VERSION 5.8 ;
BUSBITCHARS "[]" ;
DIVIDERCHAR "/" ;
UNITS
    DATABASE MICRONS 1000 ;
END UNITS

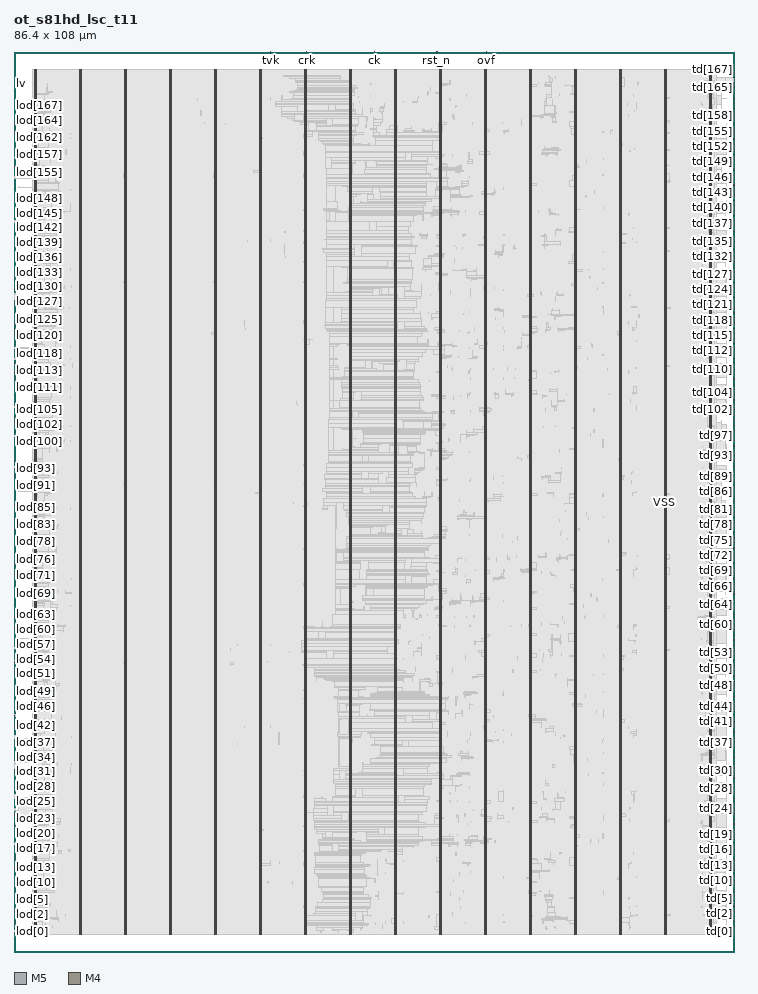
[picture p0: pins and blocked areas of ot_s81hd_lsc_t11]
MACRO ot_s81hd_lsc_t11
  FOREIGN ot_s81hd_lsc_t11 0 0 ;
  CLASS BLOCK ;
  SIZE 86.4 BY 108 ;
  PIN ck
    DIRECTION INPUT ;
    USE SIGNAL ;
    PORT
      LAYER M5 ;
        RECT  43.2 107.916 43.224 108 ;
    END
  END ck
  PIN crk
    DIRECTION INPUT ;
    USE SIGNAL ;
    PORT
      LAYER M5 ;
        RECT  35.088 107.916 35.112 108 ;
    END
  END crk
  PIN lod[0]
    DIRECTION OUTPUT ;
    USE SIGNAL ;
    PORT
      LAYER M4 ;
        RECT  0 2.448 0.084 2.472 ;
    END
  END lod[0]
  PIN lod[100]
    DIRECTION OUTPUT ;
    USE SIGNAL ;
    PORT
      LAYER M4 ;
        RECT  0 61.248 0.084 61.272 ;
    END
  END lod[100]
  PIN lod[101]
    DIRECTION OUTPUT ;
    USE SIGNAL ;
    PORT
      LAYER M4 ;
        RECT  0 61.824 0.084 61.848 ;
    END
  END lod[101]
  PIN lod[102]
    DIRECTION OUTPUT ;
    USE SIGNAL ;
    PORT
      LAYER M4 ;
        RECT  0 62.4 0.084 62.424 ;
    END
  END lod[102]
  PIN lod[103]
    DIRECTION OUTPUT ;
    USE SIGNAL ;
    PORT
      LAYER M4 ;
        RECT  0 62.976 0.084 63 ;
    END
  END lod[103]
  PIN lod[104]
    DIRECTION OUTPUT ;
    USE SIGNAL ;
    PORT
      LAYER M4 ;
        RECT  0 63.6 0.084 63.624 ;
    END
  END lod[104]
  PIN lod[105]
    DIRECTION OUTPUT ;
    USE SIGNAL ;
    PORT
      LAYER M4 ;
        RECT  0 64.176 0.084 64.2 ;
    END
  END lod[105]
  PIN lod[106]
    DIRECTION OUTPUT ;
    USE SIGNAL ;
    PORT
      LAYER M4 ;
        RECT  0 64.752 0.084 64.776 ;
    END
  END lod[106]
  PIN lod[107]
    DIRECTION OUTPUT ;
    USE SIGNAL ;
    PORT
      LAYER M4 ;
        RECT  0 65.328 0.084 65.352 ;
    END
  END lod[107]
  PIN lod[108]
    DIRECTION OUTPUT ;
    USE SIGNAL ;
    PORT
      LAYER M4 ;
        RECT  0 65.952 0.084 65.976 ;
    END
  END lod[108]
  PIN lod[109]
    DIRECTION OUTPUT ;
    USE SIGNAL ;
    PORT
      LAYER M4 ;
        RECT  0 66.528 0.084 66.552 ;
    END
  END lod[109]
  PIN lod[10]
    DIRECTION OUTPUT ;
    USE SIGNAL ;
    PORT
      LAYER M4 ;
        RECT  0 8.304 0.084 8.328 ;
    END
  END lod[10]
  PIN lod[110]
    DIRECTION OUTPUT ;
    USE SIGNAL ;
    PORT
      LAYER M4 ;
        RECT  0 67.104 0.084 67.128 ;
    END
  END lod[110]
  PIN lod[111]
    DIRECTION OUTPUT ;
    USE SIGNAL ;
    PORT
      LAYER M4 ;
        RECT  0 67.68 0.084 67.704 ;
    END
  END lod[111]
  PIN lod[112]
    DIRECTION OUTPUT ;
    USE SIGNAL ;
    PORT
      LAYER M4 ;
        RECT  0 68.304 0.084 68.328 ;
    END
  END lod[112]
  PIN lod[113]
    DIRECTION OUTPUT ;
    USE SIGNAL ;
    PORT
      LAYER M4 ;
        RECT  0 68.88 0.084 68.904 ;
    END
  END lod[113]
  PIN lod[114]
    DIRECTION OUTPUT ;
    USE SIGNAL ;
    PORT
      LAYER M4 ;
        RECT  0 69.456 0.084 69.48 ;
    END
  END lod[114]
  PIN lod[115]
    DIRECTION OUTPUT ;
    USE SIGNAL ;
    PORT
      LAYER M4 ;
        RECT  0 70.032 0.084 70.056 ;
    END
  END lod[115]
  PIN lod[116]
    DIRECTION OUTPUT ;
    USE SIGNAL ;
    PORT
      LAYER M4 ;
        RECT  0 70.656 0.084 70.68 ;
    END
  END lod[116]
  PIN lod[117]
    DIRECTION OUTPUT ;
    USE SIGNAL ;
    PORT
      LAYER M4 ;
        RECT  0 71.232 0.084 71.256 ;
    END
  END lod[117]
  PIN lod[118]
    DIRECTION OUTPUT ;
    USE SIGNAL ;
    PORT
      LAYER M4 ;
        RECT  0 71.808 0.084 71.832 ;
    END
  END lod[118]
  PIN lod[119]
    DIRECTION OUTPUT ;
    USE SIGNAL ;
    PORT
      LAYER M4 ;
        RECT  0 72.384 0.084 72.408 ;
    END
  END lod[119]
  PIN lod[11]
    DIRECTION OUTPUT ;
    USE SIGNAL ;
    PORT
      LAYER M4 ;
        RECT  0 8.928 0.084 8.952 ;
    END
  END lod[11]
  PIN lod[120]
    DIRECTION OUTPUT ;
    USE SIGNAL ;
    PORT
      LAYER M4 ;
        RECT  0 73.008 0.084 73.032 ;
    END
  END lod[120]
  PIN lod[121]
    DIRECTION OUTPUT ;
    USE SIGNAL ;
    PORT
      LAYER M4 ;
        RECT  0 73.584 0.084 73.608 ;
    END
  END lod[121]
  PIN lod[122]
    DIRECTION OUTPUT ;
    USE SIGNAL ;
    PORT
      LAYER M4 ;
        RECT  0 74.16 0.084 74.184 ;
    END
  END lod[122]
  PIN lod[123]
    DIRECTION OUTPUT ;
    USE SIGNAL ;
    PORT
      LAYER M4 ;
        RECT  0 74.736 0.084 74.76 ;
    END
  END lod[123]
  PIN lod[124]
    DIRECTION OUTPUT ;
    USE SIGNAL ;
    PORT
      LAYER M4 ;
        RECT  0 75.36 0.084 75.384 ;
    END
  END lod[124]
  PIN lod[125]
    DIRECTION OUTPUT ;
    USE SIGNAL ;
    PORT
      LAYER M4 ;
        RECT  0 75.936 0.084 75.96 ;
    END
  END lod[125]
  PIN lod[126]
    DIRECTION OUTPUT ;
    USE SIGNAL ;
    PORT
      LAYER M4 ;
        RECT  0 76.512 0.084 76.536 ;
    END
  END lod[126]
  PIN lod[127]
    DIRECTION OUTPUT ;
    USE SIGNAL ;
    PORT
      LAYER M4 ;
        RECT  0 77.088 0.084 77.112 ;
    END
  END lod[127]
  PIN lod[128]
    DIRECTION OUTPUT ;
    USE SIGNAL ;
    PORT
      LAYER M4 ;
        RECT  0 77.712 0.084 77.736 ;
    END
  END lod[128]
  PIN lod[129]
    DIRECTION OUTPUT ;
    USE SIGNAL ;
    PORT
      LAYER M4 ;
        RECT  0 78.288 0.084 78.312 ;
    END
  END lod[129]
  PIN lod[12]
    DIRECTION OUTPUT ;
    USE SIGNAL ;
    PORT
      LAYER M4 ;
        RECT  0 9.504 0.084 9.528 ;
    END
  END lod[12]
  PIN lod[130]
    DIRECTION OUTPUT ;
    USE SIGNAL ;
    PORT
      LAYER M4 ;
        RECT  0 78.864 0.084 78.888 ;
    END
  END lod[130]
  PIN lod[131]
    DIRECTION OUTPUT ;
    USE SIGNAL ;
    PORT
      LAYER M4 ;
        RECT  0 79.44 0.084 79.464 ;
    END
  END lod[131]
  PIN lod[132]
    DIRECTION OUTPUT ;
    USE SIGNAL ;
    PORT
      LAYER M4 ;
        RECT  0 80.064 0.084 80.088 ;
    END
  END lod[132]
  PIN lod[133]
    DIRECTION OUTPUT ;
    USE SIGNAL ;
    PORT
      LAYER M4 ;
        RECT  0 80.64 0.084 80.664 ;
    END
  END lod[133]
  PIN lod[134]
    DIRECTION OUTPUT ;
    USE SIGNAL ;
    PORT
      LAYER M4 ;
        RECT  0 81.216 0.084 81.24 ;
    END
  END lod[134]
  PIN lod[135]
    DIRECTION OUTPUT ;
    USE SIGNAL ;
    PORT
      LAYER M4 ;
        RECT  0 81.792 0.084 81.816 ;
    END
  END lod[135]
  PIN lod[136]
    DIRECTION OUTPUT ;
    USE SIGNAL ;
    PORT
      LAYER M4 ;
        RECT  0 82.416 0.084 82.44 ;
    END
  END lod[136]
  PIN lod[137]
    DIRECTION OUTPUT ;
    USE SIGNAL ;
    PORT
      LAYER M4 ;
        RECT  0 82.992 0.084 83.016 ;
    END
  END lod[137]
  PIN lod[138]
    DIRECTION OUTPUT ;
    USE SIGNAL ;
    PORT
      LAYER M4 ;
        RECT  0 83.568 0.084 83.592 ;
    END
  END lod[138]
  PIN lod[139]
    DIRECTION OUTPUT ;
    USE SIGNAL ;
    PORT
      LAYER M4 ;
        RECT  0 84.144 0.084 84.168 ;
    END
  END lod[139]
  PIN lod[13]
    DIRECTION OUTPUT ;
    USE SIGNAL ;
    PORT
      LAYER M4 ;
        RECT  0 10.08 0.084 10.104 ;
    END
  END lod[13]
  PIN lod[140]
    DIRECTION OUTPUT ;
    USE SIGNAL ;
    PORT
      LAYER M4 ;
        RECT  0 84.768 0.084 84.792 ;
    END
  END lod[140]
  PIN lod[141]
    DIRECTION OUTPUT ;
    USE SIGNAL ;
    PORT
      LAYER M4 ;
        RECT  0 85.344 0.084 85.368 ;
    END
  END lod[141]
  PIN lod[142]
    DIRECTION OUTPUT ;
    USE SIGNAL ;
    PORT
      LAYER M4 ;
        RECT  0 85.92 0.084 85.944 ;
    END
  END lod[142]
  PIN lod[143]
    DIRECTION OUTPUT ;
    USE SIGNAL ;
    PORT
      LAYER M4 ;
        RECT  0 86.496 0.084 86.52 ;
    END
  END lod[143]
  PIN lod[144]
    DIRECTION OUTPUT ;
    USE SIGNAL ;
    PORT
      LAYER M4 ;
        RECT  0 87.12 0.084 87.144 ;
    END
  END lod[144]
  PIN lod[145]
    DIRECTION OUTPUT ;
    USE SIGNAL ;
    PORT
      LAYER M4 ;
        RECT  0 87.696 0.084 87.72 ;
    END
  END lod[145]
  PIN lod[146]
    DIRECTION OUTPUT ;
    USE SIGNAL ;
    PORT
      LAYER M4 ;
        RECT  0 88.272 0.084 88.296 ;
    END
  END lod[146]
  PIN lod[147]
    DIRECTION OUTPUT ;
    USE SIGNAL ;
    PORT
      LAYER M4 ;
        RECT  0 88.848 0.084 88.872 ;
    END
  END lod[147]
  PIN lod[148]
    DIRECTION OUTPUT ;
    USE SIGNAL ;
    PORT
      LAYER M4 ;
        RECT  0 89.472 0.084 89.496 ;
    END
  END lod[148]
  PIN lod[149]
    DIRECTION OUTPUT ;
    USE SIGNAL ;
    PORT
      LAYER M4 ;
        RECT  0 90.048 0.084 90.072 ;
    END
  END lod[149]
  PIN lod[14]
    DIRECTION OUTPUT ;
    USE SIGNAL ;
    PORT
      LAYER M4 ;
        RECT  0 10.656 0.084 10.68 ;
    END
  END lod[14]
  PIN lod[150]
    DIRECTION OUTPUT ;
    USE SIGNAL ;
    PORT
      LAYER M4 ;
        RECT  0 90.624 0.084 90.648 ;
    END
  END lod[150]
  PIN lod[151]
    DIRECTION OUTPUT ;
    USE SIGNAL ;
    PORT
      LAYER M4 ;
        RECT  0 91.2 0.084 91.224 ;
    END
  END lod[151]
  PIN lod[152]
    DIRECTION OUTPUT ;
    USE SIGNAL ;
    PORT
      LAYER M4 ;
        RECT  0 91.824 0.084 91.848 ;
    END
  END lod[152]
  PIN lod[153]
    DIRECTION OUTPUT ;
    USE SIGNAL ;
    PORT
      LAYER M4 ;
        RECT  0 92.4 0.084 92.424 ;
    END
  END lod[153]
  PIN lod[154]
    DIRECTION OUTPUT ;
    USE SIGNAL ;
    PORT
      LAYER M4 ;
        RECT  0 92.976 0.084 93 ;
    END
  END lod[154]
  PIN lod[155]
    DIRECTION OUTPUT ;
    USE SIGNAL ;
    PORT
      LAYER M4 ;
        RECT  0 93.552 0.084 93.576 ;
    END
  END lod[155]
  PIN lod[156]
    DIRECTION OUTPUT ;
    USE SIGNAL ;
    PORT
      LAYER M4 ;
        RECT  0 94.176 0.084 94.2 ;
    END
  END lod[156]
  PIN lod[157]
    DIRECTION OUTPUT ;
    USE SIGNAL ;
    PORT
      LAYER M4 ;
        RECT  0 94.752 0.084 94.776 ;
    END
  END lod[157]
  PIN lod[158]
    DIRECTION OUTPUT ;
    USE SIGNAL ;
    PORT
      LAYER M4 ;
        RECT  0 95.328 0.084 95.352 ;
    END
  END lod[158]
  PIN lod[159]
    DIRECTION OUTPUT ;
    USE SIGNAL ;
    PORT
      LAYER M4 ;
        RECT  0 95.904 0.084 95.928 ;
    END
  END lod[159]
  PIN lod[15]
    DIRECTION OUTPUT ;
    USE SIGNAL ;
    PORT
      LAYER M4 ;
        RECT  0 11.28 0.084 11.304 ;
    END
  END lod[15]
  PIN lod[160]
    DIRECTION OUTPUT ;
    USE SIGNAL ;
    PORT
      LAYER M4 ;
        RECT  0 96.528 0.084 96.552 ;
    END
  END lod[160]
  PIN lod[161]
    DIRECTION OUTPUT ;
    USE SIGNAL ;
    PORT
      LAYER M4 ;
        RECT  0 97.104 0.084 97.128 ;
    END
  END lod[161]
  PIN lod[162]
    DIRECTION OUTPUT ;
    USE SIGNAL ;
    PORT
      LAYER M4 ;
        RECT  0 97.68 0.084 97.704 ;
    END
  END lod[162]
  PIN lod[163]
    DIRECTION OUTPUT ;
    USE SIGNAL ;
    PORT
      LAYER M4 ;
        RECT  0 98.256 0.084 98.28 ;
    END
  END lod[163]
  PIN lod[164]
    DIRECTION OUTPUT ;
    USE SIGNAL ;
    PORT
      LAYER M4 ;
        RECT  0 98.88 0.084 98.904 ;
    END
  END lod[164]
  PIN lod[165]
    DIRECTION OUTPUT ;
    USE SIGNAL ;
    PORT
      LAYER M4 ;
        RECT  0 99.456 0.084 99.48 ;
    END
  END lod[165]
  PIN lod[166]
    DIRECTION OUTPUT ;
    USE SIGNAL ;
    PORT
      LAYER M4 ;
        RECT  0 100.032 0.084 100.056 ;
    END
  END lod[166]
  PIN lod[167]
    DIRECTION OUTPUT ;
    USE SIGNAL ;
    PORT
      LAYER M4 ;
        RECT  0 100.608 0.084 100.632 ;
    END
  END lod[167]
  PIN lod[168]
    DIRECTION OUTPUT ;
    USE SIGNAL ;
    PORT
      LAYER M4 ;
        RECT  0 101.232 0.084 101.256 ;
    END
  END lod[168]
  PIN lod[16]
    DIRECTION OUTPUT ;
    USE SIGNAL ;
    PORT
      LAYER M4 ;
        RECT  0 11.856 0.084 11.88 ;
    END
  END lod[16]
  PIN lod[17]
    DIRECTION OUTPUT ;
    USE SIGNAL ;
    PORT
      LAYER M4 ;
        RECT  0 12.432 0.084 12.456 ;
    END
  END lod[17]
  PIN lod[18]
    DIRECTION OUTPUT ;
    USE SIGNAL ;
    PORT
      LAYER M4 ;
        RECT  0 13.008 0.084 13.032 ;
    END
  END lod[18]
  PIN lod[19]
    DIRECTION OUTPUT ;
    USE SIGNAL ;
    PORT
      LAYER M4 ;
        RECT  0 13.632 0.084 13.656 ;
    END
  END lod[19]
  PIN lod[1]
    DIRECTION OUTPUT ;
    USE SIGNAL ;
    PORT
      LAYER M4 ;
        RECT  0 3.024 0.084 3.048 ;
    END
  END lod[1]
  PIN lod[20]
    DIRECTION OUTPUT ;
    USE SIGNAL ;
    PORT
      LAYER M4 ;
        RECT  0 14.208 0.084 14.232 ;
    END
  END lod[20]
  PIN lod[21]
    DIRECTION OUTPUT ;
    USE SIGNAL ;
    PORT
      LAYER M4 ;
        RECT  0 14.784 0.084 14.808 ;
    END
  END lod[21]
  PIN lod[22]
    DIRECTION OUTPUT ;
    USE SIGNAL ;
    PORT
      LAYER M4 ;
        RECT  0 15.36 0.084 15.384 ;
    END
  END lod[22]
  PIN lod[23]
    DIRECTION OUTPUT ;
    USE SIGNAL ;
    PORT
      LAYER M4 ;
        RECT  0 15.984 0.084 16.008 ;
    END
  END lod[23]
  PIN lod[24]
    DIRECTION OUTPUT ;
    USE SIGNAL ;
    PORT
      LAYER M4 ;
        RECT  0 16.56 0.084 16.584 ;
    END
  END lod[24]
  PIN lod[25]
    DIRECTION OUTPUT ;
    USE SIGNAL ;
    PORT
      LAYER M4 ;
        RECT  0 17.136 0.084 17.16 ;
    END
  END lod[25]
  PIN lod[26]
    DIRECTION OUTPUT ;
    USE SIGNAL ;
    PORT
      LAYER M4 ;
        RECT  0 17.712 0.084 17.736 ;
    END
  END lod[26]
  PIN lod[27]
    DIRECTION OUTPUT ;
    USE SIGNAL ;
    PORT
      LAYER M4 ;
        RECT  0 18.336 0.084 18.36 ;
    END
  END lod[27]
  PIN lod[28]
    DIRECTION OUTPUT ;
    USE SIGNAL ;
    PORT
      LAYER M4 ;
        RECT  0 18.912 0.084 18.936 ;
    END
  END lod[28]
  PIN lod[29]
    DIRECTION OUTPUT ;
    USE SIGNAL ;
    PORT
      LAYER M4 ;
        RECT  0 19.488 0.084 19.512 ;
    END
  END lod[29]
  PIN lod[2]
    DIRECTION OUTPUT ;
    USE SIGNAL ;
    PORT
      LAYER M4 ;
        RECT  0 3.6 0.084 3.624 ;
    END
  END lod[2]
  PIN lod[30]
    DIRECTION OUTPUT ;
    USE SIGNAL ;
    PORT
      LAYER M4 ;
        RECT  0 20.064 0.084 20.088 ;
    END
  END lod[30]
  PIN lod[31]
    DIRECTION OUTPUT ;
    USE SIGNAL ;
    PORT
      LAYER M4 ;
        RECT  0 20.688 0.084 20.712 ;
    END
  END lod[31]
  PIN lod[32]
    DIRECTION OUTPUT ;
    USE SIGNAL ;
    PORT
      LAYER M4 ;
        RECT  0 21.264 0.084 21.288 ;
    END
  END lod[32]
  PIN lod[33]
    DIRECTION OUTPUT ;
    USE SIGNAL ;
    PORT
      LAYER M4 ;
        RECT  0 21.84 0.084 21.864 ;
    END
  END lod[33]
  PIN lod[34]
    DIRECTION OUTPUT ;
    USE SIGNAL ;
    PORT
      LAYER M4 ;
        RECT  0 22.416 0.084 22.44 ;
    END
  END lod[34]
  PIN lod[35]
    DIRECTION OUTPUT ;
    USE SIGNAL ;
    PORT
      LAYER M4 ;
        RECT  0 23.04 0.084 23.064 ;
    END
  END lod[35]
  PIN lod[36]
    DIRECTION OUTPUT ;
    USE SIGNAL ;
    PORT
      LAYER M4 ;
        RECT  0 23.616 0.084 23.64 ;
    END
  END lod[36]
  PIN lod[37]
    DIRECTION OUTPUT ;
    USE SIGNAL ;
    PORT
      LAYER M4 ;
        RECT  0 24.192 0.084 24.216 ;
    END
  END lod[37]
  PIN lod[38]
    DIRECTION OUTPUT ;
    USE SIGNAL ;
    PORT
      LAYER M4 ;
        RECT  0 24.768 0.084 24.792 ;
    END
  END lod[38]
  PIN lod[39]
    DIRECTION OUTPUT ;
    USE SIGNAL ;
    PORT
      LAYER M4 ;
        RECT  0 25.392 0.084 25.416 ;
    END
  END lod[39]
  PIN lod[3]
    DIRECTION OUTPUT ;
    USE SIGNAL ;
    PORT
      LAYER M4 ;
        RECT  0 4.224 0.084 4.248 ;
    END
  END lod[3]
  PIN lod[40]
    DIRECTION OUTPUT ;
    USE SIGNAL ;
    PORT
      LAYER M4 ;
        RECT  0 25.968 0.084 25.992 ;
    END
  END lod[40]
  PIN lod[41]
    DIRECTION OUTPUT ;
    USE SIGNAL ;
    PORT
      LAYER M4 ;
        RECT  0 26.544 0.084 26.568 ;
    END
  END lod[41]
  PIN lod[42]
    DIRECTION OUTPUT ;
    USE SIGNAL ;
    PORT
      LAYER M4 ;
        RECT  0 27.12 0.084 27.144 ;
    END
  END lod[42]
  PIN lod[43]
    DIRECTION OUTPUT ;
    USE SIGNAL ;
    PORT
      LAYER M4 ;
        RECT  0 27.744 0.084 27.768 ;
    END
  END lod[43]
  PIN lod[44]
    DIRECTION OUTPUT ;
    USE SIGNAL ;
    PORT
      LAYER M4 ;
        RECT  0 28.32 0.084 28.344 ;
    END
  END lod[44]
  PIN lod[45]
    DIRECTION OUTPUT ;
    USE SIGNAL ;
    PORT
      LAYER M4 ;
        RECT  0 28.896 0.084 28.92 ;
    END
  END lod[45]
  PIN lod[46]
    DIRECTION OUTPUT ;
    USE SIGNAL ;
    PORT
      LAYER M4 ;
        RECT  0 29.472 0.084 29.496 ;
    END
  END lod[46]
  PIN lod[47]
    DIRECTION OUTPUT ;
    USE SIGNAL ;
    PORT
      LAYER M4 ;
        RECT  0 30.096 0.084 30.12 ;
    END
  END lod[47]
  PIN lod[48]
    DIRECTION OUTPUT ;
    USE SIGNAL ;
    PORT
      LAYER M4 ;
        RECT  0 30.672 0.084 30.696 ;
    END
  END lod[48]
  PIN lod[49]
    DIRECTION OUTPUT ;
    USE SIGNAL ;
    PORT
      LAYER M4 ;
        RECT  0 31.248 0.084 31.272 ;
    END
  END lod[49]
  PIN lod[4]
    DIRECTION OUTPUT ;
    USE SIGNAL ;
    PORT
      LAYER M4 ;
        RECT  0 4.8 0.084 4.824 ;
    END
  END lod[4]
  PIN lod[50]
    DIRECTION OUTPUT ;
    USE SIGNAL ;
    PORT
      LAYER M4 ;
        RECT  0 31.824 0.084 31.848 ;
    END
  END lod[50]
  PIN lod[51]
    DIRECTION OUTPUT ;
    USE SIGNAL ;
    PORT
      LAYER M4 ;
        RECT  0 32.448 0.084 32.472 ;
    END
  END lod[51]
  PIN lod[52]
    DIRECTION OUTPUT ;
    USE SIGNAL ;
    PORT
      LAYER M4 ;
        RECT  0 33.024 0.084 33.048 ;
    END
  END lod[52]
  PIN lod[53]
    DIRECTION OUTPUT ;
    USE SIGNAL ;
    PORT
      LAYER M4 ;
        RECT  0 33.6 0.084 33.624 ;
    END
  END lod[53]
  PIN lod[54]
    DIRECTION OUTPUT ;
    USE SIGNAL ;
    PORT
      LAYER M4 ;
        RECT  0 34.176 0.084 34.2 ;
    END
  END lod[54]
  PIN lod[55]
    DIRECTION OUTPUT ;
    USE SIGNAL ;
    PORT
      LAYER M4 ;
        RECT  0 34.8 0.084 34.824 ;
    END
  END lod[55]
  PIN lod[56]
    DIRECTION OUTPUT ;
    USE SIGNAL ;
    PORT
      LAYER M4 ;
        RECT  0 35.376 0.084 35.4 ;
    END
  END lod[56]
  PIN lod[57]
    DIRECTION OUTPUT ;
    USE SIGNAL ;
    PORT
      LAYER M4 ;
        RECT  0 35.952 0.084 35.976 ;
    END
  END lod[57]
  PIN lod[58]
    DIRECTION OUTPUT ;
    USE SIGNAL ;
    PORT
      LAYER M4 ;
        RECT  0 36.528 0.084 36.552 ;
    END
  END lod[58]
  PIN lod[59]
    DIRECTION OUTPUT ;
    USE SIGNAL ;
    PORT
      LAYER M4 ;
        RECT  0 37.152 0.084 37.176 ;
    END
  END lod[59]
  PIN lod[5]
    DIRECTION OUTPUT ;
    USE SIGNAL ;
    PORT
      LAYER M4 ;
        RECT  0 5.376 0.084 5.4 ;
    END
  END lod[5]
  PIN lod[60]
    DIRECTION OUTPUT ;
    USE SIGNAL ;
    PORT
      LAYER M4 ;
        RECT  0 37.728 0.084 37.752 ;
    END
  END lod[60]
  PIN lod[61]
    DIRECTION OUTPUT ;
    USE SIGNAL ;
    PORT
      LAYER M4 ;
        RECT  0 38.304 0.084 38.328 ;
    END
  END lod[61]
  PIN lod[62]
    DIRECTION OUTPUT ;
    USE SIGNAL ;
    PORT
      LAYER M4 ;
        RECT  0 38.88 0.084 38.904 ;
    END
  END lod[62]
  PIN lod[63]
    DIRECTION OUTPUT ;
    USE SIGNAL ;
    PORT
      LAYER M4 ;
        RECT  0 39.504 0.084 39.528 ;
    END
  END lod[63]
  PIN lod[64]
    DIRECTION OUTPUT ;
    USE SIGNAL ;
    PORT
      LAYER M4 ;
        RECT  0 40.08 0.084 40.104 ;
    END
  END lod[64]
  PIN lod[65]
    DIRECTION OUTPUT ;
    USE SIGNAL ;
    PORT
      LAYER M4 ;
        RECT  0 40.656 0.084 40.68 ;
    END
  END lod[65]
  PIN lod[66]
    DIRECTION OUTPUT ;
    USE SIGNAL ;
    PORT
      LAYER M4 ;
        RECT  0 41.232 0.084 41.256 ;
    END
  END lod[66]
  PIN lod[67]
    DIRECTION OUTPUT ;
    USE SIGNAL ;
    PORT
      LAYER M4 ;
        RECT  0 41.856 0.084 41.88 ;
    END
  END lod[67]
  PIN lod[68]
    DIRECTION OUTPUT ;
    USE SIGNAL ;
    PORT
      LAYER M4 ;
        RECT  0 42.432 0.084 42.456 ;
    END
  END lod[68]
  PIN lod[69]
    DIRECTION OUTPUT ;
    USE SIGNAL ;
    PORT
      LAYER M4 ;
        RECT  0 43.008 0.084 43.032 ;
    END
  END lod[69]
  PIN lod[6]
    DIRECTION OUTPUT ;
    USE SIGNAL ;
    PORT
      LAYER M4 ;
        RECT  0 5.952 0.084 5.976 ;
    END
  END lod[6]
  PIN lod[70]
    DIRECTION OUTPUT ;
    USE SIGNAL ;
    PORT
      LAYER M4 ;
        RECT  0 43.584 0.084 43.608 ;
    END
  END lod[70]
  PIN lod[71]
    DIRECTION OUTPUT ;
    USE SIGNAL ;
    PORT
      LAYER M4 ;
        RECT  0 44.208 0.084 44.232 ;
    END
  END lod[71]
  PIN lod[72]
    DIRECTION OUTPUT ;
    USE SIGNAL ;
    PORT
      LAYER M4 ;
        RECT  0 44.784 0.084 44.808 ;
    END
  END lod[72]
  PIN lod[73]
    DIRECTION OUTPUT ;
    USE SIGNAL ;
    PORT
      LAYER M4 ;
        RECT  0 45.36 0.084 45.384 ;
    END
  END lod[73]
  PIN lod[74]
    DIRECTION OUTPUT ;
    USE SIGNAL ;
    PORT
      LAYER M4 ;
        RECT  0 45.936 0.084 45.96 ;
    END
  END lod[74]
  PIN lod[75]
    DIRECTION OUTPUT ;
    USE SIGNAL ;
    PORT
      LAYER M4 ;
        RECT  0 46.56 0.084 46.584 ;
    END
  END lod[75]
  PIN lod[76]
    DIRECTION OUTPUT ;
    USE SIGNAL ;
    PORT
      LAYER M4 ;
        RECT  0 47.136 0.084 47.16 ;
    END
  END lod[76]
  PIN lod[77]
    DIRECTION OUTPUT ;
    USE SIGNAL ;
    PORT
      LAYER M4 ;
        RECT  0 47.712 0.084 47.736 ;
    END
  END lod[77]
  PIN lod[78]
    DIRECTION OUTPUT ;
    USE SIGNAL ;
    PORT
      LAYER M4 ;
        RECT  0 48.288 0.084 48.312 ;
    END
  END lod[78]
  PIN lod[79]
    DIRECTION OUTPUT ;
    USE SIGNAL ;
    PORT
      LAYER M4 ;
        RECT  0 48.912 0.084 48.936 ;
    END
  END lod[79]
  PIN lod[7]
    DIRECTION OUTPUT ;
    USE SIGNAL ;
    PORT
      LAYER M4 ;
        RECT  0 6.576 0.084 6.6 ;
    END
  END lod[7]
  PIN lod[80]
    DIRECTION OUTPUT ;
    USE SIGNAL ;
    PORT
      LAYER M4 ;
        RECT  0 49.488 0.084 49.512 ;
    END
  END lod[80]
  PIN lod[81]
    DIRECTION OUTPUT ;
    USE SIGNAL ;
    PORT
      LAYER M4 ;
        RECT  0 50.064 0.084 50.088 ;
    END
  END lod[81]
  PIN lod[82]
    DIRECTION OUTPUT ;
    USE SIGNAL ;
    PORT
      LAYER M4 ;
        RECT  0 50.64 0.084 50.664 ;
    END
  END lod[82]
  PIN lod[83]
    DIRECTION OUTPUT ;
    USE SIGNAL ;
    PORT
      LAYER M4 ;
        RECT  0 51.264 0.084 51.288 ;
    END
  END lod[83]
  PIN lod[84]
    DIRECTION OUTPUT ;
    USE SIGNAL ;
    PORT
      LAYER M4 ;
        RECT  0 51.84 0.084 51.864 ;
    END
  END lod[84]
  PIN lod[85]
    DIRECTION OUTPUT ;
    USE SIGNAL ;
    PORT
      LAYER M4 ;
        RECT  0 52.416 0.084 52.44 ;
    END
  END lod[85]
  PIN lod[86]
    DIRECTION OUTPUT ;
    USE SIGNAL ;
    PORT
      LAYER M4 ;
        RECT  0 52.992 0.084 53.016 ;
    END
  END lod[86]
  PIN lod[87]
    DIRECTION OUTPUT ;
    USE SIGNAL ;
    PORT
      LAYER M4 ;
        RECT  0 53.616 0.084 53.64 ;
    END
  END lod[87]
  PIN lod[88]
    DIRECTION OUTPUT ;
    USE SIGNAL ;
    PORT
      LAYER M4 ;
        RECT  0 54.192 0.084 54.216 ;
    END
  END lod[88]
  PIN lod[89]
    DIRECTION OUTPUT ;
    USE SIGNAL ;
    PORT
      LAYER M4 ;
        RECT  0 54.768 0.084 54.792 ;
    END
  END lod[89]
  PIN lod[8]
    DIRECTION OUTPUT ;
    USE SIGNAL ;
    PORT
      LAYER M4 ;
        RECT  0 7.152 0.084 7.176 ;
    END
  END lod[8]
  PIN lod[90]
    DIRECTION OUTPUT ;
    USE SIGNAL ;
    PORT
      LAYER M4 ;
        RECT  0 55.344 0.084 55.368 ;
    END
  END lod[90]
  PIN lod[91]
    DIRECTION OUTPUT ;
    USE SIGNAL ;
    PORT
      LAYER M4 ;
        RECT  0 55.968 0.084 55.992 ;
    END
  END lod[91]
  PIN lod[92]
    DIRECTION OUTPUT ;
    USE SIGNAL ;
    PORT
      LAYER M4 ;
        RECT  0 56.544 0.084 56.568 ;
    END
  END lod[92]
  PIN lod[93]
    DIRECTION OUTPUT ;
    USE SIGNAL ;
    PORT
      LAYER M4 ;
        RECT  0 57.12 0.084 57.144 ;
    END
  END lod[93]
  PIN lod[94]
    DIRECTION OUTPUT ;
    USE SIGNAL ;
    PORT
      LAYER M4 ;
        RECT  0 57.696 0.084 57.72 ;
    END
  END lod[94]
  PIN lod[95]
    DIRECTION OUTPUT ;
    USE SIGNAL ;
    PORT
      LAYER M4 ;
        RECT  0 58.272 0.084 58.296 ;
    END
  END lod[95]
  PIN lod[96]
    DIRECTION OUTPUT ;
    USE SIGNAL ;
    PORT
      LAYER M4 ;
        RECT  0 58.896 0.084 58.92 ;
    END
  END lod[96]
  PIN lod[97]
    DIRECTION OUTPUT ;
    USE SIGNAL ;
    PORT
      LAYER M4 ;
        RECT  0 59.472 0.084 59.496 ;
    END
  END lod[97]
  PIN lod[98]
    DIRECTION OUTPUT ;
    USE SIGNAL ;
    PORT
      LAYER M4 ;
        RECT  0 60.048 0.084 60.072 ;
    END
  END lod[98]
  PIN lod[99]
    DIRECTION OUTPUT ;
    USE SIGNAL ;
    PORT
      LAYER M4 ;
        RECT  0 60.624 0.084 60.648 ;
    END
  END lod[99]
  PIN lod[9]
    DIRECTION OUTPUT ;
    USE SIGNAL ;
    PORT
      LAYER M4 ;
        RECT  0 7.728 0.084 7.752 ;
    END
  END lod[9]
  PIN lv
    DIRECTION OUTPUT ;
    USE SIGNAL ;
    PORT
      LAYER M4 ;
        RECT  0 104.208 0.084 104.232 ;
    END
  END lv
  PIN ovf
    DIRECTION OUTPUT ;
    USE SIGNAL ;
    PORT
      LAYER M5 ;
        RECT  56.688 107.916 56.712 108 ;
    END
  END ovf
  PIN rst_n
    DIRECTION INPUT ;
    USE SIGNAL ;
    PORT
      LAYER M5 ;
        RECT  50.736 107.916 50.76 108 ;
    END
  END rst_n
  PIN td[0]
    DIRECTION INPUT ;
    USE SIGNAL ;
    PORT
      LAYER M4 ;
        RECT  86.316 2.448 86.4 2.472 ;
    END
  END td[0]
  PIN td[100]
    DIRECTION INPUT ;
    USE SIGNAL ;
    PORT
      LAYER M4 ;
        RECT  86.316 63.792 86.4 63.816 ;
    END
  END td[100]
  PIN td[101]
    DIRECTION INPUT ;
    USE SIGNAL ;
    PORT
      LAYER M4 ;
        RECT  86.316 64.416 86.4 64.44 ;
    END
  END td[101]
  PIN td[102]
    DIRECTION INPUT ;
    USE SIGNAL ;
    PORT
      LAYER M4 ;
        RECT  86.316 65.04 86.4 65.064 ;
    END
  END td[102]
  PIN td[103]
    DIRECTION INPUT ;
    USE SIGNAL ;
    PORT
      LAYER M4 ;
        RECT  86.316 65.664 86.4 65.688 ;
    END
  END td[103]
  PIN td[104]
    DIRECTION INPUT ;
    USE SIGNAL ;
    PORT
      LAYER M4 ;
        RECT  86.316 66.24 86.4 66.264 ;
    END
  END td[104]
  PIN td[105]
    DIRECTION INPUT ;
    USE SIGNAL ;
    PORT
      LAYER M4 ;
        RECT  86.316 66.864 86.4 66.888 ;
    END
  END td[105]
  PIN td[106]
    DIRECTION INPUT ;
    USE SIGNAL ;
    PORT
      LAYER M4 ;
        RECT  86.316 67.488 86.4 67.512 ;
    END
  END td[106]
  PIN td[107]
    DIRECTION INPUT ;
    USE SIGNAL ;
    PORT
      LAYER M4 ;
        RECT  86.316 68.112 86.4 68.136 ;
    END
  END td[107]
  PIN td[108]
    DIRECTION INPUT ;
    USE SIGNAL ;
    PORT
      LAYER M4 ;
        RECT  86.316 68.736 86.4 68.76 ;
    END
  END td[108]
  PIN td[109]
    DIRECTION INPUT ;
    USE SIGNAL ;
    PORT
      LAYER M4 ;
        RECT  86.316 69.312 86.4 69.336 ;
    END
  END td[109]
  PIN td[10]
    DIRECTION INPUT ;
    USE SIGNAL ;
    PORT
      LAYER M4 ;
        RECT  86.316 8.592 86.4 8.616 ;
    END
  END td[10]
  PIN td[110]
    DIRECTION INPUT ;
    USE SIGNAL ;
    PORT
      LAYER M4 ;
        RECT  86.316 69.936 86.4 69.96 ;
    END
  END td[110]
  PIN td[111]
    DIRECTION INPUT ;
    USE SIGNAL ;
    PORT
      LAYER M4 ;
        RECT  86.316 70.56 86.4 70.584 ;
    END
  END td[111]
  PIN td[112]
    DIRECTION INPUT ;
    USE SIGNAL ;
    PORT
      LAYER M4 ;
        RECT  86.316 71.184 86.4 71.208 ;
    END
  END td[112]
  PIN td[113]
    DIRECTION INPUT ;
    USE SIGNAL ;
    PORT
      LAYER M4 ;
        RECT  86.316 71.76 86.4 71.784 ;
    END
  END td[113]
  PIN td[114]
    DIRECTION INPUT ;
    USE SIGNAL ;
    PORT
      LAYER M4 ;
        RECT  86.316 72.384 86.4 72.408 ;
    END
  END td[114]
  PIN td[115]
    DIRECTION INPUT ;
    USE SIGNAL ;
    PORT
      LAYER M4 ;
        RECT  86.316 73.008 86.4 73.032 ;
    END
  END td[115]
  PIN td[116]
    DIRECTION INPUT ;
    USE SIGNAL ;
    PORT
      LAYER M4 ;
        RECT  86.316 73.632 86.4 73.656 ;
    END
  END td[116]
  PIN td[117]
    DIRECTION INPUT ;
    USE SIGNAL ;
    PORT
      LAYER M4 ;
        RECT  86.316 74.256 86.4 74.28 ;
    END
  END td[117]
  PIN td[118]
    DIRECTION INPUT ;
    USE SIGNAL ;
    PORT
      LAYER M4 ;
        RECT  86.316 74.832 86.4 74.856 ;
    END
  END td[118]
  PIN td[119]
    DIRECTION INPUT ;
    USE SIGNAL ;
    PORT
      LAYER M4 ;
        RECT  86.316 75.456 86.4 75.48 ;
    END
  END td[119]
  PIN td[11]
    DIRECTION INPUT ;
    USE SIGNAL ;
    PORT
      LAYER M4 ;
        RECT  86.316 9.216 86.4 9.24 ;
    END
  END td[11]
  PIN td[120]
    DIRECTION INPUT ;
    USE SIGNAL ;
    PORT
      LAYER M4 ;
        RECT  86.316 76.08 86.4 76.104 ;
    END
  END td[120]
  PIN td[121]
    DIRECTION INPUT ;
    USE SIGNAL ;
    PORT
      LAYER M4 ;
        RECT  86.316 76.704 86.4 76.728 ;
    END
  END td[121]
  PIN td[122]
    DIRECTION INPUT ;
    USE SIGNAL ;
    PORT
      LAYER M4 ;
        RECT  86.316 77.28 86.4 77.304 ;
    END
  END td[122]
  PIN td[123]
    DIRECTION INPUT ;
    USE SIGNAL ;
    PORT
      LAYER M4 ;
        RECT  86.316 77.904 86.4 77.928 ;
    END
  END td[123]
  PIN td[124]
    DIRECTION INPUT ;
    USE SIGNAL ;
    PORT
      LAYER M4 ;
        RECT  86.316 78.528 86.4 78.552 ;
    END
  END td[124]
  PIN td[125]
    DIRECTION INPUT ;
    USE SIGNAL ;
    PORT
      LAYER M4 ;
        RECT  86.316 79.152 86.4 79.176 ;
    END
  END td[125]
  PIN td[126]
    DIRECTION INPUT ;
    USE SIGNAL ;
    PORT
      LAYER M4 ;
        RECT  86.316 79.776 86.4 79.8 ;
    END
  END td[126]
  PIN td[127]
    DIRECTION INPUT ;
    USE SIGNAL ;
    PORT
      LAYER M4 ;
        RECT  86.316 80.352 86.4 80.376 ;
    END
  END td[127]
  PIN td[128]
    DIRECTION INPUT ;
    USE SIGNAL ;
    PORT
      LAYER M4 ;
        RECT  86.316 80.976 86.4 81 ;
    END
  END td[128]
  PIN td[129]
    DIRECTION INPUT ;
    USE SIGNAL ;
    PORT
      LAYER M4 ;
        RECT  86.316 81.6 86.4 81.624 ;
    END
  END td[129]
  PIN td[12]
    DIRECTION INPUT ;
    USE SIGNAL ;
    PORT
      LAYER M4 ;
        RECT  86.316 9.84 86.4 9.864 ;
    END
  END td[12]
  PIN td[130]
    DIRECTION INPUT ;
    USE SIGNAL ;
    PORT
      LAYER M4 ;
        RECT  86.316 82.224 86.4 82.248 ;
    END
  END td[130]
  PIN td[131]
    DIRECTION INPUT ;
    USE SIGNAL ;
    PORT
      LAYER M4 ;
        RECT  86.316 82.8 86.4 82.824 ;
    END
  END td[131]
  PIN td[132]
    DIRECTION INPUT ;
    USE SIGNAL ;
    PORT
      LAYER M4 ;
        RECT  86.316 83.424 86.4 83.448 ;
    END
  END td[132]
  PIN td[133]
    DIRECTION INPUT ;
    USE SIGNAL ;
    PORT
      LAYER M4 ;
        RECT  86.316 84.048 86.4 84.072 ;
    END
  END td[133]
  PIN td[134]
    DIRECTION INPUT ;
    USE SIGNAL ;
    PORT
      LAYER M4 ;
        RECT  86.316 84.672 86.4 84.696 ;
    END
  END td[134]
  PIN td[135]
    DIRECTION INPUT ;
    USE SIGNAL ;
    PORT
      LAYER M4 ;
        RECT  86.316 85.296 86.4 85.32 ;
    END
  END td[135]
  PIN td[136]
    DIRECTION INPUT ;
    USE SIGNAL ;
    PORT
      LAYER M4 ;
        RECT  86.316 85.872 86.4 85.896 ;
    END
  END td[136]
  PIN td[137]
    DIRECTION INPUT ;
    USE SIGNAL ;
    PORT
      LAYER M4 ;
        RECT  86.316 86.496 86.4 86.52 ;
    END
  END td[137]
  PIN td[138]
    DIRECTION INPUT ;
    USE SIGNAL ;
    PORT
      LAYER M4 ;
        RECT  86.316 87.12 86.4 87.144 ;
    END
  END td[138]
  PIN td[139]
    DIRECTION INPUT ;
    USE SIGNAL ;
    PORT
      LAYER M4 ;
        RECT  86.316 87.744 86.4 87.768 ;
    END
  END td[139]
  PIN td[13]
    DIRECTION INPUT ;
    USE SIGNAL ;
    PORT
      LAYER M4 ;
        RECT  86.316 10.416 86.4 10.44 ;
    END
  END td[13]
  PIN td[140]
    DIRECTION INPUT ;
    USE SIGNAL ;
    PORT
      LAYER M4 ;
        RECT  86.316 88.368 86.4 88.392 ;
    END
  END td[140]
  PIN td[141]
    DIRECTION INPUT ;
    USE SIGNAL ;
    PORT
      LAYER M4 ;
        RECT  86.316 88.944 86.4 88.968 ;
    END
  END td[141]
  PIN td[142]
    DIRECTION INPUT ;
    USE SIGNAL ;
    PORT
      LAYER M4 ;
        RECT  86.316 89.568 86.4 89.592 ;
    END
  END td[142]
  PIN td[143]
    DIRECTION INPUT ;
    USE SIGNAL ;
    PORT
      LAYER M4 ;
        RECT  86.316 90.192 86.4 90.216 ;
    END
  END td[143]
  PIN td[144]
    DIRECTION INPUT ;
    USE SIGNAL ;
    PORT
      LAYER M4 ;
        RECT  86.316 90.816 86.4 90.84 ;
    END
  END td[144]
  PIN td[145]
    DIRECTION INPUT ;
    USE SIGNAL ;
    PORT
      LAYER M4 ;
        RECT  86.316 91.392 86.4 91.416 ;
    END
  END td[145]
  PIN td[146]
    DIRECTION INPUT ;
    USE SIGNAL ;
    PORT
      LAYER M4 ;
        RECT  86.316 92.016 86.4 92.04 ;
    END
  END td[146]
  PIN td[147]
    DIRECTION INPUT ;
    USE SIGNAL ;
    PORT
      LAYER M4 ;
        RECT  86.316 92.64 86.4 92.664 ;
    END
  END td[147]
  PIN td[148]
    DIRECTION INPUT ;
    USE SIGNAL ;
    PORT
      LAYER M4 ;
        RECT  86.316 93.264 86.4 93.288 ;
    END
  END td[148]
  PIN td[149]
    DIRECTION INPUT ;
    USE SIGNAL ;
    PORT
      LAYER M4 ;
        RECT  86.316 93.888 86.4 93.912 ;
    END
  END td[149]
  PIN td[14]
    DIRECTION INPUT ;
    USE SIGNAL ;
    PORT
      LAYER M4 ;
        RECT  86.316 11.04 86.4 11.064 ;
    END
  END td[14]
  PIN td[150]
    DIRECTION INPUT ;
    USE SIGNAL ;
    PORT
      LAYER M4 ;
        RECT  86.316 94.464 86.4 94.488 ;
    END
  END td[150]
  PIN td[151]
    DIRECTION INPUT ;
    USE SIGNAL ;
    PORT
      LAYER M4 ;
        RECT  86.316 95.088 86.4 95.112 ;
    END
  END td[151]
  PIN td[152]
    DIRECTION INPUT ;
    USE SIGNAL ;
    PORT
      LAYER M4 ;
        RECT  86.316 95.712 86.4 95.736 ;
    END
  END td[152]
  PIN td[153]
    DIRECTION INPUT ;
    USE SIGNAL ;
    PORT
      LAYER M4 ;
        RECT  86.316 96.336 86.4 96.36 ;
    END
  END td[153]
  PIN td[154]
    DIRECTION INPUT ;
    USE SIGNAL ;
    PORT
      LAYER M4 ;
        RECT  86.316 96.912 86.4 96.936 ;
    END
  END td[154]
  PIN td[155]
    DIRECTION INPUT ;
    USE SIGNAL ;
    PORT
      LAYER M4 ;
        RECT  86.316 97.536 86.4 97.56 ;
    END
  END td[155]
  PIN td[156]
    DIRECTION INPUT ;
    USE SIGNAL ;
    PORT
      LAYER M4 ;
        RECT  86.316 98.16 86.4 98.184 ;
    END
  END td[156]
  PIN td[157]
    DIRECTION INPUT ;
    USE SIGNAL ;
    PORT
      LAYER M4 ;
        RECT  86.316 98.784 86.4 98.808 ;
    END
  END td[157]
  PIN td[158]
    DIRECTION INPUT ;
    USE SIGNAL ;
    PORT
      LAYER M4 ;
        RECT  86.316 99.408 86.4 99.432 ;
    END
  END td[158]
  PIN td[159]
    DIRECTION INPUT ;
    USE SIGNAL ;
    PORT
      LAYER M4 ;
        RECT  86.316 99.984 86.4 100.008 ;
    END
  END td[159]
  PIN td[15]
    DIRECTION INPUT ;
    USE SIGNAL ;
    PORT
      LAYER M4 ;
        RECT  86.316 11.664 86.4 11.688 ;
    END
  END td[15]
  PIN td[160]
    DIRECTION INPUT ;
    USE SIGNAL ;
    PORT
      LAYER M4 ;
        RECT  86.316 100.608 86.4 100.632 ;
    END
  END td[160]
  PIN td[161]
    DIRECTION INPUT ;
    USE SIGNAL ;
    PORT
      LAYER M4 ;
        RECT  86.316 101.232 86.4 101.256 ;
    END
  END td[161]
  PIN td[162]
    DIRECTION INPUT ;
    USE SIGNAL ;
    PORT
      LAYER M4 ;
        RECT  86.316 101.856 86.4 101.88 ;
    END
  END td[162]
  PIN td[163]
    DIRECTION INPUT ;
    USE SIGNAL ;
    PORT
      LAYER M4 ;
        RECT  86.316 102.432 86.4 102.456 ;
    END
  END td[163]
  PIN td[164]
    DIRECTION INPUT ;
    USE SIGNAL ;
    PORT
      LAYER M4 ;
        RECT  86.316 103.056 86.4 103.08 ;
    END
  END td[164]
  PIN td[165]
    DIRECTION INPUT ;
    USE SIGNAL ;
    PORT
      LAYER M4 ;
        RECT  86.316 103.68 86.4 103.704 ;
    END
  END td[165]
  PIN td[166]
    DIRECTION INPUT ;
    USE SIGNAL ;
    PORT
      LAYER M4 ;
        RECT  86.316 104.304 86.4 104.328 ;
    END
  END td[166]
  PIN td[167]
    DIRECTION INPUT ;
    USE SIGNAL ;
    PORT
      LAYER M4 ;
        RECT  86.316 104.928 86.4 104.952 ;
    END
  END td[167]
  PIN td[168]
    DIRECTION INPUT ;
    USE SIGNAL ;
    PORT
      LAYER M4 ;
        RECT  86.316 105.504 86.4 105.528 ;
    END
  END td[168]
  PIN td[16]
    DIRECTION INPUT ;
    USE SIGNAL ;
    PORT
      LAYER M4 ;
        RECT  86.316 12.288 86.4 12.312 ;
    END
  END td[16]
  PIN td[17]
    DIRECTION INPUT ;
    USE SIGNAL ;
    PORT
      LAYER M4 ;
        RECT  86.316 12.864 86.4 12.888 ;
    END
  END td[17]
  PIN td[18]
    DIRECTION INPUT ;
    USE SIGNAL ;
    PORT
      LAYER M4 ;
        RECT  86.316 13.488 86.4 13.512 ;
    END
  END td[18]
  PIN td[19]
    DIRECTION INPUT ;
    USE SIGNAL ;
    PORT
      LAYER M4 ;
        RECT  86.316 14.112 86.4 14.136 ;
    END
  END td[19]
  PIN td[1]
    DIRECTION INPUT ;
    USE SIGNAL ;
    PORT
      LAYER M4 ;
        RECT  86.316 3.072 86.4 3.096 ;
    END
  END td[1]
  PIN td[20]
    DIRECTION INPUT ;
    USE SIGNAL ;
    PORT
      LAYER M4 ;
        RECT  86.316 14.736 86.4 14.76 ;
    END
  END td[20]
  PIN td[21]
    DIRECTION INPUT ;
    USE SIGNAL ;
    PORT
      LAYER M4 ;
        RECT  86.316 15.36 86.4 15.384 ;
    END
  END td[21]
  PIN td[22]
    DIRECTION INPUT ;
    USE SIGNAL ;
    PORT
      LAYER M4 ;
        RECT  86.316 15.936 86.4 15.96 ;
    END
  END td[22]
  PIN td[23]
    DIRECTION INPUT ;
    USE SIGNAL ;
    PORT
      LAYER M4 ;
        RECT  86.316 16.56 86.4 16.584 ;
    END
  END td[23]
  PIN td[24]
    DIRECTION INPUT ;
    USE SIGNAL ;
    PORT
      LAYER M4 ;
        RECT  86.316 17.184 86.4 17.208 ;
    END
  END td[24]
  PIN td[25]
    DIRECTION INPUT ;
    USE SIGNAL ;
    PORT
      LAYER M4 ;
        RECT  86.316 17.808 86.4 17.832 ;
    END
  END td[25]
  PIN td[26]
    DIRECTION INPUT ;
    USE SIGNAL ;
    PORT
      LAYER M4 ;
        RECT  86.316 18.384 86.4 18.408 ;
    END
  END td[26]
  PIN td[27]
    DIRECTION INPUT ;
    USE SIGNAL ;
    PORT
      LAYER M4 ;
        RECT  86.316 19.008 86.4 19.032 ;
    END
  END td[27]
  PIN td[28]
    DIRECTION INPUT ;
    USE SIGNAL ;
    PORT
      LAYER M4 ;
        RECT  86.316 19.632 86.4 19.656 ;
    END
  END td[28]
  PIN td[29]
    DIRECTION INPUT ;
    USE SIGNAL ;
    PORT
      LAYER M4 ;
        RECT  86.316 20.256 86.4 20.28 ;
    END
  END td[29]
  PIN td[2]
    DIRECTION INPUT ;
    USE SIGNAL ;
    PORT
      LAYER M4 ;
        RECT  86.316 3.696 86.4 3.72 ;
    END
  END td[2]
  PIN td[30]
    DIRECTION INPUT ;
    USE SIGNAL ;
    PORT
      LAYER M4 ;
        RECT  86.316 20.88 86.4 20.904 ;
    END
  END td[30]
  PIN td[31]
    DIRECTION INPUT ;
    USE SIGNAL ;
    PORT
      LAYER M4 ;
        RECT  86.316 21.456 86.4 21.48 ;
    END
  END td[31]
  PIN td[32]
    DIRECTION INPUT ;
    USE SIGNAL ;
    PORT
      LAYER M4 ;
        RECT  86.316 22.08 86.4 22.104 ;
    END
  END td[32]
  PIN td[33]
    DIRECTION INPUT ;
    USE SIGNAL ;
    PORT
      LAYER M4 ;
        RECT  86.316 22.704 86.4 22.728 ;
    END
  END td[33]
  PIN td[34]
    DIRECTION INPUT ;
    USE SIGNAL ;
    PORT
      LAYER M4 ;
        RECT  86.316 23.328 86.4 23.352 ;
    END
  END td[34]
  PIN td[35]
    DIRECTION INPUT ;
    USE SIGNAL ;
    PORT
      LAYER M4 ;
        RECT  86.316 23.904 86.4 23.928 ;
    END
  END td[35]
  PIN td[36]
    DIRECTION INPUT ;
    USE SIGNAL ;
    PORT
      LAYER M4 ;
        RECT  86.316 24.528 86.4 24.552 ;
    END
  END td[36]
  PIN td[37]
    DIRECTION INPUT ;
    USE SIGNAL ;
    PORT
      LAYER M4 ;
        RECT  86.316 25.152 86.4 25.176 ;
    END
  END td[37]
  PIN td[38]
    DIRECTION INPUT ;
    USE SIGNAL ;
    PORT
      LAYER M4 ;
        RECT  86.316 25.776 86.4 25.8 ;
    END
  END td[38]
  PIN td[39]
    DIRECTION INPUT ;
    USE SIGNAL ;
    PORT
      LAYER M4 ;
        RECT  86.316 26.4 86.4 26.424 ;
    END
  END td[39]
  PIN td[3]
    DIRECTION INPUT ;
    USE SIGNAL ;
    PORT
      LAYER M4 ;
        RECT  86.316 4.272 86.4 4.296 ;
    END
  END td[3]
  PIN td[40]
    DIRECTION INPUT ;
    USE SIGNAL ;
    PORT
      LAYER M4 ;
        RECT  86.316 26.976 86.4 27 ;
    END
  END td[40]
  PIN td[41]
    DIRECTION INPUT ;
    USE SIGNAL ;
    PORT
      LAYER M4 ;
        RECT  86.316 27.6 86.4 27.624 ;
    END
  END td[41]
  PIN td[42]
    DIRECTION INPUT ;
    USE SIGNAL ;
    PORT
      LAYER M4 ;
        RECT  86.316 28.224 86.4 28.248 ;
    END
  END td[42]
  PIN td[43]
    DIRECTION INPUT ;
    USE SIGNAL ;
    PORT
      LAYER M4 ;
        RECT  86.316 28.848 86.4 28.872 ;
    END
  END td[43]
  PIN td[44]
    DIRECTION INPUT ;
    USE SIGNAL ;
    PORT
      LAYER M4 ;
        RECT  86.316 29.472 86.4 29.496 ;
    END
  END td[44]
  PIN td[45]
    DIRECTION INPUT ;
    USE SIGNAL ;
    PORT
      LAYER M4 ;
        RECT  86.316 30.048 86.4 30.072 ;
    END
  END td[45]
  PIN td[46]
    DIRECTION INPUT ;
    USE SIGNAL ;
    PORT
      LAYER M4 ;
        RECT  86.316 30.672 86.4 30.696 ;
    END
  END td[46]
  PIN td[47]
    DIRECTION INPUT ;
    USE SIGNAL ;
    PORT
      LAYER M4 ;
        RECT  86.316 31.296 86.4 31.32 ;
    END
  END td[47]
  PIN td[48]
    DIRECTION INPUT ;
    USE SIGNAL ;
    PORT
      LAYER M4 ;
        RECT  86.316 31.92 86.4 31.944 ;
    END
  END td[48]
  PIN td[49]
    DIRECTION INPUT ;
    USE SIGNAL ;
    PORT
      LAYER M4 ;
        RECT  86.316 32.496 86.4 32.52 ;
    END
  END td[49]
  PIN td[4]
    DIRECTION INPUT ;
    USE SIGNAL ;
    PORT
      LAYER M4 ;
        RECT  86.316 4.896 86.4 4.92 ;
    END
  END td[4]
  PIN td[50]
    DIRECTION INPUT ;
    USE SIGNAL ;
    PORT
      LAYER M4 ;
        RECT  86.316 33.12 86.4 33.144 ;
    END
  END td[50]
  PIN td[51]
    DIRECTION INPUT ;
    USE SIGNAL ;
    PORT
      LAYER M4 ;
        RECT  86.316 33.744 86.4 33.768 ;
    END
  END td[51]
  PIN td[52]
    DIRECTION INPUT ;
    USE SIGNAL ;
    PORT
      LAYER M4 ;
        RECT  86.316 34.368 86.4 34.392 ;
    END
  END td[52]
  PIN td[53]
    DIRECTION INPUT ;
    USE SIGNAL ;
    PORT
      LAYER M4 ;
        RECT  86.316 34.992 86.4 35.016 ;
    END
  END td[53]
  PIN td[54]
    DIRECTION INPUT ;
    USE SIGNAL ;
    PORT
      LAYER M4 ;
        RECT  86.316 35.568 86.4 35.592 ;
    END
  END td[54]
  PIN td[55]
    DIRECTION INPUT ;
    USE SIGNAL ;
    PORT
      LAYER M4 ;
        RECT  86.316 36.192 86.4 36.216 ;
    END
  END td[55]
  PIN td[56]
    DIRECTION INPUT ;
    USE SIGNAL ;
    PORT
      LAYER M4 ;
        RECT  86.316 36.816 86.4 36.84 ;
    END
  END td[56]
  PIN td[57]
    DIRECTION INPUT ;
    USE SIGNAL ;
    PORT
      LAYER M4 ;
        RECT  86.316 37.44 86.4 37.464 ;
    END
  END td[57]
  PIN td[58]
    DIRECTION INPUT ;
    USE SIGNAL ;
    PORT
      LAYER M4 ;
        RECT  86.316 38.016 86.4 38.04 ;
    END
  END td[58]
  PIN td[59]
    DIRECTION INPUT ;
    USE SIGNAL ;
    PORT
      LAYER M4 ;
        RECT  86.316 38.64 86.4 38.664 ;
    END
  END td[59]
  PIN td[5]
    DIRECTION INPUT ;
    USE SIGNAL ;
    PORT
      LAYER M4 ;
        RECT  86.316 5.52 86.4 5.544 ;
    END
  END td[5]
  PIN td[60]
    DIRECTION INPUT ;
    USE SIGNAL ;
    PORT
      LAYER M4 ;
        RECT  86.316 39.264 86.4 39.288 ;
    END
  END td[60]
  PIN td[61]
    DIRECTION INPUT ;
    USE SIGNAL ;
    PORT
      LAYER M4 ;
        RECT  86.316 39.888 86.4 39.912 ;
    END
  END td[61]
  PIN td[62]
    DIRECTION INPUT ;
    USE SIGNAL ;
    PORT
      LAYER M4 ;
        RECT  86.316 40.512 86.4 40.536 ;
    END
  END td[62]
  PIN td[63]
    DIRECTION INPUT ;
    USE SIGNAL ;
    PORT
      LAYER M4 ;
        RECT  86.316 41.088 86.4 41.112 ;
    END
  END td[63]
  PIN td[64]
    DIRECTION INPUT ;
    USE SIGNAL ;
    PORT
      LAYER M4 ;
        RECT  86.316 41.712 86.4 41.736 ;
    END
  END td[64]
  PIN td[65]
    DIRECTION INPUT ;
    USE SIGNAL ;
    PORT
      LAYER M4 ;
        RECT  86.316 42.336 86.4 42.36 ;
    END
  END td[65]
  PIN td[66]
    DIRECTION INPUT ;
    USE SIGNAL ;
    PORT
      LAYER M4 ;
        RECT  86.316 42.96 86.4 42.984 ;
    END
  END td[66]
  PIN td[67]
    DIRECTION INPUT ;
    USE SIGNAL ;
    PORT
      LAYER M4 ;
        RECT  86.316 43.536 86.4 43.56 ;
    END
  END td[67]
  PIN td[68]
    DIRECTION INPUT ;
    USE SIGNAL ;
    PORT
      LAYER M4 ;
        RECT  86.316 44.16 86.4 44.184 ;
    END
  END td[68]
  PIN td[69]
    DIRECTION INPUT ;
    USE SIGNAL ;
    PORT
      LAYER M4 ;
        RECT  86.316 44.784 86.4 44.808 ;
    END
  END td[69]
  PIN td[6]
    DIRECTION INPUT ;
    USE SIGNAL ;
    PORT
      LAYER M4 ;
        RECT  86.316 6.144 86.4 6.168 ;
    END
  END td[6]
  PIN td[70]
    DIRECTION INPUT ;
    USE SIGNAL ;
    PORT
      LAYER M4 ;
        RECT  86.316 45.408 86.4 45.432 ;
    END
  END td[70]
  PIN td[71]
    DIRECTION INPUT ;
    USE SIGNAL ;
    PORT
      LAYER M4 ;
        RECT  86.316 46.032 86.4 46.056 ;
    END
  END td[71]
  PIN td[72]
    DIRECTION INPUT ;
    USE SIGNAL ;
    PORT
      LAYER M4 ;
        RECT  86.316 46.608 86.4 46.632 ;
    END
  END td[72]
  PIN td[73]
    DIRECTION INPUT ;
    USE SIGNAL ;
    PORT
      LAYER M4 ;
        RECT  86.316 47.232 86.4 47.256 ;
    END
  END td[73]
  PIN td[74]
    DIRECTION INPUT ;
    USE SIGNAL ;
    PORT
      LAYER M4 ;
        RECT  86.316 47.856 86.4 47.88 ;
    END
  END td[74]
  PIN td[75]
    DIRECTION INPUT ;
    USE SIGNAL ;
    PORT
      LAYER M4 ;
        RECT  86.316 48.48 86.4 48.504 ;
    END
  END td[75]
  PIN td[76]
    DIRECTION INPUT ;
    USE SIGNAL ;
    PORT
      LAYER M4 ;
        RECT  86.316 49.104 86.4 49.128 ;
    END
  END td[76]
  PIN td[77]
    DIRECTION INPUT ;
    USE SIGNAL ;
    PORT
      LAYER M4 ;
        RECT  86.316 49.68 86.4 49.704 ;
    END
  END td[77]
  PIN td[78]
    DIRECTION INPUT ;
    USE SIGNAL ;
    PORT
      LAYER M4 ;
        RECT  86.316 50.304 86.4 50.328 ;
    END
  END td[78]
  PIN td[79]
    DIRECTION INPUT ;
    USE SIGNAL ;
    PORT
      LAYER M4 ;
        RECT  86.316 50.928 86.4 50.952 ;
    END
  END td[79]
  PIN td[7]
    DIRECTION INPUT ;
    USE SIGNAL ;
    PORT
      LAYER M4 ;
        RECT  86.316 6.768 86.4 6.792 ;
    END
  END td[7]
  PIN td[80]
    DIRECTION INPUT ;
    USE SIGNAL ;
    PORT
      LAYER M4 ;
        RECT  86.316 51.552 86.4 51.576 ;
    END
  END td[80]
  PIN td[81]
    DIRECTION INPUT ;
    USE SIGNAL ;
    PORT
      LAYER M4 ;
        RECT  86.316 52.128 86.4 52.152 ;
    END
  END td[81]
  PIN td[82]
    DIRECTION INPUT ;
    USE SIGNAL ;
    PORT
      LAYER M4 ;
        RECT  86.316 52.752 86.4 52.776 ;
    END
  END td[82]
  PIN td[83]
    DIRECTION INPUT ;
    USE SIGNAL ;
    PORT
      LAYER M4 ;
        RECT  86.316 53.376 86.4 53.4 ;
    END
  END td[83]
  PIN td[84]
    DIRECTION INPUT ;
    USE SIGNAL ;
    PORT
      LAYER M4 ;
        RECT  86.316 54 86.4 54.024 ;
    END
  END td[84]
  PIN td[85]
    DIRECTION INPUT ;
    USE SIGNAL ;
    PORT
      LAYER M4 ;
        RECT  86.316 54.624 86.4 54.648 ;
    END
  END td[85]
  PIN td[86]
    DIRECTION INPUT ;
    USE SIGNAL ;
    PORT
      LAYER M4 ;
        RECT  86.316 55.2 86.4 55.224 ;
    END
  END td[86]
  PIN td[87]
    DIRECTION INPUT ;
    USE SIGNAL ;
    PORT
      LAYER M4 ;
        RECT  86.316 55.824 86.4 55.848 ;
    END
  END td[87]
  PIN td[88]
    DIRECTION INPUT ;
    USE SIGNAL ;
    PORT
      LAYER M4 ;
        RECT  86.316 56.448 86.4 56.472 ;
    END
  END td[88]
  PIN td[89]
    DIRECTION INPUT ;
    USE SIGNAL ;
    PORT
      LAYER M4 ;
        RECT  86.316 57.072 86.4 57.096 ;
    END
  END td[89]
  PIN td[8]
    DIRECTION INPUT ;
    USE SIGNAL ;
    PORT
      LAYER M4 ;
        RECT  86.316 7.344 86.4 7.368 ;
    END
  END td[8]
  PIN td[90]
    DIRECTION INPUT ;
    USE SIGNAL ;
    PORT
      LAYER M4 ;
        RECT  86.316 57.648 86.4 57.672 ;
    END
  END td[90]
  PIN td[91]
    DIRECTION INPUT ;
    USE SIGNAL ;
    PORT
      LAYER M4 ;
        RECT  86.316 58.272 86.4 58.296 ;
    END
  END td[91]
  PIN td[92]
    DIRECTION INPUT ;
    USE SIGNAL ;
    PORT
      LAYER M4 ;
        RECT  86.316 58.896 86.4 58.92 ;
    END
  END td[92]
  PIN td[93]
    DIRECTION INPUT ;
    USE SIGNAL ;
    PORT
      LAYER M4 ;
        RECT  86.316 59.52 86.4 59.544 ;
    END
  END td[93]
  PIN td[94]
    DIRECTION INPUT ;
    USE SIGNAL ;
    PORT
      LAYER M4 ;
        RECT  86.316 60.144 86.4 60.168 ;
    END
  END td[94]
  PIN td[95]
    DIRECTION INPUT ;
    USE SIGNAL ;
    PORT
      LAYER M4 ;
        RECT  86.316 60.72 86.4 60.744 ;
    END
  END td[95]
  PIN td[96]
    DIRECTION INPUT ;
    USE SIGNAL ;
    PORT
      LAYER M4 ;
        RECT  86.316 61.344 86.4 61.368 ;
    END
  END td[96]
  PIN td[97]
    DIRECTION INPUT ;
    USE SIGNAL ;
    PORT
      LAYER M4 ;
        RECT  86.316 61.968 86.4 61.992 ;
    END
  END td[97]
  PIN td[98]
    DIRECTION INPUT ;
    USE SIGNAL ;
    PORT
      LAYER M4 ;
        RECT  86.316 62.592 86.4 62.616 ;
    END
  END td[98]
  PIN td[99]
    DIRECTION INPUT ;
    USE SIGNAL ;
    PORT
      LAYER M4 ;
        RECT  86.316 63.168 86.4 63.192 ;
    END
  END td[99]
  PIN td[9]
    DIRECTION INPUT ;
    USE SIGNAL ;
    PORT
      LAYER M4 ;
        RECT  86.316 7.968 86.4 7.992 ;
    END
  END td[9]
  PIN tvk
    DIRECTION INPUT ;
    USE SIGNAL ;
    PORT
      LAYER M5 ;
        RECT  30.768 107.916 30.792 108 ;
    END
  END tvk
  PIN VDD
    DIRECTION INOUT ;
    USE POWER ;
    PORT
      LAYER M5 ;
        RECT  83.592 2.151 83.712 105.849 ;
        RECT  78.192 2.151 78.312 105.849 ;
        RECT  72.792 2.151 72.912 105.849 ;
        RECT  67.392 2.151 67.512 105.849 ;
        RECT  61.992 2.151 62.112 105.849 ;
        RECT  56.592 2.151 56.712 105.849 ;
        RECT  51.192 2.151 51.312 105.849 ;
        RECT  45.792 2.151 45.912 105.849 ;
        RECT  40.392 2.151 40.512 105.849 ;
        RECT  34.992 2.151 35.112 105.849 ;
        RECT  29.592 2.151 29.712 105.849 ;
        RECT  24.192 2.151 24.312 105.849 ;
        RECT  18.792 2.151 18.912 105.849 ;
        RECT  13.392 2.151 13.512 105.849 ;
        RECT  7.992 2.151 8.112 105.849 ;
        RECT  2.592 2.151 2.712 105.849 ;
    END
  END VDD
  PIN VSS
    DIRECTION INOUT ;
    USE GROUND ;
    PORT
      LAYER M5 ;
        RECT  83.4 2.137 83.52 105.863 ;
        RECT  78 2.137 78.12 105.863 ;
        RECT  72.6 2.137 72.72 105.863 ;
        RECT  67.2 2.137 67.32 105.863 ;
        RECT  61.8 2.137 61.92 105.863 ;
        RECT  56.4 2.137 56.52 105.863 ;
        RECT  51 2.137 51.12 105.863 ;
        RECT  45.6 2.137 45.72 105.863 ;
        RECT  40.2 2.137 40.32 105.863 ;
        RECT  34.8 2.137 34.92 105.863 ;
        RECT  29.4 2.137 29.52 105.863 ;
        RECT  24 2.137 24.12 105.863 ;
        RECT  18.6 2.137 18.72 105.863 ;
        RECT  13.2 2.137 13.32 105.863 ;
        RECT  7.8 2.137 7.92 105.863 ;
        RECT  2.4 2.137 2.52 105.863 ;
    END
  END VSS
  OBS
    LAYER RVTN ;
     RECT  2.16 2.16 84.24 2.295 ;
     RECT  2.16 2.565 84.24 2.835 ;
     RECT  2.16 3.105 84.24 3.375 ;
     RECT  2.16 3.645 84.24 3.915 ;
     RECT  2.16 4.185 84.24 4.455 ;
     RECT  2.16 4.725 84.24 4.995 ;
     RECT  2.16 5.265 84.24 5.535 ;
     RECT  2.16 5.805 84.24 6.075 ;
     RECT  2.16 6.345 84.24 6.615 ;
     RECT  2.16 6.885 84.24 7.155 ;
     RECT  2.16 7.425 84.24 7.695 ;
     RECT  2.16 7.965 84.24 8.235 ;
     RECT  2.16 8.505 84.24 8.775 ;
     RECT  2.16 9.045 84.24 9.315 ;
     RECT  2.16 9.585 84.24 9.855 ;
     RECT  2.16 10.125 84.24 10.395 ;
     RECT  2.16 10.665 84.24 10.935 ;
     RECT  2.16 11.205 84.24 11.475 ;
     RECT  2.16 11.745 84.24 12.015 ;
     RECT  2.16 12.285 84.24 12.555 ;
     RECT  2.16 12.825 84.24 13.095 ;
     RECT  2.16 13.365 84.24 13.635 ;
     RECT  2.16 13.905 84.24 14.175 ;
     RECT  2.16 14.445 84.24 14.715 ;
     RECT  2.16 14.985 84.24 15.255 ;
     RECT  2.16 15.525 84.24 15.795 ;
     RECT  2.16 16.065 84.24 16.335 ;
     RECT  2.16 16.605 84.24 16.875 ;
     RECT  2.16 17.145 84.24 17.415 ;
     RECT  2.16 17.685 84.24 17.955 ;
     RECT  2.16 18.225 84.24 18.495 ;
     RECT  2.16 18.765 84.24 19.035 ;
     RECT  2.16 19.305 84.24 19.575 ;
     RECT  2.16 19.845 84.24 20.115 ;
     RECT  2.16 20.385 84.24 20.655 ;
     RECT  2.16 20.925 84.24 21.195 ;
     RECT  2.16 21.465 84.24 21.735 ;
     RECT  2.16 22.005 84.24 22.275 ;
     RECT  2.16 22.545 84.24 22.815 ;
     RECT  2.16 23.085 84.24 23.355 ;
     RECT  2.16 23.625 84.24 23.895 ;
     RECT  2.16 24.165 84.24 24.435 ;
     RECT  2.16 24.705 84.24 24.975 ;
     RECT  2.16 25.245 84.24 25.515 ;
     RECT  2.16 25.785 84.24 26.055 ;
     RECT  2.16 26.325 84.24 26.595 ;
     RECT  2.16 26.865 84.24 27.135 ;
     RECT  2.16 27.405 84.24 27.675 ;
     RECT  2.16 27.945 84.24 28.215 ;
     RECT  2.16 28.485 84.24 28.755 ;
     RECT  2.16 29.025 84.24 29.295 ;
     RECT  2.16 29.565 84.24 29.835 ;
     RECT  2.16 30.105 84.24 30.375 ;
     RECT  2.16 30.645 84.24 30.915 ;
     RECT  2.16 31.185 84.24 31.455 ;
     RECT  2.16 31.725 84.24 31.995 ;
     RECT  2.16 32.265 84.24 32.535 ;
     RECT  2.16 32.805 84.24 33.075 ;
     RECT  2.16 33.345 84.24 33.615 ;
     RECT  2.16 33.885 84.24 34.155 ;
     RECT  2.16 34.425 84.24 34.695 ;
     RECT  2.16 34.965 84.24 35.235 ;
     RECT  2.16 35.505 84.24 35.775 ;
     RECT  2.16 36.045 84.24 36.315 ;
     RECT  2.16 36.585 84.24 36.855 ;
     RECT  2.16 37.125 84.24 37.395 ;
     RECT  2.16 37.665 84.24 37.935 ;
     RECT  2.16 38.205 84.24 38.475 ;
     RECT  2.16 38.745 84.24 39.015 ;
     RECT  2.16 39.285 84.24 39.555 ;
     RECT  2.16 39.825 84.24 40.095 ;
     RECT  2.16 40.365 84.24 40.635 ;
     RECT  2.16 40.905 84.24 41.175 ;
     RECT  2.16 41.445 84.24 41.715 ;
     RECT  2.16 41.985 84.24 42.255 ;
     RECT  2.16 42.525 84.24 42.795 ;
     RECT  2.16 43.065 84.24 43.335 ;
     RECT  2.16 43.605 84.24 43.875 ;
     RECT  2.16 44.145 84.24 44.415 ;
     RECT  2.16 44.685 84.24 44.955 ;
     RECT  2.16 45.225 84.24 45.495 ;
     RECT  2.16 45.765 84.24 46.035 ;
     RECT  2.16 46.305 84.24 46.575 ;
     RECT  2.16 46.845 84.24 47.115 ;
     RECT  2.16 47.385 84.24 47.655 ;
     RECT  2.16 47.925 84.24 48.195 ;
     RECT  2.16 48.465 84.24 48.735 ;
     RECT  2.16 49.005 84.24 49.275 ;
     RECT  2.16 49.545 84.24 49.815 ;
     RECT  2.16 50.085 84.24 50.355 ;
     RECT  2.16 50.625 84.24 50.895 ;
     RECT  2.16 51.165 84.24 51.435 ;
     RECT  2.16 51.705 84.24 51.975 ;
     RECT  2.16 52.245 84.24 52.515 ;
     RECT  2.16 52.785 84.24 53.055 ;
     RECT  2.16 53.325 84.24 53.595 ;
     RECT  2.16 53.865 84.24 54.135 ;
     RECT  2.16 54.405 84.24 54.675 ;
     RECT  2.16 54.945 84.24 55.215 ;
     RECT  2.16 55.485 84.24 55.755 ;
     RECT  2.16 56.025 84.24 56.295 ;
     RECT  2.16 56.565 84.24 56.835 ;
     RECT  2.16 57.105 84.24 57.375 ;
     RECT  2.16 57.645 84.24 57.915 ;
     RECT  2.16 58.185 84.24 58.455 ;
     RECT  2.16 58.725 84.24 58.995 ;
     RECT  2.16 59.265 84.24 59.535 ;
     RECT  2.16 59.805 84.24 60.075 ;
     RECT  2.16 60.345 84.24 60.615 ;
     RECT  2.16 60.885 84.24 61.155 ;
     RECT  2.16 61.425 84.24 61.695 ;
     RECT  2.16 61.965 84.24 62.235 ;
     RECT  2.16 62.505 84.24 62.775 ;
     RECT  2.16 63.045 84.24 63.315 ;
     RECT  2.16 63.585 84.24 63.855 ;
     RECT  2.16 64.125 84.24 64.395 ;
     RECT  2.16 64.665 84.24 64.935 ;
     RECT  2.16 65.205 84.24 65.475 ;
     RECT  2.16 65.745 84.24 66.015 ;
     RECT  2.16 66.285 84.24 66.555 ;
     RECT  2.16 66.825 84.24 67.095 ;
     RECT  2.16 67.365 84.24 67.635 ;
     RECT  2.16 67.905 84.24 68.175 ;
     RECT  2.16 68.445 84.24 68.715 ;
     RECT  2.16 68.985 84.24 69.255 ;
     RECT  2.16 69.525 84.24 69.795 ;
     RECT  2.16 70.065 84.24 70.335 ;
     RECT  2.16 70.605 84.24 70.875 ;
     RECT  2.16 71.145 84.24 71.415 ;
     RECT  2.16 71.685 84.24 71.955 ;
     RECT  2.16 72.225 84.24 72.495 ;
     RECT  2.16 72.765 84.24 73.035 ;
     RECT  2.16 73.305 84.24 73.575 ;
     RECT  2.16 73.845 84.24 74.115 ;
     RECT  2.16 74.385 84.24 74.655 ;
     RECT  2.16 74.925 84.24 75.195 ;
     RECT  2.16 75.465 84.24 75.735 ;
     RECT  2.16 76.005 84.24 76.275 ;
     RECT  2.16 76.545 84.24 76.815 ;
     RECT  2.16 77.085 84.24 77.355 ;
     RECT  2.16 77.625 84.24 77.895 ;
     RECT  2.16 78.165 84.24 78.435 ;
     RECT  2.16 78.705 84.24 78.975 ;
     RECT  2.16 79.245 84.24 79.515 ;
     RECT  2.16 79.785 84.24 80.055 ;
     RECT  2.16 80.325 84.24 80.595 ;
     RECT  2.16 80.865 84.24 81.135 ;
     RECT  2.16 81.405 84.24 81.675 ;
     RECT  2.16 81.945 84.24 82.215 ;
     RECT  2.16 82.485 84.24 82.755 ;
     RECT  2.16 83.025 84.24 83.295 ;
     RECT  2.16 83.565 84.24 83.835 ;
     RECT  2.16 84.105 84.24 84.375 ;
     RECT  2.16 84.645 84.24 84.915 ;
     RECT  2.16 85.185 84.24 85.455 ;
     RECT  2.16 85.725 84.24 85.995 ;
     RECT  2.16 86.265 84.24 86.535 ;
     RECT  2.16 86.805 84.24 87.075 ;
     RECT  2.16 87.345 84.24 87.615 ;
     RECT  2.16 87.885 84.24 88.155 ;
     RECT  2.16 88.425 84.24 88.695 ;
     RECT  2.16 88.965 84.24 89.235 ;
     RECT  2.16 89.505 84.24 89.775 ;
     RECT  2.16 90.045 84.24 90.315 ;
     RECT  2.16 90.585 84.24 90.855 ;
     RECT  2.16 91.125 84.24 91.395 ;
     RECT  2.16 91.665 84.24 91.935 ;
     RECT  2.16 92.205 84.24 92.475 ;
     RECT  2.16 92.745 84.24 93.015 ;
     RECT  2.16 93.285 84.24 93.555 ;
     RECT  2.16 93.825 84.24 94.095 ;
     RECT  2.16 94.365 84.24 94.635 ;
     RECT  2.16 94.905 84.24 95.175 ;
     RECT  2.16 95.445 84.24 95.715 ;
     RECT  2.16 95.985 84.24 96.255 ;
     RECT  2.16 96.525 84.24 96.795 ;
     RECT  2.16 97.065 84.24 97.335 ;
     RECT  2.16 97.605 84.24 97.875 ;
     RECT  2.16 98.145 84.24 98.415 ;
     RECT  2.16 98.685 84.24 98.955 ;
     RECT  2.16 99.225 84.24 99.495 ;
     RECT  2.16 99.765 84.24 100.035 ;
     RECT  2.16 100.305 84.24 100.575 ;
     RECT  2.16 100.845 84.24 101.115 ;
     RECT  2.16 101.385 84.24 101.655 ;
     RECT  2.16 101.925 84.24 102.195 ;
     RECT  2.16 102.465 84.24 102.735 ;
     RECT  2.16 103.005 84.24 103.275 ;
     RECT  2.16 103.545 84.24 103.815 ;
     RECT  2.16 104.085 84.24 104.355 ;
     RECT  2.16 104.625 84.24 104.895 ;
     RECT  2.16 105.165 84.24 105.435 ;
     RECT  2.16 105.705 84.24 105.84 ;
    LAYER RVTP ;
     RECT  2.16 2.295 84.24 2.565 ;
     RECT  2.16 2.835 84.24 3.105 ;
     RECT  2.16 3.375 84.24 3.645 ;
     RECT  2.16 3.915 84.24 4.185 ;
     RECT  2.16 4.455 84.24 4.725 ;
     RECT  2.16 4.995 84.24 5.265 ;
     RECT  2.16 5.535 84.24 5.805 ;
     RECT  2.16 6.075 84.24 6.345 ;
     RECT  2.16 6.615 84.24 6.885 ;
     RECT  2.16 7.155 84.24 7.425 ;
     RECT  2.16 7.695 84.24 7.965 ;
     RECT  2.16 8.235 84.24 8.505 ;
     RECT  2.16 8.775 84.24 9.045 ;
     RECT  2.16 9.315 84.24 9.585 ;
     RECT  2.16 9.855 84.24 10.125 ;
     RECT  2.16 10.395 84.24 10.665 ;
     RECT  2.16 10.935 84.24 11.205 ;
     RECT  2.16 11.475 84.24 11.745 ;
     RECT  2.16 12.015 84.24 12.285 ;
     RECT  2.16 12.555 84.24 12.825 ;
     RECT  2.16 13.095 84.24 13.365 ;
     RECT  2.16 13.635 84.24 13.905 ;
     RECT  2.16 14.175 84.24 14.445 ;
     RECT  2.16 14.715 84.24 14.985 ;
     RECT  2.16 15.255 84.24 15.525 ;
     RECT  2.16 15.795 84.24 16.065 ;
     RECT  2.16 16.335 84.24 16.605 ;
     RECT  2.16 16.875 84.24 17.145 ;
     RECT  2.16 17.415 84.24 17.685 ;
     RECT  2.16 17.955 84.24 18.225 ;
     RECT  2.16 18.495 84.24 18.765 ;
     RECT  2.16 19.035 84.24 19.305 ;
     RECT  2.16 19.575 84.24 19.845 ;
     RECT  2.16 20.115 84.24 20.385 ;
     RECT  2.16 20.655 84.24 20.925 ;
     RECT  2.16 21.195 84.24 21.465 ;
     RECT  2.16 21.735 84.24 22.005 ;
     RECT  2.16 22.275 84.24 22.545 ;
     RECT  2.16 22.815 84.24 23.085 ;
     RECT  2.16 23.355 84.24 23.625 ;
     RECT  2.16 23.895 84.24 24.165 ;
     RECT  2.16 24.435 84.24 24.705 ;
     RECT  2.16 24.975 84.24 25.245 ;
     RECT  2.16 25.515 84.24 25.785 ;
     RECT  2.16 26.055 84.24 26.325 ;
     RECT  2.16 26.595 84.24 26.865 ;
     RECT  2.16 27.135 84.24 27.405 ;
     RECT  2.16 27.675 84.24 27.945 ;
     RECT  2.16 28.215 84.24 28.485 ;
     RECT  2.16 28.755 84.24 29.025 ;
     RECT  2.16 29.295 84.24 29.565 ;
     RECT  2.16 29.835 84.24 30.105 ;
     RECT  2.16 30.375 84.24 30.645 ;
     RECT  2.16 30.915 84.24 31.185 ;
     RECT  2.16 31.455 84.24 31.725 ;
     RECT  2.16 31.995 84.24 32.265 ;
     RECT  2.16 32.535 84.24 32.805 ;
     RECT  2.16 33.075 84.24 33.345 ;
     RECT  2.16 33.615 84.24 33.885 ;
     RECT  2.16 34.155 84.24 34.425 ;
     RECT  2.16 34.695 84.24 34.965 ;
     RECT  2.16 35.235 84.24 35.505 ;
     RECT  2.16 35.775 84.24 36.045 ;
     RECT  2.16 36.315 84.24 36.585 ;
     RECT  2.16 36.855 84.24 37.125 ;
     RECT  2.16 37.395 84.24 37.665 ;
     RECT  2.16 37.935 84.24 38.205 ;
     RECT  2.16 38.475 84.24 38.745 ;
     RECT  2.16 39.015 84.24 39.285 ;
     RECT  2.16 39.555 84.24 39.825 ;
     RECT  2.16 40.095 84.24 40.365 ;
     RECT  2.16 40.635 84.24 40.905 ;
     RECT  2.16 41.175 84.24 41.445 ;
     RECT  2.16 41.715 84.24 41.985 ;
     RECT  2.16 42.255 84.24 42.525 ;
     RECT  2.16 42.795 84.24 43.065 ;
     RECT  2.16 43.335 84.24 43.605 ;
     RECT  2.16 43.875 84.24 44.145 ;
     RECT  2.16 44.415 84.24 44.685 ;
     RECT  2.16 44.955 84.24 45.225 ;
     RECT  2.16 45.495 84.24 45.765 ;
     RECT  2.16 46.035 84.24 46.305 ;
     RECT  2.16 46.575 84.24 46.845 ;
     RECT  2.16 47.115 84.24 47.385 ;
     RECT  2.16 47.655 84.24 47.925 ;
     RECT  2.16 48.195 84.24 48.465 ;
     RECT  2.16 48.735 84.24 49.005 ;
     RECT  2.16 49.275 84.24 49.545 ;
     RECT  2.16 49.815 84.24 50.085 ;
     RECT  2.16 50.355 84.24 50.625 ;
     RECT  2.16 50.895 84.24 51.165 ;
     RECT  2.16 51.435 84.24 51.705 ;
     RECT  2.16 51.975 84.24 52.245 ;
     RECT  2.16 52.515 84.24 52.785 ;
     RECT  2.16 53.055 84.24 53.325 ;
     RECT  2.16 53.595 84.24 53.865 ;
     RECT  2.16 54.135 84.24 54.405 ;
     RECT  2.16 54.675 84.24 54.945 ;
     RECT  2.16 55.215 84.24 55.485 ;
     RECT  2.16 55.755 84.24 56.025 ;
     RECT  2.16 56.295 84.24 56.565 ;
     RECT  2.16 56.835 84.24 57.105 ;
     RECT  2.16 57.375 84.24 57.645 ;
     RECT  2.16 57.915 84.24 58.185 ;
     RECT  2.16 58.455 84.24 58.725 ;
     RECT  2.16 58.995 84.24 59.265 ;
     RECT  2.16 59.535 84.24 59.805 ;
     RECT  2.16 60.075 84.24 60.345 ;
     RECT  2.16 60.615 84.24 60.885 ;
     RECT  2.16 61.155 84.24 61.425 ;
     RECT  2.16 61.695 84.24 61.965 ;
     RECT  2.16 62.235 84.24 62.505 ;
     RECT  2.16 62.775 84.24 63.045 ;
     RECT  2.16 63.315 84.24 63.585 ;
     RECT  2.16 63.855 84.24 64.125 ;
     RECT  2.16 64.395 84.24 64.665 ;
     RECT  2.16 64.935 84.24 65.205 ;
     RECT  2.16 65.475 84.24 65.745 ;
     RECT  2.16 66.015 84.24 66.285 ;
     RECT  2.16 66.555 84.24 66.825 ;
     RECT  2.16 67.095 84.24 67.365 ;
     RECT  2.16 67.635 84.24 67.905 ;
     RECT  2.16 68.175 84.24 68.445 ;
     RECT  2.16 68.715 84.24 68.985 ;
     RECT  2.16 69.255 84.24 69.525 ;
     RECT  2.16 69.795 84.24 70.065 ;
     RECT  2.16 70.335 84.24 70.605 ;
     RECT  2.16 70.875 84.24 71.145 ;
     RECT  2.16 71.415 84.24 71.685 ;
     RECT  2.16 71.955 84.24 72.225 ;
     RECT  2.16 72.495 84.24 72.765 ;
     RECT  2.16 73.035 84.24 73.305 ;
     RECT  2.16 73.575 84.24 73.845 ;
     RECT  2.16 74.115 84.24 74.385 ;
     RECT  2.16 74.655 84.24 74.925 ;
     RECT  2.16 75.195 84.24 75.465 ;
     RECT  2.16 75.735 84.24 76.005 ;
     RECT  2.16 76.275 84.24 76.545 ;
     RECT  2.16 76.815 84.24 77.085 ;
     RECT  2.16 77.355 84.24 77.625 ;
     RECT  2.16 77.895 84.24 78.165 ;
     RECT  2.16 78.435 84.24 78.705 ;
     RECT  2.16 78.975 84.24 79.245 ;
     RECT  2.16 79.515 84.24 79.785 ;
     RECT  2.16 80.055 84.24 80.325 ;
     RECT  2.16 80.595 84.24 80.865 ;
     RECT  2.16 81.135 84.24 81.405 ;
     RECT  2.16 81.675 84.24 81.945 ;
     RECT  2.16 82.215 84.24 82.485 ;
     RECT  2.16 82.755 84.24 83.025 ;
     RECT  2.16 83.295 84.24 83.565 ;
     RECT  2.16 83.835 84.24 84.105 ;
     RECT  2.16 84.375 84.24 84.645 ;
     RECT  2.16 84.915 84.24 85.185 ;
     RECT  2.16 85.455 84.24 85.725 ;
     RECT  2.16 85.995 84.24 86.265 ;
     RECT  2.16 86.535 84.24 86.805 ;
     RECT  2.16 87.075 84.24 87.345 ;
     RECT  2.16 87.615 84.24 87.885 ;
     RECT  2.16 88.155 84.24 88.425 ;
     RECT  2.16 88.695 84.24 88.965 ;
     RECT  2.16 89.235 84.24 89.505 ;
     RECT  2.16 89.775 84.24 90.045 ;
     RECT  2.16 90.315 84.24 90.585 ;
     RECT  2.16 90.855 84.24 91.125 ;
     RECT  2.16 91.395 84.24 91.665 ;
     RECT  2.16 91.935 84.24 92.205 ;
     RECT  2.16 92.475 84.24 92.745 ;
     RECT  2.16 93.015 84.24 93.285 ;
     RECT  2.16 93.555 84.24 93.825 ;
     RECT  2.16 94.095 84.24 94.365 ;
     RECT  2.16 94.635 84.24 94.905 ;
     RECT  2.16 95.175 84.24 95.445 ;
     RECT  2.16 95.715 84.24 95.985 ;
     RECT  2.16 96.255 84.24 96.525 ;
     RECT  2.16 96.795 84.24 97.065 ;
     RECT  2.16 97.335 84.24 97.605 ;
     RECT  2.16 97.875 84.24 98.145 ;
     RECT  2.16 98.415 84.24 98.685 ;
     RECT  2.16 98.955 84.24 99.225 ;
     RECT  2.16 99.495 84.24 99.765 ;
     RECT  2.16 100.035 84.24 100.305 ;
     RECT  2.16 100.575 84.24 100.845 ;
     RECT  2.16 101.115 84.24 101.385 ;
     RECT  2.16 101.655 84.24 101.925 ;
     RECT  2.16 102.195 84.24 102.465 ;
     RECT  2.16 102.735 84.24 103.005 ;
     RECT  2.16 103.275 84.24 103.545 ;
     RECT  2.16 103.815 84.24 104.085 ;
     RECT  2.16 104.355 84.24 104.625 ;
     RECT  2.16 104.895 84.24 105.165 ;
     RECT  2.16 105.435 84.24 105.705 ;
    LAYER M1 ;
     RECT  2.16 2.151 84.24 105.849 ;
    LAYER M2 ;
     RECT  0.103 16.956 0.535 16.974 ;
     RECT  0.535 15.876 2.16 17.676 ;
     RECT  0.103 18.468 2.16 18.486 ;
     RECT  0.103 22.716 2.16 22.734 ;
     RECT  0.103 25.596 2.16 25.614 ;
     RECT  0.103 36.396 2.16 36.414 ;
     RECT  0.535 37.566 2.16 37.584 ;
     RECT  2.047 38.448 2.16 38.466 ;
     RECT  0.535 55.26 2.16 55.278 ;
     RECT  0.103 58.086 2.16 58.104 ;
     RECT  0.103 72.468 2.16 72.486 ;
     RECT  0.535 83.736 2.16 83.754 ;
     RECT  0.535 91.746 2.16 91.764 ;
     RECT  0.103 92.826 2.16 92.844 ;
     RECT  0.103 95.346 2.16 95.364 ;
     RECT  2.16 2.151 84.24 105.849 ;
     RECT  84.24 101.7 84.911 102.762 ;
     RECT  84.24 29.772 84.947 29.79 ;
     RECT  84.24 53.568 84.947 54.972 ;
     RECT  84.24 55.764 84.947 57.096 ;
     RECT  84.24 62.172 84.947 63.54 ;
     RECT  84.24 71.352 84.947 71.64 ;
     RECT  84.24 82.728 84.947 83.79 ;
     RECT  84.24 87.318 84.947 87.642 ;
     RECT  84.24 92.178 84.947 93.078 ;
     RECT  84.24 93.87 84.947 94.86 ;
     RECT  84.911 102.438 84.947 102.762 ;
     RECT  84.24 4.968 85.379 5.526 ;
     RECT  84.24 9.558 85.379 9.846 ;
     RECT  84.24 21.132 85.379 22.23 ;
     RECT  84.24 23.022 85.379 24.696 ;
     RECT  84.24 33.318 85.379 34.416 ;
     RECT  84.24 41.958 85.379 42.48 ;
     RECT  84.24 43.308 85.379 45.45 ;
     RECT  84.24 46.278 85.379 46.602 ;
     RECT  84.947 53.568 85.379 54.126 ;
     RECT  84.24 59.238 85.379 61.416 ;
     RECT  84.24 65.718 85.379 66.276 ;
     RECT  84.24 67.068 85.379 68.13 ;
     RECT  84.24 80.028 85.379 81.09 ;
     RECT  84.947 82.998 85.379 83.016 ;
     RECT  84.947 87.318 85.379 87.336 ;
     RECT  84.24 88.668 85.379 88.686 ;
     RECT  84.24 103.788 85.379 104.886 ;
     RECT  84.24 76.788 85.451 77.85 ;
     RECT  84.24 2.808 85.487 3.096 ;
     RECT  84.24 3.852 85.487 3.87 ;
     RECT  85.379 5.202 85.487 5.526 ;
     RECT  84.24 6.282 85.487 7.38 ;
     RECT  84.24 8.172 85.487 8.73 ;
     RECT  85.379 9.828 85.487 9.846 ;
     RECT  84.24 10.602 85.487 11.16 ;
     RECT  84.24 11.952 85.487 14.13 ;
     RECT  84.24 14.922 85.487 16.596 ;
     RECT  84.24 17.352 85.487 18.45 ;
     RECT  84.24 19.278 85.487 20.34 ;
     RECT  85.379 21.132 85.487 21.15 ;
     RECT  85.379 22.212 85.487 22.23 ;
     RECT  85.379 23.022 85.487 24.12 ;
     RECT  84.24 25.488 85.487 27.09 ;
     RECT  84.24 27.918 85.487 28.98 ;
     RECT  84.24 30.888 85.487 32.49 ;
     RECT  85.379 33.858 85.487 34.416 ;
     RECT  84.24 35.172 85.487 36.27 ;
     RECT  84.24 37.062 85.487 39.276 ;
     RECT  84.24 40.41 85.487 41.13 ;
     RECT  85.379 42.462 85.487 42.48 ;
     RECT  85.379 43.542 85.487 45.45 ;
     RECT  85.379 46.584 85.487 46.602 ;
     RECT  84.24 47.358 85.487 48.456 ;
     RECT  84.24 49.248 85.487 50.958 ;
     RECT  84.24 52.182 85.487 52.776 ;
     RECT  85.379 53.568 85.487 53.586 ;
     RECT  84.947 56.502 85.487 57.096 ;
     RECT  84.24 57.852 85.487 58.41 ;
     RECT  85.379 59.778 85.487 60.876 ;
     RECT  84.947 62.172 85.487 63.27 ;
     RECT  84.24 64.602 85.487 64.62 ;
     RECT  85.379 65.988 85.487 66.276 ;
     RECT  85.379 67.608 85.487 68.13 ;
     RECT  84.24 68.922 85.487 70.596 ;
     RECT  84.947 71.352 85.487 71.37 ;
     RECT  84.24 72.738 85.487 73.026 ;
     RECT  84.24 73.782 85.487 75.492 ;
     RECT  85.451 77.022 85.487 77.85 ;
     RECT  84.24 78.642 85.487 79.2 ;
     RECT  85.379 80.532 85.487 81.09 ;
     RECT  84.24 81.918 85.487 81.936 ;
     RECT  84.24 84.654 85.487 86.526 ;
     RECT  84.24 90.792 85.487 91.422 ;
     RECT  84.947 92.178 85.487 92.7 ;
     RECT  84.947 94.446 85.487 94.464 ;
     RECT  84.24 95.724 85.487 96.012 ;
     RECT  84.24 97.038 85.487 97.596 ;
     RECT  84.24 98.388 85.487 99.18 ;
     RECT  84.24 99.972 85.487 99.99 ;
     RECT  84.24 100.818 85.487 100.836 ;
     RECT  84.947 102.438 85.487 102.456 ;
     RECT  84.24 105.678 85.487 105.696 ;
     RECT  85.487 40.41 85.523 40.428 ;
     RECT  85.487 49.554 85.523 49.572 ;
     RECT  84.947 83.772 85.523 83.79 ;
     RECT  84.24 89.478 85.523 90.036 ;
     RECT  85.487 95.994 85.523 96.012 ;
     RECT  85.487 99.162 85.523 99.18 ;
     RECT  85.487 32.472 86.315 32.49 ;
     RECT  85.487 48.438 86.315 48.456 ;
     RECT  85.379 104.292 86.315 104.886 ;
    LAYER M3 ;
     RECT  40.215 2.143 40.305 2.335 ;
     RECT  40.215 2.335 40.662 2.371 ;
     RECT  2.415 2.143 2.505 2.413 ;
     RECT  7.815 2.143 7.905 2.413 ;
     RECT  13.215 2.143 13.305 2.413 ;
     RECT  18.615 2.143 18.705 2.413 ;
     RECT  24.015 2.143 24.105 2.413 ;
     RECT  29.415 2.143 29.505 2.413 ;
     RECT  34.815 2.143 34.905 2.413 ;
     RECT  45.615 2.143 45.705 2.413 ;
     RECT  51.015 2.143 51.105 2.413 ;
     RECT  56.415 2.143 56.505 2.413 ;
     RECT  61.815 2.143 61.905 2.413 ;
     RECT  67.215 2.143 67.305 2.413 ;
     RECT  72.615 2.143 72.705 2.413 ;
     RECT  78.015 2.143 78.105 2.413 ;
     RECT  83.415 2.143 83.505 2.413 ;
     RECT  36.828 2.371 36.846 2.533 ;
     RECT  83.415 2.413 83.697 2.533 ;
     RECT  38.16 2.533 38.178 2.569 ;
     RECT  38.916 2.371 38.934 2.569 ;
     RECT  40.215 2.371 40.77 2.569 ;
     RECT  0.108 2.443 0.126 2.573 ;
     RECT  83.304 2.533 83.697 2.605 ;
     RECT  36.324 2.533 36.846 2.635 ;
     RECT  3.42 2.461 3.438 2.641 ;
     RECT  38.16 2.569 38.934 2.641 ;
     RECT  39.96 2.569 40.77 2.641 ;
     RECT  51.015 2.413 51.297 2.641 ;
     RECT  50.724 2.641 51.297 2.731 ;
     RECT  63.792 2.731 63.882 2.767 ;
     RECT  83.304 2.605 84.042 2.795 ;
     RECT  3.42 2.641 3.474 2.803 ;
     RECT  63.792 2.767 63.99 2.861 ;
     RECT  41.544 2.605 41.562 2.875 ;
     RECT  3.42 2.803 3.654 2.911 ;
     RECT  36.324 2.635 37.17 2.911 ;
     RECT  38.16 2.641 40.77 2.911 ;
     RECT  41.544 2.875 41.778 2.911 ;
     RECT  64.98 2.767 64.998 2.911 ;
     RECT  73.8 2.731 73.818 2.911 ;
     RECT  64.908 2.911 64.998 2.939 ;
     RECT  2.415 2.413 2.697 3.019 ;
     RECT  63.792 2.861 63.882 3.029 ;
     RECT  73.8 2.911 73.926 3.029 ;
     RECT  50.508 2.731 51.297 3.065 ;
     RECT  64.908 2.939 64.926 3.101 ;
     RECT  36.324 2.911 41.778 3.145 ;
     RECT  34.815 2.413 35.097 3.163 ;
     RECT  35.892 3.145 41.778 3.163 ;
     RECT  4.608 2.911 4.626 3.173 ;
     RECT  34.815 3.163 41.778 3.181 ;
     RECT  34.815 3.181 42.39 3.271 ;
     RECT  73.8 3.029 73.89 3.271 ;
     RECT  44.172 2.767 44.19 3.299 ;
     RECT  43.236 3.301 43.254 3.341 ;
     RECT  44.352 3.307 44.37 3.344 ;
     RECT  2.34 3.019 2.697 3.371 ;
     RECT  34.815 3.271 42.498 3.371 ;
     RECT  34.815 3.371 42.39 3.443 ;
     RECT  45.615 2.413 45.897 3.451 ;
     RECT  67.215 2.413 67.497 3.451 ;
     RECT  72.615 2.413 72.897 3.541 ;
     RECT  73.728 3.271 73.89 3.541 ;
     RECT  34.815 3.443 41.958 3.569 ;
     RECT  43.38 3.343 43.398 3.569 ;
     RECT  54.144 3.451 54.162 3.569 ;
     RECT  83.415 2.795 84.042 3.569 ;
     RECT  58.788 3.541 58.806 3.577 ;
     RECT  44.532 3.451 44.55 3.605 ;
     RECT  46.764 3.451 46.782 3.605 ;
     RECT  58.68 3.577 58.806 3.641 ;
     RECT  58.68 3.641 58.698 3.677 ;
     RECT  2.415 3.371 2.697 3.685 ;
     RECT  3.42 2.911 3.834 3.685 ;
     RECT  54.792 3.613 54.81 3.713 ;
     RECT  64.62 3.685 64.782 3.721 ;
     RECT  66.672 3.451 67.497 3.721 ;
     RECT  66.24 3.721 67.497 3.749 ;
     RECT  63.468 3.451 63.558 3.811 ;
     RECT  64.296 3.721 64.782 3.811 ;
     RECT  34.815 3.569 41.886 3.839 ;
     RECT  66.24 3.749 66.402 3.883 ;
     RECT  63.468 3.811 64.782 3.931 ;
     RECT  65.52 3.883 66.402 3.931 ;
     RECT  5.328 3.649 5.346 3.955 ;
     RECT  45.324 3.451 45.897 3.983 ;
     RECT  63.324 3.931 66.402 3.983 ;
     RECT  2.415 3.685 3.834 3.991 ;
     RECT  4.608 3.955 5.346 3.991 ;
     RECT  2.415 3.991 5.346 4.109 ;
     RECT  63.828 3.983 66.402 4.145 ;
     RECT  72.615 3.541 73.89 4.145 ;
     RECT  5.112 4.109 5.166 4.157 ;
     RECT  2.415 4.109 4.158 4.217 ;
     RECT  66.384 4.145 66.402 4.217 ;
     RECT  61.815 2.413 62.097 4.225 ;
     RECT  63.828 4.145 65.538 4.253 ;
     RECT  64.044 4.253 65.538 4.289 ;
     RECT  73.944 4.261 74.25 4.351 ;
     RECT  78.015 2.413 78.297 4.351 ;
     RECT  83.415 3.569 83.898 4.351 ;
     RECT  41.868 3.839 41.886 4.363 ;
     RECT  42.732 4.261 42.75 4.363 ;
     RECT  34.815 3.839 41.022 4.379 ;
     RECT  41.868 4.363 42.75 4.379 ;
     RECT  49.788 4.189 49.806 4.379 ;
     RECT  73.944 4.351 74.754 4.379 ;
     RECT  74.736 4.379 74.754 4.387 ;
     RECT  83.304 4.351 83.898 4.387 ;
     RECT  61.815 4.225 62.19 4.415 ;
     RECT  82.728 4.387 83.898 4.423 ;
     RECT  50.724 3.065 51.297 4.487 ;
     RECT  74.736 4.387 74.826 4.487 ;
     RECT  82.728 4.423 84.042 4.487 ;
     RECT  6.12 4.261 6.138 4.523 ;
     RECT  74.808 4.487 74.826 4.523 ;
     RECT  83.376 4.487 84.042 4.523 ;
     RECT  58.716 4.423 58.734 4.559 ;
     RECT  78.015 4.351 78.75 4.559 ;
     RECT  35.928 4.379 41.022 4.649 ;
     RECT  52.632 4.423 52.65 4.685 ;
     RECT  73.944 4.379 73.962 4.685 ;
     RECT  2.415 4.217 4.05 4.721 ;
     RECT  64.044 4.289 64.962 4.721 ;
     RECT  2.415 4.721 4.014 4.733 ;
     RECT  36.216 4.649 41.022 4.801 ;
     RECT  41.868 4.379 42.426 4.801 ;
     RECT  1.152 4.699 1.17 4.829 ;
     RECT  85.464 2.443 85.482 4.891 ;
     RECT  83.415 4.523 84.042 4.919 ;
     RECT  85.356 4.891 85.482 4.991 ;
     RECT  5.112 4.157 5.13 5.027 ;
     RECT  36.216 4.801 42.426 5.179 ;
     RECT  2.415 4.733 3.978 5.341 ;
     RECT  34.815 4.379 35.097 5.341 ;
     RECT  36.216 5.179 42.642 5.341 ;
     RECT  64.044 4.721 64.854 5.341 ;
     RECT  36.216 5.341 42.75 5.459 ;
     RECT  53.604 5.161 53.622 5.459 ;
     RECT  73.872 5.161 73.89 5.459 ;
     RECT  63.972 5.341 64.854 5.495 ;
     RECT  82.548 5.341 82.566 5.495 ;
     RECT  34.776 5.341 35.097 5.567 ;
     RECT  74.664 5.467 74.682 5.567 ;
     RECT  2.304 5.341 3.978 5.611 ;
     RECT  2.304 5.611 4.338 5.693 ;
     RECT  3.492 5.693 4.338 5.801 ;
     RECT  36.468 5.459 42.75 5.909 ;
     RECT  63.972 5.495 64.494 5.971 ;
     RECT  63.936 5.971 64.494 6.151 ;
     RECT  2.304 5.693 2.697 6.179 ;
     RECT  63.828 6.151 64.494 6.241 ;
     RECT  37.044 5.909 42.75 6.275 ;
     RECT  37.08 6.275 42.75 6.421 ;
     RECT  67.215 3.749 67.497 6.421 ;
     RECT  73.692 6.241 73.71 6.421 ;
     RECT  2.415 6.179 2.697 6.511 ;
     RECT  3.492 5.801 4.086 6.511 ;
     RECT  37.08 6.421 42.93 6.539 ;
     RECT  66.708 6.421 67.497 6.539 ;
     RECT  73.692 6.421 73.818 6.539 ;
     RECT  53.424 6.151 53.442 6.575 ;
     RECT  73.692 6.539 73.71 6.575 ;
     RECT  43.704 6.241 43.722 6.691 ;
     RECT  63.828 6.241 64.638 6.691 ;
     RECT  72.615 4.145 72.897 6.781 ;
     RECT  61.815 4.415 62.097 6.808 ;
     RECT  43.416 6.691 43.722 6.809 ;
     RECT  63.648 6.691 64.71 6.809 ;
     RECT  82.656 6.313 82.674 6.817 ;
     RECT  83.415 4.919 83.898 6.817 ;
     RECT  37.08 6.539 42.498 6.845 ;
     RECT  63.648 6.809 64.566 6.845 ;
     RECT  45.615 3.983 45.897 6.961 ;
     RECT  46.62 6.925 46.638 6.961 ;
     RECT  61.815 6.808 62.586 6.961 ;
     RECT  37.08 6.845 41.994 7.051 ;
     RECT  61.815 6.961 62.73 7.051 ;
     RECT  70.776 6.925 70.794 7.051 ;
     RECT  45.615 6.961 46.638 7.079 ;
     RECT  70.704 7.051 70.794 7.079 ;
     RECT  45.615 7.079 45.897 7.087 ;
     RECT  37.044 7.051 41.994 7.115 ;
     RECT  52.416 6.817 52.434 7.115 ;
     RECT  61.776 7.051 62.73 7.115 ;
     RECT  51.015 4.487 51.297 7.123 ;
     RECT  45.612 7.087 45.897 7.133 ;
     RECT  2.415 6.511 4.086 7.147 ;
     RECT  61.776 7.115 62.154 7.187 ;
     RECT  82.656 6.817 83.898 7.187 ;
     RECT  2.304 7.147 4.086 7.195 ;
     RECT  4.896 7.087 4.914 7.195 ;
     RECT  37.044 7.115 41.886 7.195 ;
     RECT  43.704 6.809 43.722 7.223 ;
     RECT  50.724 7.123 51.297 7.223 ;
     RECT  72.615 6.781 72.954 7.223 ;
     RECT  36.972 7.195 41.886 7.231 ;
     RECT  46.764 7.123 46.782 7.259 ;
     RECT  63.072 7.231 63.306 7.277 ;
     RECT  2.304 7.195 4.914 7.349 ;
     RECT  53.928 7.195 53.946 7.349 ;
     RECT  63.072 7.277 63.09 7.349 ;
     RECT  70.704 7.079 70.722 7.349 ;
     RECT  4.716 7.349 4.914 7.385 ;
     RECT  61.776 7.187 62.097 7.385 ;
     RECT  82.62 7.231 82.638 7.385 ;
     RECT  64.224 6.845 64.242 7.421 ;
     RECT  4.716 7.385 4.734 7.469 ;
     RECT  36.936 7.231 41.886 7.771 ;
     RECT  2.304 7.349 3.87 7.799 ;
     RECT  36.54 7.771 41.886 7.861 ;
     RECT  72.615 7.223 72.897 8.131 ;
     RECT  61.815 7.385 62.097 8.203 ;
     RECT  83.415 7.187 83.898 8.275 ;
     RECT  2.415 7.799 3.87 8.311 ;
     RECT  30.528 8.167 30.546 8.311 ;
     RECT  61.815 8.203 62.154 8.311 ;
     RECT  83.196 8.275 83.898 8.311 ;
     RECT  30.42 8.311 30.546 8.429 ;
     RECT  33.372 8.041 33.39 8.429 ;
     RECT  72.615 8.131 72.954 8.429 ;
     RECT  2.415 8.311 4.014 8.465 ;
     RECT  61.815 8.311 62.694 8.465 ;
     RECT  83.196 8.311 84.042 8.537 ;
     RECT  43.308 8.311 43.326 8.635 ;
     RECT  72.615 8.429 72.897 8.671 ;
     RECT  52.74 8.473 52.758 8.735 ;
     RECT  85.464 4.991 85.482 8.735 ;
     RECT  82.152 8.671 82.674 8.771 ;
     RECT  36.54 7.861 42.282 8.779 ;
     RECT  36.54 8.779 42.318 8.851 ;
     RECT  43.2 8.635 43.326 8.851 ;
     RECT  61.815 8.465 62.154 8.851 ;
     RECT  36.54 8.851 43.326 8.879 ;
     RECT  2.415 8.465 3.582 8.923 ;
     RECT  36.54 8.879 42.75 8.969 ;
     RECT  61.524 8.851 62.154 8.969 ;
     RECT  72.468 8.671 72.897 8.969 ;
     RECT  58.716 8.779 58.734 9.005 ;
     RECT  82.296 8.771 82.674 9.005 ;
     RECT  36.54 8.969 42.318 9.049 ;
     RECT  74.664 8.977 74.682 9.077 ;
     RECT  36.396 9.049 42.318 9.121 ;
     RECT  43.632 9.121 43.794 9.239 ;
     RECT  36.36 9.121 42.318 9.275 ;
     RECT  36.36 9.275 42.066 9.283 ;
     RECT  36.324 9.283 42.066 9.391 ;
     RECT  72.615 8.969 72.897 9.481 ;
     RECT  44.568 9.391 44.586 9.509 ;
     RECT  53.46 9.121 53.478 9.509 ;
     RECT  61.815 8.969 62.154 9.517 ;
     RECT  63.072 8.851 63.09 9.517 ;
     RECT  82.656 9.005 82.674 9.581 ;
     RECT  85.356 9.211 85.374 9.581 ;
     RECT  54.72 9.517 54.738 9.617 ;
     RECT  61.815 9.517 63.09 9.638 ;
     RECT  61.815 9.638 63.198 9.661 ;
     RECT  2.304 8.923 3.582 9.689 ;
     RECT  61.815 9.661 64.242 9.779 ;
     RECT  72.615 9.481 72.954 9.815 ;
     RECT  36.108 9.391 42.066 9.895 ;
     RECT  2.376 9.689 3.582 9.923 ;
     RECT  64.224 9.779 64.242 9.923 ;
     RECT  36 9.895 42.066 10.085 ;
     RECT  36.144 10.085 42.066 10.201 ;
     RECT  2.376 9.923 3.546 10.319 ;
     RECT  4.392 10.165 4.41 10.319 ;
     RECT  29.415 2.413 29.697 10.327 ;
     RECT  43.632 9.239 43.65 10.327 ;
     RECT  36.144 10.201 42.57 10.363 ;
     RECT  34.815 5.567 35.097 10.399 ;
     RECT  67.215 6.539 67.497 10.399 ;
     RECT  29.415 10.327 30.15 10.435 ;
     RECT  45.615 7.133 45.897 10.471 ;
     RECT  73.692 10.021 73.71 10.471 ;
     RECT  36.144 10.363 42.786 10.499 ;
     RECT  45 10.471 45.897 10.561 ;
     RECT  73.692 10.471 73.818 10.561 ;
     RECT  29.415 10.435 30.798 10.589 ;
     RECT  44.712 10.561 45.897 10.589 ;
     RECT  61.815 9.779 63.342 10.589 ;
     RECT  54.468 10.327 54.486 10.597 ;
     RECT  73.692 10.561 74.07 10.625 ;
     RECT  54.36 10.597 54.738 10.669 ;
     RECT  34.776 10.399 35.097 10.697 ;
     RECT  36.144 10.499 41.958 10.733 ;
     RECT  64.692 10.471 64.71 10.741 ;
     RECT  53.856 10.669 54.81 10.769 ;
     RECT  31.896 10.669 31.914 10.859 ;
     RECT  51.015 7.223 51.297 10.867 ;
     RECT  53.856 10.769 53.874 10.895 ;
     RECT  74.052 10.625 74.07 10.895 ;
     RECT  50.796 10.867 51.297 10.903 ;
     RECT  46.728 10.831 46.746 10.931 ;
     RECT  64.116 10.741 64.962 10.931 ;
     RECT  64.116 10.931 64.89 10.967 ;
     RECT  2.415 10.319 3.546 11.011 ;
     RECT  44.712 10.589 44.73 11.011 ;
     RECT  83.415 8.537 84.042 11.011 ;
     RECT  30.78 10.589 30.798 11.039 ;
     RECT  43.596 10.327 43.65 11.039 ;
     RECT  43.632 11.039 43.65 11.069 ;
     RECT  44.568 11.011 44.73 11.069 ;
     RECT  61.815 10.589 62.802 11.129 ;
     RECT  64.116 10.967 64.566 11.129 ;
     RECT  64.116 11.129 64.35 11.131 ;
     RECT  61.815 11.129 62.73 11.165 ;
     RECT  82.836 11.011 84.042 11.165 ;
     RECT  63.648 11.131 64.35 11.171 ;
     RECT  44.568 11.069 44.586 11.237 ;
     RECT  2.415 11.011 4.086 11.272 ;
     RECT  64.116 11.171 64.35 11.273 ;
     RECT  2.304 11.272 4.086 11.275 ;
     RECT  50.724 10.903 51.297 11.309 ;
     RECT  66.672 10.399 67.497 11.309 ;
     RECT  36.144 10.733 41.634 11.551 ;
     RECT  36.036 11.551 41.67 11.669 ;
     RECT  45.615 10.589 45.897 11.749 ;
     RECT  65.484 11.749 65.502 11.785 ;
     RECT  5.292 11.785 5.31 11.821 ;
     RECT  36.108 11.669 41.67 11.821 ;
     RECT  65.484 11.785 65.646 11.821 ;
     RECT  53.028 11.551 53.046 11.939 ;
     RECT  74.34 11.641 74.358 11.939 ;
     RECT  83.415 11.165 84.042 11.939 ;
     RECT  64.332 11.273 64.35 11.975 ;
     RECT  65.412 11.821 65.646 11.975 ;
     RECT  82.62 11.821 82.638 11.975 ;
     RECT  36.108 11.821 42.21 11.981 ;
     RECT  65.628 11.975 65.646 11.981 ;
     RECT  45.615 11.749 46.602 12.055 ;
     RECT  5.292 11.821 5.706 12.091 ;
     RECT  34.815 10.697 35.097 12.091 ;
     RECT  36.684 11.981 42.21 12.091 ;
     RECT  43.956 12.055 43.974 12.091 ;
     RECT  36.684 12.091 43.974 12.119 ;
     RECT  2.304 11.275 4.23 12.181 ;
     RECT  5.292 12.091 5.742 12.209 ;
     RECT  34.776 12.091 35.097 12.209 ;
     RECT  38.916 12.119 43.974 12.217 ;
     RECT  6.48 12.091 6.822 12.281 ;
     RECT  38.916 12.217 44.118 12.325 ;
     RECT  44.928 12.055 46.602 12.325 ;
     RECT  6.48 12.281 6.498 12.353 ;
     RECT  67.215 11.309 67.497 12.451 ;
     RECT  2.304 12.181 4.338 12.551 ;
     RECT  2.415 12.551 4.338 12.631 ;
     RECT  47.952 12.595 47.97 12.631 ;
     RECT  67.215 12.451 67.554 12.631 ;
     RECT  38.916 12.325 46.602 12.715 ;
     RECT  47.412 12.631 47.97 12.715 ;
     RECT  38.916 12.715 47.97 12.721 ;
     RECT  67.215 12.631 67.662 12.749 ;
     RECT  67.215 12.749 67.554 12.785 ;
     RECT  36.684 12.119 38.178 12.793 ;
     RECT  51.015 11.309 51.297 12.793 ;
     RECT  54.72 12.631 54.738 12.793 ;
     RECT  50.724 12.793 51.297 12.829 ;
     RECT  36.576 12.793 38.178 12.901 ;
     RECT  52.092 12.631 52.434 12.901 ;
     RECT  53.172 12.631 53.19 12.901 ;
     RECT  36.504 12.901 38.178 12.941 ;
     RECT  36.576 12.941 38.178 13.027 ;
     RECT  38.916 12.721 48.51 13.027 ;
     RECT  50.148 12.829 51.297 13.027 ;
     RECT  52.092 12.901 53.334 13.027 ;
     RECT  56.415 2.413 56.697 13.027 ;
     RECT  0.108 12.859 0.126 13.037 ;
     RECT  54.144 12.793 54.738 13.063 ;
     RECT  83.415 11.939 83.697 13.063 ;
     RECT  2.415 12.631 5.238 13.085 ;
     RECT  36.576 13.027 48.51 13.091 ;
     RECT  50.148 13.027 53.334 13.091 ;
     RECT  54.144 13.063 54.882 13.135 ;
     RECT  55.98 13.027 56.697 13.147 ;
     RECT  55.98 13.147 56.754 13.171 ;
     RECT  83.268 13.063 83.697 13.171 ;
     RECT  42.264 13.091 48.51 13.261 ;
     RECT  54.144 13.135 55.026 13.261 ;
     RECT  55.944 13.171 56.898 13.261 ;
     RECT  83.268 13.171 83.898 13.297 ;
     RECT  2.415 13.085 4.59 13.325 ;
     RECT  69.156 12.991 69.174 13.325 ;
     RECT  57.708 13.099 57.726 13.397 ;
     RECT  42.264 13.261 49.014 13.405 ;
     RECT  50.148 13.091 52.758 13.405 ;
     RECT  54.144 13.261 56.898 13.405 ;
     RECT  36.576 13.091 41.526 13.433 ;
     RECT  54.072 13.405 56.898 13.433 ;
     RECT  56.34 13.433 56.898 13.441 ;
     RECT  83.232 13.297 83.898 13.441 ;
     RECT  36.576 13.433 40.878 13.469 ;
     RECT  69.264 13.369 69.282 13.469 ;
     RECT  4.284 13.325 4.59 13.559 ;
     RECT  37.008 13.469 40.878 13.559 ;
     RECT  42.264 13.405 52.758 13.559 ;
     RECT  54.072 13.433 55.566 13.559 ;
     RECT  70.092 13.171 70.11 13.559 ;
     RECT  37.008 13.559 40.77 13.595 ;
     RECT  56.34 13.441 57.33 13.595 ;
     RECT  50.832 13.559 52.758 13.631 ;
     RECT  70.668 13.567 70.722 13.667 ;
     RECT  37.008 13.595 40.497 13.709 ;
     RECT  67.215 12.785 67.497 13.711 ;
     RECT  42.264 13.559 48.978 13.829 ;
     RECT  82.98 13.441 83.898 13.837 ;
     RECT  51.015 13.631 52.758 13.853 ;
     RECT  54.54 13.559 55.566 13.853 ;
     RECT  4.284 13.559 4.518 13.865 ;
     RECT  42.264 13.829 48.87 13.865 ;
     RECT  56.34 13.595 56.697 13.865 ;
     RECT  82.656 13.837 83.898 13.865 ;
     RECT  52.164 13.853 52.254 13.901 ;
     RECT  82.656 13.865 83.697 13.937 ;
     RECT  5.364 13.711 5.382 13.973 ;
     RECT  54.936 13.853 55.566 13.973 ;
     RECT  82.656 13.937 82.674 13.981 ;
     RECT  55.548 13.973 55.566 14.009 ;
     RECT  52.236 13.901 52.254 14.099 ;
     RECT  67.215 13.711 67.842 14.099 ;
     RECT  42.264 13.865 48.546 14.135 ;
     RECT  53.208 13.981 53.226 14.135 ;
     RECT  82.548 13.981 82.674 14.135 ;
     RECT  70.668 13.667 70.686 14.207 ;
     RECT  37.008 13.709 37.35 14.251 ;
     RECT  38.16 13.709 40.497 14.341 ;
     RECT  42.264 14.135 43.686 14.341 ;
     RECT  38.16 14.341 41.13 14.413 ;
     RECT  36.324 14.251 37.35 14.485 ;
     RECT  38.16 14.413 41.274 14.485 ;
     RECT  42.192 14.341 43.686 14.485 ;
     RECT  2.415 13.325 3.438 14.521 ;
     RECT  29.415 10.589 29.697 14.611 ;
     RECT  4.644 14.485 4.662 14.639 ;
     RECT  29.415 14.611 29.934 14.669 ;
     RECT  36.324 14.485 43.686 14.755 ;
     RECT  2.415 14.521 3.87 14.779 ;
     RECT  36.036 14.755 43.686 14.881 ;
     RECT  44.496 14.135 48.546 14.881 ;
     RECT  67.215 14.099 67.497 14.881 ;
     RECT  36.036 14.881 48.546 14.989 ;
     RECT  49.392 14.881 49.41 14.989 ;
     RECT  51.015 13.853 51.297 15.025 ;
     RECT  34.815 12.209 35.097 15.061 ;
     RECT  36.036 14.989 49.41 15.061 ;
     RECT  50.472 15.025 51.297 15.061 ;
     RECT  82.656 14.135 82.674 15.061 ;
     RECT  83.415 13.937 83.697 15.061 ;
     RECT  2.376 14.779 3.87 15.179 ;
     RECT  34.776 15.061 35.097 15.179 ;
     RECT  66.744 14.881 67.497 15.179 ;
     RECT  82.656 15.061 83.697 15.215 ;
     RECT  36.036 15.061 51.297 15.251 ;
     RECT  2.415 15.179 3.87 15.259 ;
     RECT  66.888 15.179 67.497 15.287 ;
     RECT  5.4 15.259 5.418 15.331 ;
     RECT  0.108 15.259 0.126 15.389 ;
     RECT  82.656 15.215 82.674 15.421 ;
     RECT  54.432 15.295 54.45 15.449 ;
     RECT  61.815 11.165 62.097 15.493 ;
     RECT  5.04 15.331 5.418 15.565 ;
     RECT  36.036 15.251 49.338 15.593 ;
     RECT  82.332 15.421 82.674 15.593 ;
     RECT  56.415 13.865 56.697 15.601 ;
     RECT  64.872 15.529 64.89 15.601 ;
     RECT  83.415 15.215 83.697 15.601 ;
     RECT  54.72 15.529 54.738 15.629 ;
     RECT  64.8 15.601 64.89 15.629 ;
     RECT  2.415 15.259 4.194 15.691 ;
     RECT  5.04 15.565 5.598 15.691 ;
     RECT  78.015 4.559 78.297 15.691 ;
     RECT  36.036 15.593 48.618 15.719 ;
     RECT  59.292 15.529 59.31 15.719 ;
     RECT  69.984 15.601 70.002 15.719 ;
     RECT  36.036 15.719 48.546 15.755 ;
     RECT  82.44 15.593 82.674 15.755 ;
     RECT  36.036 15.755 39.33 15.787 ;
     RECT  40.14 15.755 48.546 15.827 ;
     RECT  61.815 15.493 62.766 15.827 ;
     RECT  82.656 15.755 82.674 15.827 ;
     RECT  63.936 15.643 63.954 15.871 ;
     RECT  64.8 15.629 64.818 15.871 ;
     RECT  78.015 15.691 78.678 15.899 ;
     RECT  2.415 15.691 5.598 15.989 ;
     RECT  63.936 15.871 64.818 15.989 ;
     RECT  35.964 15.787 39.33 15.997 ;
     RECT  2.415 15.989 4.626 16.013 ;
     RECT  63.936 15.989 64.674 16.025 ;
     RECT  73.8 15.691 73.818 16.025 ;
     RECT  67.215 15.287 67.497 16.033 ;
     RECT  70.704 15.727 70.722 16.033 ;
     RECT  50.472 15.251 51.297 16.069 ;
     RECT  56.415 15.601 57.222 16.069 ;
     RECT  57.996 15.871 58.014 16.069 ;
     RECT  4.536 16.013 4.626 16.133 ;
     RECT  63.936 16.025 64.098 16.133 ;
     RECT  66.6 16.033 67.497 16.133 ;
     RECT  53.352 15.565 53.37 16.141 ;
     RECT  63.072 15.979 63.09 16.141 ;
     RECT  63.936 16.133 64.026 16.141 ;
     RECT  50.472 16.069 51.534 16.169 ;
     RECT  70.704 16.033 70.794 16.169 ;
     RECT  72.615 9.815 72.897 16.231 ;
     RECT  56.415 16.069 57.258 16.259 ;
     RECT  63.072 16.141 64.026 16.259 ;
     RECT  66.672 16.133 67.497 16.259 ;
     RECT  56.415 16.259 56.697 16.267 ;
     RECT  83.415 15.601 84.042 16.295 ;
     RECT  50.472 16.169 51.297 16.331 ;
     RECT  70.704 16.169 70.722 16.331 ;
     RECT  57.996 16.069 58.734 16.367 ;
     RECT  83.415 16.295 83.898 16.375 ;
     RECT  56.052 16.267 56.697 16.411 ;
     RECT  35.928 15.997 39.33 16.439 ;
     RECT  53.064 16.141 53.37 16.439 ;
     RECT  53.064 16.439 53.082 16.445 ;
     RECT  40.176 15.827 48.546 16.501 ;
     RECT  55.98 16.411 56.697 16.529 ;
     RECT  72.615 16.231 73.386 16.565 ;
     RECT  0.54 15.871 0.558 16.589 ;
     RECT  54.108 16.267 54.126 16.601 ;
     RECT  57.996 16.367 58.014 16.601 ;
     RECT  63.36 16.259 64.026 16.601 ;
     RECT  50.544 16.331 51.297 16.673 ;
     RECT  34.815 15.179 35.097 16.681 ;
     RECT  35.928 16.439 37.566 16.681 ;
     RECT  38.304 16.439 39.33 16.681 ;
     RECT  40.176 16.501 49.05 16.681 ;
     RECT  34.815 16.681 37.566 16.733 ;
     RECT  38.304 16.681 49.05 16.733 ;
     RECT  83.232 16.375 83.898 16.907 ;
     RECT  38.376 16.733 49.05 16.915 ;
     RECT  64.656 17.035 64.674 17.041 ;
     RECT  55.116 17.035 55.134 17.105 ;
     RECT  56.088 16.529 56.697 17.105 ;
     RECT  64.656 17.041 65.538 17.105 ;
     RECT  2.415 16.013 3.798 17.149 ;
     RECT  4.608 16.133 4.626 17.149 ;
     RECT  0.108 16.951 0.126 17.165 ;
     RECT  35.928 16.733 37.566 17.185 ;
     RECT  35.928 17.185 37.638 17.213 ;
     RECT  73.8 17.041 73.818 17.221 ;
     RECT  59.868 17.041 59.886 17.339 ;
     RECT  63.288 17.041 63.306 17.375 ;
     RECT  73.8 17.221 73.926 17.375 ;
     RECT  2.415 17.149 4.626 17.419 ;
     RECT  83.415 16.907 83.898 17.491 ;
     RECT  2.415 17.419 4.662 17.609 ;
     RECT  36 17.213 37.638 17.617 ;
     RECT  38.376 16.915 49.554 17.617 ;
     RECT  36 17.617 49.554 17.689 ;
     RECT  0.54 17.653 0.558 17.741 ;
     RECT  56.415 17.105 56.697 17.851 ;
     RECT  61.815 15.827 62.097 17.851 ;
     RECT  36 17.689 49.59 17.915 ;
     RECT  46.908 17.915 49.59 17.995 ;
     RECT  36 17.915 46.17 18.023 ;
     RECT  51.015 16.673 51.297 18.031 ;
     RECT  64.944 17.105 65.538 18.031 ;
     RECT  83.415 17.491 84.042 18.031 ;
     RECT  54.684 17.959 54.702 18.059 ;
     RECT  61.815 17.851 62.73 18.059 ;
     RECT  52.416 17.959 52.434 18.121 ;
     RECT  74.34 17.887 74.358 18.121 ;
     RECT  52.272 18.121 52.434 18.149 ;
     RECT  53.208 18.031 53.226 18.149 ;
     RECT  56.415 17.851 57.186 18.149 ;
     RECT  52.272 18.149 52.29 18.173 ;
     RECT  50.724 18.031 51.297 18.221 ;
     RECT  82.872 18.031 84.042 18.221 ;
     RECT  46.908 17.995 49.626 18.265 ;
     RECT  63.864 18.193 63.882 18.301 ;
     RECT  2.415 17.609 3.978 18.331 ;
     RECT  36 18.023 37.386 18.419 ;
     RECT  63.504 18.301 63.882 18.419 ;
     RECT  64.908 18.031 66.114 18.419 ;
     RECT  38.16 18.023 46.17 18.491 ;
     RECT  36.936 18.419 37.026 18.527 ;
     RECT  36 18.419 36.018 18.563 ;
     RECT  65.196 18.419 66.114 18.563 ;
     RECT  2.304 18.331 3.978 18.571 ;
     RECT  34.815 16.733 35.097 18.571 ;
     RECT  2.304 18.571 4.086 18.599 ;
     RECT  36.936 18.527 36.954 18.689 ;
     RECT  38.16 18.491 40.986 18.689 ;
     RECT  46.908 18.265 49.806 18.689 ;
     RECT  34.776 18.571 35.097 18.761 ;
     RECT  41.868 18.491 46.17 18.769 ;
     RECT  46.908 18.689 49.086 18.769 ;
     RECT  38.52 18.689 40.986 18.797 ;
     RECT  83.232 18.221 84.042 18.797 ;
     RECT  2.415 18.599 4.086 18.841 ;
     RECT  74.34 18.121 74.502 18.841 ;
     RECT  0.108 18.463 0.126 18.941 ;
     RECT  65.196 18.563 65.394 18.959 ;
     RECT  52.416 18.931 52.434 19.031 ;
     RECT  63.504 18.419 63.522 19.111 ;
     RECT  52.2 19.075 52.218 19.133 ;
     RECT  65.196 18.959 65.214 19.133 ;
     RECT  58.104 18.031 58.734 19.229 ;
     RECT  63.432 19.111 63.522 19.229 ;
     RECT  74.088 18.841 74.502 19.229 ;
     RECT  83.415 18.797 84.042 19.229 ;
     RECT  2.415 18.841 4.626 19.265 ;
     RECT  63.504 19.229 63.522 19.265 ;
     RECT  82.512 19.111 82.53 19.265 ;
     RECT  66.168 19.111 66.186 19.301 ;
     RECT  58.716 19.229 58.734 19.337 ;
     RECT  74.664 19.237 74.682 19.337 ;
     RECT  2.415 19.265 2.697 19.483 ;
     RECT  51.015 18.221 51.297 19.579 ;
     RECT  38.592 18.797 40.986 19.651 ;
     RECT  41.868 18.769 49.086 19.651 ;
     RECT  2.304 19.483 2.697 19.679 ;
     RECT  4.032 19.265 4.626 19.741 ;
     RECT  38.592 19.651 49.194 19.813 ;
     RECT  52.956 19.201 52.974 19.849 ;
     RECT  54.684 19.579 54.702 19.877 ;
     RECT  52.956 19.849 53.298 19.915 ;
     RECT  51.015 19.579 51.498 19.921 ;
     RECT  52.92 19.915 53.298 19.921 ;
     RECT  4.032 19.741 4.734 20.011 ;
     RECT  67.215 16.259 67.497 20.011 ;
     RECT  51.015 19.921 53.694 20.039 ;
     RECT  38.592 19.813 49.23 20.047 ;
     RECT  53.568 20.039 53.694 20.075 ;
     RECT  53.568 20.075 53.586 20.147 ;
     RECT  67.215 20.011 67.518 20.147 ;
     RECT  38.592 20.047 49.626 20.155 ;
     RECT  83.415 19.229 83.697 20.155 ;
     RECT  70.704 20.011 70.722 20.183 ;
     RECT  2.415 19.679 2.697 20.191 ;
     RECT  3.42 20.011 4.734 20.191 ;
     RECT  38.592 20.155 50.094 20.191 ;
     RECT  63.792 19.963 64.134 20.219 ;
     RECT  2.415 20.191 4.878 20.333 ;
     RECT  4.5 20.333 4.878 20.345 ;
     RECT  2.415 20.333 3.762 20.417 ;
     RECT  38.304 20.191 50.094 20.443 ;
     RECT  4.5 20.345 4.554 20.489 ;
     RECT  38.196 20.443 50.094 20.489 ;
     RECT  63.792 20.219 63.81 20.525 ;
     RECT  83.415 20.155 84.042 20.579 ;
     RECT  83.415 20.579 83.898 20.615 ;
     RECT  4.536 20.489 4.554 20.651 ;
     RECT  51.015 20.039 52.578 20.723 ;
     RECT  38.304 20.489 50.094 20.759 ;
     RECT  39.816 20.759 50.094 20.821 ;
     RECT  51.015 20.723 51.57 20.821 ;
     RECT  52.344 20.723 52.578 21.091 ;
     RECT  52.344 21.091 53.082 21.115 ;
     RECT  52.344 21.115 53.73 21.155 ;
     RECT  85.464 9.823 85.482 21.155 ;
     RECT  39.816 20.821 51.57 21.227 ;
     RECT  2.415 20.417 3.618 21.259 ;
     RECT  38.304 20.759 39.078 21.263 ;
     RECT  53.064 21.155 53.73 21.271 ;
     RECT  54.684 21.163 54.702 21.271 ;
     RECT  39.816 21.227 46.026 21.299 ;
     RECT  37.584 21.271 37.602 21.341 ;
     RECT  46.764 21.227 51.57 21.389 ;
     RECT  68.94 21.127 68.958 21.389 ;
     RECT  70.704 21.361 70.722 21.397 ;
     RECT  46.764 21.389 51.462 21.425 ;
     RECT  53.064 21.271 54.702 21.425 ;
     RECT  39.816 21.299 45.897 21.461 ;
     RECT  46.764 21.425 51.297 21.461 ;
     RECT  53.316 21.425 54.702 21.497 ;
     RECT  83.415 20.615 83.826 21.505 ;
     RECT  41.364 21.461 45.897 21.533 ;
     RECT  70.596 21.397 70.722 21.533 ;
     RECT  2.304 21.259 3.618 21.569 ;
     RECT  50.724 21.461 51.297 21.569 ;
     RECT  53.316 21.497 54.054 21.569 ;
     RECT  85.356 21.451 85.374 21.731 ;
     RECT  34.815 18.761 35.097 21.739 ;
     RECT  38.376 21.263 39.078 21.811 ;
     RECT  39.816 21.461 40.497 21.811 ;
     RECT  34.776 21.739 35.097 21.839 ;
     RECT  4.428 21.361 4.446 21.901 ;
     RECT  4.428 21.901 4.59 21.931 ;
     RECT  2.415 21.569 3.618 21.965 ;
     RECT  3.42 21.965 3.618 21.979 ;
     RECT  4.392 21.931 4.59 21.979 ;
     RECT  38.376 21.811 40.497 22.013 ;
     RECT  41.868 21.533 45.897 22.027 ;
     RECT  46.764 21.461 49.59 22.027 ;
     RECT  83.415 21.505 84.042 22.081 ;
     RECT  6.804 21.469 6.822 22.109 ;
     RECT  64.8 22.081 64.818 22.171 ;
     RECT  82.764 22.081 84.042 22.199 ;
     RECT  3.42 21.979 4.59 22.219 ;
     RECT  38.88 22.013 40.497 22.235 ;
     RECT  82.764 22.199 83.697 22.235 ;
     RECT  41.868 22.027 49.59 22.279 ;
     RECT  2.415 21.965 2.697 22.411 ;
     RECT  3.42 22.219 4.698 22.441 ;
     RECT  41.868 22.279 49.878 22.469 ;
     RECT  64.656 22.171 64.818 22.469 ;
     RECT  64.656 22.469 64.674 22.505 ;
     RECT  6.84 22.351 6.858 22.577 ;
     RECT  42.768 22.469 49.878 22.621 ;
     RECT  51.015 21.569 51.297 22.621 ;
     RECT  2.304 22.411 2.697 22.649 ;
     RECT  2.415 22.649 2.697 22.711 ;
     RECT  3.42 22.441 5.202 22.711 ;
     RECT  42.768 22.621 51.297 22.711 ;
     RECT  67.215 20.147 67.497 22.747 ;
     RECT  2.415 22.711 5.202 22.775 ;
     RECT  41.868 22.469 41.886 22.781 ;
     RECT  2.415 22.775 4.842 22.919 ;
     RECT  2.415 22.919 4.266 23.045 ;
     RECT  0.108 21.835 0.126 23.069 ;
     RECT  54.576 23.125 54.594 23.161 ;
     RECT  83.415 22.235 83.697 23.161 ;
     RECT  42.768 22.711 51.858 23.189 ;
     RECT  53.676 22.981 53.694 23.251 ;
     RECT  54.504 23.161 55.134 23.251 ;
     RECT  68.796 22.981 68.814 23.279 ;
     RECT  43.452 23.189 51.858 23.315 ;
     RECT  53.676 23.251 55.134 23.315 ;
     RECT  43.884 23.315 51.858 23.371 ;
     RECT  53.676 23.315 55.062 23.431 ;
     RECT  53.604 23.431 55.062 23.459 ;
     RECT  82.44 22.981 82.674 23.521 ;
     RECT  83.415 23.161 84.042 23.521 ;
     RECT  43.884 23.371 52.542 23.549 ;
     RECT  43.92 23.549 52.542 23.585 ;
     RECT  53.604 23.459 54.558 23.629 ;
     RECT  43.92 23.585 51.966 23.693 ;
     RECT  82.332 23.521 84.042 23.693 ;
     RECT  2.415 23.045 4.23 23.701 ;
     RECT  67.176 22.747 67.497 23.701 ;
     RECT  43.92 23.693 51.894 23.819 ;
     RECT  53.388 23.629 54.558 23.819 ;
     RECT  82.44 23.693 84.042 23.819 ;
     RECT  43.92 23.819 51.786 23.855 ;
     RECT  70.74 23.791 70.758 23.891 ;
     RECT  2.376 23.701 4.23 23.899 ;
     RECT  43.92 23.855 51.678 23.927 ;
     RECT  82.98 23.819 84.042 23.927 ;
     RECT  53.604 23.819 53.766 24.089 ;
     RECT  54.54 23.819 54.558 24.089 ;
     RECT  2.376 23.899 4.59 24.125 ;
     RECT  85.464 22.075 85.482 24.125 ;
     RECT  53.604 24.089 53.622 24.131 ;
     RECT  83.232 23.927 84.042 24.197 ;
     RECT  66.78 23.701 67.497 24.331 ;
     RECT  4.392 24.125 4.59 24.359 ;
     RECT  4.392 24.359 4.518 24.395 ;
     RECT  43.92 23.927 51.57 24.629 ;
     RECT  43.92 24.629 51.462 24.665 ;
     RECT  66.672 24.331 67.497 24.665 ;
     RECT  85.356 24.523 85.374 24.701 ;
     RECT  43.92 24.665 46.566 24.745 ;
     RECT  2.376 24.125 3.546 24.763 ;
     RECT  43.272 24.745 46.566 24.781 ;
     RECT  42.84 24.781 46.566 24.899 ;
     RECT  2.304 24.763 3.546 24.935 ;
     RECT  26.784 24.907 26.802 25.079 ;
     RECT  40.215 22.235 40.497 25.147 ;
     RECT  58.716 25.147 58.734 25.277 ;
     RECT  56.415 18.149 56.697 25.285 ;
     RECT  57.456 25.141 57.474 25.285 ;
     RECT  56.415 25.285 57.474 25.321 ;
     RECT  83.415 24.197 84.042 25.321 ;
     RECT  43.272 24.899 46.566 25.435 ;
     RECT  47.304 24.665 51.297 25.435 ;
     RECT  2.304 24.935 3.474 25.439 ;
     RECT  54.36 25.141 54.378 25.439 ;
     RECT  56.415 25.321 58.086 25.439 ;
     RECT  70.56 25.141 70.578 25.439 ;
     RECT  56.415 25.439 57.33 25.475 ;
     RECT  58.068 25.439 58.086 25.475 ;
     RECT  83.196 25.321 84.042 25.475 ;
     RECT  4.5 24.395 4.518 25.583 ;
     RECT  54.684 25.447 54.702 25.583 ;
     RECT  70.704 25.447 70.722 25.583 ;
     RECT  38.88 22.235 39.078 25.675 ;
     RECT  40.215 25.147 40.59 25.675 ;
     RECT  65.556 25.675 65.574 25.715 ;
     RECT  4.032 25.675 4.05 25.745 ;
     RECT  38.88 25.675 40.59 25.753 ;
     RECT  43.272 25.435 51.297 25.753 ;
     RECT  38.88 25.753 40.914 25.789 ;
     RECT  38.88 25.789 41.526 25.861 ;
     RECT  6.84 25.789 6.858 25.889 ;
     RECT  74.304 25.681 74.322 25.987 ;
     RECT  0.108 25.591 0.126 25.997 ;
     RECT  53.82 25.963 53.838 26.015 ;
     RECT  65.88 25.861 66.15 26.015 ;
     RECT  82.62 25.861 82.638 26.015 ;
     RECT  38.772 25.861 41.526 26.095 ;
     RECT  38.772 26.095 41.67 26.159 ;
     RECT  65.88 26.015 65.898 26.159 ;
     RECT  2.304 25.439 3.15 26.203 ;
     RECT  42.768 25.753 51.297 26.221 ;
     RECT  74.304 25.987 74.682 26.221 ;
     RECT  52.02 25.825 52.038 26.249 ;
     RECT  59.652 26.023 59.67 26.249 ;
     RECT  42.444 26.221 51.297 26.329 ;
     RECT  54.792 25.951 54.81 26.357 ;
     RECT  65.016 25.951 65.034 26.357 ;
     RECT  31.788 24.871 31.806 26.393 ;
     RECT  38.772 26.159 39.078 26.393 ;
     RECT  4.968 25.681 4.986 26.401 ;
     RECT  40.176 26.159 41.67 26.401 ;
     RECT  42.408 26.329 51.297 26.401 ;
     RECT  63.828 26.365 63.846 26.401 ;
     RECT  83.415 25.475 84.042 26.401 ;
     RECT  52.056 26.329 52.074 26.429 ;
     RECT  57.816 26.365 57.834 26.519 ;
     RECT  74.016 26.221 74.682 26.519 ;
     RECT  83.268 26.401 84.042 26.555 ;
     RECT  4.392 26.401 4.986 26.663 ;
     RECT  58.716 26.527 58.734 26.663 ;
     RECT  74.664 26.519 74.682 26.663 ;
     RECT  2.304 26.203 3.618 26.699 ;
     RECT  56.415 25.475 56.697 26.761 ;
     RECT  61.815 18.059 62.097 26.761 ;
     RECT  40.176 26.401 51.297 26.789 ;
     RECT  63.828 26.401 64.782 26.789 ;
     RECT  27.648 26.905 27.666 27.059 ;
     RECT  64.224 26.789 64.782 27.059 ;
     RECT  2.415 26.699 3.618 27.067 ;
     RECT  4.392 26.663 4.41 27.067 ;
     RECT  2.415 27.067 4.41 27.095 ;
     RECT  73.728 26.761 73.746 27.095 ;
     RECT  56.376 26.761 56.697 27.167 ;
     RECT  64.764 27.059 64.782 27.203 ;
     RECT  30.744 26.941 30.762 27.239 ;
     RECT  51.015 26.789 51.297 27.337 ;
     RECT  61.815 26.761 62.154 27.571 ;
     RECT  63.288 26.941 63.306 27.571 ;
     RECT  72.615 16.565 72.897 27.571 ;
     RECT  40.176 26.789 50.238 27.599 ;
     RECT  51.015 27.337 51.75 27.599 ;
     RECT  56.415 27.167 56.697 27.607 ;
     RECT  47.772 27.599 50.238 27.715 ;
     RECT  51.015 27.599 51.297 27.715 ;
     RECT  2.415 27.095 4.122 27.739 ;
     RECT  61.815 27.571 63.306 27.751 ;
     RECT  83.415 26.555 84.042 27.751 ;
     RECT  2.304 27.739 4.122 27.779 ;
     RECT  4.932 27.445 4.95 27.869 ;
     RECT  47.772 27.715 51.297 27.869 ;
     RECT  56.415 27.607 57.042 27.869 ;
     RECT  72.615 27.571 73.278 27.869 ;
     RECT  82.764 27.751 84.042 27.869 ;
     RECT  2.415 27.779 4.122 27.877 ;
     RECT  61.815 27.751 63.882 27.905 ;
     RECT  82.764 27.869 83.898 27.905 ;
     RECT  2.415 27.877 4.806 27.917 ;
     RECT  38.88 26.393 39.078 27.931 ;
     RECT  61.815 27.905 63.81 27.965 ;
     RECT  38.88 27.931 39.258 27.985 ;
     RECT  40.176 27.599 46.926 27.985 ;
     RECT  63.792 27.965 63.81 28.049 ;
     RECT  38.88 27.985 46.926 28.211 ;
     RECT  61.815 27.965 62.622 28.255 ;
     RECT  5.688 27.841 5.706 28.283 ;
     RECT  38.88 28.211 42.426 28.283 ;
     RECT  43.236 28.211 46.926 28.381 ;
     RECT  47.772 27.869 49.878 28.381 ;
     RECT  57.492 28.111 57.51 28.409 ;
     RECT  0.108 28.315 0.126 28.445 ;
     RECT  53.856 28.291 53.874 28.445 ;
     RECT  61.74 28.255 62.622 28.445 ;
     RECT  42.408 28.283 42.426 28.481 ;
     RECT  52.92 28.075 52.938 28.541 ;
     RECT  53.028 28.561 53.046 28.651 ;
     RECT  53.028 28.651 53.838 28.679 ;
     RECT  50.724 27.869 51.297 28.759 ;
     RECT  38.88 28.283 41.454 28.795 ;
     RECT  56.415 27.869 56.697 28.795 ;
     RECT  38.844 28.795 41.454 28.823 ;
     RECT  2.415 27.917 4.446 28.831 ;
     RECT  43.236 28.381 49.878 28.831 ;
     RECT  50.652 28.759 51.297 28.831 ;
     RECT  52.092 28.507 52.11 28.831 ;
     RECT  82.98 27.905 83.898 28.831 ;
     RECT  38.844 28.823 39.078 28.859 ;
     RECT  53.712 28.679 53.838 28.949 ;
     RECT  69.876 28.687 69.894 28.949 ;
     RECT  43.236 28.831 52.11 28.957 ;
     RECT  42.696 28.957 52.11 28.973 ;
     RECT  53.712 28.949 53.73 28.985 ;
     RECT  82.512 28.831 83.898 28.985 ;
     RECT  85.464 25.147 85.482 28.985 ;
     RECT  2.304 28.831 4.446 29.021 ;
     RECT  56.415 28.795 57.186 29.057 ;
     RECT  70.704 28.111 70.722 29.057 ;
     RECT  42.696 28.973 51.75 29.069 ;
     RECT  56.415 29.057 56.79 29.069 ;
     RECT  3.744 29.021 4.446 29.101 ;
     RECT  3.744 29.101 4.59 29.255 ;
     RECT  54.612 29.083 54.63 29.371 ;
     RECT  3.744 29.255 4.266 29.399 ;
     RECT  67.215 24.665 67.497 29.461 ;
     RECT  52.596 29.419 52.614 29.489 ;
     RECT  54.612 29.371 54.702 29.489 ;
     RECT  67.032 29.461 67.497 29.497 ;
     RECT  2.304 29.021 2.697 29.561 ;
     RECT  39.852 28.823 41.454 29.605 ;
     RECT  83.016 28.985 83.898 29.605 ;
     RECT  39.78 29.605 41.454 29.641 ;
     RECT  54.684 29.489 54.702 29.641 ;
     RECT  67.032 29.497 68.13 29.641 ;
     RECT  83.016 29.605 84.042 29.669 ;
     RECT  54.684 29.641 55.026 29.759 ;
     RECT  67.032 29.641 68.274 29.759 ;
     RECT  67.032 29.759 68.13 29.795 ;
     RECT  54.684 29.759 54.702 29.837 ;
     RECT  83.232 29.669 84.042 29.867 ;
     RECT  38.844 28.859 39.006 29.875 ;
     RECT  39.78 29.641 41.814 29.875 ;
     RECT  42.768 29.069 51.75 29.875 ;
     RECT  3.744 29.399 3.906 30.001 ;
     RECT  2.415 29.561 2.697 30.037 ;
     RECT  3.42 30.001 3.906 30.037 ;
     RECT  84.924 29.767 84.942 30.077 ;
     RECT  2.415 30.037 3.906 30.271 ;
     RECT  38.844 29.875 51.75 30.283 ;
     RECT  34.815 21.839 35.097 30.379 ;
     RECT  52.992 29.605 53.154 30.415 ;
     RECT  38.844 30.283 52.002 30.451 ;
     RECT  52.992 30.415 53.226 30.451 ;
     RECT  34.776 30.379 35.097 30.479 ;
     RECT  2.415 30.271 4.626 30.541 ;
     RECT  38.448 30.451 52.146 30.569 ;
     RECT  2.376 30.541 4.626 30.605 ;
     RECT  42.732 30.569 51.354 30.605 ;
     RECT  52.92 30.451 53.226 30.605 ;
     RECT  41.328 30.569 41.922 30.641 ;
     RECT  38.448 30.569 40.554 30.649 ;
     RECT  41.328 30.641 41.49 30.653 ;
     RECT  54.144 30.451 54.162 30.667 ;
     RECT  52.128 30.569 52.146 30.677 ;
     RECT  38.304 30.649 40.554 30.701 ;
     RECT  42.732 30.605 50.166 30.713 ;
     RECT  52.92 30.605 52.938 30.713 ;
     RECT  54 30.667 54.162 30.721 ;
     RECT  42.732 30.713 49.914 30.797 ;
     RECT  54 30.721 54.774 30.847 ;
     RECT  68.544 30.541 68.562 30.875 ;
     RECT  67.215 29.795 67.497 30.883 ;
     RECT  52.74 30.847 52.758 30.893 ;
     RECT  58.608 30.811 58.698 30.911 ;
     RECT  42.804 30.797 49.914 30.947 ;
     RECT  53.892 30.847 54.774 30.949 ;
     RECT  53.892 30.949 54.918 30.991 ;
     RECT  82.656 30.883 82.674 30.991 ;
     RECT  42.804 30.947 49.302 31.019 ;
     RECT  43.2 31.019 49.302 31.037 ;
     RECT  43.38 31.037 49.302 31.109 ;
     RECT  53.892 30.991 55.566 31.109 ;
     RECT  66.708 30.883 67.497 31.109 ;
     RECT  82.512 30.991 82.674 31.109 ;
     RECT  54 31.109 55.566 31.145 ;
     RECT  82.512 31.109 82.53 31.145 ;
     RECT  2.376 30.605 4.518 31.181 ;
     RECT  43.596 31.109 49.302 31.217 ;
     RECT  54 31.145 55.422 31.217 ;
     RECT  58.68 30.911 58.698 31.217 ;
     RECT  2.376 31.181 2.97 31.243 ;
     RECT  54 31.217 54.018 31.253 ;
     RECT  70.704 31.117 70.722 31.253 ;
     RECT  48.42 31.217 48.798 31.289 ;
     RECT  55.404 31.217 55.422 31.289 ;
     RECT  38.952 30.701 40.554 31.351 ;
     RECT  41.328 30.653 41.346 31.351 ;
     RECT  34.815 30.479 35.097 31.423 ;
     RECT  38.952 31.351 41.346 31.423 ;
     RECT  4.824 31.459 4.986 31.495 ;
     RECT  38.952 31.423 41.634 31.495 ;
     RECT  34.776 31.423 35.097 31.523 ;
     RECT  38.952 31.495 41.994 31.531 ;
     RECT  2.304 31.243 2.97 31.565 ;
     RECT  4.824 31.495 5.058 31.685 ;
     RECT  43.596 31.217 46.674 31.757 ;
     RECT  38.952 31.531 42.138 31.765 ;
     RECT  38.484 31.765 42.138 31.801 ;
     RECT  43.596 31.757 45.954 31.867 ;
     RECT  38.484 31.801 42.57 31.891 ;
     RECT  43.56 31.867 45.954 31.891 ;
     RECT  50.22 31.801 50.238 31.904 ;
     RECT  83.415 29.867 84.042 31.919 ;
     RECT  82.188 31.801 82.206 31.955 ;
     RECT  51.015 30.605 51.297 31.963 ;
     RECT  85.464 30.667 85.482 31.991 ;
     RECT  4.932 31.685 5.058 32.035 ;
     RECT  50.976 31.963 51.297 32.071 ;
     RECT  49.824 31.904 50.238 32.161 ;
     RECT  50.976 32.071 51.426 32.161 ;
     RECT  4.932 32.035 5.49 32.189 ;
     RECT  49.824 32.161 51.426 32.189 ;
     RECT  50.76 32.189 51.426 32.333 ;
     RECT  3.708 31.181 4.014 32.341 ;
     RECT  49.824 32.189 49.95 32.341 ;
     RECT  48.708 31.289 48.798 32.431 ;
     RECT  49.644 32.341 49.95 32.431 ;
     RECT  66.456 31.891 66.474 32.431 ;
     RECT  2.304 31.565 2.754 32.443 ;
     RECT  3.6 32.341 4.014 32.443 ;
     RECT  38.484 31.891 45.954 32.443 ;
     RECT  2.304 32.443 4.014 32.459 ;
     RECT  4.932 32.189 4.95 32.477 ;
     RECT  86.292 32.467 86.31 32.525 ;
     RECT  3.42 32.459 4.014 32.611 ;
     RECT  38.196 32.443 45.954 32.611 ;
     RECT  46.764 32.341 46.782 32.611 ;
     RECT  66.384 32.431 66.474 32.611 ;
     RECT  67.215 31.109 67.497 32.611 ;
     RECT  3.42 32.611 4.878 32.729 ;
     RECT  48.708 32.431 49.95 32.729 ;
     RECT  66.384 32.611 67.497 32.729 ;
     RECT  37.548 32.611 46.782 32.737 ;
     RECT  66.384 32.729 66.402 32.765 ;
     RECT  37.224 32.737 46.782 32.773 ;
     RECT  36.288 32.611 36.306 32.809 ;
     RECT  49.212 32.729 49.95 32.873 ;
     RECT  36.252 32.809 36.306 32.881 ;
     RECT  55.044 32.845 55.062 32.881 ;
     RECT  49.608 32.873 49.662 32.909 ;
     RECT  36.252 32.881 36.378 32.971 ;
     RECT  37.116 32.773 46.782 32.971 ;
     RECT  47.844 32.431 47.862 32.971 ;
     RECT  49.644 32.909 49.662 32.999 ;
     RECT  55.044 32.881 55.674 33.007 ;
     RECT  56.415 29.069 56.697 33.007 ;
     RECT  83.415 31.919 83.697 33.007 ;
     RECT  55.044 33.007 56.697 33.035 ;
     RECT  55.116 33.035 56.697 33.053 ;
     RECT  2.304 32.459 2.697 33.071 ;
     RECT  36.252 32.971 47.862 33.079 ;
     RECT  36.18 33.079 47.862 33.115 ;
     RECT  36.072 33.115 47.862 33.151 ;
     RECT  55.656 33.053 56.697 33.269 ;
     RECT  69.48 33.151 69.498 33.269 ;
     RECT  55.944 33.269 56.697 33.305 ;
     RECT  64.944 32.971 64.962 33.305 ;
     RECT  85.356 33.115 85.374 33.341 ;
     RECT  83.415 33.007 84.042 33.385 ;
     RECT  70.704 33.241 70.722 33.413 ;
     RECT  36.072 33.151 48.006 33.449 ;
     RECT  65.052 33.349 65.07 33.449 ;
     RECT  2.376 33.071 2.697 33.511 ;
     RECT  3.42 32.729 3.438 33.511 ;
     RECT  50.76 32.333 51.297 33.511 ;
     RECT  36.072 33.449 47.034 33.583 ;
     RECT  61.815 28.445 62.097 33.583 ;
     RECT  50.688 33.511 51.297 33.611 ;
     RECT  2.376 33.511 3.438 33.629 ;
     RECT  2.415 33.629 3.438 33.691 ;
     RECT  4.212 32.729 4.878 33.691 ;
     RECT  72.615 27.869 72.897 33.781 ;
     RECT  83.232 33.385 84.042 33.781 ;
     RECT  2.415 33.691 4.878 33.809 ;
     RECT  36.036 33.583 47.034 33.809 ;
     RECT  61.815 33.583 62.694 33.809 ;
     RECT  59.868 33.511 59.886 33.845 ;
     RECT  63.216 33.817 63.234 33.869 ;
     RECT  36.036 33.809 46.206 33.953 ;
     RECT  82.548 33.781 84.042 33.953 ;
     RECT  52.596 33.511 52.614 33.989 ;
     RECT  72.615 33.781 73.17 34.079 ;
     RECT  82.656 33.953 84.042 34.079 ;
     RECT  82.656 34.079 82.674 34.115 ;
     RECT  34.815 31.523 35.097 34.195 ;
     RECT  36.036 33.953 45.897 34.195 ;
     RECT  48.132 33.643 48.15 34.205 ;
     RECT  83.415 34.079 84.042 34.349 ;
     RECT  34.815 34.195 45.897 34.429 ;
     RECT  34.632 34.429 45.897 34.493 ;
     RECT  25.992 34.357 26.01 34.501 ;
     RECT  13.215 2.413 13.497 34.591 ;
     RECT  13.104 34.591 13.497 34.637 ;
     RECT  25.992 34.501 26.334 34.733 ;
     RECT  2.415 33.809 4.662 34.861 ;
     RECT  30.456 34.771 30.474 34.889 ;
     RECT  2.376 34.861 4.662 34.961 ;
     RECT  0.108 34.795 0.126 34.973 ;
     RECT  51.015 33.611 51.297 35.131 ;
     RECT  72.615 34.079 72.897 35.131 ;
     RECT  46.764 35.125 46.782 35.165 ;
     RECT  34.815 34.493 45.897 35.167 ;
     RECT  2.376 34.961 4.374 35.195 ;
     RECT  63.432 34.795 63.45 35.195 ;
     RECT  83.415 34.349 83.697 35.203 ;
     RECT  3.456 35.195 4.374 35.231 ;
     RECT  34.815 35.167 46.062 35.267 ;
     RECT  61.815 33.809 62.097 35.311 ;
     RECT  83.415 35.203 83.826 35.311 ;
     RECT  50.688 35.131 51.297 35.339 ;
     RECT  2.376 35.195 2.697 35.371 ;
     RECT  67.215 32.729 67.497 35.401 ;
     RECT  72.615 35.131 73.17 35.401 ;
     RECT  60.444 35.131 60.462 35.465 ;
     RECT  56.415 33.305 56.697 35.509 ;
     RECT  50.724 35.339 51.297 35.537 ;
     RECT  66.708 35.401 67.497 35.537 ;
     RECT  64.368 35.311 64.386 35.545 ;
     RECT  72.615 35.401 73.278 35.573 ;
     RECT  82.656 35.437 82.674 35.581 ;
     RECT  83.415 35.311 83.898 35.581 ;
     RECT  54.144 35.131 54.162 35.609 ;
     RECT  82.44 35.581 82.674 35.609 ;
     RECT  70.704 35.509 70.722 35.699 ;
     RECT  82.44 35.609 82.458 35.735 ;
     RECT  61.815 35.311 62.73 35.807 ;
     RECT  63.576 35.311 63.594 35.807 ;
     RECT  65.7 35.545 65.718 35.807 ;
     RECT  58.716 35.779 58.734 35.843 ;
     RECT  38.376 35.267 45.897 35.879 ;
     RECT  34.815 35.267 37.458 35.899 ;
     RECT  56.088 35.509 56.697 35.941 ;
     RECT  74.664 35.707 74.682 35.941 ;
     RECT  3.456 35.231 4.23 35.969 ;
     RECT  34.524 35.899 37.458 36.049 ;
     RECT  38.376 35.879 44.838 36.049 ;
     RECT  64.368 35.545 64.674 36.049 ;
     RECT  33.084 35.947 33.102 36.077 ;
     RECT  2.304 35.371 2.697 36.085 ;
     RECT  3.456 35.969 4.086 36.085 ;
     RECT  47.916 35.419 47.934 36.085 ;
     RECT  48.888 35.581 48.906 36.085 ;
     RECT  47.916 36.085 48.906 36.113 ;
     RECT  64.116 36.049 64.674 36.113 ;
     RECT  34.524 36.049 37.53 36.121 ;
     RECT  38.304 36.049 44.838 36.121 ;
     RECT  78.015 15.899 78.297 36.121 ;
     RECT  2.304 36.085 4.086 36.149 ;
     RECT  55.764 35.941 56.697 36.239 ;
     RECT  74.196 35.941 74.682 36.239 ;
     RECT  2.415 36.149 4.086 36.275 ;
     RECT  63.036 36.121 63.054 36.275 ;
     RECT  64.116 36.113 64.602 36.275 ;
     RECT  78.015 36.121 78.678 36.275 ;
     RECT  74.664 36.239 74.682 36.347 ;
     RECT  48.42 36.113 48.906 36.391 ;
     RECT  25.956 36.121 25.974 36.419 ;
     RECT  48.42 36.391 48.942 36.509 ;
     RECT  83.415 35.581 84.042 36.509 ;
     RECT  0.108 36.391 0.126 36.557 ;
     RECT  34.524 36.121 44.838 36.625 ;
     RECT  45.615 35.879 45.897 36.625 ;
     RECT  64.512 36.275 64.602 36.895 ;
     RECT  2.415 36.275 3.438 36.907 ;
     RECT  26.784 36.787 26.802 36.959 ;
     RECT  30.78 36.751 30.798 36.959 ;
     RECT  34.524 36.625 45.897 37.021 ;
     RECT  48.924 36.509 48.942 37.037 ;
     RECT  2.376 36.907 3.438 37.147 ;
     RECT  65.52 36.931 65.538 37.165 ;
     RECT  83.415 36.509 83.898 37.165 ;
     RECT  2.304 37.147 3.438 37.201 ;
     RECT  47.304 36.907 47.322 37.201 ;
     RECT  55.224 36.895 55.35 37.201 ;
     RECT  56.415 36.239 56.697 37.201 ;
     RECT  67.215 35.537 67.497 37.201 ;
     RECT  74.448 37.021 74.466 37.201 ;
     RECT  47.304 37.201 47.466 37.291 ;
     RECT  47.304 37.291 47.538 37.319 ;
     RECT  55.224 37.201 56.697 37.319 ;
     RECT  65.484 37.165 65.646 37.319 ;
     RECT  66.492 37.201 67.497 37.319 ;
     RECT  74.448 37.201 74.574 37.327 ;
     RECT  55.224 37.319 55.242 37.355 ;
     RECT  73.764 37.327 74.574 37.355 ;
     RECT  64.512 36.895 64.638 37.363 ;
     RECT  65.484 37.319 65.61 37.363 ;
     RECT  34.524 37.021 46.17 37.391 ;
     RECT  47.52 37.319 47.538 37.391 ;
     RECT  83.088 37.165 83.898 37.427 ;
     RECT  34.815 37.391 46.17 37.463 ;
     RECT  64.512 37.363 65.61 37.471 ;
     RECT  2.304 37.201 3.618 37.499 ;
     RECT  2.415 37.499 3.618 37.589 ;
     RECT  56.052 37.319 56.697 37.589 ;
     RECT  64.332 37.471 65.61 37.589 ;
     RECT  73.764 37.355 73.782 37.589 ;
     RECT  2.415 37.589 3.438 37.625 ;
     RECT  34.815 37.463 45.897 37.625 ;
     RECT  64.548 37.589 65.61 37.625 ;
     RECT  82.44 37.471 82.458 37.625 ;
     RECT  56.124 37.589 56.697 37.661 ;
     RECT  0.54 37.561 0.558 37.757 ;
     RECT  2.415 37.625 3.366 37.859 ;
     RECT  49.896 37.597 49.914 37.859 ;
     RECT  56.415 37.661 56.697 37.867 ;
     RECT  61.815 35.807 62.097 37.939 ;
     RECT  48.96 37.975 48.978 38.045 ;
     RECT  65.592 37.625 65.61 38.045 ;
     RECT  2.415 37.859 3.15 38.129 ;
     RECT  56.415 37.867 57.078 38.129 ;
     RECT  64.548 37.625 64.566 38.129 ;
     RECT  74.628 37.831 74.646 38.129 ;
     RECT  61.815 37.939 62.73 38.165 ;
     RECT  83.196 37.427 83.898 38.165 ;
     RECT  66.528 37.319 67.497 38.201 ;
     RECT  37.404 37.625 45.897 38.281 ;
     RECT  2.415 38.129 3.114 38.299 ;
     RECT  4.392 36.931 4.41 38.371 ;
     RECT  34.815 37.625 36.486 38.407 ;
     RECT  37.404 38.281 45.918 38.407 ;
     RECT  2.052 38.299 3.114 38.471 ;
     RECT  4.068 38.371 4.662 38.471 ;
     RECT  83.232 38.165 83.898 38.507 ;
     RECT  4.464 38.471 4.662 38.551 ;
     RECT  5.94 38.479 5.958 38.551 ;
     RECT  34.815 38.407 45.918 38.785 ;
     RECT  34.815 38.785 46.422 38.821 ;
     RECT  72.615 35.573 72.897 38.911 ;
     RECT  34.776 38.821 46.422 38.939 ;
     RECT  34.776 38.939 37.062 38.975 ;
     RECT  2.304 38.471 3.114 39.019 ;
     RECT  34.776 38.975 36.09 39.047 ;
     RECT  37.944 38.939 46.422 39.047 ;
     RECT  2.304 39.019 3.15 39.055 ;
     RECT  34.776 39.047 35.097 39.083 ;
     RECT  36.864 38.975 37.062 39.083 ;
     RECT  37.98 39.047 46.422 39.083 ;
     RECT  4.464 38.551 5.958 39.091 ;
     RECT  51.015 35.537 51.297 39.091 ;
     RECT  54.684 39.019 54.702 39.091 ;
     RECT  61.815 38.165 62.097 39.091 ;
     RECT  74.376 38.641 74.394 39.091 ;
     RECT  83.415 38.507 83.898 39.091 ;
     RECT  2.304 39.055 3.438 39.119 ;
     RECT  4.464 39.091 6.21 39.119 ;
     RECT  36.072 39.047 36.09 39.119 ;
     RECT  38.268 39.083 46.422 39.119 ;
     RECT  58.716 39.019 58.734 39.119 ;
     RECT  74.376 39.091 74.538 39.181 ;
     RECT  5.22 39.119 6.21 39.209 ;
     RECT  51.015 39.091 51.858 39.209 ;
     RECT  52.812 38.911 52.83 39.209 ;
     RECT  54.684 39.091 54.738 39.209 ;
     RECT  59.58 39.091 59.598 39.209 ;
     RECT  72.396 38.911 72.897 39.209 ;
     RECT  51.015 39.209 51.297 39.217 ;
     RECT  5.22 39.209 5.238 39.245 ;
     RECT  74.376 39.181 74.682 39.245 ;
     RECT  38.268 39.119 46.35 39.281 ;
     RECT  61.776 39.091 62.097 39.281 ;
     RECT  65.268 39.091 65.286 39.289 ;
     RECT  50.904 39.217 51.297 39.293 ;
     RECT  85.464 33.739 85.482 39.293 ;
     RECT  6.192 39.209 6.21 39.317 ;
     RECT  54.72 39.209 54.738 39.317 ;
     RECT  74.664 39.245 74.682 39.317 ;
     RECT  60.84 39.055 60.858 39.341 ;
     RECT  64.404 39.289 65.286 39.341 ;
     RECT  64.404 39.341 64.422 39.479 ;
     RECT  63.288 39.181 63.306 39.515 ;
     RECT  2.415 39.119 3.438 39.523 ;
     RECT  4.176 39.289 4.194 39.523 ;
     RECT  66.06 39.361 66.078 39.623 ;
     RECT  37.044 39.083 37.062 39.659 ;
     RECT  2.415 39.523 4.194 39.749 ;
     RECT  48.348 39.901 48.366 39.979 ;
     RECT  48.204 39.979 48.366 40.055 ;
     RECT  2.415 39.749 3.402 40.075 ;
     RECT  4.536 39.865 4.554 40.091 ;
     RECT  82.044 39.991 82.062 40.091 ;
     RECT  51.015 39.293 51.297 40.099 ;
     RECT  46.8 39.979 46.89 40.171 ;
     RECT  83.415 39.091 84.042 40.171 ;
     RECT  2.304 40.075 3.402 40.199 ;
     RECT  54.252 40.135 54.27 40.205 ;
     RECT  52.884 40.171 52.902 40.289 ;
     RECT  65.772 39.901 65.79 40.289 ;
     RECT  68.472 40.027 68.49 40.289 ;
     RECT  82.188 40.171 84.042 40.289 ;
     RECT  48.708 40.171 48.87 40.325 ;
     RECT  50.724 40.099 51.297 40.325 ;
     RECT  82.836 40.289 83.697 40.325 ;
     RECT  70.74 40.261 70.758 40.361 ;
     RECT  68.616 40.297 68.634 40.397 ;
     RECT  55.188 40.171 55.206 40.433 ;
     RECT  38.268 39.281 45.897 40.469 ;
     RECT  46.728 40.171 47.034 40.469 ;
     RECT  48.708 40.325 48.726 40.469 ;
     RECT  49.608 40.369 49.626 40.469 ;
     RECT  85.5 40.405 85.518 40.541 ;
     RECT  2.415 40.199 3.402 40.651 ;
     RECT  2.415 40.651 4.086 40.829 ;
     RECT  2.415 40.829 3.51 40.939 ;
     RECT  46.728 40.469 46.782 40.945 ;
     RECT  38.592 40.469 45.897 40.973 ;
     RECT  5.04 40.873 5.058 40.981 ;
     RECT  2.376 40.939 3.51 41.009 ;
     RECT  38.628 40.973 45.897 41.009 ;
     RECT  42.804 41.009 45.897 41.035 ;
     RECT  46.62 40.945 46.782 41.035 ;
     RECT  47.808 40.171 47.97 41.035 ;
     RECT  61.815 39.281 62.097 41.071 ;
     RECT  51.015 40.325 51.297 41.083 ;
     RECT  38.628 41.009 42.066 41.099 ;
     RECT  38.628 41.099 41.13 41.135 ;
     RECT  85.464 41.083 85.482 41.135 ;
     RECT  38.628 41.135 40.842 41.243 ;
     RECT  42.804 41.035 46.782 41.251 ;
     RECT  47.736 41.035 48.114 41.251 ;
     RECT  50.472 41.083 51.297 41.251 ;
     RECT  78.015 36.275 78.297 41.251 ;
     RECT  42.804 41.251 48.474 41.323 ;
     RECT  4.428 40.981 5.058 41.341 ;
     RECT  50.472 41.251 51.426 41.369 ;
     RECT  61.815 41.071 62.73 41.369 ;
     RECT  41.94 41.099 42.066 41.405 ;
     RECT  78.015 41.251 78.678 41.441 ;
     RECT  83.415 40.325 83.697 41.485 ;
     RECT  50.688 41.369 51.426 41.513 ;
     RECT  6.804 41.449 6.822 41.549 ;
     RECT  2.415 41.009 3.51 41.611 ;
     RECT  52.2 41.611 52.218 41.647 ;
     RECT  4.428 41.341 5.202 41.675 ;
     RECT  68.292 41.341 68.31 41.675 ;
     RECT  67.215 38.201 67.497 41.683 ;
     RECT  42.804 41.323 48.69 41.707 ;
     RECT  38.628 41.243 40.554 41.741 ;
     RECT  52.2 41.647 52.326 41.749 ;
     RECT  42.804 41.707 49.194 41.755 ;
     RECT  42.192 41.755 49.194 41.791 ;
     RECT  52.2 41.749 52.974 41.791 ;
     RECT  66.708 41.683 67.497 41.819 ;
     RECT  2.415 41.611 3.654 41.851 ;
     RECT  2.412 41.851 3.654 41.909 ;
     RECT  52.2 41.791 53.622 41.945 ;
     RECT  85.356 41.707 85.374 41.981 ;
     RECT  40.215 41.741 40.554 41.989 ;
     RECT  54.72 41.611 54.738 41.989 ;
     RECT  52.272 41.945 53.622 42.017 ;
     RECT  2.415 41.909 3.654 42.061 ;
     RECT  4.428 41.675 4.626 42.061 ;
     RECT  54.72 41.989 55.278 42.061 ;
     RECT  56.415 38.129 56.697 42.061 ;
     RECT  40.215 41.989 40.734 42.089 ;
     RECT  52.452 42.017 53.622 42.139 ;
     RECT  54.72 42.061 56.754 42.139 ;
     RECT  42.192 41.791 49.554 42.151 ;
     RECT  69.984 42.061 70.002 42.151 ;
     RECT  2.415 42.061 4.626 42.179 ;
     RECT  52.452 42.139 56.754 42.179 ;
     RECT  58.716 42.061 58.734 42.179 ;
     RECT  42.192 42.151 50.202 42.187 ;
     RECT  41.832 42.187 50.202 42.259 ;
     RECT  51.015 41.513 51.354 42.259 ;
     RECT  52.452 42.179 52.47 42.287 ;
     RECT  41.832 42.259 51.354 42.323 ;
     RECT  50.148 42.323 51.354 42.331 ;
     RECT  55.836 42.179 56.754 42.331 ;
     RECT  50.148 42.331 51.426 42.359 ;
     RECT  3.636 42.179 4.626 42.449 ;
     RECT  41.832 42.323 49.302 42.449 ;
     RECT  69.84 42.151 70.002 42.449 ;
     RECT  55.836 42.331 57.078 42.485 ;
     RECT  69.84 42.449 69.858 42.485 ;
     RECT  85.464 42.331 85.482 42.485 ;
     RECT  50.148 42.359 50.202 42.521 ;
     RECT  55.008 42.179 55.098 42.557 ;
     RECT  50.184 42.521 50.202 42.629 ;
     RECT  2.415 42.179 2.754 42.719 ;
     RECT  53.604 42.179 53.694 42.719 ;
     RECT  41.832 42.449 49.266 42.755 ;
     RECT  55.008 42.557 55.026 42.755 ;
     RECT  83.415 41.485 84.042 42.835 ;
     RECT  53.604 42.719 53.622 42.989 ;
     RECT  69.156 42.691 69.282 42.989 ;
     RECT  51.015 42.359 51.426 42.997 ;
     RECT  61.815 41.369 62.097 42.997 ;
     RECT  2.415 42.719 2.697 43.003 ;
     RECT  69.156 42.989 69.174 43.025 ;
     RECT  55.944 42.485 56.697 43.061 ;
     RECT  3.636 42.449 4.014 43.069 ;
     RECT  6.156 42.961 6.174 43.069 ;
     RECT  3.6 43.069 4.014 43.141 ;
     RECT  61.815 42.997 62.514 43.141 ;
     RECT  2.304 43.003 2.697 43.169 ;
     RECT  6.156 43.069 6.858 43.169 ;
     RECT  67.215 41.819 67.497 43.231 ;
     RECT  61.815 43.141 62.73 43.277 ;
     RECT  51.015 42.997 51.894 43.291 ;
     RECT  5.22 43.105 5.238 43.325 ;
     RECT  6.156 43.169 6.174 43.331 ;
     RECT  85.356 42.955 85.374 43.331 ;
     RECT  50.94 43.291 51.894 43.411 ;
     RECT  42.192 42.755 42.318 43.609 ;
     RECT  43.092 42.755 49.266 43.609 ;
     RECT  83.232 42.835 84.042 43.637 ;
     RECT  38.628 41.741 39.186 43.645 ;
     RECT  40.215 42.089 40.497 43.645 ;
     RECT  50.94 43.411 51.93 43.673 ;
     RECT  3.492 43.141 4.014 43.681 ;
     RECT  38.628 43.645 40.497 43.681 ;
     RECT  42.192 43.609 49.266 43.681 ;
     RECT  67.176 43.231 67.497 43.771 ;
     RECT  2.415 43.169 2.697 43.843 ;
     RECT  3.492 43.681 4.086 43.843 ;
     RECT  42.192 43.681 49.59 43.879 ;
     RECT  38.556 43.681 40.497 43.915 ;
     RECT  34.815 39.083 35.097 43.951 ;
     RECT  42.156 43.879 49.59 43.951 ;
     RECT  42.156 43.951 50.202 44.041 ;
     RECT  50.94 43.673 51.297 44.041 ;
     RECT  38.52 43.915 41.022 44.077 ;
     RECT  42.156 44.041 51.297 44.077 ;
     RECT  66.78 43.771 67.497 44.105 ;
     RECT  38.52 44.077 51.297 44.177 ;
     RECT  2.415 43.843 4.086 44.203 ;
     RECT  34.776 43.951 35.097 44.213 ;
     RECT  2.304 44.203 4.086 44.311 ;
     RECT  54.324 44.221 54.342 44.311 ;
     RECT  50.292 44.177 51.297 44.645 ;
     RECT  54.324 44.311 54.738 44.681 ;
     RECT  57.564 44.491 57.582 44.725 ;
     RECT  38.52 44.177 46.926 44.753 ;
     RECT  57.564 44.725 58.266 44.761 ;
     RECT  6.84 44.689 6.858 44.789 ;
     RECT  70.632 44.581 70.65 44.879 ;
     RECT  2.304 44.311 4.662 44.915 ;
     RECT  57.564 44.761 58.806 44.915 ;
     RECT  82.548 44.761 82.566 44.915 ;
     RECT  2.304 44.915 3.87 44.987 ;
     RECT  57.564 44.915 58.734 44.987 ;
     RECT  70.704 44.887 70.722 44.987 ;
     RECT  58.248 44.987 58.734 45.005 ;
     RECT  47.664 44.177 49.446 45.031 ;
     RECT  64.944 45.031 64.962 45.121 ;
     RECT  54.18 45.031 54.198 45.149 ;
     RECT  64.512 45.121 64.962 45.149 ;
     RECT  83.415 43.637 84.042 45.149 ;
     RECT  42.3 44.753 46.926 45.193 ;
     RECT  47.664 45.031 49.518 45.193 ;
     RECT  42.3 45.193 49.518 45.265 ;
     RECT  4.644 44.915 4.662 45.293 ;
     RECT  52.596 45.265 52.614 45.301 ;
     RECT  64.512 45.149 64.782 45.301 ;
     RECT  78.015 41.441 78.297 45.301 ;
     RECT  64.404 45.301 64.782 45.341 ;
     RECT  56.415 43.061 56.697 45.391 ;
     RECT  58.464 45.005 58.734 45.419 ;
     RECT  64.404 45.341 64.53 45.419 ;
     RECT  42.3 45.265 49.842 45.455 ;
     RECT  85.464 43.528 85.482 45.455 ;
     RECT  51.015 44.645 51.297 45.535 ;
     RECT  61.02 45.391 61.038 45.571 ;
     RECT  61.815 43.277 62.097 45.571 ;
     RECT  51.015 45.535 51.678 45.581 ;
     RECT  52.596 45.301 53.262 45.599 ;
     RECT  51.015 45.581 51.297 45.661 ;
     RECT  63.288 45.391 63.306 45.689 ;
     RECT  64.404 45.419 64.422 45.689 ;
     RECT  42.3 45.455 49.626 45.691 ;
     RECT  61.02 45.571 62.097 45.691 ;
     RECT  58.716 45.419 58.734 45.697 ;
     RECT  83.415 45.149 83.898 45.697 ;
     RECT  42.264 45.691 49.626 45.731 ;
     RECT  50.724 45.661 51.297 45.797 ;
     RECT  56.415 45.391 57.042 45.797 ;
     RECT  60.768 45.691 62.097 45.805 ;
     RECT  67.215 44.105 67.497 45.805 ;
     RECT  72.615 39.209 72.897 45.805 ;
     RECT  38.52 44.753 41.454 45.841 ;
     RECT  42.3 45.731 49.626 45.869 ;
     RECT  55.368 45.733 55.386 45.869 ;
     RECT  58.716 45.697 58.806 45.869 ;
     RECT  65.88 45.841 65.898 45.917 ;
     RECT  74.34 45.031 74.358 45.931 ;
     RECT  2.304 44.987 3.69 45.959 ;
     RECT  42.3 45.869 49.518 45.959 ;
     RECT  58.716 45.869 58.734 45.959 ;
     RECT  60.768 45.805 62.73 45.959 ;
     RECT  66.888 45.805 67.497 45.959 ;
     RECT  72.252 45.805 72.897 45.959 ;
     RECT  74.34 45.931 74.754 45.959 ;
     RECT  82.404 45.841 82.422 45.959 ;
     RECT  74.736 45.959 74.754 45.967 ;
     RECT  52.956 45.599 53.262 45.982 ;
     RECT  2.304 45.959 3.546 45.995 ;
     RECT  61.524 45.959 62.658 45.995 ;
     RECT  60.768 45.959 60.786 46.013 ;
     RECT  74.736 45.967 74.826 46.067 ;
     RECT  83.16 45.697 83.898 46.075 ;
     RECT  74.736 46.067 74.754 46.103 ;
     RECT  2.304 45.995 3.438 46.139 ;
     RECT  52.956 45.982 52.974 46.139 ;
     RECT  78.015 45.301 78.678 46.139 ;
     RECT  47.592 45.959 49.518 46.229 ;
     RECT  83.088 46.075 84.042 46.229 ;
     RECT  85.356 46.027 85.374 46.301 ;
     RECT  51.015 45.797 51.297 46.615 ;
     RECT  38.52 45.841 41.562 46.643 ;
     RECT  38.556 46.643 41.562 46.651 ;
     RECT  61.815 45.995 62.658 46.685 ;
     RECT  2.415 46.139 3.438 46.741 ;
     RECT  47.7 46.229 49.518 46.741 ;
     RECT  50.364 46.615 51.297 46.741 ;
     RECT  38.556 46.651 41.598 46.769 ;
     RECT  42.516 45.959 46.854 46.777 ;
     RECT  38.628 46.769 41.598 46.877 ;
     RECT  83.088 46.229 83.898 46.877 ;
     RECT  39.492 46.877 41.598 46.921 ;
     RECT  42.516 46.777 46.926 46.921 ;
     RECT  2.415 46.741 3.798 47.011 ;
     RECT  4.644 46.921 4.662 47.011 ;
     RECT  65.376 46.747 65.394 47.011 ;
     RECT  83.415 46.877 83.898 47.047 ;
     RECT  54.18 46.921 54.198 47.075 ;
     RECT  65.052 47.011 65.394 47.083 ;
     RECT  78.015 46.139 78.297 47.083 ;
     RECT  2.415 47.011 4.662 47.111 ;
     RECT  2.415 47.111 4.086 47.131 ;
     RECT  56.415 45.797 56.697 47.155 ;
     RECT  59.436 47.011 59.454 47.155 ;
     RECT  39.492 46.921 46.926 47.191 ;
     RECT  47.7 46.741 51.297 47.191 ;
     RECT  53.244 46.747 53.262 47.191 ;
     RECT  65.052 47.083 65.538 47.191 ;
     RECT  66.348 47.083 66.366 47.191 ;
     RECT  39.492 47.191 51.297 47.219 ;
     RECT  78.015 47.083 78.678 47.219 ;
     RECT  53.244 47.191 53.73 47.261 ;
     RECT  39.492 47.219 49.842 47.309 ;
     RECT  53.712 47.261 53.73 47.309 ;
     RECT  56.415 47.155 57.114 47.309 ;
     RECT  57.888 46.885 57.906 47.309 ;
     RECT  59.256 47.155 59.454 47.309 ;
     RECT  65.052 47.191 66.366 47.309 ;
     RECT  39.492 47.309 49.698 47.315 ;
     RECT  63.396 47.281 63.414 47.323 ;
     RECT  56.415 47.309 56.97 47.357 ;
     RECT  65.124 47.309 65.538 47.381 ;
     RECT  62.892 47.323 63.414 47.389 ;
     RECT  62.892 47.389 63.882 47.417 ;
     RECT  66.312 47.309 66.366 47.453 ;
     RECT  66.384 47.461 66.402 47.551 ;
     RECT  67.215 45.959 67.497 47.551 ;
     RECT  72.615 45.959 72.897 47.551 ;
     RECT  65.448 47.381 65.538 47.579 ;
     RECT  66.384 47.551 67.497 47.579 ;
     RECT  74.844 47.461 74.862 47.579 ;
     RECT  50.616 47.219 51.297 47.615 ;
     RECT  60.3 47.389 60.318 47.615 ;
     RECT  62.892 47.417 62.91 47.615 ;
     RECT  65.448 47.579 65.466 47.651 ;
     RECT  66.672 47.579 67.497 47.651 ;
     RECT  78.015 47.219 78.642 47.687 ;
     RECT  82.656 47.587 82.674 47.687 ;
     RECT  59.256 47.309 59.274 47.759 ;
     RECT  72.615 47.551 73.386 47.821 ;
     RECT  63.756 47.417 63.882 47.849 ;
     RECT  83.415 47.047 84.042 47.857 ;
     RECT  63.756 47.849 63.774 47.885 ;
     RECT  85.464 46.579 85.482 47.885 ;
     RECT  38.628 46.877 38.682 47.965 ;
     RECT  39.492 47.315 49.302 47.965 ;
     RECT  72.615 47.821 73.458 47.993 ;
     RECT  2.304 47.131 4.086 48.001 ;
     RECT  5.076 47.965 5.094 48.001 ;
     RECT  2.304 48.001 5.094 48.091 ;
     RECT  38.628 47.965 49.302 48.091 ;
     RECT  2.304 48.091 5.13 48.119 ;
     RECT  83.232 47.857 84.042 48.119 ;
     RECT  38.592 48.091 49.302 48.187 ;
     RECT  38.52 48.187 49.302 48.199 ;
     RECT  38.52 48.199 49.734 48.227 ;
     RECT  38.556 48.227 49.734 48.263 ;
     RECT  34.815 44.213 35.097 48.271 ;
     RECT  39.708 48.263 49.734 48.299 ;
     RECT  38.556 48.263 38.646 48.389 ;
     RECT  34.776 48.271 35.097 48.461 ;
     RECT  39.744 48.299 49.734 48.461 ;
     RECT  86.292 48.433 86.31 48.509 ;
     RECT  39.852 48.461 49.734 48.569 ;
     RECT  5.004 48.119 5.13 48.731 ;
     RECT  39.924 48.569 49.734 48.775 ;
     RECT  2.304 48.119 4.158 48.941 ;
     RECT  39.924 48.775 49.986 48.973 ;
     RECT  51.015 47.615 51.297 48.973 ;
     RECT  83.232 48.119 83.898 48.973 ;
     RECT  82.656 48.973 83.898 49.045 ;
     RECT  2.415 48.941 4.158 49.081 ;
     RECT  59.76 49.195 59.778 49.235 ;
     RECT  2.415 49.081 4.41 49.271 ;
     RECT  85.464 49.099 85.482 49.271 ;
     RECT  82.656 49.045 84.042 49.351 ;
     RECT  71.316 49.171 71.334 49.469 ;
     RECT  82.44 49.351 84.042 49.469 ;
     RECT  82.98 49.469 83.697 49.505 ;
     RECT  52.992 49.441 53.01 49.541 ;
     RECT  74.592 49.441 74.61 49.541 ;
     RECT  39.924 48.973 51.297 49.613 ;
     RECT  49.752 49.613 51.297 49.621 ;
     RECT  66.42 49.441 66.438 49.649 ;
     RECT  85.5 49.549 85.518 49.709 ;
     RECT  49.752 49.621 51.75 49.775 ;
     RECT  39.924 49.613 48.978 49.847 ;
     RECT  60.408 49.351 60.426 49.883 ;
     RECT  50.256 49.775 51.75 49.919 ;
     RECT  40.215 49.847 48.978 50.009 ;
     RECT  40.215 50.009 46.494 50.045 ;
     RECT  58.644 49.711 58.662 50.045 ;
     RECT  54.684 50.017 54.702 50.117 ;
     RECT  2.415 49.271 3.798 50.125 ;
     RECT  50.472 49.919 51.75 50.153 ;
     RECT  43.776 50.045 46.494 50.279 ;
     RECT  47.268 50.009 48.978 50.279 ;
     RECT  43.776 50.279 44.622 50.315 ;
     RECT  65.52 49.981 65.538 50.315 ;
     RECT  83.232 49.505 83.697 50.387 ;
     RECT  51.015 50.153 51.75 50.431 ;
     RECT  51.015 50.431 51.894 50.521 ;
     RECT  67.215 47.651 67.497 50.521 ;
     RECT  45.612 50.279 46.494 50.549 ;
     RECT  48.852 50.279 48.87 50.549 ;
     RECT  65.664 50.431 65.682 50.549 ;
     RECT  83.415 50.387 83.697 50.665 ;
     RECT  47.268 50.279 47.97 50.729 ;
     RECT  51.015 50.521 51.966 50.729 ;
     RECT  2.415 50.125 4.302 50.779 ;
     RECT  2.415 50.779 4.698 50.791 ;
     RECT  38.556 48.389 38.61 50.791 ;
     RECT  45.615 50.549 46.494 50.791 ;
     RECT  47.268 50.729 47.43 50.791 ;
     RECT  83.415 50.665 84.042 50.819 ;
     RECT  67.215 50.521 67.806 50.855 ;
     RECT  2.415 50.791 4.77 50.863 ;
     RECT  2.415 50.863 5.274 50.891 ;
     RECT  40.215 50.045 42.786 50.935 ;
     RECT  85.464 50.287 85.482 50.963 ;
     RECT  40.215 50.935 42.966 51.061 ;
     RECT  44.1 50.315 44.622 51.061 ;
     RECT  2.415 50.891 3.69 51.089 ;
     RECT  51.015 50.729 51.93 51.089 ;
     RECT  4.752 50.891 5.274 51.125 ;
     RECT  40.215 51.061 44.622 51.163 ;
     RECT  5.184 51.125 5.274 51.169 ;
     RECT  2.415 51.089 3.402 51.197 ;
     RECT  5.184 51.169 5.31 51.197 ;
     RECT  2.415 51.197 3.186 51.211 ;
     RECT  5.256 51.197 5.31 51.233 ;
     RECT  40.215 51.163 44.874 51.241 ;
     RECT  2.376 51.211 3.186 51.259 ;
     RECT  5.292 51.233 5.31 51.269 ;
     RECT  40.176 51.241 44.874 51.331 ;
     RECT  45.615 50.791 47.43 51.331 ;
     RECT  2.268 51.259 3.186 51.359 ;
     RECT  40.176 51.331 47.43 51.511 ;
     RECT  83.415 50.819 83.697 51.547 ;
     RECT  40.176 51.511 47.502 51.745 ;
     RECT  83.415 51.547 83.898 51.745 ;
     RECT  40.176 51.745 47.898 51.781 ;
     RECT  48.852 51.439 48.87 51.781 ;
     RECT  54.684 50.971 54.702 51.871 ;
     RECT  53.46 51.871 53.478 51.883 ;
     RECT  54.324 51.871 54.702 51.931 ;
     RECT  65.484 51.601 65.502 51.935 ;
     RECT  2.304 51.359 3.186 52.051 ;
     RECT  40.176 51.781 48.87 52.051 ;
     RECT  53.244 51.883 53.478 52.051 ;
     RECT  54.324 51.931 54.846 52.051 ;
     RECT  56.415 47.357 56.697 52.051 ;
     RECT  82.656 51.943 82.674 52.051 ;
     RECT  68.904 51.871 68.922 52.169 ;
     RECT  82.512 52.051 82.674 52.205 ;
     RECT  53.244 52.051 56.697 52.277 ;
     RECT  70.704 52.177 70.722 52.277 ;
     RECT  2.304 52.051 3.618 52.285 ;
     RECT  40.176 52.051 49.05 52.285 ;
     RECT  2.304 52.285 3.69 52.321 ;
     RECT  53.244 52.277 55.314 52.349 ;
     RECT  2.304 52.321 4.41 52.439 ;
     RECT  2.304 52.439 3.654 52.445 ;
     RECT  53.604 52.349 54.342 52.547 ;
     RECT  39.924 52.285 49.122 52.591 ;
     RECT  39.924 52.591 49.194 52.681 ;
     RECT  39.924 52.681 49.302 52.709 ;
     RECT  55.152 52.349 55.314 52.709 ;
     RECT  82.656 52.205 82.674 52.709 ;
     RECT  55.296 52.709 55.314 52.745 ;
     RECT  68.724 52.411 68.742 52.745 ;
     RECT  53.964 52.547 54.342 52.781 ;
     RECT  4.392 52.439 4.41 52.951 ;
     RECT  53.964 52.781 54.09 52.979 ;
     RECT  66.204 52.861 66.222 52.979 ;
     RECT  39.924 52.709 44.19 52.987 ;
     RECT  37.548 53.059 37.566 53.131 ;
     RECT  39.6 52.987 44.19 53.131 ;
     RECT  37.044 53.131 37.566 53.249 ;
     RECT  2.415 52.445 3.654 53.365 ;
     RECT  4.392 52.951 5.13 53.365 ;
     RECT  45.072 52.709 49.302 53.365 ;
     RECT  6.768 53.059 6.786 53.393 ;
     RECT  34.815 48.461 35.097 53.401 ;
     RECT  45.072 53.365 49.338 53.401 ;
     RECT  2.415 53.365 5.13 53.519 ;
     RECT  37.188 53.249 37.566 53.527 ;
     RECT  38.556 50.791 38.682 53.527 ;
     RECT  4.536 53.519 5.022 53.555 ;
     RECT  39.564 53.131 44.19 53.563 ;
     RECT  34.776 53.401 35.097 53.591 ;
     RECT  85.464 52.123 85.482 53.591 ;
     RECT  2.415 53.519 3.69 53.611 ;
     RECT  39.564 53.563 44.298 53.635 ;
     RECT  45.072 53.401 49.482 53.635 ;
     RECT  34.815 53.591 35.097 53.755 ;
     RECT  66.024 53.671 66.042 53.761 ;
     RECT  67.215 50.855 67.497 53.761 ;
     RECT  2.304 53.611 3.69 53.789 ;
     RECT  66.024 53.761 67.497 53.789 ;
     RECT  34.815 53.755 35.19 53.861 ;
     RECT  4.536 53.555 4.554 53.933 ;
     RECT  37.188 53.527 38.682 53.941 ;
     RECT  39.564 53.635 49.482 53.941 ;
     RECT  2.304 53.789 2.754 53.969 ;
     RECT  33.516 53.851 33.534 53.969 ;
     RECT  56.415 52.277 56.697 54.031 ;
     RECT  83.415 51.745 84.042 54.059 ;
     RECT  3.528 53.789 3.69 54.131 ;
     RECT  85.356 53.995 85.374 54.131 ;
     RECT  51.015 51.089 51.297 54.175 ;
     RECT  56.415 54.031 57.042 54.175 ;
     RECT  58.356 54.103 58.374 54.175 ;
     RECT  53.496 54.067 53.514 54.329 ;
     RECT  37.188 53.941 49.482 54.461 ;
     RECT  37.44 54.461 49.482 54.473 ;
     RECT  56.415 54.175 58.374 54.473 ;
     RECT  48.96 54.473 49.482 54.481 ;
     RECT  50.904 54.175 51.297 54.481 ;
     RECT  50.76 54.481 51.297 54.557 ;
     RECT  66.708 53.789 67.497 54.571 ;
     RECT  57.528 54.473 58.374 54.607 ;
     RECT  48.96 54.481 49.986 54.671 ;
     RECT  2.415 53.969 2.754 54.679 ;
     RECT  37.44 54.473 48.222 54.701 ;
     RECT  48.96 54.671 49.302 54.707 ;
     RECT  57.528 54.607 58.734 54.707 ;
     RECT  2.415 54.679 2.79 54.751 ;
     RECT  61.815 46.685 62.097 54.751 ;
     RECT  3.672 54.131 3.69 54.763 ;
     RECT  66.672 54.571 67.497 54.841 ;
     RECT  50.148 54.715 50.274 54.869 ;
     RECT  70.668 54.715 70.686 54.869 ;
     RECT  78.015 47.687 78.297 54.877 ;
     RECT  83.415 54.059 83.754 54.877 ;
     RECT  57.528 54.707 58.518 54.905 ;
     RECT  57.528 54.905 57.546 54.977 ;
     RECT  58.5 54.905 58.518 54.977 ;
     RECT  66.6 54.841 67.497 54.977 ;
     RECT  78.015 54.877 78.678 54.977 ;
     RECT  70.74 54.877 70.758 55.013 ;
     RECT  3.672 54.763 4.014 55.021 ;
     RECT  29.415 14.669 29.697 55.021 ;
     RECT  64.692 54.679 64.71 55.021 ;
     RECT  83.415 54.877 83.826 55.021 ;
     RECT  37.44 54.701 47.79 55.049 ;
     RECT  61.815 54.751 62.766 55.049 ;
     RECT  64.044 55.021 64.71 55.085 ;
     RECT  74.232 54.751 74.25 55.111 ;
     RECT  28.98 55.021 29.697 55.139 ;
     RECT  37.44 55.049 41.886 55.139 ;
     RECT  50.148 54.869 50.238 55.139 ;
     RECT  64.548 55.085 64.71 55.139 ;
     RECT  74.232 55.111 74.682 55.139 ;
     RECT  42.732 55.049 47.79 55.175 ;
     RECT  50.22 55.139 50.238 55.175 ;
     RECT  64.548 55.139 64.566 55.175 ;
     RECT  2.415 54.751 2.826 55.183 ;
     RECT  3.672 55.021 4.554 55.183 ;
     RECT  42.732 55.175 47.538 55.211 ;
     RECT  42.732 55.211 47.466 55.247 ;
     RECT  83.415 55.021 83.898 55.255 ;
     RECT  49.284 54.707 49.302 55.283 ;
     RECT  74.664 55.139 74.682 55.283 ;
     RECT  37.44 55.139 41.814 55.291 ;
     RECT  0.54 55.255 0.558 55.373 ;
     RECT  2.415 55.183 4.554 55.525 ;
     RECT  37.044 55.291 41.814 55.589 ;
     RECT  2.415 55.525 4.806 55.679 ;
     RECT  84.924 54.409 84.942 55.853 ;
     RECT  37.404 55.589 41.814 55.915 ;
     RECT  42.732 55.247 47.43 55.915 ;
     RECT  4.68 55.679 4.806 55.949 ;
     RECT  4.68 55.949 4.698 55.985 ;
     RECT  37.404 55.915 47.43 55.993 ;
     RECT  51.015 54.557 51.297 56.029 ;
     RECT  13.215 34.637 13.497 56.191 ;
     RECT  24.015 2.413 24.297 56.191 ;
     RECT  34.815 53.861 35.097 56.191 ;
     RECT  2.415 55.679 3.87 56.219 ;
     RECT  37.404 55.993 47.538 56.219 ;
     RECT  13.104 56.191 13.497 56.237 ;
     RECT  23.904 56.191 24.297 56.237 ;
     RECT  34.704 56.191 35.097 56.237 ;
     RECT  58.716 56.227 58.734 56.327 ;
     RECT  44.676 56.219 47.538 56.335 ;
     RECT  48.276 55.915 48.294 56.335 ;
     RECT  83.415 55.255 84.042 56.335 ;
     RECT  64.152 56.191 64.17 56.371 ;
     RECT  44.676 56.335 48.294 56.399 ;
     RECT  74.052 56.191 74.07 56.525 ;
     RECT  2.415 56.219 3.474 56.539 ;
     RECT  64.152 56.371 65.538 56.561 ;
     RECT  50.724 56.029 51.297 56.569 ;
     RECT  54.684 56.461 54.702 56.569 ;
     RECT  54.684 56.569 54.81 56.633 ;
     RECT  70.704 56.533 70.722 56.633 ;
     RECT  37.404 56.219 43.722 56.641 ;
     RECT  50.724 56.569 51.894 56.641 ;
     RECT  72.615 47.993 72.897 56.731 ;
     RECT  50.724 56.641 52.038 56.759 ;
     RECT  53.784 56.683 53.802 56.759 ;
     RECT  52.02 56.759 52.038 56.795 ;
     RECT  54.792 56.633 54.81 56.831 ;
     RECT  61.815 55.049 62.097 56.839 ;
     RECT  37.296 56.641 43.722 56.867 ;
     RECT  83.232 56.335 84.042 56.867 ;
     RECT  63.396 56.725 63.414 56.911 ;
     RECT  64.152 56.561 64.35 56.911 ;
     RECT  2.304 56.539 3.474 56.939 ;
     RECT  44.676 56.399 48.186 56.939 ;
     RECT  2.415 56.939 3.474 56.971 ;
     RECT  61.815 56.839 62.154 57.029 ;
     RECT  63.288 56.911 64.35 57.029 ;
     RECT  72.615 56.731 73.17 57.109 ;
     RECT  2.415 56.971 4.086 57.137 ;
     RECT  63.792 57.029 64.35 57.137 ;
     RECT  58.572 57.001 58.59 57.173 ;
     RECT  64.332 57.137 64.35 57.173 ;
     RECT  3.42 57.137 4.086 57.181 ;
     RECT  57.564 56.731 57.582 57.209 ;
     RECT  72.615 57.109 73.278 57.209 ;
     RECT  44.964 56.939 48.186 57.271 ;
     RECT  44.964 57.271 48.402 57.299 ;
     RECT  37.296 56.867 41.742 57.335 ;
     RECT  42.588 56.867 43.722 57.415 ;
     RECT  65.52 56.561 65.538 57.415 ;
     RECT  37.44 57.335 41.742 57.443 ;
     RECT  48.096 57.299 48.402 57.451 ;
     RECT  64.944 57.415 65.538 57.451 ;
     RECT  64.944 57.451 65.682 57.485 ;
     RECT  48.096 57.451 48.474 57.541 ;
     RECT  74.124 57.307 74.142 57.541 ;
     RECT  65.52 57.485 65.682 57.569 ;
     RECT  74.124 57.541 74.214 57.569 ;
     RECT  65.664 57.569 65.682 57.605 ;
     RECT  37.512 57.443 41.742 57.649 ;
     RECT  42.588 57.415 44.226 57.649 ;
     RECT  37.512 57.649 44.226 57.685 ;
     RECT  44.964 57.299 47.286 57.685 ;
     RECT  2.415 57.137 2.697 57.691 ;
     RECT  5.256 57.451 5.274 57.713 ;
     RECT  74.196 57.569 74.214 57.713 ;
     RECT  48.096 57.541 48.618 57.811 ;
     RECT  3.42 57.181 4.482 57.883 ;
     RECT  48.096 57.811 48.978 57.883 ;
     RECT  51.015 56.759 51.297 57.883 ;
     RECT  2.304 57.691 2.697 57.919 ;
     RECT  3.42 57.883 4.698 57.919 ;
     RECT  48.096 57.883 49.05 57.955 ;
     RECT  2.304 57.919 4.698 58.019 ;
     RECT  48.096 57.955 49.302 58.019 ;
     RECT  48.6 58.019 49.302 58.109 ;
     RECT  50.724 57.883 51.297 58.109 ;
     RECT  82.62 57.991 82.638 58.109 ;
     RECT  48.6 58.109 49.23 58.145 ;
     RECT  65.736 57.991 65.754 58.145 ;
     RECT  37.512 57.685 47.286 58.189 ;
     RECT  0.108 58.081 0.126 58.301 ;
     RECT  34.815 56.237 35.097 58.351 ;
     RECT  2.376 58.019 4.698 58.379 ;
     RECT  2.376 58.379 4.59 58.415 ;
     RECT  85.464 56.443 85.482 58.415 ;
     RECT  34.776 58.351 35.097 58.559 ;
     RECT  2.376 58.415 3.942 58.649 ;
     RECT  37.512 58.189 47.826 58.649 ;
     RECT  37.764 58.649 47.826 58.721 ;
     RECT  37.764 58.721 47.61 58.793 ;
     RECT  37.764 58.793 47.574 58.829 ;
     RECT  2.376 58.649 3.474 58.891 ;
     RECT  72.615 57.209 72.897 59.035 ;
     RECT  51.015 58.109 51.297 59.071 ;
     RECT  2.304 58.891 3.474 59.099 ;
     RECT  60.84 59.035 60.858 59.161 ;
     RECT  2.415 59.099 3.474 59.189 ;
     RECT  60.696 59.161 60.858 59.189 ;
     RECT  72.576 59.035 72.897 59.189 ;
     RECT  82.656 59.071 82.674 59.189 ;
     RECT  60.696 59.189 60.714 59.213 ;
     RECT  74.664 59.161 74.682 59.261 ;
     RECT  85.356 58.891 85.374 59.261 ;
     RECT  51.015 59.071 51.75 59.275 ;
     RECT  61.815 57.029 62.097 59.305 ;
     RECT  51.015 59.275 51.966 59.341 ;
     RECT  60.444 59.233 60.462 59.459 ;
     RECT  61.632 59.305 62.097 59.531 ;
     RECT  37.764 58.829 41.814 59.611 ;
     RECT  42.552 58.829 47.574 59.611 ;
     RECT  49.968 59.431 49.986 59.611 ;
     RECT  51.015 59.341 52.11 59.611 ;
     RECT  51.015 59.611 52.542 59.701 ;
     RECT  37.764 59.611 47.898 59.729 ;
     RECT  82.44 59.611 82.458 59.765 ;
     RECT  49.212 58.145 49.23 59.773 ;
     RECT  49.032 59.773 49.23 59.851 ;
     RECT  47.16 59.729 47.898 59.873 ;
     RECT  47.268 59.873 47.898 59.881 ;
     RECT  48.672 59.851 49.23 59.881 ;
     RECT  51.015 59.701 52.65 59.885 ;
     RECT  37.764 59.729 46.17 59.999 ;
     RECT  47.268 59.881 49.23 59.999 ;
     RECT  47.268 59.999 48.69 60.035 ;
     RECT  52.632 59.885 52.65 60.035 ;
     RECT  67.215 54.977 67.497 60.043 ;
     RECT  54.684 59.971 54.702 60.071 ;
     RECT  49.968 59.611 50.13 60.091 ;
     RECT  51.015 59.885 51.894 60.091 ;
     RECT  49.968 60.091 51.894 60.143 ;
     RECT  49.968 60.143 50.202 60.151 ;
     RECT  83.415 56.867 84.042 60.151 ;
     RECT  37.764 59.999 43.686 60.179 ;
     RECT  50.976 60.143 51.894 60.179 ;
     RECT  39.384 60.179 43.686 60.269 ;
     RECT  49.608 60.151 50.202 60.269 ;
     RECT  65.448 59.881 65.466 60.269 ;
     RECT  82.764 60.151 84.042 60.269 ;
     RECT  67.215 60.043 67.554 60.277 ;
     RECT  82.764 60.269 83.97 60.305 ;
     RECT  39.384 60.269 39.402 60.377 ;
     RECT  66.708 60.277 67.554 60.377 ;
     RECT  2.415 59.189 3.438 60.385 ;
     RECT  4.212 59.881 4.23 60.385 ;
     RECT  50.184 60.269 50.202 60.413 ;
     RECT  50.976 60.179 51.642 60.413 ;
     RECT  40.215 60.269 43.686 60.539 ;
     RECT  40.215 60.539 40.806 60.611 ;
     RECT  2.415 60.385 4.23 60.655 ;
     RECT  47.268 60.035 48.33 60.691 ;
     RECT  82.656 60.547 82.674 60.719 ;
     RECT  45.036 59.999 46.098 60.781 ;
     RECT  47.052 60.691 48.33 60.781 ;
     RECT  40.215 60.611 40.662 60.809 ;
     RECT  85.464 59.515 85.482 60.881 ;
     RECT  41.58 60.539 43.686 60.889 ;
     RECT  2.415 60.655 4.41 60.925 ;
     RECT  5.148 60.043 5.166 60.925 ;
     RECT  45.036 60.781 48.33 60.955 ;
     RECT  41.58 60.889 44.082 61.051 ;
     RECT  45.036 60.955 48.726 61.051 ;
     RECT  50.976 60.413 51.297 61.051 ;
     RECT  41.58 61.051 48.762 61.079 ;
     RECT  83.415 60.305 83.97 61.087 ;
     RECT  2.415 60.925 5.166 61.115 ;
     RECT  41.832 61.079 48.762 61.115 ;
     RECT  41.904 61.115 48.762 61.181 ;
     RECT  50.688 61.051 51.297 61.187 ;
     RECT  53.1 61.147 53.118 61.187 ;
     RECT  51.015 61.187 51.297 61.189 ;
     RECT  4.932 61.115 5.166 61.195 ;
     RECT  5.904 61.051 5.922 61.195 ;
     RECT  51.015 61.189 51.462 61.229 ;
     RECT  2.415 61.115 4.158 61.231 ;
     RECT  4.932 61.195 5.922 61.231 ;
     RECT  83.415 61.087 84.042 61.231 ;
     RECT  2.304 61.231 4.158 61.277 ;
     RECT  67.215 60.377 67.554 61.349 ;
     RECT  83.196 61.231 84.042 61.349 ;
     RECT  52.092 61.231 52.11 61.357 ;
     RECT  4.932 61.231 6.03 61.373 ;
     RECT  6.804 61.243 6.822 61.373 ;
     RECT  2.415 61.277 4.158 61.385 ;
     RECT  5.904 61.373 6.03 61.385 ;
     RECT  83.196 61.349 83.754 61.385 ;
     RECT  85.356 61.339 85.374 61.421 ;
     RECT  6.012 61.385 6.03 61.457 ;
     RECT  70.668 60.547 70.686 61.493 ;
     RECT  4.932 61.373 5.166 61.529 ;
     RECT  40.215 60.809 40.626 61.579 ;
     RECT  41.904 61.181 48.726 61.619 ;
     RECT  52.092 61.357 52.218 61.619 ;
     RECT  40.215 61.579 41.094 61.655 ;
     RECT  52.092 61.619 52.11 61.655 ;
     RECT  54.324 61.591 54.342 61.861 ;
     RECT  4.932 61.529 4.95 61.889 ;
     RECT  0.108 61.819 0.126 61.949 ;
     RECT  51.015 61.229 51.297 62.005 ;
     RECT  54.324 61.861 54.666 62.005 ;
     RECT  54.324 62.005 55.314 62.041 ;
     RECT  53.568 61.195 53.586 62.107 ;
     RECT  54.324 62.041 55.566 62.107 ;
     RECT  3.96 61.385 4.158 62.131 ;
     RECT  41.976 61.619 48.726 62.131 ;
     RECT  53.568 62.107 55.566 62.131 ;
     RECT  53.568 62.131 55.638 62.141 ;
     RECT  69.192 61.861 69.21 62.195 ;
     RECT  41.976 62.131 49.302 62.239 ;
     RECT  2.415 61.385 3.006 62.311 ;
     RECT  3.816 62.131 4.158 62.311 ;
     RECT  54.252 62.141 55.638 62.311 ;
     RECT  56.415 54.473 56.697 62.311 ;
     RECT  83.415 61.385 83.754 62.311 ;
     RECT  54.252 62.311 56.697 62.339 ;
     RECT  2.415 62.311 4.158 62.395 ;
     RECT  41.976 62.239 49.338 62.395 ;
     RECT  41.76 62.395 49.338 62.401 ;
     RECT  2.304 62.395 4.158 62.581 ;
     RECT  41.76 62.401 49.374 62.581 ;
     RECT  50.616 62.005 51.297 62.581 ;
     RECT  2.304 62.581 4.77 62.609 ;
     RECT  54.252 62.339 54.27 62.621 ;
     RECT  40.215 61.655 40.626 62.671 ;
     RECT  55.116 62.339 56.697 62.699 ;
     RECT  69.516 62.311 69.678 62.699 ;
     RECT  39.78 62.671 40.626 62.731 ;
     RECT  41.76 62.581 51.297 62.731 ;
     RECT  55.872 62.699 56.697 62.735 ;
     RECT  69.516 62.699 69.534 62.735 ;
     RECT  39.78 62.731 51.297 62.743 ;
     RECT  39.42 62.743 51.297 62.765 ;
     RECT  39.42 62.765 49.086 62.771 ;
     RECT  55.116 62.699 55.134 62.807 ;
     RECT  39.42 62.771 45.954 62.815 ;
     RECT  50.04 62.765 51.297 62.815 ;
     RECT  67.215 61.349 67.497 62.815 ;
     RECT  2.415 62.609 4.77 62.851 ;
     RECT  67.215 62.815 67.554 62.851 ;
     RECT  37.764 60.179 38.394 62.941 ;
     RECT  39.204 62.815 45.954 62.941 ;
     RECT  37.764 62.941 45.954 62.969 ;
     RECT  66.96 62.851 67.554 62.969 ;
     RECT  56.232 62.735 56.697 63.005 ;
     RECT  63.576 62.968 63.594 63.005 ;
     RECT  83.415 62.311 84.042 63.085 ;
     RECT  50.04 62.815 51.498 63.121 ;
     RECT  6.804 63.013 6.822 63.149 ;
     RECT  2.415 62.851 5.958 63.239 ;
     RECT  64.944 63.115 64.962 63.239 ;
     RECT  67.215 62.969 67.554 63.239 ;
     RECT  83.232 63.085 84.042 63.239 ;
     RECT  2.415 63.239 5.814 63.275 ;
     RECT  50.04 63.121 51.786 63.275 ;
     RECT  85.464 61.963 85.482 63.275 ;
     RECT  37.764 62.969 45.897 63.391 ;
     RECT  50.04 63.275 51.714 63.419 ;
     RECT  5.724 63.275 5.814 63.509 ;
     RECT  5.724 63.509 5.742 63.545 ;
     RECT  46.692 62.771 49.086 63.661 ;
     RECT  50.04 63.419 51.297 63.661 ;
     RECT  46.656 63.661 51.297 63.779 ;
     RECT  84.924 63.517 84.942 63.821 ;
     RECT  37.728 63.391 45.897 63.923 ;
     RECT  37.836 63.923 45.897 63.931 ;
     RECT  46.656 63.779 50.202 63.931 ;
     RECT  37.836 63.931 50.202 64.085 ;
     RECT  2.415 63.275 4.158 64.165 ;
     RECT  83.232 63.239 83.697 64.363 ;
     RECT  56.415 63.005 56.697 64.411 ;
     RECT  2.415 64.165 4.626 64.589 ;
     RECT  41.364 64.085 50.202 64.597 ;
     RECT  50.94 63.779 51.297 64.597 ;
     RECT  52.524 64.597 52.542 64.633 ;
     RECT  52.524 64.633 52.83 64.669 ;
     RECT  2.415 64.589 4.554 64.697 ;
     RECT  83.124 64.363 83.697 64.697 ;
     RECT  56.34 64.411 56.697 64.741 ;
     RECT  2.415 64.697 4.23 64.747 ;
     RECT  41.364 64.597 51.297 64.769 ;
     RECT  50.184 64.769 51.297 64.795 ;
     RECT  37.836 64.085 40.626 64.831 ;
     RECT  41.364 64.769 49.302 64.831 ;
     RECT  52.452 64.669 52.83 64.831 ;
     RECT  37.836 64.831 49.302 64.859 ;
     RECT  50.184 64.795 51.534 64.859 ;
     RECT  56.34 64.741 57.042 64.867 ;
     RECT  69.588 64.831 69.606 64.867 ;
     RECT  50.184 64.859 51.297 64.895 ;
     RECT  52.38 64.831 52.83 64.931 ;
     RECT  54.792 64.741 54.81 64.931 ;
     RECT  83.415 64.697 83.697 64.939 ;
     RECT  37.836 64.859 48.978 64.973 ;
     RECT  55.872 64.867 57.042 65.011 ;
     RECT  64.944 64.987 64.962 65.011 ;
     RECT  52.812 64.931 52.83 65.129 ;
     RECT  69.588 64.867 69.714 65.129 ;
     RECT  37.836 64.973 48.726 65.165 ;
     RECT  63.72 64.831 63.738 65.165 ;
     RECT  69.588 65.129 69.606 65.165 ;
     RECT  55.872 65.011 57.33 65.201 ;
     RECT  64.836 65.011 65.07 65.281 ;
     RECT  55.872 65.201 57.042 65.309 ;
     RECT  74.664 65.011 74.682 65.371 ;
     RECT  39.06 65.165 48.726 65.399 ;
     RECT  55.872 65.309 56.697 65.399 ;
     RECT  82.656 64.831 82.674 65.399 ;
     RECT  0.108 65.323 0.126 65.453 ;
     RECT  64.728 65.281 65.07 65.515 ;
     RECT  83.415 64.939 83.97 65.515 ;
     RECT  74.664 65.371 74.754 65.543 ;
     RECT  64.44 65.515 65.07 65.551 ;
     RECT  64.44 65.551 65.214 65.579 ;
     RECT  85.464 64.411 85.482 65.659 ;
     RECT  33.984 65.551 34.002 65.669 ;
     RECT  85.356 65.659 85.482 65.741 ;
     RECT  33.876 65.821 33.894 66.083 ;
     RECT  65.196 65.579 65.214 66.091 ;
     RECT  2.304 64.747 4.23 66.119 ;
     RECT  37.836 65.165 38.322 66.139 ;
     RECT  39.06 65.399 48.654 66.139 ;
     RECT  37.836 66.139 49.194 66.209 ;
     RECT  64.44 65.579 64.458 66.209 ;
     RECT  65.196 66.091 66.114 66.209 ;
     RECT  74.016 65.911 74.034 66.245 ;
     RECT  66.096 66.209 66.114 66.281 ;
     RECT  85.464 65.741 85.482 66.281 ;
     RECT  2.415 66.119 4.23 66.325 ;
     RECT  41.616 66.209 49.194 66.353 ;
     RECT  51.015 64.895 51.297 66.361 ;
     RECT  50.724 66.361 51.297 66.475 ;
     RECT  39.204 66.209 40.698 66.479 ;
     RECT  41.724 66.353 49.194 66.515 ;
     RECT  2.415 66.325 4.41 66.523 ;
     RECT  50.724 66.475 51.786 66.631 ;
     RECT  63.396 66.451 63.414 66.631 ;
     RECT  6.804 66.361 6.822 66.659 ;
     RECT  52.704 66.289 52.722 66.659 ;
     RECT  54.432 66.361 54.45 66.721 ;
     RECT  41.724 66.515 49.05 66.749 ;
     RECT  50.112 66.631 51.786 66.749 ;
     RECT  63.396 66.631 63.882 66.749 ;
     RECT  53.604 66.715 53.622 66.785 ;
     RECT  59.652 66.631 59.67 66.829 ;
     RECT  63.396 66.749 63.414 66.857 ;
     RECT  57.816 66.451 58.158 66.865 ;
     RECT  59.652 66.829 59.994 66.865 ;
     RECT  61.815 59.531 62.097 66.865 ;
     RECT  50.112 66.749 51.297 66.893 ;
     RECT  59.004 66.865 59.994 66.901 ;
     RECT  83.415 65.515 84.042 66.901 ;
     RECT  50.724 66.893 51.297 66.929 ;
     RECT  74.34 66.901 74.358 66.991 ;
     RECT  54.432 66.721 54.63 67.019 ;
     RECT  61.815 66.865 62.766 67.019 ;
     RECT  66.24 66.865 66.258 67.019 ;
     RECT  71.424 66.865 71.442 67.019 ;
     RECT  82.98 66.901 84.042 67.019 ;
     RECT  74.34 66.991 74.754 67.027 ;
     RECT  57.708 66.865 58.158 67.055 ;
     RECT  58.932 66.901 59.994 67.055 ;
     RECT  83.052 67.019 84.042 67.055 ;
     RECT  85.356 66.859 85.374 67.091 ;
     RECT  54.72 67.027 54.738 67.127 ;
     RECT  57.708 67.055 57.726 67.127 ;
     RECT  59.976 67.055 59.994 67.127 ;
     RECT  74.16 67.027 74.754 67.163 ;
     RECT  2.415 66.523 4.518 67.171 ;
     RECT  39.384 66.479 40.698 67.171 ;
     RECT  65.196 66.209 65.25 67.243 ;
     RECT  39.384 67.171 40.986 67.261 ;
     RECT  41.724 66.749 48.762 67.261 ;
     RECT  58.932 67.055 59.022 67.277 ;
     RECT  64.224 67.243 65.25 67.277 ;
     RECT  2.415 67.171 5.058 67.333 ;
     RECT  2.415 67.333 5.166 67.405 ;
     RECT  61.815 67.019 62.73 67.433 ;
     RECT  2.415 67.405 5.346 67.441 ;
     RECT  58.932 67.277 58.95 67.469 ;
     RECT  64.224 67.277 65.214 67.469 ;
     RECT  2.415 67.441 5.598 67.595 ;
     RECT  65.196 67.469 65.214 67.595 ;
     RECT  39.384 67.261 48.762 67.627 ;
     RECT  2.415 67.595 5.49 67.667 ;
     RECT  39.312 67.627 48.762 67.667 ;
     RECT  64.224 67.469 64.242 67.667 ;
     RECT  6.732 67.441 6.75 67.711 ;
     RECT  39.348 67.667 48.762 67.711 ;
     RECT  6.732 67.711 6.822 67.739 ;
     RECT  39.348 67.711 48.834 67.801 ;
     RECT  2.415 67.667 5.346 67.805 ;
     RECT  2.415 67.805 5.31 67.829 ;
     RECT  6.804 67.739 6.822 67.829 ;
     RECT  74.376 67.163 74.682 67.829 ;
     RECT  74.376 67.829 74.394 67.865 ;
     RECT  2.415 67.829 3.438 67.867 ;
     RECT  2.376 67.867 3.438 67.901 ;
     RECT  4.356 67.829 5.31 67.901 ;
     RECT  39.348 67.801 48.906 67.901 ;
     RECT  4.536 67.901 5.31 67.973 ;
     RECT  5.148 67.973 5.31 68.099 ;
     RECT  39.348 67.901 48.834 68.099 ;
     RECT  39.348 68.099 48.69 68.135 ;
     RECT  5.292 68.099 5.31 68.171 ;
     RECT  2.376 67.901 3.258 68.369 ;
     RECT  39.348 68.135 48.654 68.369 ;
     RECT  2.376 68.369 3.114 68.381 ;
     RECT  2.415 68.381 3.114 68.405 ;
     RECT  72.615 59.189 72.897 68.611 ;
     RECT  61.815 67.433 62.097 68.635 ;
     RECT  49.896 68.485 49.914 68.639 ;
     RECT  39.348 68.369 48.51 68.675 ;
     RECT  61.704 68.635 62.097 68.675 ;
     RECT  61.776 68.675 62.097 68.717 ;
     RECT  39.348 68.675 47.97 68.719 ;
     RECT  37.836 66.209 38.322 68.755 ;
     RECT  39.096 68.719 47.97 68.755 ;
     RECT  61.815 68.717 62.097 68.791 ;
     RECT  37.836 68.755 47.97 68.819 ;
     RECT  37.836 68.819 47.934 68.909 ;
     RECT  54.792 68.647 54.81 68.909 ;
     RECT  60.012 68.791 60.03 68.909 ;
     RECT  72.615 68.611 72.954 68.909 ;
     RECT  58.716 68.719 58.734 68.945 ;
     RECT  39.348 68.909 47.934 68.981 ;
     RECT  39.42 68.981 47.934 69.053 ;
     RECT  39.528 69.053 47.934 69.089 ;
     RECT  83.415 67.055 84.042 69.179 ;
     RECT  2.415 68.405 2.862 69.187 ;
     RECT  2.415 69.187 3.15 69.451 ;
     RECT  64.404 69.451 64.422 69.491 ;
     RECT  83.415 69.179 83.898 69.493 ;
     RECT  51.015 66.929 51.297 69.529 ;
     RECT  64.836 69.529 64.926 69.601 ;
     RECT  73.728 69.421 73.746 69.601 ;
     RECT  50.688 69.529 51.297 69.629 ;
     RECT  39.672 69.089 47.934 69.691 ;
     RECT  61.815 68.791 62.658 69.691 ;
     RECT  64.836 69.601 65.43 69.719 ;
     RECT  73.728 69.601 73.89 69.719 ;
     RECT  39.672 69.691 48.114 69.755 ;
     RECT  54.504 69.421 54.666 69.755 ;
     RECT  73.728 69.719 73.746 69.755 ;
     RECT  61.815 69.691 62.694 69.791 ;
     RECT  2.415 69.451 3.366 69.799 ;
     RECT  4.788 69.601 4.806 69.799 ;
     RECT  83.232 69.493 83.898 69.827 ;
     RECT  65.34 69.719 65.358 69.863 ;
     RECT  37.836 68.909 38.322 69.871 ;
     RECT  46.764 69.755 48.114 69.899 ;
     RECT  2.415 69.799 3.582 69.931 ;
     RECT  52.632 69.763 52.65 69.961 ;
     RECT  52.452 69.961 52.65 69.989 ;
     RECT  57.528 69.871 57.546 69.989 ;
     RECT  71.172 69.763 71.19 69.989 ;
     RECT  54.72 69.799 54.738 70.025 ;
     RECT  82.62 69.871 82.638 70.025 ;
     RECT  4.716 69.799 4.806 70.033 ;
     RECT  39.672 69.755 43.506 70.061 ;
     RECT  60.156 69.871 60.174 70.061 ;
     RECT  2.376 69.931 3.582 70.069 ;
     RECT  67.215 63.239 67.497 70.069 ;
     RECT  52.452 69.989 52.47 70.097 ;
     RECT  74.628 69.997 74.646 70.097 ;
     RECT  37.836 69.871 38.934 70.109 ;
     RECT  59.22 69.835 59.238 70.109 ;
     RECT  39.672 70.061 42.21 70.133 ;
     RECT  2.376 70.069 3.978 70.141 ;
     RECT  4.716 70.033 5.166 70.141 ;
     RECT  2.376 70.141 5.166 70.259 ;
     RECT  67.215 70.069 67.662 70.259 ;
     RECT  2.376 70.259 4.374 70.301 ;
     RECT  78.015 54.977 78.297 70.303 ;
     RECT  7.02 70.141 7.038 70.331 ;
     RECT  83.415 69.827 83.898 70.375 ;
     RECT  37.836 70.109 38.826 70.403 ;
     RECT  52.02 70.141 52.038 70.403 ;
     RECT  5.148 70.259 5.166 70.411 ;
     RECT  6.012 70.375 6.03 70.411 ;
     RECT  78.015 70.303 78.678 70.439 ;
     RECT  5.148 70.411 6.03 70.445 ;
     RECT  44.352 69.755 45.99 70.501 ;
     RECT  5.148 70.445 5.31 70.529 ;
     RECT  83.415 70.375 84.042 70.529 ;
     RECT  47.088 69.899 48.114 70.573 ;
     RECT  6.984 70.411 7.002 70.601 ;
     RECT  44.352 70.501 46.062 70.609 ;
     RECT  5.292 70.529 5.31 70.673 ;
     RECT  2.415 70.301 4.374 70.685 ;
     RECT  42.948 70.061 43.074 70.843 ;
     RECT  43.848 70.609 46.062 70.843 ;
     RECT  42.948 70.843 46.062 70.879 ;
     RECT  47.088 70.573 48.15 70.915 ;
     RECT  40.215 70.133 42.21 70.951 ;
     RECT  42.948 70.879 46.242 70.951 ;
     RECT  2.415 70.685 4.194 71.069 ;
     RECT  40.215 70.951 46.242 71.077 ;
     RECT  47.088 70.915 48.582 71.077 ;
     RECT  37.836 70.403 38.322 71.149 ;
     RECT  83.415 70.529 83.697 71.185 ;
     RECT  54.504 71.185 54.522 71.221 ;
     RECT  51.015 69.629 51.297 71.227 ;
     RECT  6.804 71.149 6.822 71.249 ;
     RECT  37.836 71.149 38.79 71.249 ;
     RECT  0.108 71.131 0.126 71.261 ;
     RECT  54.504 71.221 55.494 71.261 ;
     RECT  68.832 71.041 68.85 71.375 ;
     RECT  85.464 67.483 85.482 71.375 ;
     RECT  51.015 71.227 51.858 71.383 ;
     RECT  55.008 71.261 55.494 71.383 ;
     RECT  67.215 70.259 67.497 71.383 ;
     RECT  83.232 71.185 83.697 71.383 ;
     RECT  53.28 71.311 53.37 71.405 ;
     RECT  40.215 71.077 48.582 71.419 ;
     RECT  82.656 71.383 83.697 71.447 ;
     RECT  53.28 71.405 53.298 71.483 ;
     RECT  55.008 71.383 55.566 71.483 ;
     RECT  51.015 71.383 52.326 71.491 ;
     RECT  82.656 71.447 82.674 71.491 ;
     RECT  51.015 71.491 52.47 71.609 ;
     RECT  67.215 71.383 67.554 71.609 ;
     RECT  52.452 71.609 52.47 71.645 ;
     RECT  82.548 71.491 82.674 71.645 ;
     RECT  82.656 71.645 82.674 71.717 ;
     RECT  51.015 71.609 51.642 71.725 ;
     RECT  70.668 71.617 70.686 71.753 ;
     RECT  84.924 71.617 84.942 71.789 ;
     RECT  2.415 71.069 3.474 71.803 ;
     RECT  2.304 71.803 3.474 71.851 ;
     RECT  40.215 71.419 48.978 71.995 ;
     RECT  2.304 71.851 3.978 72.059 ;
     RECT  55.008 71.483 55.026 72.149 ;
     RECT  2.415 72.059 3.978 72.185 ;
     RECT  60.156 72.121 60.174 72.185 ;
     RECT  40.215 71.995 49.41 72.265 ;
     RECT  50.328 71.725 51.642 72.265 ;
     RECT  58.68 72.157 58.698 72.293 ;
     RECT  60.444 72.301 60.462 72.421 ;
     RECT  56.415 65.399 56.697 72.427 ;
     RECT  67.215 71.609 67.497 72.463 ;
     RECT  0.108 72.379 0.126 72.491 ;
     RECT  54.684 72.391 54.702 72.491 ;
     RECT  83.415 71.447 83.697 72.535 ;
     RECT  60.444 72.421 60.75 72.571 ;
     RECT  61.815 69.791 62.097 72.571 ;
     RECT  52.56 72.571 52.578 72.661 ;
     RECT  69.372 72.571 69.39 72.661 ;
     RECT  40.215 72.265 51.642 72.689 ;
     RECT  60.444 72.571 60.894 72.689 ;
     RECT  67.215 72.463 67.95 72.689 ;
     RECT  37.836 71.249 38.322 72.697 ;
     RECT  55.872 72.427 56.697 72.725 ;
     RECT  40.215 72.689 49.77 72.733 ;
     RECT  50.76 72.689 51.642 72.733 ;
     RECT  52.56 72.661 53.082 72.733 ;
     RECT  61.668 72.571 62.097 72.761 ;
     RECT  6.804 72.571 6.822 72.797 ;
     RECT  50.76 72.733 53.082 72.833 ;
     RECT  58.716 72.571 58.734 72.833 ;
     RECT  61.74 72.761 62.097 72.833 ;
     RECT  37.836 72.697 38.862 72.841 ;
     RECT  56.415 72.725 56.697 72.841 ;
     RECT  50.76 72.833 52.578 72.869 ;
     RECT  40.032 72.733 49.77 72.931 ;
     RECT  55.548 72.841 55.638 72.931 ;
     RECT  34.815 58.559 35.097 72.955 ;
     RECT  2.415 72.185 3.618 72.959 ;
     RECT  52.128 72.869 52.578 72.959 ;
     RECT  69.264 72.661 69.39 72.959 ;
     RECT  2.415 72.959 3.402 72.995 ;
     RECT  39.924 72.931 49.77 72.995 ;
     RECT  69.264 72.959 69.282 72.995 ;
     RECT  2.415 72.995 3.33 73.003 ;
     RECT  52.56 72.959 52.578 73.031 ;
     RECT  55.296 72.931 55.638 73.031 ;
     RECT  37.836 72.841 39.042 73.051 ;
     RECT  39.924 72.995 48.438 73.051 ;
     RECT  4.968 72.499 4.986 73.075 ;
     RECT  56.415 72.841 56.826 73.103 ;
     RECT  4.968 73.075 5.094 73.111 ;
     RECT  50.76 72.869 51.297 73.139 ;
     RECT  60.876 72.689 60.894 73.229 ;
     RECT  82.656 72.733 82.674 73.337 ;
     RECT  74.664 73.237 74.682 73.373 ;
     RECT  34.815 72.955 35.478 73.471 ;
     RECT  4.968 73.111 5.346 73.483 ;
     RECT  4.464 73.483 5.346 73.499 ;
     RECT  49.608 72.995 49.77 73.499 ;
     RECT  55.62 73.031 55.638 73.499 ;
     RECT  34.704 73.471 35.766 73.517 ;
     RECT  49.752 73.499 49.77 73.517 ;
     RECT  4.464 73.499 5.31 73.535 ;
     RECT  2.304 73.003 3.33 73.741 ;
     RECT  4.716 73.535 5.31 73.769 ;
     RECT  60.912 73.507 60.93 73.769 ;
     RECT  4.716 73.769 5.238 73.805 ;
     RECT  37.836 73.051 48.438 73.849 ;
     RECT  2.304 73.741 3.942 73.949 ;
     RECT  60.984 73.921 61.002 74.011 ;
     RECT  61.815 72.833 62.097 74.011 ;
     RECT  72.615 68.909 72.897 74.011 ;
     RECT  72.576 74.011 72.897 74.047 ;
     RECT  60.984 74.011 62.097 74.075 ;
     RECT  24.015 56.237 24.297 74.083 ;
     RECT  37.836 73.849 48.87 74.191 ;
     RECT  51.015 73.139 51.297 74.191 ;
     RECT  61.815 74.075 62.097 74.191 ;
     RECT  54.432 74.191 54.45 74.281 ;
     RECT  54.432 74.281 54.702 74.309 ;
     RECT  60.984 74.075 61.002 74.309 ;
     RECT  25.272 74.281 25.29 74.333 ;
     RECT  23.724 74.083 24.297 74.381 ;
     RECT  50.796 74.191 51.297 74.389 ;
     RECT  61.815 74.191 62.406 74.389 ;
     RECT  37.836 74.191 48.978 74.425 ;
     RECT  54.684 74.309 54.702 74.453 ;
     RECT  37.62 74.425 48.978 74.461 ;
     RECT  61.815 74.389 62.73 74.461 ;
     RECT  72.396 74.047 72.897 74.489 ;
     RECT  2.415 73.949 3.942 74.551 ;
     RECT  4.716 73.805 4.734 74.551 ;
     RECT  56.415 73.103 56.697 74.551 ;
     RECT  63.72 74.389 63.738 74.551 ;
     RECT  37.62 74.461 49.662 74.579 ;
     RECT  58.86 74.281 58.878 74.579 ;
     RECT  50.796 74.389 51.606 74.581 ;
     RECT  63.72 74.551 63.882 74.581 ;
     RECT  37.62 74.579 49.518 74.587 ;
     RECT  65.34 74.461 65.358 74.587 ;
     RECT  50.58 74.581 51.606 74.615 ;
     RECT  53.496 74.425 53.514 74.621 ;
     RECT  65.34 74.587 65.61 74.623 ;
     RECT  50.58 74.615 51.57 74.651 ;
     RECT  37.44 74.587 49.518 74.669 ;
     RECT  2.415 74.551 4.734 74.731 ;
     RECT  50.58 74.651 51.297 74.731 ;
     RECT  63.72 74.581 64.242 74.731 ;
     RECT  65.34 74.623 66.114 74.731 ;
     RECT  67.215 72.689 67.497 74.731 ;
     RECT  74.268 74.551 74.286 74.731 ;
     RECT  63.72 74.731 64.422 74.759 ;
     RECT  46.8 74.669 49.518 74.765 ;
     RECT  37.44 74.669 46.026 74.821 ;
     RECT  83.415 72.535 84.042 74.821 ;
     RECT  27.72 74.731 27.738 74.849 ;
     RECT  56.415 74.551 56.754 74.849 ;
     RECT  61.815 74.461 62.802 74.849 ;
     RECT  65.196 74.731 67.497 74.849 ;
     RECT  74.268 74.731 74.43 74.885 ;
     RECT  58.716 74.821 58.734 74.921 ;
     RECT  63.864 74.759 64.422 74.921 ;
     RECT  82.728 74.821 84.042 74.921 ;
     RECT  55.296 74.623 55.314 74.957 ;
     RECT  50.436 74.731 51.297 74.993 ;
     RECT  65.196 74.849 65.214 74.993 ;
     RECT  66.528 74.849 67.497 74.993 ;
     RECT  2.304 74.731 4.734 75.091 ;
     RECT  46.8 74.765 49.23 75.119 ;
     RECT  61.815 74.849 62.73 75.119 ;
     RECT  2.304 75.091 5.022 75.191 ;
     RECT  37.368 74.821 46.026 75.235 ;
     RECT  3.996 75.191 5.022 75.271 ;
     RECT  37.296 75.235 46.026 75.293 ;
     RECT  2.304 75.191 3.258 75.355 ;
     RECT  3.996 75.271 5.598 75.389 ;
     RECT  63.864 74.921 64.134 75.389 ;
     RECT  34.815 73.517 35.097 75.469 ;
     RECT  2.16 75.355 3.258 75.485 ;
     RECT  3.996 75.389 4.806 75.497 ;
     RECT  5.58 75.389 5.598 75.533 ;
     RECT  37.368 75.293 46.026 75.533 ;
     RECT  63.864 75.389 63.99 75.569 ;
     RECT  63.972 75.569 63.99 75.581 ;
     RECT  39.312 75.533 46.026 75.631 ;
     RECT  46.8 75.119 48.942 75.631 ;
     RECT  73.692 75.271 73.71 75.659 ;
     RECT  82.98 74.921 84.042 75.695 ;
     RECT  27.612 75.001 27.63 75.731 ;
     RECT  34.776 75.469 35.097 75.803 ;
     RECT  74.664 74.893 74.682 75.803 ;
     RECT  2.34 75.485 3.258 75.821 ;
     RECT  83.232 75.695 84.042 75.929 ;
     RECT  2.415 75.821 3.258 76.045 ;
     RECT  3.996 75.497 4.158 76.045 ;
     RECT  39.312 75.631 48.942 76.073 ;
     RECT  50.148 75.931 50.166 76.081 ;
     RECT  51.015 74.993 51.297 76.081 ;
     RECT  61.815 75.119 62.097 76.081 ;
     RECT  64.908 75.901 64.926 76.081 ;
     RECT  60.984 76.081 62.097 76.171 ;
     RECT  57.78 75.901 57.798 76.199 ;
     RECT  60.984 76.171 62.694 76.301 ;
     RECT  64.908 76.081 64.998 76.315 ;
     RECT  2.415 76.045 4.158 76.351 ;
     RECT  64.908 76.315 65.718 76.351 ;
     RECT  67.215 74.993 67.497 76.351 ;
     RECT  64.908 76.351 67.497 76.363 ;
     RECT  60.984 76.301 62.097 76.379 ;
     RECT  60.984 76.379 61.002 76.397 ;
     RECT  64.512 76.363 67.497 76.441 ;
     RECT  64.152 76.441 67.497 76.469 ;
     RECT  64.152 76.469 65.466 76.505 ;
     RECT  74.988 76.171 75.006 76.505 ;
     RECT  66.636 76.469 67.497 76.541 ;
     RECT  2.415 76.351 4.266 76.549 ;
     RECT  39.312 76.073 48.798 76.577 ;
     RECT  50.148 76.081 51.297 76.577 ;
     RECT  53.928 76.549 53.946 76.649 ;
     RECT  85.464 72.379 85.482 76.699 ;
     RECT  2.415 76.549 4.806 76.711 ;
     RECT  83.415 75.929 84.042 76.739 ;
     RECT  49.716 76.621 49.734 76.775 ;
     RECT  85.428 76.699 85.482 76.811 ;
     RECT  50.652 76.577 51.297 76.847 ;
     RECT  54.684 76.747 54.702 76.847 ;
     RECT  58.716 76.207 58.734 76.891 ;
     RECT  48.78 76.577 48.798 76.919 ;
     RECT  64.512 76.505 65.466 76.925 ;
     RECT  64.656 76.925 65.466 77.009 ;
     RECT  58.248 76.891 58.734 77.035 ;
     RECT  2.415 76.711 5.166 77.081 ;
     RECT  65.448 77.009 65.466 77.081 ;
     RECT  3.672 77.081 5.166 77.083 ;
     RECT  70.704 76.513 70.722 77.089 ;
     RECT  57.6 77.035 58.734 77.117 ;
     RECT  39.312 76.577 47.97 77.125 ;
     RECT  3.672 77.083 5.706 77.161 ;
     RECT  78.015 70.439 78.297 77.161 ;
     RECT  57.6 77.117 58.266 77.165 ;
     RECT  3.672 77.161 5.886 77.279 ;
     RECT  58.14 77.165 58.266 77.279 ;
     RECT  64.656 77.009 64.674 77.279 ;
     RECT  70.704 77.089 70.794 77.279 ;
     RECT  58.14 77.279 58.158 77.315 ;
     RECT  78.015 77.161 78.75 77.315 ;
     RECT  70.704 77.279 70.722 77.323 ;
     RECT  74.088 77.287 74.106 77.323 ;
     RECT  6.66 77.161 6.678 77.351 ;
     RECT  37.368 75.533 38.322 77.359 ;
     RECT  39.276 77.125 47.97 77.359 ;
     RECT  5.796 77.279 5.886 77.387 ;
     RECT  37.368 77.359 47.97 77.395 ;
     RECT  83.415 76.739 83.898 77.395 ;
     RECT  5.868 77.387 5.886 77.423 ;
     RECT  70.632 77.323 70.722 77.423 ;
     RECT  74.088 77.323 74.718 77.423 ;
     RECT  70.704 77.423 70.722 77.459 ;
     RECT  2.415 77.081 2.934 77.707 ;
     RECT  3.672 77.279 3.762 77.819 ;
     RECT  4.536 77.279 4.554 77.819 ;
     RECT  2.304 77.707 2.934 77.899 ;
     RECT  3.672 77.819 3.69 77.899 ;
     RECT  83.232 77.395 83.898 77.899 ;
     RECT  83.232 77.899 84.042 77.927 ;
     RECT  2.304 77.899 3.69 77.999 ;
     RECT  2.415 77.999 3.69 78.077 ;
     RECT  37.368 77.395 48.258 78.161 ;
     RECT  37.44 78.161 48.258 78.205 ;
     RECT  37.44 78.205 48.33 78.395 ;
     RECT  46.8 78.395 48.33 78.475 ;
     RECT  46.8 78.475 48.834 78.601 ;
     RECT  61.815 76.379 62.097 78.601 ;
     RECT  64.944 78.091 64.962 78.665 ;
     RECT  82.332 78.511 82.35 78.665 ;
     RECT  61.56 78.601 62.097 78.667 ;
     RECT  54.72 78.601 54.738 78.781 ;
     RECT  73.8 78.601 73.818 78.781 ;
     RECT  37.44 78.395 46.062 78.809 ;
     RECT  43.884 78.809 46.062 78.899 ;
     RECT  49.932 78.781 49.95 78.899 ;
     RECT  73.8 78.781 73.926 78.899 ;
     RECT  83.415 77.927 84.042 78.899 ;
     RECT  83.415 78.899 83.898 78.907 ;
     RECT  61.56 78.667 62.37 78.935 ;
     RECT  65.088 78.781 65.97 78.935 ;
     RECT  73.8 78.899 73.818 78.935 ;
     RECT  2.415 78.077 3.438 78.979 ;
     RECT  4.248 78.955 4.266 78.979 ;
     RECT  0.108 78.283 0.126 78.989 ;
     RECT  65.088 78.935 65.214 79.007 ;
     RECT  65.952 78.935 65.97 79.007 ;
     RECT  63.324 78.781 63.342 79.051 ;
     RECT  83.232 78.907 83.898 79.051 ;
     RECT  2.415 78.979 4.266 79.169 ;
     RECT  37.44 78.809 42.966 79.169 ;
     RECT  54.72 78.781 54.81 79.169 ;
     RECT  63.216 79.051 63.342 79.169 ;
     RECT  3.924 79.169 4.266 79.177 ;
     RECT  5.4 79.141 5.418 79.177 ;
     RECT  46.8 78.601 48.942 79.205 ;
     RECT  63.216 79.169 63.234 79.205 ;
     RECT  85.464 76.811 85.482 79.205 ;
     RECT  3.924 79.177 5.418 79.229 ;
     RECT  39.78 79.169 42.966 79.241 ;
     RECT  65.196 79.007 65.214 79.241 ;
     RECT  5.4 79.229 5.418 79.321 ;
     RECT  51.015 76.847 51.297 79.321 ;
     RECT  2.415 79.169 3.15 79.411 ;
     RECT  46.8 79.205 47.97 79.439 ;
     RECT  52.416 78.907 52.434 79.439 ;
     RECT  58.716 79.411 58.734 79.511 ;
     RECT  82.98 79.051 83.898 79.519 ;
     RECT  5.4 79.321 5.85 79.555 ;
     RECT  40.215 79.241 42.966 79.555 ;
     RECT  5.4 79.555 5.922 79.583 ;
     RECT  54.72 79.169 54.738 79.583 ;
     RECT  5.652 79.583 5.922 79.591 ;
     RECT  40.215 79.555 43.146 79.591 ;
     RECT  43.884 78.899 44.082 79.591 ;
     RECT  56.415 74.849 56.697 79.591 ;
     RECT  82.908 79.519 83.898 79.591 ;
     RECT  3.924 79.229 4.266 79.619 ;
     RECT  40.215 79.591 44.082 79.681 ;
     RECT  44.964 78.899 45.954 79.681 ;
     RECT  56.34 79.591 56.697 79.709 ;
     RECT  69.984 79.483 70.002 79.709 ;
     RECT  5.652 79.591 6.102 79.745 ;
     RECT  82.836 79.591 83.898 79.745 ;
     RECT  57.636 79.591 57.654 79.781 ;
     RECT  40.215 79.681 45.954 79.825 ;
     RECT  46.8 79.439 47.574 79.825 ;
     RECT  83.232 79.745 83.898 79.825 ;
     RECT  67.215 76.541 67.497 79.951 ;
     RECT  5.904 79.745 6.102 79.979 ;
     RECT  6.876 79.753 6.894 79.979 ;
     RECT  83.232 79.825 84.042 79.979 ;
     RECT  5.904 79.979 5.922 80.051 ;
     RECT  85.356 79.771 85.374 80.051 ;
     RECT  2.376 79.411 3.15 80.059 ;
     RECT  48.924 79.205 48.942 80.141 ;
     RECT  50.04 80.095 50.058 80.141 ;
     RECT  40.215 79.825 47.574 80.221 ;
     RECT  3.924 79.619 3.942 80.249 ;
     RECT  66.888 79.951 67.497 80.249 ;
     RECT  40.215 80.221 47.718 80.257 ;
     RECT  50.976 79.321 51.297 80.285 ;
     RECT  2.304 80.059 3.15 80.321 ;
     RECT  70.668 80.221 70.686 80.321 ;
     RECT  13.215 56.237 13.497 80.365 ;
     RECT  24.015 74.381 24.297 80.365 ;
     RECT  34.815 75.803 35.097 80.365 ;
     RECT  39.564 80.257 47.718 80.381 ;
     RECT  2.415 80.321 3.15 80.401 ;
     RECT  13.104 80.365 13.497 80.429 ;
     RECT  23.904 80.365 24.297 80.429 ;
     RECT  34.704 80.365 35.097 80.429 ;
     RECT  2.415 80.401 3.762 80.519 ;
     RECT  4.536 80.365 4.554 80.519 ;
     RECT  39.924 80.381 47.718 80.519 ;
     RECT  39.96 80.519 47.718 80.671 ;
     RECT  54.936 80.635 54.954 80.671 ;
     RECT  54.936 80.671 55.458 80.761 ;
     RECT  56.415 79.709 56.697 80.761 ;
     RECT  54.432 80.761 56.697 80.905 ;
     RECT  69.048 80.761 69.066 80.941 ;
     RECT  69.048 80.941 69.174 81.059 ;
     RECT  69.048 81.059 69.066 81.095 ;
     RECT  54.324 80.905 56.697 81.203 ;
     RECT  2.415 80.519 3.618 81.211 ;
     RECT  51.015 80.285 51.297 81.211 ;
     RECT  83.232 79.979 83.697 81.211 ;
     RECT  2.196 81.211 3.618 81.301 ;
     RECT  51.015 81.211 52.074 81.337 ;
     RECT  50.616 81.337 52.074 81.365 ;
     RECT  2.196 81.301 4.122 81.389 ;
     RECT  50.616 81.365 51.354 81.509 ;
     RECT  2.304 81.389 4.122 81.599 ;
     RECT  67.215 80.249 67.497 81.643 ;
     RECT  54.324 81.203 55.53 81.671 ;
     RECT  51.015 81.509 51.354 81.707 ;
     RECT  55.188 81.671 55.53 81.743 ;
     RECT  53.136 81.739 53.154 81.751 ;
     RECT  54.324 81.671 54.342 81.751 ;
     RECT  83.232 81.211 84.042 81.751 ;
     RECT  52.776 81.751 54.342 81.779 ;
     RECT  3.924 81.599 4.122 81.787 ;
     RECT  49.32 81.607 49.338 81.841 ;
     RECT  52.776 81.779 52.794 81.869 ;
     RECT  55.44 81.743 55.53 81.869 ;
     RECT  67.215 81.643 68.166 81.869 ;
     RECT  68.904 81.751 68.922 81.869 ;
     RECT  53.748 81.779 54.342 81.905 ;
     RECT  82.656 81.751 84.042 81.941 ;
     RECT  85.464 80.347 85.482 81.941 ;
     RECT  48.96 81.841 49.59 81.949 ;
     RECT  39.96 80.671 47.862 81.985 ;
     RECT  6.732 81.751 6.822 82.013 ;
     RECT  70.704 81.877 70.722 82.013 ;
     RECT  2.304 81.599 3.114 82.049 ;
     RECT  6.732 82.013 6.75 82.049 ;
     RECT  55.512 81.869 55.53 82.049 ;
     RECT  54.324 81.905 54.342 82.061 ;
     RECT  39.96 81.985 47.898 82.109 ;
     RECT  39.96 82.109 47.718 82.111 ;
     RECT  48.96 81.949 50.13 82.139 ;
     RECT  39.348 82.111 47.718 82.175 ;
     RECT  37.44 79.169 38.286 82.219 ;
     RECT  39.348 82.175 44.838 82.219 ;
     RECT  49.176 82.139 50.13 82.255 ;
     RECT  51.015 81.707 51.297 82.255 ;
     RECT  3.924 81.787 4.266 82.381 ;
     RECT  2.415 82.049 3.114 82.409 ;
     RECT  49.176 82.255 51.297 82.409 ;
     RECT  67.215 81.869 67.554 82.409 ;
     RECT  82.656 81.941 82.674 82.481 ;
     RECT  3.924 82.381 4.338 82.561 ;
     RECT  5.184 82.021 5.202 82.561 ;
     RECT  50.04 82.409 51.297 82.637 ;
     RECT  67.215 82.409 67.497 82.651 ;
     RECT  3.492 82.561 5.598 82.679 ;
     RECT  50.04 82.637 50.13 82.679 ;
     RECT  34.815 80.429 35.097 82.723 ;
     RECT  85.356 82.219 85.374 82.723 ;
     RECT  5.472 82.679 5.598 82.823 ;
     RECT  66.564 82.651 67.497 82.823 ;
     RECT  3.492 82.679 4.59 82.829 ;
     RECT  45.576 82.175 47.718 82.831 ;
     RECT  5.472 82.823 5.562 82.859 ;
     RECT  34.776 82.723 35.097 82.859 ;
     RECT  5.472 82.859 5.49 82.949 ;
     RECT  3.528 82.829 4.59 82.985 ;
     RECT  45.576 82.831 47.754 82.985 ;
     RECT  2.415 82.409 2.697 82.987 ;
     RECT  37.44 82.219 44.838 82.993 ;
     RECT  45.576 82.985 47.43 82.993 ;
     RECT  84.924 82.723 85.374 83.021 ;
     RECT  2.304 82.987 2.697 83.129 ;
     RECT  49.176 82.409 49.194 83.168 ;
     RECT  50.04 82.679 50.058 83.168 ;
     RECT  49.176 83.168 50.058 83.219 ;
     RECT  52.848 82.723 52.866 83.219 ;
     RECT  51.015 82.637 51.297 83.371 ;
     RECT  84.924 83.021 84.942 83.453 ;
     RECT  49.68 83.219 50.058 83.461 ;
     RECT  51.015 83.371 51.498 83.461 ;
     RECT  32.58 83.371 32.598 83.489 ;
     RECT  37.44 82.993 47.43 83.489 ;
     RECT  49.68 83.461 51.498 83.525 ;
     RECT  2.34 83.129 2.697 83.563 ;
     RECT  3.528 82.985 4.374 83.563 ;
     RECT  50.4 83.525 51.498 83.569 ;
     RECT  58.104 83.335 58.122 83.569 ;
     RECT  50.4 83.569 51.534 83.641 ;
     RECT  58.104 83.569 58.59 83.755 ;
     RECT  2.34 83.563 4.374 83.759 ;
     RECT  37.44 83.489 40.878 83.759 ;
     RECT  66.996 82.823 67.497 83.759 ;
     RECT  83.415 81.941 84.042 83.759 ;
     RECT  50.4 83.641 51.714 83.795 ;
     RECT  57.636 83.755 58.59 83.795 ;
     RECT  82.512 83.641 82.53 83.795 ;
     RECT  41.652 83.489 47.43 83.875 ;
     RECT  48.168 83.803 48.186 83.875 ;
     RECT  37.44 83.759 40.842 83.911 ;
     RECT  57.816 83.795 58.59 83.911 ;
     RECT  2.34 83.759 4.266 84.029 ;
     RECT  70.74 83.911 70.758 84.029 ;
     RECT  57.816 83.911 58.698 84.065 ;
     RECT  78.015 77.315 78.297 84.073 ;
     RECT  85.5 83.767 85.518 84.077 ;
     RECT  57.816 84.065 57.834 84.137 ;
     RECT  83.415 83.759 83.697 84.145 ;
     RECT  0.54 83.731 0.558 84.173 ;
     RECT  78.015 84.073 78.678 84.209 ;
     RECT  37.188 83.911 40.842 84.331 ;
     RECT  37.008 84.331 40.842 84.371 ;
     RECT  59.976 84.271 59.994 84.379 ;
     RECT  59.976 84.379 60.282 84.479 ;
     RECT  53.064 84.451 53.082 84.569 ;
     RECT  53.856 84.307 53.874 84.569 ;
     RECT  59.976 84.479 60.066 84.605 ;
     RECT  41.652 83.875 48.186 84.613 ;
     RECT  51.015 83.795 51.297 84.613 ;
     RECT  41.652 84.613 48.402 84.685 ;
     RECT  56.415 81.203 56.697 84.721 ;
     RECT  58.644 84.065 58.698 84.721 ;
     RECT  63.648 84.379 63.666 84.721 ;
     RECT  83.232 84.145 83.697 84.721 ;
     RECT  52.884 84.685 52.902 84.749 ;
     RECT  2.34 84.029 4.014 84.763 ;
     RECT  2.304 84.763 4.014 84.811 ;
     RECT  63.648 84.721 64.17 84.811 ;
     RECT  41.652 84.685 48.474 84.839 ;
     RECT  50.724 84.613 51.297 84.839 ;
     RECT  58.644 84.721 58.806 84.839 ;
     RECT  83.232 84.721 84.042 84.839 ;
     RECT  63.396 84.811 64.17 84.847 ;
     RECT  32.472 83.641 32.49 84.875 ;
     RECT  55.764 84.721 56.697 84.875 ;
     RECT  58.788 84.839 58.806 84.875 ;
     RECT  63.396 84.847 64.746 84.875 ;
     RECT  37.44 84.371 40.842 84.883 ;
     RECT  41.652 84.839 47.826 84.883 ;
     RECT  63.648 84.875 64.746 84.883 ;
     RECT  65.52 84.811 65.538 84.883 ;
     RECT  60.048 84.605 60.066 84.911 ;
     RECT  37.44 84.883 47.826 84.941 ;
     RECT  34.815 82.859 35.097 84.991 ;
     RECT  72.615 74.489 72.897 84.991 ;
     RECT  2.304 84.811 4.122 85.109 ;
     RECT  72.615 84.991 73.386 85.109 ;
     RECT  3.42 85.109 4.122 85.145 ;
     RECT  63.648 84.883 65.538 85.253 ;
     RECT  74.664 85.081 74.682 85.253 ;
     RECT  34.776 84.991 35.097 85.289 ;
     RECT  28.044 85.225 28.062 85.379 ;
     RECT  64.872 85.253 64.89 85.379 ;
     RECT  2.304 85.109 2.697 85.451 ;
     RECT  30.78 85.261 30.798 85.451 ;
     RECT  37.44 84.941 47.754 85.483 ;
     RECT  37.296 85.483 47.754 85.523 ;
     RECT  51.015 84.839 51.297 85.621 ;
     RECT  56.415 84.875 56.697 85.621 ;
     RECT  74.16 85.459 74.178 85.649 ;
     RECT  49.464 85.459 49.482 85.657 ;
     RECT  37.476 85.523 47.754 85.729 ;
     RECT  37.476 85.729 47.79 85.765 ;
     RECT  63.648 85.253 63.918 85.801 ;
     RECT  2.415 85.451 2.697 85.891 ;
     RECT  3.42 85.145 4.05 85.891 ;
     RECT  48.924 85.657 49.482 85.891 ;
     RECT  61.815 78.935 62.097 85.891 ;
     RECT  37.476 85.765 48.114 85.919 ;
     RECT  56.376 85.621 56.697 85.919 ;
     RECT  53.928 85.801 53.946 85.927 ;
     RECT  63.252 85.801 63.918 85.955 ;
     RECT  4.896 85.765 4.914 85.963 ;
     RECT  50.796 85.621 51.297 85.963 ;
     RECT  63.252 85.955 63.774 86.027 ;
     RECT  2.415 85.891 4.05 86.035 ;
     RECT  4.896 85.963 5.094 86.035 ;
     RECT  48.924 85.891 49.59 86.035 ;
     RECT  53.82 85.927 53.946 86.035 ;
     RECT  48.708 86.035 49.59 86.045 ;
     RECT  50.724 85.963 51.297 86.063 ;
     RECT  58.788 85.927 58.806 86.063 ;
     RECT  72.615 85.109 72.897 86.071 ;
     RECT  53.82 86.035 54.162 86.099 ;
     RECT  63.684 86.027 63.774 86.099 ;
     RECT  2.415 86.035 5.094 86.161 ;
     RECT  37.476 85.919 47.682 86.189 ;
     RECT  48.708 86.045 48.726 86.189 ;
     RECT  54.144 86.099 54.162 86.189 ;
     RECT  63.684 86.099 63.702 86.189 ;
     RECT  64.98 86.035 64.998 86.189 ;
     RECT  72.615 86.071 73.458 86.189 ;
     RECT  83.415 84.839 84.042 86.189 ;
     RECT  61.815 85.891 62.154 86.225 ;
     RECT  49.572 86.045 49.59 86.261 ;
     RECT  74.664 86.161 74.682 86.261 ;
     RECT  67.215 83.759 67.497 86.305 ;
     RECT  83.415 86.189 83.898 86.305 ;
     RECT  32.508 86.341 32.526 86.459 ;
     RECT  66.492 86.305 67.497 86.459 ;
     RECT  34.815 85.289 35.097 86.467 ;
     RECT  85.464 84.649 85.482 86.531 ;
     RECT  34.776 86.467 35.097 86.567 ;
     RECT  65.016 86.341 65.034 86.587 ;
     RECT  2.415 86.161 5.202 86.603 ;
     RECT  65.016 86.587 65.574 86.611 ;
     RECT  37.476 86.189 47.286 86.621 ;
     RECT  83.304 86.305 83.898 86.701 ;
     RECT  2.415 86.603 4.482 86.729 ;
     RECT  65.016 86.611 65.718 86.729 ;
     RECT  65.196 86.729 65.214 86.765 ;
     RECT  2.415 86.729 3.51 86.771 ;
     RECT  78.015 84.209 78.297 86.773 ;
     RECT  4.464 86.729 4.482 86.837 ;
     RECT  82.872 86.701 83.898 86.845 ;
     RECT  66.708 86.459 67.497 86.909 ;
     RECT  78.015 86.773 78.678 86.909 ;
     RECT  74.304 86.809 74.322 86.999 ;
     RECT  74.664 87.007 74.682 87.107 ;
     RECT  43.488 86.621 47.286 87.115 ;
     RECT  82.764 86.845 83.898 87.115 ;
     RECT  82.764 87.115 84.042 87.269 ;
     RECT  85.356 87.115 85.374 87.341 ;
     RECT  2.415 86.771 2.97 87.595 ;
     RECT  43.488 87.115 47.61 87.619 ;
     RECT  37.476 86.621 42.606 87.647 ;
     RECT  37.476 87.647 38.862 87.655 ;
     RECT  40.14 87.647 42.606 87.655 ;
     RECT  37.44 87.655 38.862 87.683 ;
     RECT  40.14 87.655 42.714 87.691 ;
     RECT  43.488 87.619 47.97 87.691 ;
     RECT  0.108 87.595 0.126 87.725 ;
     RECT  37.44 87.683 37.854 87.725 ;
     RECT  84.924 87.619 84.942 87.773 ;
     RECT  2.415 87.595 3.042 87.853 ;
     RECT  82.764 87.269 83.898 87.917 ;
     RECT  2.415 87.853 3.618 88.231 ;
     RECT  49.068 87.781 49.086 88.231 ;
     RECT  40.14 87.691 47.97 88.321 ;
     RECT  50.112 88.231 50.202 88.321 ;
     RECT  51.015 86.063 51.297 88.321 ;
     RECT  52.452 88.231 52.47 88.321 ;
     RECT  40.14 88.321 48.114 88.363 ;
     RECT  2.415 88.231 3.978 88.393 ;
     RECT  52.344 88.321 52.47 88.459 ;
     RECT  53.28 88.321 53.298 88.459 ;
     RECT  40.14 88.363 48.258 88.465 ;
     RECT  49.032 88.231 49.086 88.465 ;
     RECT  83.232 87.917 83.898 88.465 ;
     RECT  5.652 88.321 5.67 88.501 ;
     RECT  50.112 88.321 51.297 88.501 ;
     RECT  56.415 85.919 56.697 88.501 ;
     RECT  64.296 88.357 64.314 88.501 ;
     RECT  65.304 88.429 65.322 88.501 ;
     RECT  73.692 88.321 73.71 88.501 ;
     RECT  64.296 88.501 65.322 88.529 ;
     RECT  50.004 88.501 51.297 88.603 ;
     RECT  73.692 88.501 73.818 88.619 ;
     RECT  40.14 88.465 49.194 88.627 ;
     RECT  50.004 88.603 51.57 88.627 ;
     RECT  64.296 88.529 64.998 88.655 ;
     RECT  73.692 88.619 73.71 88.655 ;
     RECT  85.356 88.363 85.374 88.691 ;
     RECT  40.14 88.627 51.57 88.727 ;
     RECT  5.652 88.501 5.706 88.735 ;
     RECT  39.348 88.699 39.366 88.735 ;
     RECT  40.14 88.727 49.194 88.735 ;
     RECT  50.184 88.727 51.57 88.771 ;
     RECT  52.344 88.459 53.298 88.771 ;
     RECT  83.232 88.465 84.042 88.771 ;
     RECT  38.592 87.683 38.61 88.795 ;
     RECT  39.348 88.735 49.194 88.795 ;
     RECT  64.296 88.655 64.638 88.799 ;
     RECT  2.415 88.393 4.554 88.843 ;
     RECT  5.652 88.735 6.102 88.861 ;
     RECT  64.296 88.799 64.422 88.861 ;
     RECT  2.412 88.843 4.554 88.889 ;
     RECT  5.652 88.861 6.822 88.889 ;
     RECT  38.592 88.795 49.194 88.889 ;
     RECT  50.184 88.771 53.406 88.889 ;
     RECT  55.872 88.501 56.697 88.889 ;
     RECT  62.892 88.771 62.982 88.889 ;
     RECT  2.415 88.889 4.554 88.891 ;
     RECT  37.476 87.725 37.854 88.897 ;
     RECT  38.592 88.889 39.186 88.897 ;
     RECT  37.476 88.897 39.186 88.925 ;
     RECT  50.184 88.889 53.298 88.925 ;
     RECT  54.216 88.771 54.234 88.925 ;
     RECT  62.964 88.889 62.982 88.925 ;
     RECT  82.98 88.771 84.042 88.925 ;
     RECT  5.652 88.889 5.922 88.931 ;
     RECT  50.328 88.925 52.686 88.931 ;
     RECT  37.476 88.925 38.862 88.939 ;
     RECT  39.96 88.889 49.194 88.961 ;
     RECT  34.815 86.567 35.097 88.969 ;
     RECT  2.415 88.891 4.662 89.005 ;
     RECT  67.215 86.909 67.497 89.041 ;
     RECT  34.776 88.969 35.097 89.069 ;
     RECT  50.328 88.931 52.542 89.069 ;
     RECT  2.415 89.005 4.878 89.159 ;
     RECT  5.652 88.931 5.67 89.159 ;
     RECT  37.116 88.939 38.862 89.159 ;
     RECT  50.328 89.069 51.297 89.159 ;
     RECT  52.344 89.069 52.542 89.159 ;
     RECT  64.188 88.861 64.422 89.159 ;
     RECT  67.215 89.041 67.986 89.159 ;
     RECT  37.116 89.159 38.79 89.231 ;
     RECT  64.296 89.159 64.314 89.231 ;
     RECT  52.524 89.159 52.542 89.303 ;
     RECT  70.704 89.167 70.722 89.303 ;
     RECT  2.415 89.159 4.662 89.339 ;
     RECT  40.14 88.961 49.194 89.339 ;
     RECT  50.364 89.159 51.297 89.429 ;
     RECT  85.464 88.939 85.482 89.473 ;
     RECT  40.215 89.339 49.194 89.581 ;
     RECT  85.464 89.473 85.518 89.735 ;
     RECT  40.215 89.581 49.41 89.807 ;
     RECT  41.472 89.807 49.41 89.843 ;
     RECT  6.804 88.889 6.822 89.879 ;
     RECT  2.415 89.339 4.554 89.885 ;
     RECT  2.415 89.885 3.87 89.969 ;
     RECT  52.2 89.899 52.218 89.969 ;
     RECT  83.415 88.925 84.042 89.969 ;
     RECT  41.544 89.843 49.41 89.981 ;
     RECT  42.444 89.981 49.41 90.013 ;
     RECT  41.544 89.981 41.67 90.029 ;
     RECT  37.476 89.231 38.79 90.041 ;
     RECT  41.544 90.029 41.562 90.041 ;
     RECT  2.415 89.969 3.726 90.043 ;
     RECT  2.304 90.043 3.726 90.077 ;
     RECT  85.5 89.735 85.518 90.221 ;
     RECT  42.444 90.013 50.058 90.32 ;
     RECT  4.644 90.121 4.662 90.383 ;
     RECT  43.92 90.32 50.058 90.391 ;
     RECT  51.015 89.429 51.297 90.391 ;
     RECT  52.416 90.091 52.434 90.481 ;
     RECT  2.304 90.077 3.474 90.509 ;
     RECT  52.416 90.481 52.938 90.589 ;
     RECT  54.036 90.517 54.054 90.589 ;
     RECT  52.416 90.589 54.63 90.605 ;
     RECT  43.92 90.391 51.297 90.653 ;
     RECT  40.215 89.807 40.698 90.661 ;
     RECT  54.612 90.605 54.63 90.661 ;
     RECT  68.544 90.481 68.562 90.661 ;
     RECT  54.612 90.661 55.062 90.779 ;
     RECT  68.544 90.661 68.706 90.779 ;
     RECT  52.416 90.605 53.658 90.815 ;
     RECT  54.828 90.779 54.846 90.815 ;
     RECT  68.544 90.779 68.562 90.815 ;
     RECT  42.444 90.32 43.182 90.851 ;
     RECT  3.42 90.509 3.474 90.859 ;
     RECT  40.215 90.661 41.094 90.859 ;
     RECT  56.415 88.889 56.697 90.895 ;
     RECT  56.088 90.895 56.697 90.931 ;
     RECT  57.456 90.751 57.474 90.931 ;
     RECT  52.416 90.815 53.622 90.959 ;
     RECT  56.088 90.931 57.69 91.049 ;
     RECT  40.215 90.859 41.598 91.057 ;
     RECT  42.444 90.851 43.074 91.057 ;
     RECT  83.415 89.969 83.79 91.057 ;
     RECT  43.92 90.653 49.554 91.121 ;
     RECT  57.456 91.049 57.69 91.165 ;
     RECT  57.456 91.165 57.726 91.193 ;
     RECT  3.42 90.859 3.834 91.201 ;
     RECT  5.364 90.859 5.382 91.201 ;
     RECT  43.92 91.121 49.482 91.201 ;
     RECT  56.088 91.049 56.697 91.229 ;
     RECT  40.215 91.057 43.074 91.291 ;
     RECT  5.364 91.201 5.526 91.319 ;
     RECT  57.6 91.193 57.726 91.319 ;
     RECT  69.696 91.021 69.714 91.355 ;
     RECT  2.304 90.509 2.697 91.399 ;
     RECT  3.42 91.201 4.302 91.399 ;
     RECT  50.58 90.653 51.297 91.429 ;
     RECT  2.304 91.399 4.302 91.435 ;
     RECT  5.364 91.319 5.382 91.435 ;
     RECT  6.804 91.363 6.822 91.463 ;
     RECT  50.58 91.429 51.39 91.471 ;
     RECT  52.416 90.959 53.478 91.471 ;
     RECT  2.304 91.435 5.382 91.499 ;
     RECT  50.58 91.471 53.478 91.589 ;
     RECT  57.6 91.319 57.618 91.589 ;
     RECT  50.652 91.589 53.478 91.697 ;
     RECT  40.032 91.291 43.074 91.705 ;
     RECT  43.884 91.201 49.482 91.705 ;
     RECT  52.992 91.697 53.478 91.741 ;
     RECT  58.716 91.471 58.734 91.769 ;
     RECT  40.032 91.705 49.482 91.831 ;
     RECT  67.215 89.159 67.497 91.831 ;
     RECT  0.54 91.741 0.558 91.853 ;
     RECT  50.652 91.697 52.182 91.859 ;
     RECT  52.992 91.741 53.982 91.895 ;
     RECT  53.64 91.895 53.982 91.903 ;
     RECT  67.104 91.831 67.497 91.903 ;
     RECT  37.476 90.041 38.61 91.975 ;
     RECT  39.384 91.831 49.482 91.975 ;
     RECT  53.64 91.903 54.306 92.011 ;
     RECT  61.815 86.225 62.097 92.011 ;
     RECT  61.815 92.011 62.73 92.165 ;
     RECT  2.415 91.499 5.382 92.209 ;
     RECT  53.64 92.011 54.522 92.237 ;
     RECT  37.476 91.975 49.482 92.245 ;
     RECT  2.415 92.209 5.454 92.285 ;
     RECT  4.968 92.285 5.454 92.309 ;
     RECT  78.015 86.909 78.297 92.371 ;
     RECT  4.968 92.309 5.238 92.435 ;
     RECT  37.476 92.245 49.518 92.443 ;
     RECT  50.652 91.859 52.074 92.443 ;
     RECT  78.015 92.371 78.678 92.443 ;
     RECT  53.64 92.237 54.486 92.507 ;
     RECT  83.415 91.057 84.042 92.515 ;
     RECT  2.415 92.285 4.194 92.551 ;
     RECT  4.968 92.435 5.058 92.579 ;
     RECT  53.64 92.507 53.658 92.579 ;
     RECT  54.468 92.507 54.486 92.579 ;
     RECT  66.708 91.903 67.497 92.579 ;
     RECT  78.015 92.443 78.75 92.579 ;
     RECT  85.464 90.787 85.482 92.705 ;
     RECT  82.764 92.515 84.042 92.777 ;
     RECT  37.476 92.443 52.074 92.785 ;
     RECT  13.215 80.429 13.497 92.911 ;
     RECT  24.015 80.429 24.297 92.911 ;
     RECT  34.815 89.069 35.097 92.911 ;
     RECT  4.968 92.579 4.986 92.939 ;
     RECT  37.476 92.785 52.182 92.939 ;
     RECT  37.476 92.939 51.894 92.975 ;
     RECT  0.108 92.821 0.126 93.005 ;
     RECT  2.304 92.551 4.194 93.101 ;
     RECT  54.684 92.983 54.702 93.119 ;
     RECT  67.068 92.579 67.497 93.209 ;
     RECT  37.476 92.975 50.022 93.281 ;
     RECT  70.668 93.217 70.686 93.317 ;
     RECT  37.476 93.281 40.95 93.353 ;
     RECT  41.904 93.281 50.022 93.353 ;
     RECT  13.104 92.911 13.497 93.389 ;
     RECT  23.904 92.911 24.297 93.389 ;
     RECT  34.704 92.911 35.097 93.389 ;
     RECT  78.015 92.579 78.678 93.389 ;
     RECT  2.304 93.101 3.582 93.479 ;
     RECT  42.084 93.353 50.022 93.479 ;
     RECT  29.415 55.139 29.697 93.499 ;
     RECT  53.496 93.451 53.514 93.589 ;
     RECT  52.956 93.589 53.514 93.631 ;
     RECT  50.976 92.975 51.894 93.721 ;
     RECT  4.392 93.325 4.41 93.749 ;
     RECT  28.764 93.499 29.697 93.749 ;
     RECT  52.956 93.631 53.91 93.749 ;
     RECT  29.052 93.749 29.697 93.773 ;
     RECT  50.976 93.721 51.966 93.829 ;
     RECT  52.956 93.749 53.694 93.829 ;
     RECT  50.976 93.829 53.694 93.865 ;
     RECT  42.084 93.479 49.482 93.869 ;
     RECT  3.456 93.479 3.582 93.901 ;
     RECT  84.924 93.055 84.942 93.917 ;
     RECT  37.476 93.353 40.662 94.027 ;
     RECT  37.332 94.027 40.662 94.055 ;
     RECT  50.4 93.865 53.694 94.061 ;
     RECT  50.94 94.061 53.694 94.091 ;
     RECT  42.192 93.869 49.482 94.127 ;
     RECT  67.215 93.209 67.497 94.171 ;
     RECT  53.064 94.091 53.694 94.199 ;
     RECT  50.94 94.091 52.074 94.289 ;
     RECT  53.064 94.199 53.658 94.289 ;
     RECT  67.215 94.171 67.842 94.289 ;
     RECT  3.456 93.901 3.618 94.325 ;
     RECT  43.488 94.127 49.482 94.333 ;
     RECT  78.015 93.389 78.297 94.333 ;
     RECT  53.352 94.289 53.658 94.361 ;
     RECT  2.304 93.479 2.697 94.405 ;
     RECT  53.352 94.361 53.622 94.433 ;
     RECT  78.015 94.333 78.678 94.433 ;
     RECT  43.488 94.333 49.554 94.441 ;
     RECT  2.304 94.405 3.006 94.469 ;
     RECT  85.464 94.441 85.482 94.493 ;
     RECT  43.488 94.441 50.202 94.559 ;
     RECT  51.015 94.289 52.074 94.559 ;
     RECT  53.604 94.433 53.622 94.559 ;
     RECT  67.215 94.289 67.77 94.559 ;
     RECT  51.015 94.559 51.93 94.595 ;
     RECT  55.008 94.603 55.026 94.651 ;
     RECT  38.088 94.055 40.662 94.675 ;
     RECT  38.088 94.675 40.986 94.711 ;
     RECT  42.192 94.127 42.354 94.711 ;
     RECT  54.396 94.651 55.026 94.865 ;
     RECT  43.488 94.559 49.59 94.873 ;
     RECT  43.416 94.873 49.59 94.937 ;
     RECT  38.088 94.711 41.022 94.945 ;
     RECT  42.012 94.711 42.354 94.945 ;
     RECT  43.416 94.937 46.926 94.945 ;
     RECT  4.32 94.699 4.338 94.981 ;
     RECT  54.576 94.865 55.026 95.099 ;
     RECT  68.688 94.711 68.706 95.099 ;
     RECT  84.924 94.837 84.942 95.117 ;
     RECT  54.576 95.099 54.918 95.135 ;
     RECT  2.415 94.469 3.006 95.143 ;
     RECT  70.704 95.071 70.722 95.171 ;
     RECT  51.015 94.595 51.297 95.251 ;
     RECT  0.108 95.323 0.126 95.369 ;
     RECT  37.332 94.055 37.35 95.377 ;
     RECT  38.088 94.945 46.926 95.377 ;
     RECT  47.7 94.937 49.59 95.413 ;
     RECT  50.58 95.251 51.297 95.413 ;
     RECT  4.32 94.981 4.374 95.521 ;
     RECT  34.815 93.389 35.097 95.521 ;
     RECT  52.596 95.449 52.614 95.521 ;
     RECT  63.9 95.485 63.918 95.521 ;
     RECT  61.815 92.165 62.097 95.611 ;
     RECT  65.232 95.521 65.25 95.611 ;
     RECT  5.436 95.521 5.454 95.639 ;
     RECT  52.56 95.521 52.614 95.639 ;
     RECT  56.415 91.229 56.697 95.647 ;
     RECT  65.16 95.611 65.25 95.647 ;
     RECT  47.7 95.413 51.498 95.659 ;
     RECT  56.415 95.647 57.042 95.683 ;
     RECT  63.9 95.521 63.99 95.683 ;
     RECT  4.248 95.521 4.374 95.707 ;
     RECT  5.256 95.683 5.274 95.707 ;
     RECT  47.7 95.659 51.678 95.711 ;
     RECT  52.596 95.639 52.614 95.711 ;
     RECT  63.9 95.683 64.134 95.719 ;
     RECT  4.248 95.707 5.274 95.741 ;
     RECT  47.7 95.711 51.606 95.741 ;
     RECT  85.464 95.707 85.482 95.747 ;
     RECT  2.415 95.143 3.51 95.755 ;
     RECT  4.248 95.741 5.094 95.755 ;
     RECT  63.288 95.719 64.134 95.791 ;
     RECT  64.944 95.647 65.25 95.791 ;
     RECT  61.815 95.611 62.154 95.819 ;
     RECT  37.332 95.377 46.926 95.881 ;
     RECT  47.7 95.741 51.297 95.881 ;
     RECT  54.576 95.135 54.702 95.909 ;
     RECT  63.288 95.791 65.25 95.909 ;
     RECT  54.576 95.909 54.594 95.945 ;
     RECT  34.776 95.521 35.097 96.017 ;
     RECT  37.332 95.881 51.297 96.089 ;
     RECT  55.872 95.683 57.042 96.089 ;
     RECT  63.468 95.909 65.25 96.151 ;
     RECT  2.415 95.755 5.094 96.179 ;
     RECT  73.908 96.061 73.926 96.179 ;
     RECT  5.076 96.179 5.094 96.215 ;
     RECT  78.015 94.433 78.297 96.223 ;
     RECT  6.228 95.647 6.246 96.323 ;
     RECT  63.468 96.151 65.61 96.323 ;
     RECT  78.015 96.223 78.678 96.323 ;
     RECT  63.648 96.323 65.61 96.359 ;
     RECT  85.5 95.989 85.518 96.365 ;
     RECT  63.648 96.359 65.322 96.449 ;
     RECT  74.448 96.331 74.466 96.449 ;
     RECT  2.415 96.179 4.158 96.485 ;
     RECT  64.44 96.449 65.322 96.485 ;
     RECT  64.44 96.485 65.178 96.521 ;
     RECT  65.16 96.521 65.178 96.557 ;
     RECT  63.648 96.449 63.666 96.719 ;
     RECT  37.332 96.089 50.166 96.827 ;
     RECT  72.615 86.189 72.897 96.835 ;
     RECT  37.332 96.827 42.606 96.871 ;
     RECT  37.116 96.871 42.606 96.893 ;
     RECT  37.116 96.893 41.526 96.989 ;
     RECT  42.588 96.893 42.606 96.989 ;
     RECT  72.615 96.835 72.99 96.989 ;
     RECT  37.116 96.989 40.734 96.997 ;
     RECT  36.972 96.997 40.734 97.231 ;
     RECT  82.656 96.493 82.674 97.259 ;
     RECT  36.936 97.231 40.734 97.267 ;
     RECT  36.828 97.267 40.734 97.339 ;
     RECT  2.415 96.485 2.97 97.375 ;
     RECT  4.104 96.485 4.158 97.375 ;
     RECT  43.344 96.827 50.166 97.375 ;
     RECT  51.015 96.089 51.297 97.375 ;
     RECT  2.415 97.375 4.158 97.411 ;
     RECT  36.756 97.339 40.734 97.411 ;
     RECT  36.504 97.411 40.734 97.565 ;
     RECT  29.415 93.773 29.697 97.609 ;
     RECT  2.34 97.411 4.698 97.672 ;
     RECT  34.815 96.017 35.097 97.681 ;
     RECT  43.344 97.375 51.297 97.681 ;
     RECT  6.804 97.609 6.822 97.709 ;
     RECT  2.304 97.672 4.698 97.799 ;
     RECT  29.415 97.609 29.826 97.799 ;
     RECT  2.304 97.799 4.59 97.835 ;
     RECT  43.272 97.681 51.297 97.909 ;
     RECT  34.776 97.681 35.097 97.912 ;
     RECT  43.02 97.909 51.297 97.949 ;
     RECT  36.576 97.565 40.734 97.951 ;
     RECT  43.164 97.949 51.297 97.979 ;
     RECT  36.576 97.951 41.13 98.107 ;
     RECT  36.576 98.107 41.67 98.113 ;
     RECT  34.776 97.912 35.802 98.141 ;
     RECT  67.215 94.559 67.497 98.149 ;
     RECT  78.015 96.323 78.297 98.221 ;
     RECT  6.768 98.041 6.786 98.249 ;
     RECT  2.304 97.835 4.446 98.339 ;
     RECT  36.576 98.113 41.994 98.339 ;
     RECT  58.896 98.221 58.914 98.341 ;
     RECT  36.576 98.339 41.13 98.375 ;
     RECT  43.164 97.979 43.902 98.375 ;
     RECT  44.64 97.979 51.297 98.375 ;
     RECT  78.015 98.221 78.678 98.375 ;
     RECT  4.284 98.339 4.446 98.411 ;
     RECT  48.96 98.375 51.297 98.419 ;
     RECT  56.415 96.089 56.697 98.419 ;
     RECT  46.764 98.375 48.042 98.447 ;
     RECT  34.815 98.141 35.802 98.455 ;
     RECT  36.576 98.375 40.95 98.455 ;
     RECT  70.668 98.347 70.686 98.483 ;
     RECT  58.716 98.341 58.914 98.491 ;
     RECT  48.96 98.419 51.462 98.519 ;
     RECT  71.604 98.221 71.622 98.581 ;
     RECT  2.304 98.339 3.474 98.609 ;
     RECT  34.815 98.455 40.95 98.609 ;
     RECT  46.764 98.447 48.006 98.609 ;
     RECT  48.96 98.519 50.094 98.609 ;
     RECT  58.716 98.491 59.382 98.609 ;
     RECT  71.604 98.581 71.802 98.609 ;
     RECT  56.415 98.419 57.042 98.645 ;
     RECT  59.364 98.609 59.382 98.645 ;
     RECT  71.784 98.609 71.802 98.681 ;
     RECT  43.164 98.375 43.47 98.689 ;
     RECT  44.64 98.375 46.026 98.753 ;
     RECT  48.96 98.609 49.266 98.753 ;
     RECT  47.016 98.609 47.718 98.765 ;
     RECT  4.284 98.411 4.302 98.789 ;
     RECT  48.96 98.753 48.978 98.789 ;
     RECT  66.888 98.149 67.497 98.851 ;
     RECT  42.768 98.689 43.47 98.879 ;
     RECT  47.376 98.765 47.718 98.879 ;
     RECT  50.076 98.609 50.094 98.879 ;
     RECT  65.808 98.761 65.826 98.879 ;
     RECT  85.464 96.907 85.482 98.915 ;
     RECT  66.744 98.851 67.497 99.022 ;
     RECT  47.7 98.879 47.718 99.101 ;
     RECT  36.288 98.609 40.95 99.115 ;
     RECT  36.288 99.115 41.274 99.149 ;
     RECT  42.192 98.995 42.282 99.149 ;
     RECT  45.072 98.753 46.026 99.149 ;
     RECT  43.092 98.879 43.47 99.157 ;
     RECT  45.072 99.149 45.897 99.197 ;
     RECT  50.94 98.519 51.462 99.265 ;
     RECT  2.415 98.609 3.474 99.301 ;
     RECT  34.815 98.609 35.334 99.301 ;
     RECT  38.196 99.149 41.274 99.301 ;
     RECT  2.415 99.301 3.618 99.419 ;
     RECT  25.344 99.265 25.362 99.419 ;
     RECT  54.972 99.301 54.99 99.419 ;
     RECT  85.5 99.157 85.518 99.437 ;
     RECT  2.415 99.419 3.474 99.451 ;
     RECT  36.288 99.149 37.458 99.463 ;
     RECT  22.824 99.391 22.842 99.491 ;
     RECT  58.644 99.391 58.662 99.491 ;
     RECT  34.38 99.301 35.334 99.499 ;
     RECT  50.94 99.265 51.93 99.527 ;
     RECT  34.38 99.499 35.37 99.535 ;
     RECT  36.216 99.463 37.458 99.535 ;
     RECT  43.092 99.157 43.974 99.563 ;
     RECT  55.044 99.427 55.062 99.563 ;
     RECT  43.164 99.563 43.974 99.571 ;
     RECT  64.584 99.535 64.602 99.571 ;
     RECT  78.015 98.375 78.297 99.571 ;
     RECT  50.94 99.527 51.426 99.599 ;
     RECT  33.624 99.661 33.642 99.688 ;
     RECT  34.38 99.535 37.458 99.688 ;
     RECT  64.584 99.571 65.07 99.689 ;
     RECT  66.708 99.022 67.497 99.689 ;
     RECT  82.656 99.571 82.674 99.689 ;
     RECT  33.624 99.688 37.458 99.725 ;
     RECT  78.015 99.571 78.678 99.725 ;
     RECT  33.624 99.725 33.678 99.733 ;
     RECT  4.392 99.301 4.41 99.761 ;
     RECT  42.264 99.149 42.282 99.769 ;
     RECT  43.164 99.571 44.226 99.869 ;
     RECT  60.84 99.163 60.858 99.959 ;
     RECT  43.164 99.869 43.362 99.995 ;
     RECT  34.74 99.725 37.458 100.003 ;
     RECT  38.196 99.301 41.31 100.003 ;
     RECT  52.848 99.841 52.866 100.039 ;
     RECT  33.408 99.733 33.678 100.075 ;
     RECT  42.264 99.769 42.426 100.111 ;
     RECT  63.252 100.039 63.27 100.111 ;
     RECT  64.584 99.689 64.998 100.111 ;
     RECT  2.304 99.451 3.474 100.139 ;
     RECT  43.164 99.995 43.182 100.139 ;
     RECT  63.144 100.111 63.27 100.171 ;
     RECT  32.76 100.075 33.678 100.201 ;
     RECT  64.476 100.111 64.998 100.201 ;
     RECT  34.74 100.003 41.31 100.219 ;
     RECT  42.156 100.111 42.426 100.219 ;
     RECT  34.74 100.219 42.426 100.229 ;
     RECT  52.56 100.039 52.866 100.229 ;
     RECT  61.815 95.819 62.097 100.237 ;
     RECT  63.144 100.171 63.522 100.237 ;
     RECT  2.415 100.139 3.474 100.381 ;
     RECT  61.815 100.237 63.522 100.381 ;
     RECT  64.368 100.201 64.998 100.381 ;
     RECT  61.815 100.381 64.998 100.409 ;
     RECT  34.74 100.229 41.778 100.499 ;
     RECT  52.56 100.229 52.722 100.499 ;
     RECT  63.288 100.409 64.998 100.499 ;
     RECT  32.148 100.201 33.678 100.507 ;
     RECT  34.74 100.499 41.022 100.507 ;
     RECT  52.56 100.499 52.578 100.535 ;
     RECT  73.728 100.201 73.746 100.535 ;
     RECT  44.208 99.869 44.226 100.615 ;
     RECT  63.648 100.499 64.998 100.643 ;
     RECT  2.415 100.381 3.51 100.651 ;
     RECT  32.148 100.507 41.022 100.651 ;
     RECT  64.584 100.643 64.998 100.651 ;
     RECT  64.584 100.651 65.07 100.679 ;
     RECT  2.415 100.651 3.834 100.741 ;
     RECT  67.215 99.689 67.497 100.741 ;
     RECT  64.836 100.679 65.07 100.769 ;
     RECT  83.415 92.777 84.042 100.769 ;
     RECT  32.076 100.651 41.022 100.841 ;
     RECT  85.464 99.967 85.482 100.841 ;
     RECT  44.1 100.615 44.226 100.849 ;
     RECT  2.415 100.741 4.41 100.877 ;
     RECT  66.708 100.741 67.497 100.877 ;
     RECT  43.812 100.849 44.226 100.885 ;
     RECT  42.732 100.615 42.75 100.891 ;
     RECT  34.815 100.841 41.022 100.925 ;
     RECT  22.428 100.345 22.446 101.039 ;
     RECT  74.448 100.885 74.466 101.039 ;
     RECT  83.415 100.769 83.862 101.047 ;
     RECT  38.52 100.925 41.022 101.147 ;
     RECT  42.732 100.891 43.038 101.183 ;
     RECT  43.812 100.885 44.298 101.183 ;
     RECT  2.415 100.877 4.374 101.219 ;
     RECT  42.732 101.183 42.75 101.309 ;
     RECT  83.376 101.047 83.862 101.309 ;
     RECT  43.956 101.183 44.298 101.317 ;
     RECT  41.76 100.499 41.778 101.345 ;
     RECT  43.956 101.317 44.514 101.417 ;
     RECT  32.076 100.841 33.966 101.425 ;
     RECT  63.648 100.643 63.666 101.425 ;
     RECT  52.956 101.317 52.974 101.461 ;
     RECT  31.896 101.425 33.966 101.467 ;
     RECT  2.415 101.219 4.302 101.551 ;
     RECT  63.648 101.425 63.81 101.563 ;
     RECT  64.836 100.769 64.962 101.563 ;
     RECT  44.424 101.417 44.514 101.579 ;
     RECT  52.956 101.461 53.082 101.579 ;
     RECT  63.648 101.563 64.962 101.579 ;
     RECT  52.956 101.579 52.974 101.615 ;
     RECT  63.648 101.579 64.602 101.615 ;
     RECT  34.815 100.925 37.746 101.659 ;
     RECT  38.52 101.147 40.77 101.659 ;
     RECT  83.415 101.309 83.862 101.659 ;
     RECT  82.656 101.587 82.674 101.687 ;
     RECT  31.356 101.467 33.966 101.731 ;
     RECT  34.815 101.659 40.77 101.731 ;
     RECT  2.376 101.551 4.302 101.849 ;
     RECT  31.356 101.731 40.77 101.849 ;
     RECT  44.424 101.579 44.442 101.849 ;
     RECT  73.656 101.587 73.674 101.849 ;
     RECT  82.512 101.731 82.53 101.885 ;
     RECT  74.664 101.047 74.682 101.957 ;
     RECT  48.456 101.929 48.474 101.965 ;
     RECT  31.356 101.849 40.554 102.029 ;
     RECT  47.772 101.965 48.474 102.029 ;
     RECT  63.648 101.615 63.846 102.029 ;
     RECT  41.472 101.965 41.49 102.119 ;
     RECT  46.764 101.965 46.782 102.119 ;
     RECT  63.792 102.029 63.846 102.119 ;
     RECT  84.888 101.227 84.906 102.191 ;
     RECT  48.42 102.029 48.474 102.263 ;
     RECT  64.584 101.615 64.602 102.263 ;
     RECT  32.148 102.029 40.554 102.299 ;
     RECT  18.615 2.413 18.897 102.361 ;
     RECT  21.996 102.235 22.014 102.389 ;
     RECT  48.456 102.263 48.474 102.389 ;
     RECT  52.308 102.163 52.326 102.389 ;
     RECT  63.828 102.119 63.846 102.389 ;
     RECT  83.415 101.659 84.042 102.389 ;
     RECT  33.264 102.299 40.554 102.425 ;
     RECT  78.015 99.725 78.297 102.433 ;
     RECT  18.615 102.361 18.954 102.461 ;
     RECT  84.924 102.424 85.482 102.461 ;
     RECT  83.415 102.389 83.898 102.505 ;
     RECT  30.78 102.235 30.798 102.569 ;
     RECT  78.015 102.433 78.678 102.569 ;
     RECT  48.492 102.505 48.51 102.659 ;
     RECT  41.292 102.571 41.31 102.695 ;
     RECT  42.768 102.631 42.786 102.731 ;
     RECT  33.588 102.425 40.554 102.775 ;
     RECT  32.148 102.299 32.166 102.839 ;
     RECT  49.608 102.811 49.626 102.901 ;
     RECT  67.215 100.877 67.497 102.901 ;
     RECT  54.252 102.703 54.27 102.929 ;
     RECT  63.864 102.541 64.494 102.929 ;
     RECT  74.34 102.631 74.358 102.929 ;
     RECT  2.415 101.849 3.618 102.937 ;
     RECT  83.196 102.505 83.898 102.937 ;
     RECT  2.415 102.937 4.194 102.965 ;
     RECT  66.744 102.901 67.497 103.001 ;
     RECT  82.656 102.937 83.898 103.037 ;
     RECT  51.015 99.599 51.297 103.045 ;
     RECT  65.412 102.811 65.43 103.073 ;
     RECT  3.924 102.965 4.194 103.081 ;
     RECT  84.924 102.461 84.942 103.085 ;
     RECT  33.588 102.775 40.914 103.195 ;
     RECT  50.544 103.045 51.297 103.199 ;
     RECT  33.012 103.195 40.914 103.235 ;
     RECT  49.608 102.901 49.698 103.235 ;
     RECT  3.924 103.081 4.662 103.271 ;
     RECT  83.196 103.037 83.898 103.307 ;
     RECT  33.588 103.235 40.914 103.421 ;
     RECT  33.84 103.421 40.914 103.469 ;
     RECT  83.415 103.307 83.898 103.585 ;
     RECT  33.984 103.469 40.914 103.621 ;
     RECT  3.924 103.271 4.014 103.739 ;
     RECT  33.984 103.621 41.166 103.739 ;
     RECT  49.932 103.351 50.022 103.739 ;
     RECT  49.932 103.739 49.986 103.775 ;
     RECT  85.356 103.675 85.374 103.811 ;
     RECT  61.815 100.409 62.097 103.819 ;
     RECT  64.476 102.929 64.494 103.819 ;
     RECT  66.996 103.001 67.497 103.855 ;
     RECT  64.116 103.819 64.494 103.891 ;
     RECT  72.615 96.989 72.897 103.891 ;
     RECT  51.015 103.199 51.297 103.981 ;
     RECT  66.888 103.855 67.497 104.008 ;
     RECT  33.984 103.739 41.022 104.009 ;
     RECT  66.168 104.008 67.497 104.009 ;
     RECT  63.792 103.891 64.494 104.011 ;
     RECT  66.168 104.009 66.186 104.045 ;
     RECT  63.648 104.011 64.494 104.051 ;
     RECT  51.015 103.981 51.894 104.125 ;
     RECT  61.815 103.819 62.73 104.153 ;
     RECT  2.415 102.965 2.697 104.161 ;
     RECT  42.804 103.981 42.822 104.161 ;
     RECT  51.015 104.125 52.326 104.161 ;
     RECT  74.772 103.981 74.79 104.161 ;
     RECT  3.996 103.739 4.014 104.189 ;
     RECT  2.304 104.161 2.697 104.237 ;
     RECT  74.772 104.161 74.862 104.251 ;
     RECT  42.732 104.161 42.894 104.279 ;
     RECT  51.015 104.161 52.434 104.279 ;
     RECT  74.772 104.251 74.898 104.279 ;
     RECT  82.44 104.161 82.458 104.287 ;
     RECT  83.415 103.585 84.042 104.287 ;
     RECT  62.964 104.161 62.982 104.315 ;
     RECT  63.756 104.051 64.494 104.315 ;
     RECT  74.844 104.279 74.898 104.315 ;
     RECT  82.44 104.287 84.042 104.315 ;
     RECT  33.984 104.009 40.554 104.395 ;
     RECT  74.88 104.315 74.898 104.423 ;
     RECT  64.224 104.315 64.494 104.431 ;
     RECT  33.804 104.395 40.554 104.459 ;
     RECT  33.804 104.459 40.497 104.549 ;
     RECT  52.308 104.279 52.434 104.549 ;
     RECT  82.8 104.315 84.042 104.549 ;
     RECT  52.308 104.549 52.326 104.585 ;
     RECT  33.804 104.549 39.186 104.629 ;
     RECT  64.224 104.431 64.638 104.819 ;
     RECT  33.732 104.629 39.186 104.863 ;
     RECT  86.292 104.287 86.31 104.957 ;
     RECT  72.615 103.891 73.278 104.971 ;
     RECT  64.224 104.819 64.242 105.067 ;
     RECT  64.08 105.067 64.242 105.089 ;
     RECT  65.016 104.863 65.034 105.089 ;
     RECT  33.048 104.863 39.186 105.097 ;
     RECT  32.328 105.097 39.186 105.125 ;
     RECT  64.08 105.089 64.098 105.125 ;
     RECT  32.328 105.125 32.49 105.149 ;
     RECT  33.264 105.125 39.186 105.161 ;
     RECT  33.264 105.161 35.622 105.197 ;
     RECT  36.432 105.161 39.186 105.233 ;
     RECT  82.8 104.549 83.898 105.331 ;
     RECT  32.472 105.149 32.49 105.359 ;
     RECT  33.264 105.197 35.262 105.359 ;
     RECT  36.504 105.233 39.186 105.359 ;
     RECT  72.615 104.971 73.602 105.359 ;
     RECT  33.3 105.359 35.262 105.431 ;
     RECT  82.476 105.331 83.898 105.431 ;
     RECT  82.728 105.431 83.898 105.467 ;
     RECT  83.415 105.467 83.898 105.475 ;
     RECT  34.056 105.431 35.262 105.503 ;
     RECT  36.504 105.359 39.15 105.503 ;
     RECT  34.056 105.503 34.074 105.539 ;
     RECT  2.415 104.237 2.697 105.587 ;
     RECT  7.815 2.413 8.097 105.587 ;
     RECT  13.215 93.389 13.497 105.587 ;
     RECT  18.615 102.461 18.897 105.587 ;
     RECT  24.015 93.389 24.297 105.587 ;
     RECT  29.415 97.799 29.697 105.587 ;
     RECT  40.215 104.549 40.497 105.587 ;
     RECT  45.615 99.197 45.897 105.587 ;
     RECT  51.015 104.279 51.297 105.587 ;
     RECT  56.415 98.645 56.697 105.587 ;
     RECT  61.815 104.153 62.097 105.587 ;
     RECT  67.215 104.009 67.497 105.587 ;
     RECT  72.615 105.359 72.897 105.587 ;
     RECT  78.015 102.569 78.297 105.587 ;
     RECT  31.428 105.475 31.446 105.629 ;
     RECT  34.815 105.503 35.262 105.629 ;
     RECT  37.26 105.503 37.278 105.629 ;
     RECT  38.268 105.503 38.286 105.629 ;
     RECT  39.024 105.503 39.15 105.629 ;
     RECT  49.968 103.775 49.986 105.629 ;
     RECT  83.415 105.475 84.042 105.629 ;
     RECT  39.024 105.629 39.042 105.665 ;
     RECT  85.464 105.499 85.482 105.701 ;
     RECT  51.015 105.587 51.105 105.709 ;
     RECT  50.292 105.709 51.105 105.809 ;
     RECT  31.248 105.745 31.266 105.821 ;
     RECT  2.415 105.587 2.505 105.857 ;
     RECT  7.815 105.587 7.905 105.857 ;
     RECT  13.215 105.587 13.305 105.857 ;
     RECT  18.615 105.587 18.705 105.857 ;
     RECT  24.015 105.587 24.105 105.857 ;
     RECT  29.415 105.587 29.505 105.857 ;
     RECT  34.815 105.629 35.154 105.857 ;
     RECT  40.215 105.587 40.305 105.857 ;
     RECT  45.615 105.587 45.705 105.857 ;
     RECT  50.58 105.809 51.105 105.857 ;
     RECT  56.415 105.587 56.574 105.857 ;
     RECT  61.815 105.587 61.905 105.857 ;
     RECT  67.215 105.587 67.305 105.857 ;
     RECT  72.615 105.587 72.705 105.857 ;
     RECT  78.015 105.587 78.105 105.857 ;
     RECT  83.415 105.629 83.505 105.857 ;
     RECT  35.136 105.857 35.154 105.965 ;
     RECT  56.556 105.857 56.574 107.213 ;
     RECT  50.58 105.857 50.598 107.885 ;
    LAYER M4 ;
     RECT  0.06 2.448 0.137 101.256 ;
     RECT  0.137 2.544 0.569 16.584 ;
     RECT  0.137 17.712 0.569 18.36 ;
     RECT  0.137 37.152 0.569 57.72 ;
     RECT  0.137 73.008 0.569 92.424 ;
     RECT  0.137 26.544 2.365 35.976 ;
     RECT  0.569 37.152 2.365 37.176 ;
     RECT  0.569 55.968 2.365 57.72 ;
     RECT  0.137 58.896 2.365 71.832 ;
     RECT  0.569 2.544 2.408 15.288 ;
     RECT  0.569 18.336 2.408 18.36 ;
     RECT  0.137 19.488 2.408 22.44 ;
     RECT  0.137 23.616 2.408 25.416 ;
     RECT  2.365 26.544 2.408 37.176 ;
     RECT  0.569 38.304 2.408 54.792 ;
     RECT  2.365 55.968 2.408 71.832 ;
     RECT  0.569 73.008 2.408 83.592 ;
     RECT  0.569 84.768 2.408 91.224 ;
     RECT  0.569 92.4 2.408 92.424 ;
     RECT  0.137 93.552 2.408 94.776 ;
     RECT  0.137 95.904 2.408 101.256 ;
     RECT  0.06 104.208 2.408 104.232 ;
     RECT  2.408 2.148 2.512 105.852 ;
     RECT  2.512 2.418 2.704 105.582 ;
     RECT  2.704 39.504 2.729 39.528 ;
     RECT  2.704 20.304 2.765 22.728 ;
     RECT  2.704 58.656 2.801 64.2 ;
     RECT  2.704 12.864 2.837 14.28 ;
     RECT  2.704 48.432 2.837 57.144 ;
     RECT  2.704 85.92 2.837 87.624 ;
     RECT  2.837 14.208 2.873 14.28 ;
     RECT  2.704 69.456 2.873 71.88 ;
     RECT  2.704 96.288 2.873 98.088 ;
     RECT  2.704 45.696 2.909 46.584 ;
     RECT  2.704 65.424 2.909 67.896 ;
     RECT  2.801 61.248 3.017 64.2 ;
     RECT  2.909 65.904 3.053 67.896 ;
     RECT  2.837 86.16 3.053 87.624 ;
     RECT  2.873 96.288 3.061 96.552 ;
     RECT  2.837 12.864 3.233 13.08 ;
     RECT  3.017 62.64 3.233 64.2 ;
     RECT  2.704 88.608 3.305 90.072 ;
     RECT  2.837 48.432 3.377 52.152 ;
     RECT  2.873 69.456 3.377 70.728 ;
     RECT  2.704 72.96 3.413 83.592 ;
     RECT  2.704 2.544 3.443 8.904 ;
     RECT  2.704 30.192 3.443 32.472 ;
     RECT  2.909 45.696 3.443 45.72 ;
     RECT  3.377 50.208 3.443 52.152 ;
     RECT  2.801 58.656 3.443 60.072 ;
     RECT  3.413 72.96 3.443 82.824 ;
     RECT  3.443 2.544 3.449 8.808 ;
     RECT  2.704 33.6 3.449 35.928 ;
     RECT  2.704 36.912 3.449 37.608 ;
     RECT  2.873 97.536 3.449 98.088 ;
     RECT  3.377 48.432 3.485 49.032 ;
     RECT  3.443 58.656 3.485 58.68 ;
     RECT  3.443 72.96 3.485 75.48 ;
     RECT  3.443 50.544 3.491 52.152 ;
     RECT  2.837 53.184 3.491 57.144 ;
     RECT  3.377 70.272 3.491 70.728 ;
     RECT  2.704 10.272 3.521 11.304 ;
     RECT  3.491 70.416 3.529 70.728 ;
     RECT  2.704 26.208 3.539 28.968 ;
     RECT  3.053 86.16 3.539 86.76 ;
     RECT  2.704 91.44 3.539 94.728 ;
     RECT  3.449 2.832 3.565 8.808 ;
     RECT  3.443 30.192 3.565 31.272 ;
     RECT  3.565 2.832 3.587 7.752 ;
     RECT  3.491 54.096 3.587 57.144 ;
     RECT  3.565 30.24 3.593 31.272 ;
     RECT  3.587 6.24 3.629 7.464 ;
     RECT  3.305 88.608 3.629 88.632 ;
     RECT  2.704 18.768 3.635 18.984 ;
     RECT  2.765 21.36 3.635 22.728 ;
     RECT  2.873 71.856 3.635 71.88 ;
     RECT  3.485 72.96 3.635 74.136 ;
     RECT  3.587 2.832 3.683 4.728 ;
     RECT  3.449 34.224 3.683 35.928 ;
     RECT  2.704 99.168 3.683 99.192 ;
     RECT  2.873 14.256 3.697 14.28 ;
     RECT  2.704 15.264 3.697 15.384 ;
     RECT  3.635 18.768 3.701 18.792 ;
     RECT  3.443 76.56 3.701 82.824 ;
     RECT  2.704 40.656 3.709 41.64 ;
     RECT  2.704 42.768 3.724 43.32 ;
     RECT  3.683 3.024 3.729 4.728 ;
     RECT  3.683 34.608 3.731 35.928 ;
     RECT  2.765 20.304 3.733 20.328 ;
     RECT  2.704 23.952 3.737 24.744 ;
     RECT  3.305 89.856 3.737 90.072 ;
     RECT  3.635 21.936 3.765 22.728 ;
     RECT  3.709 40.656 3.769 41.4 ;
     RECT  3.539 86.16 3.841 86.184 ;
     RECT  3.233 62.64 3.845 63.864 ;
     RECT  3.629 6.24 3.881 6.264 ;
     RECT  3.053 65.904 3.909 66.552 ;
     RECT  3.737 24.72 3.925 24.744 ;
     RECT  3.539 26.208 3.925 26.232 ;
     RECT  3.449 37.584 3.925 37.608 ;
     RECT  3.697 14.256 3.971 15.384 ;
     RECT  3.925 24.72 3.971 26.232 ;
     RECT  3.925 37.584 3.971 38.424 ;
     RECT  3.769 39.696 3.971 41.4 ;
     RECT  3.587 54.672 3.971 57.144 ;
     RECT  3.841 85.488 3.971 86.184 ;
     RECT  3.845 62.976 3.989 63.864 ;
     RECT  3.913 17.664 3.997 17.688 ;
     RECT  3.737 89.856 4.012 89.88 ;
     RECT  3.593 30.24 4.019 30.264 ;
     RECT  3.233 13.056 4.021 13.08 ;
     RECT  3.971 14.64 4.021 15.384 ;
     RECT  3.769 16.512 4.021 16.536 ;
     RECT  3.729 4.128 4.025 4.728 ;
     RECT  3.593 31.248 4.025 31.272 ;
     RECT  3.971 54.768 4.025 57.144 ;
     RECT  3.989 62.976 4.025 63.24 ;
     RECT  3.485 75.168 4.025 75.48 ;
     RECT  2.704 104.16 4.025 104.184 ;
     RECT  3.539 28.944 4.06 28.968 ;
     RECT  3.971 25.68 4.061 25.704 ;
     RECT  3.539 92.16 4.067 94.728 ;
     RECT  3.971 40.656 4.097 41.4 ;
     RECT  4.025 56.208 4.097 57 ;
     RECT  3.017 61.248 4.129 61.368 ;
     RECT  3.731 34.608 4.133 34.968 ;
     RECT  3.701 78.96 4.133 82.824 ;
     RECT  3.061 96.528 4.133 96.552 ;
     RECT  3.485 48.432 4.169 48.456 ;
     RECT  3.449 97.536 4.169 97.56 ;
     RECT  4.021 14.64 4.205 16.536 ;
     RECT  3.521 11.28 4.241 11.304 ;
     RECT  4.133 78.96 4.277 80.424 ;
     RECT  4.133 81.792 4.277 82.824 ;
     RECT  2.704 44.448 4.313 44.472 ;
     RECT  3.701 76.56 4.313 77.112 ;
     RECT  3.053 67.872 4.345 67.896 ;
     RECT  4.277 82.416 4.349 82.824 ;
     RECT  4.067 92.256 4.349 94.728 ;
     RECT  3.733 20.304 4.385 20.376 ;
     RECT  4.345 67.776 4.385 67.896 ;
     RECT  3.529 70.416 4.385 70.68 ;
     RECT  4.021 13.056 4.421 13.656 ;
     RECT  3.765 21.936 4.421 22.248 ;
     RECT  4.349 92.256 4.451 93.96 ;
     RECT  3.971 38.4 4.453 38.424 ;
     RECT  4.453 38.4 4.493 38.808 ;
     RECT  3.635 73.488 4.493 74.136 ;
     RECT  4.451 92.256 4.493 93.768 ;
     RECT  3.909 66.528 4.529 66.552 ;
     RECT  3.971 86.16 4.565 86.184 ;
     RECT  4.097 41.376 4.601 41.4 ;
     RECT  4.349 82.8 4.601 82.824 ;
     RECT  4.205 15.984 4.637 16.536 ;
     RECT  4.025 75.168 4.637 75.192 ;
     RECT  4.421 22.224 4.709 22.248 ;
     RECT  3.491 50.784 4.709 50.808 ;
     RECT  4.277 79.2 4.709 80.424 ;
     RECT  3.629 7.44 4.745 7.464 ;
     RECT  3.539 27.888 4.817 27.912 ;
     RECT  3.443 32.448 4.961 32.472 ;
     RECT  4.025 63.216 5.069 63.24 ;
     RECT  4.421 13.056 5.123 13.08 ;
     RECT  4.025 4.128 5.177 4.152 ;
     RECT  3.443 60.048 5.177 60.072 ;
     RECT  4.493 38.784 5.249 38.808 ;
     RECT  3.724 43.296 5.249 43.32 ;
     RECT  4.405 95.712 5.285 95.736 ;
     RECT  4.385 67.776 5.357 67.8 ;
     RECT  5.077 11.952 5.573 11.976 ;
     RECT  4.313 77.088 5.717 77.112 ;
     RECT  4.709 80.016 5.933 80.424 ;
     RECT  4.633 88.896 5.933 88.92 ;
     RECT  4.385 70.416 6.041 70.44 ;
     RECT  4.129 61.248 6.833 61.464 ;
     RECT  3.729 3.024 7.808 3.048 ;
     RECT  3.565 8.784 7.808 8.808 ;
     RECT  4.205 14.64 7.808 14.664 ;
     RECT  4.385 20.352 7.808 20.376 ;
     RECT  4.133 34.608 7.808 34.632 ;
     RECT  4.097 56.208 7.808 56.232 ;
     RECT  6.833 61.344 7.808 61.464 ;
     RECT  4.493 73.776 7.808 74.136 ;
     RECT  5.933 80.4 7.808 80.424 ;
     RECT  4.493 92.928 7.808 93.768 ;
     RECT  7.808 2.148 7.912 105.852 ;
     RECT  7.912 2.418 8.104 105.582 ;
     RECT  8.104 3.024 13.208 3.048 ;
     RECT  8.104 8.784 13.208 8.808 ;
     RECT  8.104 14.64 13.208 14.664 ;
     RECT  8.104 20.352 13.208 20.376 ;
     RECT  8.104 34.608 13.208 34.632 ;
     RECT  8.104 56.208 13.208 56.232 ;
     RECT  8.104 61.344 13.208 61.464 ;
     RECT  8.104 73.776 13.208 74.136 ;
     RECT  8.104 80.4 13.208 80.424 ;
     RECT  8.104 92.928 13.208 93.768 ;
     RECT  13.208 2.148 13.312 105.852 ;
     RECT  13.312 2.418 13.504 105.582 ;
     RECT  13.504 3.024 18.608 3.048 ;
     RECT  13.504 8.784 18.608 8.808 ;
     RECT  13.504 14.64 18.608 14.664 ;
     RECT  13.504 20.352 18.608 20.376 ;
     RECT  13.504 34.608 18.608 34.632 ;
     RECT  13.504 56.208 18.608 56.232 ;
     RECT  13.504 61.344 18.608 61.464 ;
     RECT  13.504 73.776 18.608 74.136 ;
     RECT  13.504 80.4 18.608 80.424 ;
     RECT  13.504 92.928 18.608 93.768 ;
     RECT  18.608 2.148 18.712 105.852 ;
     RECT  18.712 2.418 18.904 105.582 ;
     RECT  18.904 73.776 23.713 74.136 ;
     RECT  18.904 34.608 23.893 34.632 ;
     RECT  18.904 3.024 24.008 3.048 ;
     RECT  18.904 8.784 24.008 8.808 ;
     RECT  18.904 14.64 24.008 14.664 ;
     RECT  18.904 20.352 24.008 20.376 ;
     RECT  23.893 34.608 24.008 34.728 ;
     RECT  18.904 56.208 24.008 56.232 ;
     RECT  18.904 61.344 24.008 61.464 ;
     RECT  23.713 73.776 24.008 74.376 ;
     RECT  18.904 80.4 24.008 80.424 ;
     RECT  18.904 92.928 24.008 93.768 ;
     RECT  24.008 2.148 24.112 105.852 ;
     RECT  24.112 2.418 24.304 105.582 ;
     RECT  24.304 34.704 25.981 34.728 ;
     RECT  25.981 34.368 26.387 34.728 ;
     RECT  24.304 73.776 28.789 74.376 ;
     RECT  24.304 14.64 29.269 14.664 ;
     RECT  26.341 35.952 29.269 35.976 ;
     RECT  24.304 3.024 29.408 3.048 ;
     RECT  24.304 8.784 29.408 8.808 ;
     RECT  29.269 14.64 29.408 14.808 ;
     RECT  24.304 20.352 29.408 20.376 ;
     RECT  26.387 34.368 29.408 34.392 ;
     RECT  29.269 35.712 29.408 35.976 ;
     RECT  24.304 56.208 29.408 56.232 ;
     RECT  24.304 61.344 29.408 61.464 ;
     RECT  28.789 73.344 29.408 74.376 ;
     RECT  24.304 80.4 29.408 80.424 ;
     RECT  24.304 92.928 29.408 93.768 ;
     RECT  29.408 2.148 29.512 105.852 ;
     RECT  29.512 2.418 29.704 105.582 ;
     RECT  30.757 106.56 30.853 106.68 ;
     RECT  30.853 105.792 30.899 106.68 ;
     RECT  30.757 107.856 30.899 107.88 ;
     RECT  30.899 105.792 31.277 105.816 ;
     RECT  31.345 101.472 32.065 101.496 ;
     RECT  32.065 100.704 32.105 101.496 ;
     RECT  32.281 101.712 32.389 101.736 ;
     RECT  32.105 100.704 32.461 100.728 ;
     RECT  32.389 101.712 33.013 101.976 ;
     RECT  33.001 103.2 33.013 103.224 ;
     RECT  29.704 35.712 33.073 35.976 ;
     RECT  33.013 101.712 33.329 103.224 ;
     RECT  32.461 100.368 33.493 100.728 ;
     RECT  33.493 99.696 33.539 100.728 ;
     RECT  33.329 101.952 33.577 103.224 ;
     RECT  33.539 99.696 33.617 100.392 ;
     RECT  33.577 101.952 33.683 103.416 ;
     RECT  33.683 101.952 33.725 103.224 ;
     RECT  33.725 102.768 33.797 103.224 ;
     RECT  33.617 99.696 34.729 99.72 ;
     RECT  29.704 3.024 34.808 3.048 ;
     RECT  29.704 8.784 34.808 8.808 ;
     RECT  29.704 14.64 34.808 14.664 ;
     RECT  29.704 20.352 34.808 20.376 ;
     RECT  34.597 34.464 34.808 34.488 ;
     RECT  33.073 35.712 34.808 36.072 ;
     RECT  33.505 53.856 34.808 53.88 ;
     RECT  29.704 56.208 34.808 56.232 ;
     RECT  29.704 61.344 34.808 61.464 ;
     RECT  29.704 73.488 34.808 74.328 ;
     RECT  29.704 80.4 34.808 80.424 ;
     RECT  29.704 92.928 34.808 93.768 ;
     RECT  34.729 99.552 34.808 99.72 ;
     RECT  33.797 103.2 34.808 103.224 ;
     RECT  32.317 105.12 34.808 105.144 ;
     RECT  34.808 2.148 34.912 105.852 ;
     RECT  34.912 2.418 35.077 105.852 ;
     RECT  35.077 2.418 35.104 105.96 ;
     RECT  35.104 105.936 35.165 105.96 ;
     RECT  35.104 99.552 35.219 100.488 ;
     RECT  35.104 101.616 35.219 101.64 ;
     RECT  35.104 102.672 35.219 104.04 ;
     RECT  35.104 53.76 35.603 53.88 ;
     RECT  35.104 72.144 35.603 74.328 ;
     RECT  35.603 73.488 35.777 74.328 ;
     RECT  35.219 99.696 35.932 100.488 ;
     RECT  35.104 14.64 36.097 14.664 ;
     RECT  35.104 15.792 36.097 16.728 ;
     RECT  35.104 34.464 36.209 37.272 ;
     RECT  36.14 101.808 36.227 101.832 ;
     RECT  36.209 34.464 36.421 34.488 ;
     RECT  35.219 103.056 36.421 103.224 ;
     RECT  35.104 97.92 36.457 98.52 ;
     RECT  36.209 35.76 36.467 37.272 ;
     RECT  36.097 11.952 36.493 11.976 ;
     RECT  36.241 104.88 36.493 104.904 ;
     RECT  35.104 8.784 36.517 8.808 ;
     RECT  36.097 14.64 36.569 16.728 ;
     RECT  36.517 8.448 36.604 8.808 ;
     RECT  36.467 35.856 36.641 37.272 ;
     RECT  35.932 99.744 36.745 100.488 ;
     RECT  36.457 97.92 36.749 98.76 ;
     RECT  36.493 11.952 36.817 12.936 ;
     RECT  35.104 9.936 36.853 9.96 ;
     RECT  36.817 11.952 36.853 13.176 ;
     RECT  36.569 14.64 36.853 16.248 ;
     RECT  36.853 11.952 36.899 16.248 ;
     RECT  36.749 97.92 36.949 97.944 ;
     RECT  36.641 35.904 36.997 37.272 ;
     RECT  35.104 38.736 36.997 38.76 ;
     RECT  36.949 97.008 37.036 97.944 ;
     RECT  36.899 15.792 37.073 16.248 ;
     RECT  36.997 35.904 37.101 38.76 ;
     RECT  36.385 5.088 37.109 5.112 ;
     RECT  35.104 3.024 37.141 4.008 ;
     RECT  37.101 35.904 37.145 38.04 ;
     RECT  35.603 53.856 37.177 53.88 ;
     RECT  35.104 18 37.285 18.024 ;
     RECT  35.104 20.352 37.285 20.376 ;
     RECT  35.777 73.776 37.285 74.328 ;
     RECT  37.073 15.792 37.325 16.056 ;
     RECT  37.285 18 37.325 18.216 ;
     RECT  36.899 11.952 37.331 14.664 ;
     RECT  36.997 84.336 37.331 84.36 ;
     RECT  37.244 85.488 37.331 85.512 ;
     RECT  37.105 88.944 37.381 88.968 ;
     RECT  36.745 99.744 37.397 101.304 ;
     RECT  37.381 88.8 37.427 88.968 ;
     RECT  36.421 34.128 37.429 34.488 ;
     RECT  37.285 87.264 37.469 87.72 ;
     RECT  37.397 100.08 37.469 101.304 ;
     RECT  35.104 56.208 37.484 56.232 ;
     RECT  37.484 57.6 37.501 57.624 ;
     RECT  37.177 53.856 37.525 54.456 ;
     RECT  37.484 55.44 37.525 56.232 ;
     RECT  37.525 53.856 37.571 56.232 ;
     RECT  37.501 57.6 37.571 58.152 ;
     RECT  37.141 2.64 37.573 4.008 ;
     RECT  37.285 19.392 37.573 20.376 ;
     RECT  36.421 102.576 37.58 103.224 ;
     RECT  37.58 102.384 37.609 103.224 ;
     RECT  37.285 73.776 37.619 75.288 ;
     RECT  37.501 77.52 37.619 77.544 ;
     RECT  36.493 104.88 37.649 105.48 ;
     RECT  37.469 100.08 37.667 101.016 ;
     RECT  37.649 105.456 37.757 105.48 ;
     RECT  37.331 11.952 37.793 13.704 ;
     RECT  37.82 96.672 37.907 96.696 ;
     RECT  37.609 102.144 37.907 103.224 ;
     RECT  37.033 6.24 38.041 6.264 ;
     RECT  35.603 72.144 38.041 72.168 ;
     RECT  35.104 92.928 38.101 93.768 ;
     RECT  38.041 96.72 38.101 96.744 ;
     RECT  37.573 2.64 38.113 4.056 ;
     RECT  36.604 8.592 38.113 8.808 ;
     RECT  37.609 10.944 38.113 10.968 ;
     RECT  37.793 11.952 38.113 11.976 ;
     RECT  38.06 95.472 38.147 95.496 ;
     RECT  36.241 33.024 38.156 33.048 ;
     RECT  38.101 96.72 38.188 96.888 ;
     RECT  38.041 72.144 38.195 72.696 ;
     RECT  36.853 9.888 38.197 9.96 ;
     RECT  38.113 10.944 38.197 11.976 ;
     RECT  38.156 32.448 38.197 33.048 ;
     RECT  37.429 34.128 38.197 34.776 ;
     RECT  37.145 35.904 38.197 36.792 ;
     RECT  37.036 97.92 38.221 97.944 ;
     RECT  38.197 31.92 38.243 36.792 ;
     RECT  38.113 2.64 38.245 4.536 ;
     RECT  38.041 6.24 38.245 6.84 ;
     RECT  37.145 38.016 38.257 38.04 ;
     RECT  38.197 9.792 38.291 11.976 ;
     RECT  37.325 15.792 38.293 16.008 ;
     RECT  38.101 92.928 38.297 94.2 ;
     RECT  37.325 18.192 38.329 18.216 ;
     RECT  37.573 19.392 38.329 21.336 ;
     RECT  37.753 83.856 38.329 83.88 ;
     RECT  38.221 97.92 38.329 98.28 ;
     RECT  38.245 2.64 38.332 6.84 ;
     RECT  38.332 2.64 38.333 4.968 ;
     RECT  37.571 53.856 38.333 54.696 ;
     RECT  38.332 6.096 38.341 6.84 ;
     RECT  38.113 8.544 38.341 8.808 ;
     RECT  38.293 30.672 38.341 30.696 ;
     RECT  38.341 6.096 38.365 8.808 ;
     RECT  38.291 9.792 38.365 11.736 ;
     RECT  38.329 18.192 38.365 21.336 ;
     RECT  38.365 6.096 38.387 11.736 ;
     RECT  38.341 30.24 38.387 30.696 ;
     RECT  38.243 33.264 38.387 36.792 ;
     RECT  38.297 92.928 38.396 93.528 ;
     RECT  38.387 35.472 38.405 36.792 ;
     RECT  38.257 38.016 38.405 38.568 ;
     RECT  38.387 7.776 38.428 7.8 ;
     RECT  37.571 58.128 38.437 58.152 ;
     RECT  38.396 92.016 38.437 93.528 ;
     RECT  38.365 18.192 38.483 22.008 ;
     RECT  38.437 91.92 38.483 93.528 ;
     RECT  38.483 92.928 38.521 93.528 ;
     RECT  37.571 56.208 38.545 56.232 ;
     RECT  37.717 63.792 38.653 63.816 ;
     RECT  38.545 56.208 38.657 56.952 ;
     RECT  38.293 15.792 38.693 16.728 ;
     RECT  37.793 13.152 38.712 13.704 ;
     RECT  38.257 14.784 38.712 14.808 ;
     RECT  37.427 88.8 38.725 88.824 ;
     RECT  38.387 33.264 38.729 34.152 ;
     RECT  37.469 87.264 38.729 87.288 ;
     RECT  38.483 18.192 38.765 20.472 ;
     RECT  38.725 88.8 38.765 88.92 ;
     RECT  38.712 13.152 38.773 14.808 ;
     RECT  38.693 15.792 38.773 16.392 ;
     RECT  38.437 58.128 38.789 58.728 ;
     RECT  37.619 73.776 38.797 75.24 ;
     RECT  37.573 76.32 38.797 76.344 ;
     RECT  38.521 92.928 38.801 93.384 ;
     RECT  38.773 13.152 38.819 16.392 ;
     RECT  38.405 35.904 38.837 36.792 ;
     RECT  38.819 15.408 38.873 16.392 ;
     RECT  38.387 30.24 38.873 30.264 ;
     RECT  38.789 58.128 38.873 59.304 ;
     RECT  37.285 82.512 38.905 82.536 ;
     RECT  38.905 82.272 38.945 82.536 ;
     RECT  38.905 70.08 38.989 70.104 ;
     RECT  38.657 56.208 39.013 56.232 ;
     RECT  38.873 58.128 39.013 58.728 ;
     RECT  38.329 83.856 39.013 84.312 ;
     RECT  38.873 15.792 39.053 16.392 ;
     RECT  39.013 57.552 39.059 58.728 ;
     RECT  38.797 73.776 39.059 76.344 ;
     RECT  38.108 68.784 39.085 68.808 ;
     RECT  38.819 13.152 39.197 13.944 ;
     RECT  38.765 88.896 39.197 88.92 ;
     RECT  38.761 86.688 39.265 86.712 ;
     RECT  38.333 3.024 39.301 4.968 ;
     RECT  38.387 6.096 39.301 6.6 ;
     RECT  38.581 40.944 39.301 40.968 ;
     RECT  38.195 72.144 39.301 72.168 ;
     RECT  39.059 73.776 39.301 73.8 ;
     RECT  38.869 66.144 39.337 66.168 ;
     RECT  39.013 56.064 39.373 56.232 ;
     RECT  39.013 83.76 39.373 84.312 ;
     RECT  38.149 103.632 39.445 103.656 ;
     RECT  39.301 40.08 39.481 40.968 ;
     RECT  39.481 40.08 39.5 41.064 ;
     RECT  35.104 80.4 39.553 80.424 ;
     RECT  39.373 83.616 39.553 84.312 ;
     RECT  38.437 25.68 39.589 25.704 ;
     RECT  38.333 53.856 39.589 54.12 ;
     RECT  39.301 67.632 39.661 67.656 ;
     RECT  39.085 68.736 39.661 68.808 ;
     RECT  39.337 66.048 39.697 66.168 ;
     RECT  39.661 67.632 39.697 68.808 ;
     RECT  39.049 95.376 39.697 95.4 ;
     RECT  38.188 96.72 39.697 96.744 ;
     RECT  39.697 96.672 39.74 96.744 ;
     RECT  38.329 97.92 39.74 98.472 ;
     RECT  38.729 33.552 39.781 34.152 ;
     RECT  38.483 91.92 39.805 91.944 ;
     RECT  38.801 93.024 39.805 93.384 ;
     RECT  39.805 91.92 39.877 93.384 ;
     RECT  38.945 82.272 39.949 82.296 ;
     RECT  38.387 8.784 40.057 11.736 ;
     RECT  39.301 3.024 40.069 6.6 ;
     RECT  38.765 18.576 40.069 20.472 ;
     RECT  38.483 21.984 40.069 22.008 ;
     RECT  38.509 48.192 40.069 48.216 ;
     RECT  39.193 64.944 40.069 64.968 ;
     RECT  39.697 66.048 40.069 68.808 ;
     RECT  40.069 2.784 40.093 6.6 ;
     RECT  39.445 103.632 40.093 103.752 ;
     RECT  39.5 40.08 40.129 41.736 ;
     RECT  40.069 49.2 40.129 49.224 ;
     RECT  39.589 25.248 40.165 25.704 ;
     RECT  39.781 33.552 40.165 34.68 ;
     RECT  38.837 35.904 40.165 36.552 ;
     RECT  40.093 2.784 40.208 6.84 ;
     RECT  40.057 7.968 40.208 11.736 ;
     RECT  39.197 13.152 40.208 13.656 ;
     RECT  40.129 14.736 40.208 14.76 ;
     RECT  39.053 16.368 40.208 16.392 ;
     RECT  40.069 18.576 40.208 22.008 ;
     RECT  40.165 25.248 40.208 25.848 ;
     RECT  39.229 27.936 40.208 27.96 ;
     RECT  40.165 30.384 40.208 30.408 ;
     RECT  38.243 31.92 40.208 31.944 ;
     RECT  40.165 33.552 40.208 36.552 ;
     RECT  38.405 38.544 40.208 38.568 ;
     RECT  40.129 39.792 40.208 41.736 ;
     RECT  38.689 43.92 40.208 43.944 ;
     RECT  39.517 45.648 40.208 45.672 ;
     RECT  40.069 47.856 40.208 48.216 ;
     RECT  40.129 49.2 40.208 49.608 ;
     RECT  39.589 52.992 40.208 54.12 ;
     RECT  39.373 55.728 40.208 56.232 ;
     RECT  39.059 57.552 40.208 57.576 ;
     RECT  39.059 58.704 40.208 58.728 ;
     RECT  39.373 60.336 40.208 60.36 ;
     RECT  35.104 61.344 40.208 61.464 ;
     RECT  38.653 63.312 40.208 63.816 ;
     RECT  40.069 64.944 40.208 68.808 ;
     RECT  39.301 72.144 40.208 73.8 ;
     RECT  39.059 74.928 40.208 76.344 ;
     RECT  38.869 79.008 40.208 79.032 ;
     RECT  39.553 80.352 40.208 80.424 ;
     RECT  39.949 81.456 40.208 82.296 ;
     RECT  39.553 83.616 40.208 84.6 ;
     RECT  39.265 85.776 40.208 86.712 ;
     RECT  39.769 88.752 40.208 88.776 ;
     RECT  39.877 91.872 40.208 93.384 ;
     RECT  39.697 94.848 40.208 95.4 ;
     RECT  39.74 96.672 40.208 98.472 ;
     RECT  37.667 100.08 40.208 100.92 ;
     RECT  37.907 102.144 40.208 102.6 ;
     RECT  40.093 103.584 40.208 103.752 ;
     RECT  40.208 2.148 40.312 105.852 ;
     RECT  40.312 2.418 40.504 105.582 ;
     RECT  40.504 7.968 40.565 8.52 ;
     RECT  40.504 103.584 40.565 103.608 ;
     RECT  40.504 14.736 40.601 15.336 ;
     RECT  40.504 25.152 40.601 25.272 ;
     RECT  40.504 39.264 40.637 41.016 ;
     RECT  40.504 52.416 40.643 56.952 ;
     RECT  40.504 73.008 40.643 76.488 ;
     RECT  40.504 69.84 40.691 71.352 ;
     RECT  40.643 75.888 40.704 76.488 ;
     RECT  40.504 49.584 40.709 50.76 ;
     RECT  40.504 94.944 40.745 94.968 ;
     RECT  40.504 27.36 40.889 27.96 ;
     RECT  40.504 45.696 40.961 47.352 ;
     RECT  40.504 5.184 40.997 6.984 ;
     RECT  40.504 67.152 41.027 68.424 ;
     RECT  40.504 77.472 41.027 78.648 ;
     RECT  40.997 6.816 41.033 6.984 ;
     RECT  40.504 9.792 41.033 13.416 ;
     RECT  40.637 39.264 41.069 39.816 ;
     RECT  40.643 55.92 41.075 56.952 ;
     RECT  40.504 102.096 41.075 102.6 ;
     RECT  40.961 45.696 41.105 46.008 ;
     RECT  40.504 80.352 41.105 80.424 ;
     RECT  40.504 17.472 41.141 17.544 ;
     RECT  41.105 45.888 41.141 46.008 ;
     RECT  40.504 65.712 41.141 65.736 ;
     RECT  41.033 10.368 41.177 13.416 ;
     RECT  40.504 31.776 41.213 35.736 ;
     RECT  40.504 2.88 41.249 3.432 ;
     RECT  41.141 17.52 41.249 17.544 ;
     RECT  41.027 78.384 41.249 78.648 ;
     RECT  40.997 5.184 41.285 5.784 ;
     RECT  41.177 10.416 41.285 13.416 ;
     RECT  41.285 11.952 41.315 13.416 ;
     RECT  40.504 99.12 41.315 100.728 ;
     RECT  41.141 45.984 41.321 46.008 ;
     RECT  41.075 102.576 41.321 102.6 ;
     RECT  40.504 57.984 41.363 62.808 ;
     RECT  41.363 57.984 41.411 62.424 ;
     RECT  40.504 81.456 41.411 87.24 ;
     RECT  40.565 7.968 41.429 7.992 ;
     RECT  40.504 38.16 41.429 38.184 ;
     RECT  40.709 49.824 41.437 50.76 ;
     RECT  41.411 57.984 41.437 59.256 ;
     RECT  41.033 6.816 41.452 6.84 ;
     RECT  41.437 57.984 41.452 58.008 ;
     RECT  41.411 81.456 41.452 85.416 ;
     RECT  40.601 14.736 41.459 15.288 ;
     RECT  41.411 86.592 41.497 87.24 ;
     RECT  41.315 12.048 41.501 13.416 ;
     RECT  40.504 30.384 41.501 30.648 ;
     RECT  40.504 88.464 41.533 89.592 ;
     RECT  41.285 10.416 41.537 10.44 ;
     RECT  40.691 69.84 41.537 69.864 ;
     RECT  40.504 91.728 41.564 91.752 ;
     RECT  41.533 88.464 41.569 89.976 ;
     RECT  41.564 90.96 41.569 91.752 ;
     RECT  41.437 59.232 41.603 59.256 ;
     RECT  41.569 88.464 41.605 91.752 ;
     RECT  40.643 52.416 41.609 54.792 ;
     RECT  40.504 97.92 41.641 98.136 ;
     RECT  41.249 2.88 41.645 3.384 ;
     RECT  40.637 40.944 41.645 41.016 ;
     RECT  41.249 78.624 41.645 78.648 ;
     RECT  41.609 52.416 41.677 54.552 ;
     RECT  41.213 31.776 41.681 33.048 ;
     RECT  41.677 51.552 41.681 54.552 ;
     RECT  41.452 81.456 41.681 85.224 ;
     RECT  41.605 88.464 41.699 91.8 ;
     RECT  41.501 12.624 41.717 13.416 ;
     RECT  41.285 5.76 41.753 5.784 ;
     RECT  40.504 16.368 41.753 16.392 ;
     RECT  41.213 34.128 41.753 35.736 ;
     RECT  41.681 81.456 41.753 83.784 ;
     RECT  41.713 36.864 41.785 36.888 ;
     RECT  41.701 65.136 41.788 65.16 ;
     RECT  41.645 2.88 41.789 3.336 ;
     RECT  41.411 60.288 41.789 62.424 ;
     RECT  41.699 88.464 41.789 90.312 ;
     RECT  41.315 99.552 41.789 100.728 ;
     RECT  40.504 96.432 41.797 96.888 ;
     RECT  41.069 39.264 41.821 39.576 ;
     RECT  41.789 88.464 41.821 88.776 ;
     RECT  40.504 19.536 41.845 20.376 ;
     RECT  40.704 75.888 41.845 76.44 ;
     RECT  41.753 34.704 41.852 35.736 ;
     RECT  40.504 21.984 41.857 22.008 ;
     RECT  41.699 91.776 41.857 91.8 ;
     RECT  41.753 82.656 41.861 83.784 ;
     RECT  41.845 75.888 41.891 76.728 ;
     RECT  41.641 97.92 41.891 98.328 ;
     RECT  41.075 55.92 41.897 56.424 ;
     RECT  41.681 85.152 41.897 85.224 ;
     RECT  41.797 95.712 41.897 96.888 ;
     RECT  41.677 26.736 41.939 26.76 ;
     RECT  41.857 21.744 41.941 22.776 ;
     RECT  40.889 27.936 41.969 27.96 ;
     RECT  41.105 80.4 42.001 80.424 ;
     RECT  41.753 81.456 42.001 81.624 ;
     RECT  41.437 49.824 42.005 49.848 ;
     RECT  41.857 91.776 42.005 91.896 ;
     RECT  41.701 66.48 42.037 66.504 ;
     RECT  41.027 67.632 42.037 67.752 ;
     RECT  40.504 92.928 42.073 93.384 ;
     RECT  41.784 17.616 42.077 18.216 ;
     RECT  41.897 95.712 42.101 96.552 ;
     RECT  41.852 34.704 42.109 35.88 ;
     RECT  41.785 36.864 42.109 37.608 ;
     RECT  41.821 39.072 42.109 39.576 ;
     RECT  40.691 71.328 42.113 71.352 ;
     RECT  41.845 19.344 42.133 20.376 ;
     RECT  41.941 21.744 42.133 22.008 ;
     RECT  40.504 64.032 42.145 64.056 ;
     RECT  41.501 30.384 42.149 30.6 ;
     RECT  41.645 40.944 42.149 40.968 ;
     RECT  42.133 19.344 42.179 22.008 ;
     RECT  42.073 92.928 42.179 93.864 ;
     RECT  41.821 42.192 42.181 42.744 ;
     RECT  40.504 44.064 42.181 44.088 ;
     RECT  41.891 76.704 42.185 76.728 ;
     RECT  41.681 32.16 42.217 33.048 ;
     RECT  42.001 80.4 42.253 81.624 ;
     RECT  42.217 32.16 42.257 33.384 ;
     RECT  42.236 4.368 42.277 4.392 ;
     RECT  42.179 19.536 42.293 21.768 ;
     RECT  41.821 88.32 42.293 88.776 ;
     RECT  42.181 42.192 42.317 44.088 ;
     RECT  42.277 4.368 42.323 5.208 ;
     RECT  42.317 42.192 42.329 44.472 ;
     RECT  42.329 43.296 42.361 44.472 ;
     RECT  42.253 45.696 42.361 45.72 ;
     RECT  42.253 80.352 42.365 81.624 ;
     RECT  42.361 43.296 42.371 45.72 ;
     RECT  40.643 73.008 42.397 74.856 ;
     RECT  42.293 19.536 42.401 21.048 ;
     RECT  42.371 44.448 42.401 45.72 ;
     RECT  41.897 55.92 42.401 56.328 ;
     RECT  42.077 17.616 42.428 17.64 ;
     RECT  42.037 66.48 42.437 67.752 ;
     RECT  41.459 14.832 42.473 14.856 ;
     RECT  42.293 88.752 42.473 88.776 ;
     RECT  41.897 85.152 42.509 85.176 ;
     RECT  42.428 16.656 42.515 17.64 ;
     RECT  41.861 82.656 42.545 82.776 ;
     RECT  42.101 95.184 42.613 96.552 ;
     RECT  42.613 95.088 42.653 96.552 ;
     RECT  42.109 39.072 42.668 39.864 ;
     RECT  41.681 52.704 42.685 54.552 ;
     RECT  41.497 86.592 42.685 87.288 ;
     RECT  42.149 30.528 42.721 30.6 ;
     RECT  41.681 51.552 42.721 51.576 ;
     RECT  42.437 66.48 42.721 66.696 ;
     RECT  42.541 26.832 42.725 26.856 ;
     RECT  42.325 29.04 42.725 29.064 ;
     RECT  40.961 47.328 42.725 47.352 ;
     RECT  42.323 5.184 42.755 5.208 ;
     RECT  41.789 99.552 42.757 100.104 ;
     RECT  42.469 6.288 42.761 7.128 ;
     RECT  42.721 30.528 42.761 30.792 ;
     RECT  42.257 32.256 42.793 33.384 ;
     RECT  42.109 34.704 42.793 37.608 ;
     RECT  42.721 51.456 42.793 51.576 ;
     RECT  42.685 52.704 42.793 54.792 ;
     RECT  42.145 63.888 42.793 64.248 ;
     RECT  42.515 17.136 42.797 17.64 ;
     RECT  42.401 56.208 42.797 56.328 ;
     RECT  42.757 99.552 42.803 100.92 ;
     RECT  42.005 91.872 42.833 91.896 ;
     RECT  42.793 32.256 42.853 37.608 ;
     RECT  42.653 96.528 42.869 96.552 ;
     RECT  42.757 67.92 42.899 68.376 ;
     RECT  42.397 72.096 42.899 74.856 ;
     RECT  42.853 32.256 42.94 38.04 ;
     RECT  42.145 69.696 42.941 69.72 ;
     RECT  42.685 86.592 42.941 87.72 ;
     RECT  42.941 86.592 42.947 87.24 ;
     RECT  41.789 60.288 42.949 61.464 ;
     RECT  42.793 15.36 42.973 15.384 ;
     RECT  42.797 17.136 42.977 17.592 ;
     RECT  42.793 62.784 42.977 64.248 ;
     RECT  42.793 51.456 42.997 54.792 ;
     RECT  41.789 90.288 43.045 90.312 ;
     RECT  42.853 70.8 43.049 70.824 ;
     RECT  42.803 100.896 43.049 100.92 ;
     RECT  42.668 39.072 43.085 40.488 ;
     RECT  42.977 62.784 43.117 63.912 ;
     RECT  42.365 80.352 43.117 80.568 ;
     RECT  42.761 30.576 43.189 30.792 ;
     RECT  42.797 56.304 43.189 56.328 ;
     RECT  42.865 57.552 43.189 57.576 ;
     RECT  42.865 76.992 43.189 77.688 ;
     RECT  42.179 92.928 43.189 93.384 ;
     RECT  42.947 86.592 43.193 86.616 ;
     RECT  43.189 76.368 43.229 77.688 ;
     RECT  42.977 17.136 43.265 17.544 ;
     RECT  42.401 44.928 43.265 45.72 ;
     RECT  43.081 48.384 43.297 48.408 ;
     RECT  42.721 66.336 43.297 66.696 ;
     RECT  41.861 83.76 43.297 83.784 ;
     RECT  43.265 44.928 43.301 44.952 ;
     RECT  43.189 8.64 43.333 8.664 ;
     RECT  43.189 30.576 43.333 31.032 ;
     RECT  42.94 32.256 43.333 37.464 ;
     RECT  43.085 39.072 43.333 39.096 ;
     RECT  43.297 65.472 43.337 66.696 ;
     RECT  43.297 48.096 43.369 48.408 ;
     RECT  42.949 60.288 43.369 61.608 ;
     RECT  43.117 62.736 43.369 63.912 ;
     RECT  43.369 60.288 43.373 63.912 ;
     RECT  43.333 8.64 43.379 9.192 ;
     RECT  43.333 30.576 43.379 37.464 ;
     RECT  42.721 42.144 43.388 42.168 ;
     RECT  42.973 15.36 43.409 15.432 ;
     RECT  43.085 40.416 43.429 40.488 ;
     RECT  43.388 42.096 43.429 42.168 ;
     RECT  42.371 43.344 43.429 43.368 ;
     RECT  43.297 85.248 43.441 85.272 ;
     RECT  43.429 42.096 43.475 43.368 ;
     RECT  43.441 85.248 43.477 86.232 ;
     RECT  43.189 56.304 43.481 57.576 ;
     RECT  41.717 13.392 43.513 13.416 ;
     RECT  43.153 18.72 43.513 18.744 ;
     RECT  43.337 65.472 43.513 65.496 ;
     RECT  43.189 92.928 43.532 93.624 ;
     RECT  43.481 57.552 43.557 57.576 ;
     RECT  42.541 58.896 43.557 58.92 ;
     RECT  42.997 50.496 43.573 54.792 ;
     RECT  43.532 92.544 43.585 93.624 ;
     RECT  42.653 95.088 43.585 95.112 ;
     RECT  43.573 50.496 43.619 55.032 ;
     RECT  43.585 92.544 43.619 95.112 ;
     RECT  43.513 13.392 43.621 13.848 ;
     RECT  42.401 20.352 43.621 21.048 ;
     RECT  42.899 67.92 43.621 67.944 ;
     RECT  42.545 82.656 43.621 82.68 ;
     RECT  43.297 83.76 43.621 84.12 ;
     RECT  42.899 72.144 43.625 74.856 ;
     RECT  43.379 9.168 43.661 9.192 ;
     RECT  43.477 85.104 43.661 86.232 ;
     RECT  43.333 38.688 43.697 39.096 ;
     RECT  43.619 92.928 43.697 95.112 ;
     RECT  43.379 30.576 43.765 30.792 ;
     RECT  43.045 89.376 43.769 90.312 ;
     RECT  43.229 76.368 43.772 77.016 ;
     RECT  43.765 30.096 43.801 30.792 ;
     RECT  43.621 20.352 43.813 21.672 ;
     RECT  43.837 44.688 43.873 44.712 ;
     RECT  43.557 57.552 43.907 58.92 ;
     RECT  43.769 89.904 43.909 90.312 ;
     RECT  43.475 42.144 43.913 43.368 ;
     RECT  43.117 79.68 43.913 80.568 ;
     RECT  41.891 97.92 43.913 97.944 ;
     RECT  43.801 29.856 44.021 30.792 ;
     RECT  43.772 75.792 44.021 77.016 ;
     RECT  43.619 55.008 44.057 55.032 ;
     RECT  43.621 13.056 44.089 13.848 ;
     RECT  43.369 48.096 44.149 48.456 ;
     RECT  43.441 23.136 44.161 23.16 ;
     RECT  43.261 27.312 44.161 27.336 ;
     RECT  44.161 27.312 44.201 27.96 ;
     RECT  43.379 31.872 44.237 37.464 ;
     RECT  43.913 80.352 44.237 80.568 ;
     RECT  43.265 17.136 44.269 17.16 ;
     RECT  44.269 17.136 44.305 17.208 ;
     RECT  43.513 18.72 44.305 18.84 ;
     RECT  43.913 42.384 44.305 43.368 ;
     RECT  43.873 44.592 44.305 44.712 ;
     RECT  44.197 69.504 44.305 69.528 ;
     RECT  42.365 81.6 44.305 81.624 ;
     RECT  43.621 82.656 44.305 84.12 ;
     RECT  43.619 50.496 44.309 53.592 ;
     RECT  44.305 81.6 44.345 84.12 ;
     RECT  41.789 3.312 44.381 3.336 ;
     RECT  44.305 42.384 44.381 44.712 ;
     RECT  43.907 57.84 44.413 58.92 ;
     RECT  44.237 36.24 44.417 37.464 ;
     RECT  43.429 40.416 44.417 41.064 ;
     RECT  44.089 12.24 44.437 13.848 ;
     RECT  43.513 65.376 44.437 65.496 ;
     RECT  44.305 17.136 44.449 18.84 ;
     RECT  43.813 20.208 44.449 21.672 ;
     RECT  44.161 23.136 44.449 24.12 ;
     RECT  40.601 25.152 44.449 25.176 ;
     RECT  43.373 60.288 44.449 63.048 ;
     RECT  43.909 89.904 44.449 90.6 ;
     RECT  44.237 31.872 44.453 35.208 ;
     RECT  44.021 76.992 44.485 77.016 ;
     RECT  43.409 15.36 44.489 15.384 ;
     RECT  44.201 27.936 44.489 27.96 ;
     RECT  44.345 81.984 44.521 84.12 ;
     RECT  43.661 85.104 44.521 86.184 ;
     RECT  44.437 64.944 44.524 65.496 ;
     RECT  44.437 12.24 44.561 14.232 ;
     RECT  44.449 20.16 44.593 21.672 ;
     RECT  44.449 23.136 44.593 25.176 ;
     RECT  44.453 33.36 44.597 35.208 ;
     RECT  43.225 47.04 44.629 47.064 ;
     RECT  44.377 66.72 44.629 66.744 ;
     RECT  43.621 67.824 44.629 67.944 ;
     RECT  44.521 81.984 44.629 86.184 ;
     RECT  44.269 87.216 44.629 87.24 ;
     RECT  44.305 68.976 44.633 69.528 ;
     RECT  43.625 72.144 44.665 74.712 ;
     RECT  43.697 38.688 44.701 38.808 ;
     RECT  44.417 40.416 44.701 40.44 ;
     RECT  44.449 60.288 44.737 63.096 ;
     RECT  44.149 48.096 44.773 49.176 ;
     RECT  44.309 50.496 44.773 53.016 ;
     RECT  44.593 20.16 44.845 25.176 ;
     RECT  44.021 29.856 44.953 30.6 ;
     RECT  44.417 37.44 44.953 37.464 ;
     RECT  44.701 38.688 44.953 40.44 ;
     RECT  43.621 11.04 44.965 11.064 ;
     RECT  44.449 16.512 44.965 18.84 ;
     RECT  44.629 46.608 44.965 47.064 ;
     RECT  44.773 48.096 44.965 53.016 ;
     RECT  42.803 99.552 44.965 99.576 ;
     RECT  44.965 15.552 44.989 18.84 ;
     RECT  44.629 66.72 44.989 67.944 ;
     RECT  44.633 68.976 44.989 69.048 ;
     RECT  44.237 80.496 44.989 80.568 ;
     RECT  44.413 26.784 45.013 26.808 ;
     RECT  44.737 60.288 45.013 63.816 ;
     RECT  44.381 42.384 45.025 44.184 ;
     RECT  44.845 96.288 45.025 96.312 ;
     RECT  44.965 99.168 45.061 99.576 ;
     RECT  44.305 88.608 45.157 88.632 ;
     RECT  45.013 60.192 45.349 63.816 ;
     RECT  44.665 72.144 45.385 75.432 ;
     RECT  44.485 76.992 45.385 77.592 ;
     RECT  43.697 92.928 45.445 94.584 ;
     RECT  44.989 15.552 45.457 18.888 ;
     RECT  44.845 19.872 45.457 25.176 ;
     RECT  43.481 56.304 45.457 56.328 ;
     RECT  44.953 79.008 45.529 79.032 ;
     RECT  45.457 15.552 45.565 25.176 ;
     RECT  45.013 26.208 45.565 26.808 ;
     RECT  44.417 36.24 45.565 36.264 ;
     RECT  44.953 37.44 45.565 40.44 ;
     RECT  44.965 46.608 45.565 53.016 ;
     RECT  45.445 92.592 45.565 94.584 ;
     RECT  45.025 96 45.565 96.312 ;
     RECT  44.413 70.896 45.601 70.92 ;
     RECT  45.385 72.144 45.601 77.592 ;
     RECT  45.157 88.608 45.601 88.92 ;
     RECT  44.449 89.904 45.601 90.744 ;
     RECT  42.761 7.104 45.608 7.128 ;
     RECT  44.965 10.512 45.608 11.064 ;
     RECT  44.561 12.24 45.608 13.848 ;
     RECT  45.565 15.552 45.608 26.808 ;
     RECT  44.701 27.984 45.608 28.008 ;
     RECT  44.953 29.76 45.608 30.6 ;
     RECT  44.453 31.872 45.608 32.28 ;
     RECT  44.597 34.176 45.608 35.208 ;
     RECT  45.565 36.24 45.608 40.44 ;
     RECT  45.025 42.192 45.608 44.184 ;
     RECT  45.565 46.608 45.608 53.064 ;
     RECT  44.845 54.624 45.608 54.648 ;
     RECT  45.457 56.304 45.608 56.376 ;
     RECT  44.413 57.84 45.608 58.968 ;
     RECT  45.349 60.192 45.608 64.104 ;
     RECT  44.524 65.472 45.608 65.496 ;
     RECT  44.989 66.72 45.608 69.048 ;
     RECT  45.601 70.896 45.608 77.592 ;
     RECT  45.529 78.72 45.608 79.032 ;
     RECT  44.989 80.496 45.608 80.664 ;
     RECT  44.629 81.984 45.608 87.24 ;
     RECT  45.601 88.608 45.608 90.744 ;
     RECT  45.565 92.592 45.608 96.312 ;
     RECT  45.241 97.392 45.608 97.416 ;
     RECT  45.061 98.64 45.608 99.576 ;
     RECT  45.608 2.148 45.712 105.852 ;
     RECT  45.712 2.418 45.904 105.582 ;
     RECT  45.904 27.696 46.019 30.984 ;
     RECT  45.904 54.096 46.019 62.568 ;
     RECT  45.904 80.496 46.019 81.624 ;
     RECT  46.019 55.776 46.067 62.568 ;
     RECT  45.904 14.64 46.073 17.64 ;
     RECT  45.904 20.16 46.073 20.424 ;
     RECT  45.904 25.728 46.109 26.568 ;
     RECT  45.904 77.616 46.109 79.224 ;
     RECT  45.904 86.544 46.145 86.856 ;
     RECT  45.904 92.304 46.145 98.664 ;
     RECT  46.019 27.696 46.181 29.064 ;
     RECT  45.904 22.032 46.217 24.552 ;
     RECT  45.904 71.088 46.217 74.712 ;
     RECT  46.067 56.304 46.325 62.568 ;
     RECT  46.145 86.544 46.397 86.568 ;
     RECT  46.325 56.304 46.433 62.04 ;
     RECT  46.145 92.304 46.469 96.648 ;
     RECT  45.904 41.04 46.505 47.064 ;
     RECT  46.433 56.352 46.505 62.04 ;
     RECT  46.505 41.04 46.541 46.008 ;
     RECT  46.505 46.992 46.541 47.064 ;
     RECT  45.904 76.032 46.595 76.44 ;
     RECT  46.541 44.448 46.613 46.008 ;
     RECT  46.469 92.304 46.685 95.208 ;
     RECT  46.217 23.712 46.691 24.552 ;
     RECT  45.904 51.744 46.721 53.064 ;
     RECT  46.691 23.712 46.732 24.12 ;
     RECT  46.613 44.448 46.757 45.624 ;
     RECT  45.904 48.288 46.787 49.608 ;
     RECT  46.073 14.64 46.793 16.584 ;
     RECT  46.721 51.744 46.793 53.016 ;
     RECT  46.505 57.312 46.793 62.04 ;
     RECT  46.793 59.472 46.835 62.04 ;
     RECT  46.787 48.672 46.865 48.696 ;
     RECT  45.904 64.08 46.865 64.392 ;
     RECT  46.793 57.312 46.873 58.344 ;
     RECT  45.904 12.24 46.885 13.656 ;
     RECT  46.793 14.64 46.885 16.008 ;
     RECT  45.904 19.056 46.897 19.08 ;
     RECT  46.073 20.16 46.897 20.376 ;
     RECT  46.181 27.888 46.901 29.064 ;
     RECT  46.757 44.448 46.901 45.384 ;
     RECT  45.904 82.704 46.901 84.216 ;
     RECT  45.904 88.272 46.901 91.224 ;
     RECT  46.873 58.32 46.924 58.344 ;
     RECT  46.885 12.24 46.931 16.008 ;
     RECT  46.901 44.448 46.937 44.472 ;
     RECT  45.904 65.568 46.969 65.592 ;
     RECT  46.931 12.72 46.972 13.848 ;
     RECT  46.732 24.096 46.973 24.12 ;
     RECT  46.145 97.728 46.973 98.664 ;
     RECT  46.217 71.088 46.981 73.224 ;
     RECT  46.973 97.92 47.005 98.664 ;
     RECT  46.793 51.744 47.009 52.44 ;
     RECT  45.904 67.824 47.036 69.528 ;
     RECT  46.981 70.656 47.037 73.224 ;
     RECT  46.901 83.856 47.045 84.216 ;
     RECT  46.865 64.224 47.077 64.392 ;
     RECT  46.969 65.568 47.077 66.504 ;
     RECT  46.019 30.96 47.113 30.984 ;
     RECT  46.019 54.096 47.117 54.696 ;
     RECT  47.037 70.656 47.117 71.112 ;
     RECT  47.036 67.824 47.123 69.672 ;
     RECT  46.897 19.056 47.149 20.376 ;
     RECT  46.931 15.36 47.153 16.008 ;
     RECT  47.117 54.096 47.153 54.12 ;
     RECT  46.469 96.192 47.185 96.648 ;
     RECT  46.972 13.248 47.189 13.848 ;
     RECT  46.835 59.472 47.189 59.496 ;
     RECT  46.109 25.728 47.221 26.088 ;
     RECT  47.077 64.224 47.221 66.504 ;
     RECT  47.123 67.824 47.221 68.952 ;
     RECT  46.873 57.312 47.225 57.336 ;
     RECT  46.835 60.96 47.261 62.04 ;
     RECT  47.045 84.192 47.261 84.216 ;
     RECT  45.904 33.504 47.269 35.16 ;
     RECT  45.904 36.24 47.293 36.936 ;
     RECT  47.149 19.056 47.315 21.288 ;
     RECT  46.019 80.496 47.315 81.048 ;
     RECT  47.037 72.144 47.317 73.224 ;
     RECT  46.217 74.4 47.317 74.712 ;
     RECT  46.901 88.368 47.333 91.224 ;
     RECT  46.685 92.304 47.333 93.768 ;
     RECT  47.269 32.976 47.369 35.16 ;
     RECT  47.221 64.224 47.369 68.952 ;
     RECT  47.315 80.496 47.369 80.52 ;
     RECT  47.369 64.224 47.404 68.712 ;
     RECT  47.009 51.888 47.405 52.44 ;
     RECT  47.315 19.248 47.437 21.288 ;
     RECT  46.073 17.616 47.473 17.64 ;
     RECT  47.473 17.136 47.513 17.64 ;
     RECT  47.185 96.192 47.513 96.744 ;
     RECT  46.109 78.048 47.603 79.224 ;
     RECT  47.005 97.92 47.66 98.76 ;
     RECT  47.581 22.8 47.693 22.824 ;
     RECT  47.333 88.368 47.693 90.696 ;
     RECT  47.404 64.224 47.699 64.872 ;
     RECT  47.404 66.144 47.699 68.712 ;
     RECT  47.333 92.928 47.725 93.768 ;
     RECT  46.685 94.896 47.725 95.208 ;
     RECT  47.699 64.848 47.729 64.872 ;
     RECT  47.66 97.92 47.729 99.096 ;
     RECT  47.729 99.072 47.747 99.096 ;
     RECT  47.117 70.752 47.801 71.112 ;
     RECT  47.701 102 47.801 102.024 ;
     RECT  47.189 13.248 47.837 13.656 ;
     RECT  47.801 70.752 47.837 70.92 ;
     RECT  47.756 84.912 47.843 84.936 ;
     RECT  47.725 92.928 47.852 95.208 ;
     RECT  46.901 27.888 47.873 29.016 ;
     RECT  47.113 30.576 47.873 30.984 ;
     RECT  47.369 33.648 47.893 35.16 ;
     RECT  47.293 36.24 47.893 37.032 ;
     RECT  47.837 13.392 47.909 13.656 ;
     RECT  47.761 22.752 47.909 22.776 ;
     RECT  47.405 51.888 47.909 51.912 ;
     RECT  47.837 70.848 47.909 70.92 ;
     RECT  46.595 76.032 47.909 76.056 ;
     RECT  47.603 78.048 47.909 78.072 ;
     RECT  47.603 79.2 47.909 79.224 ;
     RECT  47.113 82.08 47.909 82.104 ;
     RECT  47.893 33.648 47.939 37.032 ;
     RECT  47.852 92.928 47.939 95.928 ;
     RECT  47.939 35.424 47.98 37.032 ;
     RECT  47.9 50.688 47.987 50.712 ;
     RECT  47.909 13.536 48.017 13.656 ;
     RECT  47.909 70.896 48.017 70.92 ;
     RECT  47.729 97.92 48.085 98.088 ;
     RECT  47.699 66.144 48.089 68.52 ;
     RECT  47.221 25.44 48.125 26.088 ;
     RECT  47.317 72.144 48.125 74.712 ;
     RECT  47.261 60.96 48.161 61.656 ;
     RECT  46.541 41.04 48.169 43.32 ;
     RECT  48.125 72.144 48.179 72.36 ;
     RECT  47.939 33.648 48.192 34.2 ;
     RECT  46.541 47.04 48.193 47.064 ;
     RECT  47.939 92.928 48.197 94.92 ;
     RECT  48.192 33.648 48.205 33.672 ;
     RECT  48.085 97.2 48.22 98.088 ;
     RECT  48.125 73.488 48.229 74.712 ;
     RECT  47.873 30.576 48.265 30.84 ;
     RECT  47.153 15.36 48.269 15.72 ;
     RECT  48.089 66.144 48.269 66.984 ;
     RECT  47.693 88.368 48.269 90.648 ;
     RECT  48.193 54.672 48.277 54.696 ;
     RECT  48.236 55.92 48.277 55.944 ;
     RECT  48.017 13.536 48.305 13.608 ;
     RECT  48.277 54.672 48.323 55.944 ;
     RECT  48.269 66.144 48.341 66.696 ;
     RECT  48.197 93.216 48.341 94.92 ;
     RECT  48.22 97.488 48.341 98.088 ;
     RECT  48.169 41.328 48.413 43.32 ;
     RECT  47.941 53.52 48.449 53.544 ;
     RECT  47.437 19.248 48.485 21.672 ;
     RECT  48.265 30.24 48.485 30.84 ;
     RECT  48.089 68.496 48.521 68.52 ;
     RECT  48.341 93.36 48.521 94.92 ;
     RECT  48.341 66.144 48.557 66.504 ;
     RECT  48.265 62.736 48.589 62.76 ;
     RECT  48.485 20.544 48.62 21.672 ;
     RECT  48.517 22.656 48.62 22.68 ;
     RECT  48.269 88.464 48.629 90.648 ;
     RECT  48.305 13.584 48.665 13.608 ;
     RECT  48.485 30.24 48.665 30.696 ;
     RECT  47.869 59.856 48.701 59.88 ;
     RECT  48.62 20.544 48.707 22.68 ;
     RECT  48.413 41.328 48.707 43.032 ;
     RECT  47.98 36.24 48.729 37.032 ;
     RECT  48.665 30.576 48.737 30.696 ;
     RECT  48.161 60.96 48.737 61.176 ;
     RECT  48.737 61.056 48.773 61.176 ;
     RECT  48.485 19.248 48.805 19.272 ;
     RECT  48.229 73.488 48.809 74.76 ;
     RECT  47.513 17.136 48.851 17.16 ;
     RECT  47.761 45.456 48.881 45.48 ;
     RECT  48.805 18.192 48.892 19.272 ;
     RECT  45.904 39.984 48.949 40.008 ;
     RECT  47.873 27.888 48.953 28.68 ;
     RECT  47.257 86.016 48.953 86.04 ;
     RECT  48.373 64.944 48.989 64.968 ;
     RECT  48.908 38.016 48.995 38.04 ;
     RECT  48.949 39.264 48.995 40.008 ;
     RECT  48.729 37.008 48.997 37.032 ;
     RECT  48.589 44.448 49.061 44.472 ;
     RECT  47.869 49.344 49.061 49.368 ;
     RECT  48.589 62.736 49.097 63.24 ;
     RECT  48.521 93.36 49.132 94.056 ;
     RECT  48.707 41.712 49.205 43.032 ;
     RECT  48.557 66.144 49.205 66.168 ;
     RECT  48.193 46.752 49.237 47.304 ;
     RECT  49.132 94.032 49.241 94.056 ;
     RECT  48.913 54.048 49.313 54.072 ;
     RECT  48.323 55.248 49.313 55.272 ;
     RECT  47.939 95.904 49.313 95.928 ;
     RECT  48.341 97.488 49.313 97.512 ;
     RECT  49.205 42.192 49.525 43.032 ;
     RECT  48.949 22.704 49.565 22.728 ;
     RECT  48.953 27.888 49.565 28.536 ;
     RECT  48.179 72.336 49.597 72.36 ;
     RECT  48.809 73.488 49.597 73.512 ;
     RECT  48.707 20.544 49.601 21.144 ;
     RECT  49.525 42.192 49.612 43.752 ;
     RECT  48.892 18.192 49.637 18.216 ;
     RECT  48.125 25.776 49.637 26.088 ;
     RECT  49.597 72.336 49.637 72.456 ;
     RECT  47.701 103.2 49.637 103.224 ;
     RECT  49.237 46.656 49.709 47.304 ;
     RECT  49.097 62.736 49.709 62.76 ;
     RECT  49.597 73.44 49.763 73.512 ;
     RECT  48.737 30.576 49.772 30.6 ;
     RECT  49.763 73.488 49.781 73.512 ;
     RECT  49.772 30.432 49.813 30.6 ;
     RECT  47.833 32.448 49.813 32.472 ;
     RECT  49.489 23.904 49.849 23.928 ;
     RECT  49.813 31.92 49.853 32.472 ;
     RECT  49.853 31.92 49.897 31.944 ;
     RECT  49.612 42.192 49.961 43.032 ;
     RECT  49.709 46.656 50.101 47.016 ;
     RECT  48.809 74.736 50.101 74.76 ;
     RECT  49.669 83.184 50.101 83.208 ;
     RECT  49.637 72.432 50.317 72.456 ;
     RECT  48.269 15.696 50.461 15.72 ;
     RECT  50.444 50.112 50.485 50.136 ;
     RECT  48.773 61.056 50.677 61.08 ;
     RECT  48.629 88.464 50.713 89.16 ;
     RECT  50.569 107.856 50.771 107.88 ;
     RECT  49.565 28.128 50.78 28.536 ;
     RECT  50.78 27.744 50.821 28.536 ;
     RECT  50.317 72.432 50.869 72.504 ;
     RECT  48.629 90.624 50.869 90.648 ;
     RECT  50.677 91.824 50.869 91.848 ;
     RECT  50.677 60.096 50.893 61.08 ;
     RECT  49.961 43.008 50.929 43.032 ;
     RECT  50.641 44.16 50.929 44.184 ;
     RECT  50.461 15.696 51.008 16.056 ;
     RECT  48.892 19.248 51.008 19.272 ;
     RECT  49.601 21.12 51.008 21.144 ;
     RECT  49.849 23.088 51.008 23.928 ;
     RECT  49.885 25.152 51.008 25.176 ;
     RECT  49.849 26.352 51.008 26.76 ;
     RECT  50.821 27.744 51.008 28.968 ;
     RECT  49.813 30.192 51.008 30.6 ;
     RECT  48.995 39.264 51.008 39.288 ;
     RECT  50.437 41.088 51.008 41.112 ;
     RECT  50.929 43.008 51.008 44.184 ;
     RECT  50.101 46.032 51.008 47.016 ;
     RECT  50.485 50.112 51.008 51.048 ;
     RECT  50.732 54.528 51.008 54.552 ;
     RECT  50.773 56.496 51.008 56.52 ;
     RECT  50.893 60.096 51.008 61.176 ;
     RECT  50.869 70.08 51.008 70.104 ;
     RECT  50.869 71.472 51.008 72.504 ;
     RECT  50.101 74.592 51.008 74.76 ;
     RECT  50.101 75.936 51.008 75.96 ;
     RECT  48.913 80.112 51.008 80.136 ;
     RECT  50.101 82.608 51.008 83.592 ;
     RECT  50.713 88.464 51.008 89.256 ;
     RECT  50.869 90.624 51.008 91.848 ;
     RECT  50.461 94.032 51.008 94.056 ;
     RECT  50.453 95.664 51.008 95.688 ;
     RECT  50.965 98.64 51.008 98.664 ;
     RECT  51.008 2.148 51.112 105.852 ;
     RECT  51.112 2.418 51.304 105.582 ;
     RECT  51.304 43.008 51.443 44.184 ;
     RECT  51.304 98.352 51.539 98.664 ;
     RECT  51.304 62.832 51.587 62.856 ;
     RECT  51.304 64.8 51.587 64.824 ;
     RECT  51.304 95.664 51.617 95.736 ;
     RECT  51.304 72.48 51.653 72.504 ;
     RECT  51.617 95.664 51.689 95.688 ;
     RECT  51.304 66.48 51.797 66.744 ;
     RECT  51.304 71.232 51.869 71.496 ;
     RECT  51.304 59.28 51.875 60.12 ;
     RECT  51.875 59.28 51.977 59.88 ;
     RECT  51.304 83.76 52.163 84.744 ;
     RECT  51.304 18.144 52.252 19.944 ;
     RECT  51.304 88.464 52.259 90.12 ;
     RECT  52.252 18.144 52.307 18.168 ;
     RECT  52.259 90.096 52.445 90.12 ;
     RECT  51.304 23.088 52.453 23.4 ;
     RECT  51.304 28.224 52.453 28.968 ;
     RECT  52.453 22.8 52.553 23.4 ;
     RECT  52.453 28.224 52.556 29.112 ;
     RECT  51.304 30.288 52.556 30.312 ;
     RECT  52.556 28.224 52.597 30.312 ;
     RECT  52.597 28.224 52.643 30.888 ;
     RECT  52.259 88.464 52.697 88.92 ;
     RECT  52.643 28.224 52.909 29.112 ;
     RECT  52.163 84.72 52.913 84.744 ;
     RECT  52.909 28.08 52.949 29.112 ;
     RECT  52.252 19.248 52.979 19.944 ;
     RECT  51.304 41.76 52.985 41.784 ;
     RECT  52.979 19.248 53.027 19.704 ;
     RECT  52.553 22.8 53.027 22.824 ;
     RECT  52.94 93.6 53.027 93.624 ;
     RECT  51.304 15.792 53.093 16.44 ;
     RECT  53.093 15.792 53.123 16.2 ;
     RECT  53.027 19.248 53.123 19.368 ;
     RECT  51.443 43.008 53.125 43.032 ;
     RECT  51.304 81.072 53.125 81.096 ;
     RECT  51.304 45.552 53.189 46.056 ;
     RECT  51.304 61.152 53.193 61.224 ;
     RECT  53.189 45.552 53.228 46.776 ;
     RECT  53.228 45.552 53.273 47.256 ;
     RECT  53.273 47.232 53.315 47.256 ;
     RECT  51.304 50.832 53.315 50.856 ;
     RECT  53.233 51.888 53.317 51.912 ;
     RECT  51.869 71.232 53.381 71.4 ;
     RECT  51.304 91.44 53.509 91.464 ;
     RECT  51.304 74.592 53.525 74.616 ;
     RECT  53.509 90.576 53.555 91.464 ;
     RECT  53.193 61.2 53.557 61.224 ;
     RECT  53.125 62.976 53.557 63 ;
     RECT  53.557 61.2 53.597 63 ;
     RECT  53.564 24.096 53.605 24.12 ;
     RECT  51.797 66.72 53.633 66.744 ;
     RECT  53.605 23.328 53.651 24.12 ;
     RECT  51.304 21.12 53.741 21.144 ;
     RECT  51.304 56.688 53.843 56.712 ;
     RECT  52.949 28.08 53.891 28.104 ;
     RECT  53.605 25.968 53.913 25.992 ;
     RECT  52.643 30.864 53.989 30.888 ;
     RECT  53.555 90.576 54.065 91.224 ;
     RECT  53.597 62.112 54.281 63 ;
     RECT  53.125 81.072 54.284 81.768 ;
     RECT  54.229 40.176 54.316 40.2 ;
     RECT  54.284 81.072 54.371 82.056 ;
     RECT  52.981 94.656 54.425 94.68 ;
     RECT  53.381 71.232 54.533 71.256 ;
     RECT  53.651 23.328 54.605 23.352 ;
     RECT  52.949 29.088 54.673 29.112 ;
     RECT  53.989 30.672 54.673 30.888 ;
     RECT  53.123 15.984 54.709 16.008 ;
     RECT  54.673 29.088 54.709 30.888 ;
     RECT  54.709 15.84 54.755 16.008 ;
     RECT  54.709 29.088 54.851 30.984 ;
     RECT  54.851 30.96 54.947 30.984 ;
     RECT  51.304 13.824 54.997 13.848 ;
     RECT  54.997 13.152 55.037 13.848 ;
     RECT  54.949 17.04 55.145 17.064 ;
     RECT  54.851 29.088 55.237 29.832 ;
     RECT  55.237 29.04 55.283 29.832 ;
     RECT  54.281 62.592 55.389 63 ;
     RECT  55.037 13.152 56.408 13.176 ;
     RECT  54.755 15.84 56.408 15.864 ;
     RECT  53.123 19.248 56.408 19.272 ;
     RECT  55.283 29.04 56.408 29.064 ;
     RECT  54.901 33.024 56.408 33.048 ;
     RECT  53.125 42.144 56.408 43.032 ;
     RECT  54.817 51.936 56.408 51.96 ;
     RECT  53.797 54.384 56.408 54.408 ;
     RECT  55.389 62.976 56.408 63 ;
     RECT  55.333 64.416 56.408 64.44 ;
     RECT  55.861 72.432 56.408 72.456 ;
     RECT  54.371 81.072 56.408 81.096 ;
     RECT  54.325 83.76 56.408 83.784 ;
     RECT  52.697 88.896 56.408 88.92 ;
     RECT  54.065 91.2 56.408 91.224 ;
     RECT  51.539 98.352 56.408 98.376 ;
     RECT  56.408 2.148 56.512 105.852 ;
     RECT  56.512 2.418 56.704 105.582 ;
     RECT  56.545 107.184 56.723 107.208 ;
     RECT  56.704 13.152 56.765 13.176 ;
     RECT  56.704 29.04 56.801 29.064 ;
     RECT  56.704 79.536 56.819 79.56 ;
     RECT  56.704 81.072 56.819 81.096 ;
     RECT  56.704 15.84 57.089 15.864 ;
     RECT  56.704 54.384 57.413 54.408 ;
     RECT  56.704 77.04 57.629 77.16 ;
     RECT  56.704 83.76 58.117 83.784 ;
     RECT  58.117 83.76 58.163 84.6 ;
     RECT  58.237 44.88 58.403 45 ;
     RECT  56.704 47.328 58.403 47.352 ;
     RECT  56.704 51.936 58.403 51.96 ;
     RECT  58.403 44.976 58.405 45 ;
     RECT  58.405 44.976 58.451 45.72 ;
     RECT  56.704 25.152 58.705 25.176 ;
     RECT  58.705 25.152 58.745 25.272 ;
     RECT  58.993 67.248 59.267 67.272 ;
     RECT  59.209 70.08 59.293 70.104 ;
     RECT  58.357 49.2 59.789 49.224 ;
     RECT  58.163 84.576 59.948 84.6 ;
     RECT  57.629 77.04 59.989 77.064 ;
     RECT  59.948 84.288 60.005 84.6 ;
     RECT  60.005 84.288 60.035 84.408 ;
     RECT  56.704 98.352 60.085 98.376 ;
     RECT  56.704 88.896 60.131 88.92 ;
     RECT  58.451 45.696 60.757 45.72 ;
     RECT  60.757 45.696 60.797 46.008 ;
     RECT  60.085 98.352 60.812 99.192 ;
     RECT  59.221 68.64 61.765 68.664 ;
     RECT  56.704 19.248 61.808 19.272 ;
     RECT  58.745 25.248 61.808 25.272 ;
     RECT  56.704 33.024 61.808 33.048 ;
     RECT  60.829 39.312 61.808 39.336 ;
     RECT  56.704 43.008 61.808 43.032 ;
     RECT  60.797 45.984 61.808 46.008 ;
     RECT  60.685 59.184 61.808 59.208 ;
     RECT  56.704 62.976 61.808 63 ;
     RECT  61.765 68.64 61.808 68.712 ;
     RECT  56.704 72.432 61.808 72.456 ;
     RECT  61.381 74.016 61.808 74.04 ;
     RECT  59.989 76.128 61.808 77.064 ;
     RECT  61.525 78.672 61.808 78.696 ;
     RECT  60.035 84.384 61.808 84.408 ;
     RECT  60.812 98.352 61.808 99.912 ;
     RECT  61.808 2.148 61.912 105.852 ;
     RECT  61.912 2.418 62.104 105.582 ;
     RECT  62.104 78.672 62.381 78.696 ;
     RECT  62.104 43.008 62.525 43.272 ;
     RECT  62.104 76.176 62.705 76.296 ;
     RECT  62.104 45.312 62.771 47.352 ;
     RECT  62.771 46.752 62.819 47.352 ;
     RECT  62.525 43.248 62.867 43.272 ;
     RECT  62.819 47.328 62.921 47.352 ;
     RECT  62.104 8.832 63.107 9.672 ;
     RECT  62.104 33.024 63.157 33.048 ;
     RECT  63.157 33.024 63.203 34.824 ;
     RECT  63.107 9.648 63.209 9.672 ;
     RECT  63.203 33.84 63.245 34.824 ;
     RECT  62.104 27.936 63.277 27.96 ;
     RECT  62.104 6.72 63.317 7.272 ;
     RECT  63.277 27.552 63.317 27.96 ;
     RECT  62.104 99.696 63.452 99.72 ;
     RECT  63.245 34.8 63.461 34.824 ;
     RECT  63.452 99.696 63.539 100.2 ;
     RECT  62.104 62.976 63.605 63 ;
     RECT  62.104 19.248 63.637 19.272 ;
     RECT  62.104 84.384 63.637 84.408 ;
     RECT  63.637 84.384 63.677 84.888 ;
     RECT  63.317 6.72 63.721 6.84 ;
     RECT  63.637 101.568 63.721 102.648 ;
     RECT  63.637 19.248 63.74 19.992 ;
     RECT  62.104 25.248 63.781 25.272 ;
     RECT  63.317 27.552 63.781 27.576 ;
     RECT  63.74 19.248 63.827 20.52 ;
     RECT  63.781 25.248 63.827 25.704 ;
     RECT  63.781 26.736 63.827 27.576 ;
     RECT  63.827 26.736 63.868 26.76 ;
     RECT  62.104 15.984 63.884 16.008 ;
     RECT  63.637 11.136 63.925 11.16 ;
     RECT  62.705 76.176 63.932 76.2 ;
     RECT  63.721 6.72 63.965 6.744 ;
     RECT  63.884 15.648 63.971 16.008 ;
     RECT  63.932 75.552 63.973 76.2 ;
     RECT  63.973 74.592 64.019 76.392 ;
     RECT  63.452 96.288 64.076 96.312 ;
     RECT  64.028 105.072 64.115 105.096 ;
     RECT  64.076 95.712 64.163 96.312 ;
     RECT  63.925 11.136 64.22 11.976 ;
     RECT  63.313 3.936 64.268 3.96 ;
     RECT  64.22 10.752 64.307 11.976 ;
     RECT  64.268 3.936 64.309 4.536 ;
     RECT  63.961 2.832 64.355 2.856 ;
     RECT  64.309 3.936 64.355 5.16 ;
     RECT  64.268 88.368 64.355 88.392 ;
     RECT  63.827 19.248 64.357 19.992 ;
     RECT  63.721 101.568 64.361 101.592 ;
     RECT  62.104 68.688 64.364 68.712 ;
     RECT  63.971 15.984 64.403 16.008 ;
     RECT  64.357 19.104 64.403 19.992 ;
     RECT  63.385 56.736 64.405 56.76 ;
     RECT  62.104 59.184 64.451 59.208 ;
     RECT  64.364 68.688 64.451 69.48 ;
     RECT  64.019 76.368 64.46 76.392 ;
     RECT  64.355 5.136 64.505 5.16 ;
     RECT  63.721 102.624 64.505 102.648 ;
     RECT  64.405 67.44 64.537 67.464 ;
     RECT  64.46 76.368 64.547 76.92 ;
     RECT  64.537 67.248 64.577 67.464 ;
     RECT  64.163 96.288 64.577 96.312 ;
     RECT  63.539 100.176 64.577 100.2 ;
     RECT  64.405 56.736 64.652 57.48 ;
     RECT  64.033 55.056 64.739 55.08 ;
     RECT  64.652 56.4 64.739 57.48 ;
     RECT  63.677 84.864 64.757 84.888 ;
     RECT  64.739 57.456 64.973 57.48 ;
     RECT  64.501 78.096 64.973 78.12 ;
     RECT  64.405 63.12 64.979 63.144 ;
     RECT  64.933 64.992 65.017 65.016 ;
     RECT  64.403 19.104 65.069 19.128 ;
     RECT  65.069 18.192 65.153 19.128 ;
     RECT  65.153 19.104 65.225 19.128 ;
     RECT  64.577 67.248 65.261 67.272 ;
     RECT  64.357 17.04 65.269 17.064 ;
     RECT  65.269 17.04 65.315 17.88 ;
     RECT  65.315 17.856 65.356 17.88 ;
     RECT  64.355 3.936 65.405 3.96 ;
     RECT  65.468 37.2 65.509 37.224 ;
     RECT  62.771 45.312 65.509 45.336 ;
     RECT  65.365 46.752 65.509 46.776 ;
     RECT  65.509 37.2 65.555 38.04 ;
     RECT  62.104 39.312 65.555 39.336 ;
     RECT  65.509 45.312 65.555 46.776 ;
     RECT  63.827 25.68 65.585 25.704 ;
     RECT  64.309 86.592 65.585 86.616 ;
     RECT  65.555 38.016 65.621 38.04 ;
     RECT  64.019 74.592 65.621 74.616 ;
     RECT  64.307 11.952 65.657 11.976 ;
     RECT  64.547 76.368 65.729 76.392 ;
     RECT  65.555 45.888 65.909 45.912 ;
     RECT  63.637 104.016 66.197 104.04 ;
     RECT  67.208 2.148 67.312 105.852 ;
     RECT  67.312 2.418 67.504 105.582 ;
     RECT  72.608 2.148 72.712 105.852 ;
     RECT  72.712 2.418 72.904 105.582 ;
     RECT  78.008 2.148 78.112 105.852 ;
     RECT  78.112 2.418 78.304 105.582 ;
     RECT  83.408 2.148 83.512 105.852 ;
     RECT  83.512 2.418 83.704 105.582 ;
     RECT  83.704 29.472 84.913 29.496 ;
     RECT  84.913 54.624 85.345 55.848 ;
     RECT  84.913 82.8 85.345 83.448 ;
     RECT  84.913 87.744 85.345 87.768 ;
     RECT  84.913 103.056 85.345 103.08 ;
     RECT  85.345 4.896 85.453 4.92 ;
     RECT  85.345 9.216 85.453 9.24 ;
     RECT  85.345 21.456 85.453 21.48 ;
     RECT  85.345 24.528 85.453 24.552 ;
     RECT  84.913 29.472 85.453 30.072 ;
     RECT  85.345 33.12 85.453 33.144 ;
     RECT  83.704 39.888 85.453 39.912 ;
     RECT  85.345 41.712 85.453 41.736 ;
     RECT  85.345 42.96 85.453 42.984 ;
     RECT  85.345 46.032 85.453 46.056 ;
     RECT  83.704 51.552 85.453 51.576 ;
     RECT  85.345 54 85.453 55.848 ;
     RECT  85.345 58.896 85.453 58.92 ;
     RECT  85.345 61.344 85.453 61.368 ;
     RECT  84.913 63.792 85.453 63.816 ;
     RECT  85.345 65.664 85.453 65.688 ;
     RECT  85.345 66.864 85.453 66.888 ;
     RECT  84.913 71.76 85.453 71.784 ;
     RECT  85.417 76.704 85.453 76.728 ;
     RECT  85.345 79.776 85.453 79.8 ;
     RECT  85.345 82.224 85.453 83.448 ;
     RECT  85.345 87.12 85.453 88.392 ;
     RECT  84.913 93.264 85.453 93.912 ;
     RECT  84.913 95.088 85.453 95.112 ;
     RECT  84.877 101.232 85.453 101.88 ;
     RECT  85.345 103.056 85.453 103.704 ;
     RECT  85.453 33.12 85.489 39.912 ;
     RECT  85.453 41.088 85.489 47.88 ;
     RECT  85.453 49.104 85.489 49.128 ;
     RECT  85.453 50.304 85.489 83.448 ;
     RECT  85.453 84.672 85.489 88.968 ;
     RECT  85.453 90.816 85.489 95.736 ;
     RECT  85.453 96.912 85.489 98.808 ;
     RECT  85.453 99.984 85.489 103.704 ;
     RECT  85.453 2.448 86.281 31.944 ;
     RECT  85.489 33.12 86.281 47.88 ;
     RECT  85.489 49.104 86.281 103.704 ;
     RECT  85.453 105.504 86.281 105.528 ;
     RECT  86.281 2.448 86.364 105.528 ;
    LAYER M5 ;
     RECT  2.4 2.137 2.52 2.151 ;
     RECT  7.8 2.137 7.92 2.151 ;
     RECT  13.2 2.137 13.32 2.151 ;
     RECT  18.6 2.137 18.72 2.151 ;
     RECT  24 2.137 24.12 2.151 ;
     RECT  29.4 2.137 29.52 2.151 ;
     RECT  34.8 2.137 34.92 2.151 ;
     RECT  40.2 2.137 40.32 2.151 ;
     RECT  45.6 2.137 45.72 2.151 ;
     RECT  51 2.137 51.12 2.151 ;
     RECT  56.4 2.137 56.52 2.151 ;
     RECT  61.8 2.137 61.92 2.151 ;
     RECT  67.2 2.137 67.32 2.151 ;
     RECT  72.6 2.137 72.72 2.151 ;
     RECT  78 2.137 78.12 2.151 ;
     RECT  83.4 2.137 83.52 2.151 ;
     RECT  40.2 2.151 40.512 2.773 ;
     RECT  2.4 2.151 2.712 2.821 ;
     RECT  34.8 2.151 35.112 3.157 ;
     RECT  2.4 2.821 3.672 3.971 ;
     RECT  34.8 3.157 35.88 4.019 ;
     RECT  40.08 2.773 40.512 4.115 ;
     RECT  64.32 2.821 64.344 5.171 ;
     RECT  42.288 3.301 42.312 5.173 ;
     RECT  42.288 5.173 42.744 5.219 ;
     RECT  38.208 3.925 38.232 5.317 ;
     RECT  2.4 3.971 2.712 5.653 ;
     RECT  40.2 4.115 40.512 5.749 ;
     RECT  61.8 2.151 62.112 6.709 ;
     RECT  38.208 5.317 38.28 6.805 ;
     RECT  42.72 5.219 42.744 6.805 ;
     RECT  61.8 6.709 62.952 6.805 ;
     RECT  40.2 5.749 41.4 6.851 ;
     RECT  42.48 6.805 42.744 7.093 ;
     RECT  42.48 7.093 43.368 7.139 ;
     RECT  2.4 5.653 3.576 7.763 ;
     RECT  38.208 6.805 38.376 8.579 ;
     RECT  43.344 7.139 43.368 9.203 ;
     RECT  61.8 6.805 63.672 9.683 ;
     RECT  38.208 8.579 38.232 9.781 ;
     RECT  36.528 8.437 36.552 9.971 ;
     RECT  45.6 2.151 45.912 10.501 ;
     RECT  63.648 9.683 63.672 10.741 ;
     RECT  38.208 9.781 38.376 10.835 ;
     RECT  44.976 10.501 45.912 11.029 ;
     RECT  38.208 10.835 38.28 11.941 ;
     RECT  40.2 6.851 40.512 11.941 ;
     RECT  37.296 11.941 38.28 11.987 ;
     RECT  63.648 10.741 64.296 11.987 ;
     RECT  37.296 11.987 37.32 12.229 ;
     RECT  44.688 11.029 45.912 12.275 ;
     RECT  2.4 7.763 3.528 13.045 ;
     RECT  5.088 11.941 5.112 13.091 ;
     RECT  40.2 11.941 41.304 13.427 ;
     RECT  37.056 12.229 37.32 13.669 ;
     RECT  44.976 12.275 45.912 14.197 ;
     RECT  2.4 13.045 4.056 14.291 ;
     RECT  40.2 13.427 40.632 14.725 ;
     RECT  29.4 2.151 29.712 14.773 ;
     RECT  36.864 13.669 37.32 14.867 ;
     RECT  42.432 13.381 42.456 14.867 ;
     RECT  3.888 14.291 4.056 14.915 ;
     RECT  3.888 14.915 3.96 15.395 ;
     RECT  44.448 14.197 45.912 15.395 ;
     RECT  38.784 13.909 38.808 15.443 ;
     RECT  44.976 15.395 45.912 15.587 ;
     RECT  54.96 13.813 54.984 15.829 ;
     RECT  63.648 11.987 63.96 15.973 ;
     RECT  46.896 12.229 46.92 16.019 ;
     RECT  54.72 15.829 54.984 16.019 ;
     RECT  51 2.151 51.312 16.021 ;
     RECT  53.088 15.781 53.112 16.021 ;
     RECT  40.2 14.725 41.448 16.403 ;
     RECT  45.6 15.587 45.912 16.549 ;
     RECT  63.648 15.973 64.392 17.029 ;
     RECT  54.96 16.019 54.984 17.075 ;
     RECT  63.648 17.029 65.304 17.075 ;
     RECT  42.48 16.645 42.504 17.651 ;
     RECT  45.6 16.549 46.776 17.651 ;
     RECT  3.936 15.395 3.96 17.699 ;
     RECT  65.28 17.075 65.304 17.891 ;
     RECT  48.816 17.125 48.84 18.707 ;
     RECT  2.4 14.291 2.712 18.757 ;
     RECT  63.648 17.075 63.672 19.093 ;
     RECT  65.088 18.181 65.112 19.093 ;
     RECT  63.648 19.093 65.112 19.139 ;
     RECT  47.28 19.045 47.304 19.237 ;
     RECT  41.856 18.181 41.88 19.333 ;
     RECT  41.856 19.333 42.168 19.379 ;
     RECT  51 16.021 53.112 19.379 ;
     RECT  37.296 14.867 37.32 19.427 ;
     RECT  47.28 19.237 48.168 19.763 ;
     RECT  63.648 19.139 64.392 20.003 ;
     RECT  48.144 19.763 48.168 20.533 ;
     RECT  45.6 17.651 45.912 21.013 ;
     RECT  51 19.379 53.016 21.155 ;
     RECT  40.2 16.403 40.512 21.253 ;
     RECT  43.824 20.197 43.848 21.683 ;
     RECT  48.144 20.533 48.696 21.971 ;
     RECT  40.08 21.253 40.512 22.019 ;
     RECT  42.144 19.379 42.168 22.019 ;
     RECT  45.456 21.013 45.912 22.067 ;
     RECT  2.4 18.757 3.624 22.693 ;
     RECT  2.4 22.693 3.72 22.739 ;
     RECT  52.992 21.155 53.016 22.789 ;
     RECT  52.464 22.789 53.016 22.835 ;
     RECT  45.6 22.067 45.912 23.701 ;
     RECT  51 21.155 51.312 23.893 ;
     RECT  3.696 22.739 3.72 23.987 ;
     RECT  45.6 23.701 46.68 24.563 ;
     RECT  50.112 23.893 51.312 25.187 ;
     RECT  40.2 22.019 40.512 25.237 ;
     RECT  38.448 18.565 38.472 25.715 ;
     RECT  53.616 23.317 53.64 25.957 ;
     RECT  53.616 25.957 53.88 26.003 ;
     RECT  45.6 24.563 45.912 26.197 ;
     RECT  3.936 24.709 3.96 26.243 ;
     RECT  2.4 22.739 2.712 26.773 ;
     RECT  45.024 26.197 45.912 26.819 ;
     RECT  63.792 20.003 63.816 27.587 ;
     RECT  51 25.187 51.312 27.733 ;
     RECT  41.904 22.741 41.928 27.971 ;
     RECT  53.856 26.003 53.88 28.115 ;
     RECT  52.464 22.835 52.488 28.501 ;
     RECT  2.4 26.773 3.528 28.933 ;
     RECT  2.4 28.933 4.008 28.979 ;
     RECT  50.832 27.733 51.312 28.979 ;
     RECT  52.464 28.501 52.632 29.123 ;
     RECT  45.6 26.819 45.912 29.605 ;
     RECT  55.248 29.029 55.272 29.797 ;
     RECT  54.816 29.797 55.272 29.843 ;
     RECT  2.4 28.979 2.712 30.181 ;
     RECT  3.984 28.979 4.008 30.181 ;
     RECT  2.4 30.181 4.008 30.275 ;
     RECT  42.336 29.029 42.36 30.563 ;
     RECT  45.6 29.605 46.008 30.611 ;
     RECT  54.816 29.843 54.84 30.661 ;
     RECT  54.624 30.661 54.84 30.803 ;
     RECT  52.608 29.123 52.632 30.899 ;
     RECT  48.144 21.971 48.168 30.949 ;
     RECT  54.72 30.803 54.84 30.949 ;
     RECT  54.72 30.949 54.936 30.995 ;
     RECT  43.344 30.997 43.368 31.907 ;
     RECT  38.352 30.229 38.376 31.909 ;
     RECT  38.208 31.909 38.376 31.955 ;
     RECT  49.824 30.421 49.848 31.955 ;
     RECT  43.536 32.341 43.56 33.013 ;
     RECT  54.912 30.995 54.936 33.059 ;
     RECT  38.208 31.955 38.232 33.299 ;
     RECT  43.536 33.013 43.944 33.397 ;
     RECT  47.28 30.949 48.168 33.539 ;
     RECT  47.904 33.539 48.168 33.683 ;
     RECT  2.4 30.275 3.528 34.213 ;
     RECT  34.8 4.019 35.112 34.453 ;
     RECT  24 2.151 24.312 34.597 ;
     RECT  23.904 34.597 24.312 34.739 ;
     RECT  2.4 34.213 3.672 34.789 ;
     RECT  63.168 33.013 63.192 34.835 ;
     RECT  43.296 33.397 43.944 34.979 ;
     RECT  47.904 33.683 48.12 35.459 ;
     RECT  38.352 34.741 38.376 35.461 ;
     RECT  38.208 35.461 38.376 35.507 ;
     RECT  29.28 14.773 29.712 35.747 ;
     RECT  34.608 34.453 35.112 35.749 ;
     RECT  36.432 34.117 36.456 35.749 ;
     RECT  34.608 35.749 36.456 35.795 ;
     RECT  39.6 25.237 40.512 35.893 ;
     RECT  2.4 34.789 3.72 35.939 ;
     RECT  34.608 35.795 35.592 35.939 ;
     RECT  26.352 34.693 26.376 35.987 ;
     RECT  48.096 35.459 48.12 36.229 ;
     RECT  43.92 34.979 43.944 36.275 ;
     RECT  48.096 36.229 48.696 36.997 ;
     RECT  2.4 35.939 3.672 37.573 ;
     RECT  41.904 35.269 41.928 37.573 ;
     RECT  41.904 37.573 42.888 37.619 ;
     RECT  38.208 35.507 38.232 38.051 ;
     RECT  45.6 30.611 45.912 38.149 ;
     RECT  37.008 38.005 37.032 38.771 ;
     RECT  42.864 37.619 42.888 39.061 ;
     RECT  42.72 39.061 42.888 39.107 ;
     RECT  51 28.979 51.312 39.253 ;
     RECT  61.8 9.683 62.112 39.301 ;
     RECT  65.52 37.189 65.544 39.347 ;
     RECT  48.096 36.997 48.984 39.973 ;
     RECT  47.808 39.973 48.984 40.019 ;
     RECT  44.976 38.149 45.912 40.451 ;
     RECT  42.72 39.107 42.744 40.499 ;
     RECT  39.504 35.893 40.512 41.075 ;
     RECT  47.808 40.019 48.696 41.123 ;
     RECT  50.448 39.253 51.312 41.123 ;
     RECT  2.4 37.573 3.96 41.411 ;
     RECT  2.4 41.411 3.672 41.651 ;
     RECT  51 41.123 51.312 41.749 ;
     RECT  54.24 40.165 54.264 42.179 ;
     RECT  48.672 41.123 48.696 42.181 ;
     RECT  43.44 41.029 43.464 42.419 ;
     RECT  2.4 41.651 2.712 42.757 ;
     RECT  48.672 42.181 49.56 42.997 ;
     RECT  51 41.749 51.432 42.997 ;
     RECT  48.672 42.997 51.432 43.043 ;
     RECT  61.8 39.301 62.856 43.283 ;
     RECT  2.4 42.757 3.672 43.331 ;
     RECT  49.536 43.043 51.432 43.763 ;
     RECT  39.552 41.075 40.512 43.955 ;
     RECT  2.4 43.331 2.712 44.437 ;
     RECT  42.336 43.285 42.36 44.483 ;
     RECT  58.368 44.869 58.392 44.965 ;
     RECT  50.112 43.763 51.432 45.587 ;
     RECT  2.4 44.437 3.432 45.731 ;
     RECT  42.72 44.917 42.744 45.731 ;
     RECT  58.368 44.965 58.44 45.731 ;
     RECT  45.6 40.451 45.912 46.693 ;
     RECT  61.8 43.283 62.76 46.741 ;
     RECT  53.232 45.925 53.256 46.787 ;
     RECT  65.52 45.301 65.544 46.787 ;
     RECT  50.112 45.587 51.312 47.027 ;
     RECT  61.8 46.741 62.808 47.363 ;
     RECT  40.2 43.955 40.512 47.845 ;
     RECT  43.296 47.029 43.32 48.085 ;
     RECT  44.976 46.693 45.912 48.085 ;
     RECT  43.296 48.085 45.912 48.131 ;
     RECT  45.6 48.131 45.912 48.277 ;
     RECT  2.4 45.731 2.712 48.997 ;
     RECT  43.296 48.131 44.184 49.187 ;
     RECT  40.08 47.845 40.512 49.235 ;
     RECT  45.6 48.277 46.776 49.477 ;
     RECT  45.024 49.477 46.776 49.619 ;
     RECT  40.2 49.235 40.512 49.813 ;
     RECT  51 47.027 51.312 50.101 ;
     RECT  43.296 49.187 43.32 50.485 ;
     RECT  43.008 50.485 43.32 50.531 ;
     RECT  2.4 48.997 3.432 50.533 ;
     RECT  40.2 49.813 41.4 50.771 ;
     RECT  50.496 50.101 51.312 51.059 ;
     RECT  53.28 47.221 53.304 51.923 ;
     RECT  58.368 45.731 58.392 51.971 ;
     RECT  45.024 49.619 45.912 52.021 ;
     RECT  44.832 52.021 45.912 52.453 ;
     RECT  43.008 50.531 43.032 52.693 ;
     RECT  44.832 52.453 46.152 52.883 ;
     RECT  43.008 52.693 43.32 53.027 ;
     RECT  45.6 52.883 46.152 53.027 ;
     RECT  47.952 49.333 47.976 53.555 ;
     RECT  2.4 50.533 3.48 54.085 ;
     RECT  45.6 53.027 45.912 54.085 ;
     RECT  43.2 53.027 43.32 54.517 ;
     RECT  51 51.059 51.312 54.517 ;
     RECT  2.4 54.085 3.576 54.661 ;
     RECT  43.2 54.517 43.608 54.997 ;
     RECT  40.2 50.771 40.512 55.237 ;
     RECT  2.4 54.661 3.96 55.667 ;
     RECT  45.6 54.085 46.008 55.765 ;
     RECT  48.288 54.661 48.312 55.955 ;
     RECT  50.784 54.517 51.312 56.531 ;
     RECT  51 56.531 51.312 56.677 ;
     RECT  53.808 54.373 53.832 56.723 ;
     RECT  40.2 55.237 40.632 56.917 ;
     RECT  45.6 55.765 46.056 57.301 ;
     RECT  64.704 55.045 64.728 57.445 ;
     RECT  64.416 57.445 64.728 57.491 ;
     RECT  43.2 54.997 43.896 57.587 ;
     RECT  37.536 54.421 37.56 57.635 ;
     RECT  40.2 56.917 41.064 57.973 ;
     RECT  39.024 57.541 39.048 58.117 ;
     RECT  38.832 58.117 39.048 58.163 ;
     RECT  43.2 57.587 43.608 58.931 ;
     RECT  40.2 57.973 41.4 59.221 ;
     RECT  38.832 58.163 38.856 59.315 ;
     RECT  51 56.677 51.96 59.315 ;
     RECT  40.2 59.221 41.592 59.507 ;
     RECT  45.6 57.301 46.872 59.507 ;
     RECT  45.6 59.507 46.824 60.181 ;
     RECT  43.2 58.931 43.224 60.661 ;
     RECT  45.024 60.181 46.824 60.661 ;
     RECT  44.592 60.661 46.824 60.707 ;
     RECT  45.6 60.707 46.824 60.997 ;
     RECT  45.6 60.997 47.688 61.043 ;
     RECT  44.592 60.707 44.616 61.091 ;
     RECT  51 59.315 51.864 61.235 ;
     RECT  42.96 60.661 43.224 61.619 ;
     RECT  40.2 59.507 40.512 62.389 ;
     RECT  41.568 59.507 41.592 62.389 ;
     RECT  40.2 62.389 41.592 62.435 ;
     RECT  2.4 55.667 3.576 62.629 ;
     RECT  53.136 61.141 53.16 63.011 ;
     RECT  64.416 57.491 64.44 63.109 ;
     RECT  64.416 63.109 64.968 63.155 ;
     RECT  2.4 62.629 3.672 63.205 ;
     RECT  45.6 61.043 45.912 63.205 ;
     RECT  40.2 62.435 41.352 63.781 ;
     RECT  2.4 63.205 3.96 63.875 ;
     RECT  40.08 63.781 41.352 64.021 ;
     RECT  40.08 64.021 41.736 64.067 ;
     RECT  45.36 63.205 45.912 64.115 ;
     RECT  47.664 61.043 47.688 64.357 ;
     RECT  55.344 62.581 55.368 64.451 ;
     RECT  64.944 63.155 64.968 65.027 ;
     RECT  47.328 64.357 47.688 65.603 ;
     RECT  2.4 63.875 3.576 65.893 ;
     RECT  2.4 65.893 3.864 65.939 ;
     RECT  40.08 64.067 40.512 66.133 ;
     RECT  47.664 65.603 47.688 66.133 ;
     RECT  41.712 64.067 41.736 66.515 ;
     RECT  51 61.235 51.576 66.515 ;
     RECT  44.448 64.933 44.472 66.755 ;
     RECT  39.936 66.133 40.512 67.141 ;
     RECT  39.936 67.141 41.016 67.187 ;
     RECT  47.664 66.133 47.88 67.189 ;
     RECT  2.4 65.939 2.712 68.341 ;
     RECT  43.2 61.619 43.224 68.341 ;
     RECT  40.2 67.187 41.016 68.435 ;
     RECT  59.232 67.237 59.256 68.675 ;
     RECT  47.664 67.189 47.976 68.677 ;
     RECT  47.568 68.677 47.976 68.917 ;
     RECT  64.416 67.429 64.44 69.491 ;
     RECT  47.088 68.917 47.976 69.683 ;
     RECT  40.2 68.435 40.512 69.829 ;
     RECT  2.304 68.341 2.712 69.971 ;
     RECT  38.16 68.773 38.184 70.069 ;
     RECT  51 66.515 51.312 70.069 ;
     RECT  2.4 69.971 2.712 70.261 ;
     RECT  3.84 65.939 3.864 70.261 ;
     RECT  47.568 69.683 47.976 70.645 ;
     RECT  40.2 69.829 40.68 71.317 ;
     RECT  46.992 70.645 47.976 71.507 ;
     RECT  50.88 70.069 51.312 71.507 ;
     RECT  47.568 71.507 47.976 72.133 ;
     RECT  61.8 47.363 62.112 72.421 ;
     RECT  59.232 70.069 59.256 72.467 ;
     RECT  42.864 68.341 43.224 72.947 ;
     RECT  34.8 35.939 35.592 72.995 ;
     RECT  29.4 35.747 29.712 73.333 ;
     RECT  47.568 72.133 48.168 73.477 ;
     RECT  44.496 72.901 44.52 73.811 ;
     RECT  61.392 72.421 62.112 74.051 ;
     RECT  38.16 70.069 38.952 74.293 ;
     RECT  40.2 71.317 41.016 74.533 ;
     RECT  40.2 74.533 41.88 74.579 ;
     RECT  49.728 73.429 49.752 74.581 ;
     RECT  51 71.507 51.312 74.581 ;
     RECT  38.16 74.293 39.048 74.627 ;
     RECT  45.6 64.115 45.912 74.629 ;
     RECT  47.328 73.477 48.168 74.629 ;
     RECT  45.6 74.629 48.168 74.723 ;
     RECT  49.728 74.581 51.312 74.771 ;
     RECT  38.832 74.627 39.048 75.107 ;
     RECT  43.2 72.947 43.224 75.781 ;
     RECT  50.112 74.771 51.312 75.971 ;
     RECT  61.488 74.051 62.112 76.357 ;
     RECT  43.2 75.781 43.848 76.403 ;
     RECT  63.984 74.581 64.008 76.403 ;
     RECT  45.6 74.723 46.584 76.451 ;
     RECT  40.2 74.579 40.632 76.499 ;
     RECT  2.4 70.261 3.864 76.643 ;
     RECT  41.856 74.579 41.88 76.739 ;
     RECT  3.84 76.643 3.864 76.979 ;
     RECT  61.008 76.357 62.112 77.075 ;
     RECT  56.4 2.151 56.712 77.125 ;
     RECT  40.2 76.499 40.512 77.461 ;
     RECT  37.584 75.253 37.608 77.555 ;
     RECT  2.4 76.643 2.712 78.037 ;
     RECT  64.512 76.885 64.536 78.131 ;
     RECT  48.144 74.723 48.168 78.613 ;
     RECT  40.2 77.461 41.016 78.659 ;
     RECT  61.536 77.075 62.112 78.707 ;
     RECT  47.568 78.613 48.168 79.189 ;
     RECT  2.4 78.037 3.624 79.235 ;
     RECT  43.2 76.403 43.224 80.341 ;
     RECT  45.6 76.451 45.912 80.869 ;
     RECT  56.4 77.125 56.808 81.107 ;
     RECT  42.72 80.341 43.224 81.635 ;
     RECT  45.6 80.869 46.008 81.635 ;
     RECT  47.28 79.189 48.168 82.115 ;
     RECT  40.2 78.659 40.512 82.261 ;
     RECT  51 75.971 51.312 82.597 ;
     RECT  2.4 79.235 3.432 82.835 ;
     RECT  50.112 82.597 51.312 83.603 ;
     RECT  39.024 75.107 39.048 83.749 ;
     RECT  40.2 82.261 40.632 83.749 ;
     RECT  51 83.603 51.312 83.749 ;
     RECT  39.024 83.749 40.632 83.795 ;
     RECT  54.336 82.021 54.36 83.795 ;
     RECT  39.648 83.795 40.632 84.181 ;
     RECT  45.6 81.635 45.912 84.325 ;
     RECT  39.648 84.181 41.4 84.563 ;
     RECT  58.128 83.749 58.152 84.611 ;
     RECT  2.4 82.835 2.712 86.149 ;
     RECT  3.936 85.477 3.96 86.149 ;
     RECT  44.736 84.325 45.912 86.149 ;
     RECT  2.4 86.149 3.96 86.195 ;
     RECT  44.448 86.149 45.912 86.195 ;
     RECT  43.2 81.635 43.224 86.581 ;
     RECT  40.2 84.563 41.4 86.675 ;
     RECT  42.912 86.581 43.224 87.205 ;
     RECT  44.448 86.195 44.472 87.251 ;
     RECT  37.296 82.501 37.32 87.685 ;
     RECT  37.296 87.685 37.416 87.731 ;
     RECT  42.816 87.205 43.224 87.731 ;
     RECT  64.32 84.853 64.344 88.403 ;
     RECT  47.568 82.115 48.168 88.499 ;
     RECT  2.4 86.195 3.528 88.643 ;
     RECT  45.6 86.195 45.912 88.885 ;
     RECT  47.568 88.499 47.592 88.885 ;
     RECT  51 83.749 52.152 88.885 ;
     RECT  60 76.117 60.024 88.885 ;
     RECT  60 88.885 60.12 88.931 ;
     RECT  37.392 87.731 37.416 88.979 ;
     RECT  51 88.885 52.248 89.939 ;
     RECT  41.856 88.309 41.88 89.989 ;
     RECT  2.4 88.643 2.712 90.037 ;
     RECT  3.936 89.845 3.96 90.037 ;
     RECT  51 89.939 52.152 90.131 ;
     RECT  45.168 88.885 47.592 90.227 ;
     RECT  41.664 89.989 41.88 90.949 ;
     RECT  45.6 90.227 47.592 91.235 ;
     RECT  51 90.131 51.312 91.429 ;
     RECT  53.52 90.565 53.544 91.475 ;
     RECT  41.616 90.949 41.88 91.811 ;
     RECT  50.88 91.429 51.312 91.859 ;
     RECT  2.4 90.037 3.96 92.149 ;
     RECT  2.4 92.149 4.056 92.195 ;
     RECT  43.2 87.731 43.224 92.533 ;
     RECT  45.6 91.235 45.912 92.581 ;
     RECT  45.456 92.581 45.912 93.347 ;
     RECT  28.8 73.333 29.712 93.539 ;
     RECT  38.448 92.005 38.472 93.539 ;
     RECT  43.2 92.533 43.608 93.635 ;
     RECT  47.568 91.235 47.592 93.733 ;
     RECT  41.856 91.811 41.88 93.829 ;
     RECT  3.936 92.195 4.056 93.925 ;
     RECT  2.4 92.195 2.712 94.021 ;
     RECT  3.936 93.925 4.44 94.021 ;
     RECT  47.376 93.733 47.592 94.021 ;
     RECT  51 91.859 51.312 94.021 ;
     RECT  49.056 93.349 49.08 94.067 ;
     RECT  52.992 93.589 53.016 94.691 ;
     RECT  41.856 93.829 42.168 95.219 ;
     RECT  50.496 94.021 51.312 95.699 ;
     RECT  41.856 95.219 41.88 95.701 ;
     RECT  51 95.699 51.312 95.701 ;
     RECT  2.4 94.021 4.44 95.747 ;
     RECT  47.376 94.021 47.928 95.893 ;
     RECT  45.6 93.347 45.912 95.989 ;
     RECT  64.128 95.701 64.152 96.277 ;
     RECT  63.504 96.277 64.152 96.323 ;
     RECT  37.872 93.733 38.136 96.997 ;
     RECT  40.2 86.675 40.512 96.997 ;
     RECT  47.376 95.893 48.168 97.235 ;
     RECT  45.6 95.989 46.056 97.427 ;
     RECT  39.792 96.997 40.512 97.909 ;
     RECT  41.808 95.701 41.88 97.909 ;
     RECT  36.96 96.997 38.136 97.955 ;
     RECT  39.792 97.909 41.88 97.955 ;
     RECT  47.376 97.235 48.12 98.099 ;
     RECT  40.2 97.955 41.88 98.339 ;
     RECT  60.096 88.931 60.12 98.341 ;
     RECT  61.8 78.707 62.112 98.341 ;
     RECT  34.8 72.995 35.112 98.485 ;
     RECT  47.376 98.099 47.4 98.675 ;
     RECT  51 95.701 51.528 98.675 ;
     RECT  45.6 97.427 45.912 99.157 ;
     RECT  2.4 95.747 3.672 99.203 ;
     RECT  60.096 98.341 62.112 99.203 ;
     RECT  44.976 99.157 45.912 99.587 ;
     RECT  60.864 99.203 62.112 99.923 ;
     RECT  43.2 93.635 43.224 100.069 ;
     RECT  63.504 96.323 63.528 100.165 ;
     RECT  63.504 100.165 63.816 100.211 ;
     RECT  34.8 98.485 35.88 100.453 ;
     RECT  34.8 100.453 36.216 100.499 ;
     RECT  33.504 99.685 33.528 100.693 ;
     RECT  33.024 100.693 33.528 100.739 ;
     RECT  40.2 98.339 41.304 100.739 ;
     RECT  37.872 97.955 37.896 100.789 ;
     RECT  42.768 100.069 43.224 100.931 ;
     RECT  63.792 100.211 63.816 101.603 ;
     RECT  36.192 100.499 36.216 101.843 ;
     RECT  37.632 100.789 37.896 102.419 ;
     RECT  40.2 100.739 41.064 102.611 ;
     RECT  63.648 101.989 63.672 102.659 ;
     RECT  33.024 100.739 33.048 102.803 ;
     RECT  37.872 102.419 37.896 103.235 ;
     RECT  47.712 99.061 47.736 103.235 ;
     RECT  34.8 100.499 35.208 104.051 ;
     RECT  64.08 104.005 64.104 105.107 ;
     RECT  33.648 103.381 33.672 105.155 ;
     RECT  2.4 99.203 2.712 105.849 ;
     RECT  7.8 2.151 8.112 105.849 ;
     RECT  13.2 2.151 13.512 105.849 ;
     RECT  18.6 2.151 18.912 105.849 ;
     RECT  24 34.739 24.312 105.849 ;
     RECT  29.4 93.539 29.712 105.849 ;
     RECT  40.2 102.611 40.512 105.849 ;
     RECT  45.6 99.587 45.912 105.849 ;
     RECT  51 98.675 51.312 105.849 ;
     RECT  56.4 81.107 56.712 105.849 ;
     RECT  61.8 99.923 62.112 105.849 ;
     RECT  67.2 2.151 67.512 105.849 ;
     RECT  72.6 2.151 72.912 105.849 ;
     RECT  78 2.151 78.312 105.849 ;
     RECT  83.4 2.151 83.712 105.849 ;
     RECT  2.4 105.849 2.52 105.863 ;
     RECT  7.8 105.849 7.92 105.863 ;
     RECT  13.2 105.849 13.32 105.863 ;
     RECT  18.6 105.849 18.72 105.863 ;
     RECT  24 105.849 24.12 105.863 ;
     RECT  29.4 105.849 29.52 105.863 ;
     RECT  34.8 104.051 35.112 105.863 ;
     RECT  40.2 105.849 40.32 105.863 ;
     RECT  45.6 105.849 45.72 105.863 ;
     RECT  51 105.849 51.12 105.863 ;
     RECT  56.4 105.849 56.52 105.863 ;
     RECT  61.8 105.849 61.92 105.863 ;
     RECT  67.2 105.849 67.32 105.863 ;
     RECT  72.6 105.849 72.72 105.863 ;
     RECT  78 105.849 78.12 105.863 ;
     RECT  83.4 105.849 83.52 105.863 ;
     RECT  30.864 105.781 30.888 106.549 ;
     RECT  30.768 106.549 30.888 106.691 ;
     RECT  30.864 106.691 30.888 107.845 ;
     RECT  30.768 107.845 30.888 107.891 ;
     RECT  30.768 107.891 30.792 107.984 ;
     RECT  35.088 105.863 35.112 107.984 ;
     RECT  43.2 100.931 43.224 107.984 ;
     RECT  50.736 107.845 50.76 107.984 ;
     RECT  56.688 107.173 56.712 107.984 ;
  END
END ot_s81hd_lsc_t11
END LIBRARY
